VERSION 5.8 ;
BUSBITCHARS "[]" ;
DIVIDERCHAR "/" ;
UNITS
    DATABASE MICRONS 1000 ;
END UNITS

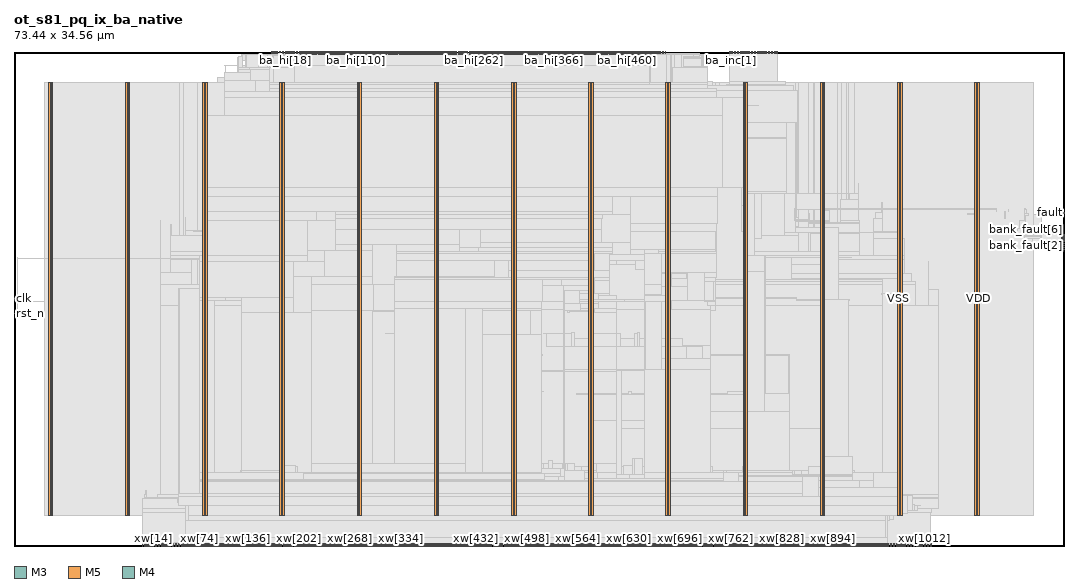
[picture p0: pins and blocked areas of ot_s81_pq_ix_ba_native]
MACRO ot_s81_pq_ix_ba_native
  FOREIGN ot_s81_pq_ix_ba_native 0 0 ;
  CLASS BLOCK ;
  SIZE 73.44 BY 34.56 ;
  PIN ba_hi[0]
    DIRECTION OUTPUT ;
    USE SIGNAL ;
    PORT
      LAYER M3 ;
        RECT  18 34.416 18.018 34.56 ;
    END
  END ba_hi[0]
  PIN ba_hi[100]
    DIRECTION OUTPUT ;
    USE SIGNAL ;
    PORT
      LAYER M3 ;
        RECT  23.4 34.416 23.418 34.56 ;
    END
  END ba_hi[100]
  PIN ba_hi[101]
    DIRECTION OUTPUT ;
    USE SIGNAL ;
    PORT
      LAYER M5 ;
        RECT  24.816 34.368 24.84 34.56 ;
    END
  END ba_hi[101]
  PIN ba_hi[102]
    DIRECTION OUTPUT ;
    USE SIGNAL ;
    PORT
      LAYER M3 ;
        RECT  23.508 34.416 23.526 34.56 ;
    END
  END ba_hi[102]
  PIN ba_hi[103]
    DIRECTION OUTPUT ;
    USE SIGNAL ;
    PORT
      LAYER M5 ;
        RECT  24.912 34.368 24.936 34.56 ;
    END
  END ba_hi[103]
  PIN ba_hi[104]
    DIRECTION OUTPUT ;
    USE SIGNAL ;
    PORT
      LAYER M3 ;
        RECT  23.616 34.416 23.634 34.56 ;
    END
  END ba_hi[104]
  PIN ba_hi[105]
    DIRECTION OUTPUT ;
    USE SIGNAL ;
    PORT
      LAYER M5 ;
        RECT  25.008 34.368 25.032 34.56 ;
    END
  END ba_hi[105]
  PIN ba_hi[106]
    DIRECTION OUTPUT ;
    USE SIGNAL ;
    PORT
      LAYER M3 ;
        RECT  23.724 34.416 23.742 34.56 ;
    END
  END ba_hi[106]
  PIN ba_hi[107]
    DIRECTION OUTPUT ;
    USE SIGNAL ;
    PORT
      LAYER M5 ;
        RECT  25.104 34.368 25.128 34.56 ;
    END
  END ba_hi[107]
  PIN ba_hi[108]
    DIRECTION OUTPUT ;
    USE SIGNAL ;
    PORT
      LAYER M3 ;
        RECT  23.832 34.416 23.85 34.56 ;
    END
  END ba_hi[108]
  PIN ba_hi[109]
    DIRECTION OUTPUT ;
    USE SIGNAL ;
    PORT
      LAYER M5 ;
        RECT  25.2 34.368 25.224 34.56 ;
    END
  END ba_hi[109]
  PIN ba_hi[10]
    DIRECTION OUTPUT ;
    USE SIGNAL ;
    PORT
      LAYER M3 ;
        RECT  18.54 34.416 18.558 34.56 ;
    END
  END ba_hi[10]
  PIN ba_hi[110]
    DIRECTION OUTPUT ;
    USE SIGNAL ;
    PORT
      LAYER M3 ;
        RECT  23.94 34.416 23.958 34.56 ;
    END
  END ba_hi[110]
  PIN ba_hi[111]
    DIRECTION OUTPUT ;
    USE SIGNAL ;
    PORT
      LAYER M5 ;
        RECT  25.296 34.368 25.32 34.56 ;
    END
  END ba_hi[111]
  PIN ba_hi[112]
    DIRECTION OUTPUT ;
    USE SIGNAL ;
    PORT
      LAYER M3 ;
        RECT  24.048 34.416 24.066 34.56 ;
    END
  END ba_hi[112]
  PIN ba_hi[113]
    DIRECTION OUTPUT ;
    USE SIGNAL ;
    PORT
      LAYER M5 ;
        RECT  25.392 34.368 25.416 34.56 ;
    END
  END ba_hi[113]
  PIN ba_hi[114]
    DIRECTION OUTPUT ;
    USE SIGNAL ;
    PORT
      LAYER M3 ;
        RECT  24.156 34.416 24.174 34.56 ;
    END
  END ba_hi[114]
  PIN ba_hi[115]
    DIRECTION OUTPUT ;
    USE SIGNAL ;
    PORT
      LAYER M5 ;
        RECT  25.488 34.368 25.512 34.56 ;
    END
  END ba_hi[115]
  PIN ba_hi[116]
    DIRECTION OUTPUT ;
    USE SIGNAL ;
    PORT
      LAYER M3 ;
        RECT  24.264 34.416 24.282 34.56 ;
    END
  END ba_hi[116]
  PIN ba_hi[117]
    DIRECTION OUTPUT ;
    USE SIGNAL ;
    PORT
      LAYER M5 ;
        RECT  25.584 34.368 25.608 34.56 ;
    END
  END ba_hi[117]
  PIN ba_hi[118]
    DIRECTION OUTPUT ;
    USE SIGNAL ;
    PORT
      LAYER M3 ;
        RECT  24.372 34.416 24.39 34.56 ;
    END
  END ba_hi[118]
  PIN ba_hi[119]
    DIRECTION OUTPUT ;
    USE SIGNAL ;
    PORT
      LAYER M5 ;
        RECT  25.68 34.368 25.704 34.56 ;
    END
  END ba_hi[119]
  PIN ba_hi[11]
    DIRECTION OUTPUT ;
    USE SIGNAL ;
    PORT
      LAYER M5 ;
        RECT  20.496 34.368 20.52 34.56 ;
    END
  END ba_hi[11]
  PIN ba_hi[120]
    DIRECTION OUTPUT ;
    USE SIGNAL ;
    PORT
      LAYER M3 ;
        RECT  24.48 34.416 24.498 34.56 ;
    END
  END ba_hi[120]
  PIN ba_hi[121]
    DIRECTION OUTPUT ;
    USE SIGNAL ;
    PORT
      LAYER M5 ;
        RECT  25.776 34.368 25.8 34.56 ;
    END
  END ba_hi[121]
  PIN ba_hi[122]
    DIRECTION OUTPUT ;
    USE SIGNAL ;
    PORT
      LAYER M3 ;
        RECT  24.588 34.416 24.606 34.56 ;
    END
  END ba_hi[122]
  PIN ba_hi[123]
    DIRECTION OUTPUT ;
    USE SIGNAL ;
    PORT
      LAYER M5 ;
        RECT  25.872 34.368 25.896 34.56 ;
    END
  END ba_hi[123]
  PIN ba_hi[124]
    DIRECTION OUTPUT ;
    USE SIGNAL ;
    PORT
      LAYER M3 ;
        RECT  24.696 34.416 24.714 34.56 ;
    END
  END ba_hi[124]
  PIN ba_hi[125]
    DIRECTION OUTPUT ;
    USE SIGNAL ;
    PORT
      LAYER M5 ;
        RECT  25.968 34.368 25.992 34.56 ;
    END
  END ba_hi[125]
  PIN ba_hi[126]
    DIRECTION OUTPUT ;
    USE SIGNAL ;
    PORT
      LAYER M3 ;
        RECT  24.804 34.416 24.822 34.56 ;
    END
  END ba_hi[126]
  PIN ba_hi[127]
    DIRECTION OUTPUT ;
    USE SIGNAL ;
    PORT
      LAYER M5 ;
        RECT  26.064 34.368 26.088 34.56 ;
    END
  END ba_hi[127]
  PIN ba_hi[128]
    DIRECTION OUTPUT ;
    USE SIGNAL ;
    PORT
      LAYER M3 ;
        RECT  24.912 34.416 24.93 34.56 ;
    END
  END ba_hi[128]
  PIN ba_hi[129]
    DIRECTION OUTPUT ;
    USE SIGNAL ;
    PORT
      LAYER M5 ;
        RECT  26.16 34.368 26.184 34.56 ;
    END
  END ba_hi[129]
  PIN ba_hi[12]
    DIRECTION OUTPUT ;
    USE SIGNAL ;
    PORT
      LAYER M3 ;
        RECT  18.648 34.416 18.666 34.56 ;
    END
  END ba_hi[12]
  PIN ba_hi[130]
    DIRECTION OUTPUT ;
    USE SIGNAL ;
    PORT
      LAYER M3 ;
        RECT  25.02 34.416 25.038 34.56 ;
    END
  END ba_hi[130]
  PIN ba_hi[131]
    DIRECTION OUTPUT ;
    USE SIGNAL ;
    PORT
      LAYER M5 ;
        RECT  26.256 34.368 26.28 34.56 ;
    END
  END ba_hi[131]
  PIN ba_hi[132]
    DIRECTION OUTPUT ;
    USE SIGNAL ;
    PORT
      LAYER M3 ;
        RECT  25.128 34.416 25.146 34.56 ;
    END
  END ba_hi[132]
  PIN ba_hi[133]
    DIRECTION OUTPUT ;
    USE SIGNAL ;
    PORT
      LAYER M5 ;
        RECT  26.352 34.368 26.376 34.56 ;
    END
  END ba_hi[133]
  PIN ba_hi[134]
    DIRECTION OUTPUT ;
    USE SIGNAL ;
    PORT
      LAYER M3 ;
        RECT  25.236 34.416 25.254 34.56 ;
    END
  END ba_hi[134]
  PIN ba_hi[135]
    DIRECTION OUTPUT ;
    USE SIGNAL ;
    PORT
      LAYER M5 ;
        RECT  26.448 34.368 26.472 34.56 ;
    END
  END ba_hi[135]
  PIN ba_hi[136]
    DIRECTION OUTPUT ;
    USE SIGNAL ;
    PORT
      LAYER M3 ;
        RECT  25.344 34.416 25.362 34.56 ;
    END
  END ba_hi[136]
  PIN ba_hi[137]
    DIRECTION OUTPUT ;
    USE SIGNAL ;
    PORT
      LAYER M5 ;
        RECT  26.544 34.368 26.568 34.56 ;
    END
  END ba_hi[137]
  PIN ba_hi[138]
    DIRECTION OUTPUT ;
    USE SIGNAL ;
    PORT
      LAYER M3 ;
        RECT  25.452 34.416 25.47 34.56 ;
    END
  END ba_hi[138]
  PIN ba_hi[139]
    DIRECTION OUTPUT ;
    USE SIGNAL ;
    PORT
      LAYER M5 ;
        RECT  26.64 34.368 26.664 34.56 ;
    END
  END ba_hi[139]
  PIN ba_hi[13]
    DIRECTION OUTPUT ;
    USE SIGNAL ;
    PORT
      LAYER M5 ;
        RECT  20.592 34.368 20.616 34.56 ;
    END
  END ba_hi[13]
  PIN ba_hi[140]
    DIRECTION OUTPUT ;
    USE SIGNAL ;
    PORT
      LAYER M3 ;
        RECT  25.56 34.416 25.578 34.56 ;
    END
  END ba_hi[140]
  PIN ba_hi[141]
    DIRECTION OUTPUT ;
    USE SIGNAL ;
    PORT
      LAYER M5 ;
        RECT  26.736 34.368 26.76 34.56 ;
    END
  END ba_hi[141]
  PIN ba_hi[142]
    DIRECTION OUTPUT ;
    USE SIGNAL ;
    PORT
      LAYER M3 ;
        RECT  25.668 34.416 25.686 34.56 ;
    END
  END ba_hi[142]
  PIN ba_hi[143]
    DIRECTION OUTPUT ;
    USE SIGNAL ;
    PORT
      LAYER M5 ;
        RECT  26.832 34.368 26.856 34.56 ;
    END
  END ba_hi[143]
  PIN ba_hi[144]
    DIRECTION OUTPUT ;
    USE SIGNAL ;
    PORT
      LAYER M3 ;
        RECT  25.776 34.416 25.794 34.56 ;
    END
  END ba_hi[144]
  PIN ba_hi[145]
    DIRECTION OUTPUT ;
    USE SIGNAL ;
    PORT
      LAYER M5 ;
        RECT  26.928 34.368 26.952 34.56 ;
    END
  END ba_hi[145]
  PIN ba_hi[146]
    DIRECTION OUTPUT ;
    USE SIGNAL ;
    PORT
      LAYER M3 ;
        RECT  25.884 34.416 25.902 34.56 ;
    END
  END ba_hi[146]
  PIN ba_hi[147]
    DIRECTION OUTPUT ;
    USE SIGNAL ;
    PORT
      LAYER M5 ;
        RECT  27.024 34.368 27.048 34.56 ;
    END
  END ba_hi[147]
  PIN ba_hi[148]
    DIRECTION OUTPUT ;
    USE SIGNAL ;
    PORT
      LAYER M3 ;
        RECT  25.992 34.416 26.01 34.56 ;
    END
  END ba_hi[148]
  PIN ba_hi[149]
    DIRECTION OUTPUT ;
    USE SIGNAL ;
    PORT
      LAYER M5 ;
        RECT  27.12 34.368 27.144 34.56 ;
    END
  END ba_hi[149]
  PIN ba_hi[14]
    DIRECTION OUTPUT ;
    USE SIGNAL ;
    PORT
      LAYER M3 ;
        RECT  18.756 34.416 18.774 34.56 ;
    END
  END ba_hi[14]
  PIN ba_hi[150]
    DIRECTION OUTPUT ;
    USE SIGNAL ;
    PORT
      LAYER M3 ;
        RECT  26.1 34.416 26.118 34.56 ;
    END
  END ba_hi[150]
  PIN ba_hi[151]
    DIRECTION OUTPUT ;
    USE SIGNAL ;
    PORT
      LAYER M5 ;
        RECT  27.216 34.368 27.24 34.56 ;
    END
  END ba_hi[151]
  PIN ba_hi[152]
    DIRECTION OUTPUT ;
    USE SIGNAL ;
    PORT
      LAYER M3 ;
        RECT  26.208 34.416 26.226 34.56 ;
    END
  END ba_hi[152]
  PIN ba_hi[153]
    DIRECTION OUTPUT ;
    USE SIGNAL ;
    PORT
      LAYER M5 ;
        RECT  27.312 34.368 27.336 34.56 ;
    END
  END ba_hi[153]
  PIN ba_hi[154]
    DIRECTION OUTPUT ;
    USE SIGNAL ;
    PORT
      LAYER M3 ;
        RECT  26.316 34.416 26.334 34.56 ;
    END
  END ba_hi[154]
  PIN ba_hi[155]
    DIRECTION OUTPUT ;
    USE SIGNAL ;
    PORT
      LAYER M5 ;
        RECT  27.408 34.368 27.432 34.56 ;
    END
  END ba_hi[155]
  PIN ba_hi[156]
    DIRECTION OUTPUT ;
    USE SIGNAL ;
    PORT
      LAYER M3 ;
        RECT  26.424 34.416 26.442 34.56 ;
    END
  END ba_hi[156]
  PIN ba_hi[157]
    DIRECTION OUTPUT ;
    USE SIGNAL ;
    PORT
      LAYER M5 ;
        RECT  27.504 34.368 27.528 34.56 ;
    END
  END ba_hi[157]
  PIN ba_hi[158]
    DIRECTION OUTPUT ;
    USE SIGNAL ;
    PORT
      LAYER M3 ;
        RECT  26.532 34.416 26.55 34.56 ;
    END
  END ba_hi[158]
  PIN ba_hi[159]
    DIRECTION OUTPUT ;
    USE SIGNAL ;
    PORT
      LAYER M5 ;
        RECT  27.6 34.368 27.624 34.56 ;
    END
  END ba_hi[159]
  PIN ba_hi[15]
    DIRECTION OUTPUT ;
    USE SIGNAL ;
    PORT
      LAYER M5 ;
        RECT  20.688 34.368 20.712 34.56 ;
    END
  END ba_hi[15]
  PIN ba_hi[160]
    DIRECTION OUTPUT ;
    USE SIGNAL ;
    PORT
      LAYER M3 ;
        RECT  26.64 34.416 26.658 34.56 ;
    END
  END ba_hi[160]
  PIN ba_hi[161]
    DIRECTION OUTPUT ;
    USE SIGNAL ;
    PORT
      LAYER M5 ;
        RECT  27.696 34.368 27.72 34.56 ;
    END
  END ba_hi[161]
  PIN ba_hi[162]
    DIRECTION OUTPUT ;
    USE SIGNAL ;
    PORT
      LAYER M3 ;
        RECT  26.748 34.416 26.766 34.56 ;
    END
  END ba_hi[162]
  PIN ba_hi[163]
    DIRECTION OUTPUT ;
    USE SIGNAL ;
    PORT
      LAYER M5 ;
        RECT  27.792 34.368 27.816 34.56 ;
    END
  END ba_hi[163]
  PIN ba_hi[164]
    DIRECTION OUTPUT ;
    USE SIGNAL ;
    PORT
      LAYER M3 ;
        RECT  26.856 34.416 26.874 34.56 ;
    END
  END ba_hi[164]
  PIN ba_hi[165]
    DIRECTION OUTPUT ;
    USE SIGNAL ;
    PORT
      LAYER M5 ;
        RECT  27.888 34.368 27.912 34.56 ;
    END
  END ba_hi[165]
  PIN ba_hi[166]
    DIRECTION OUTPUT ;
    USE SIGNAL ;
    PORT
      LAYER M3 ;
        RECT  26.964 34.416 26.982 34.56 ;
    END
  END ba_hi[166]
  PIN ba_hi[167]
    DIRECTION OUTPUT ;
    USE SIGNAL ;
    PORT
      LAYER M5 ;
        RECT  27.984 34.368 28.008 34.56 ;
    END
  END ba_hi[167]
  PIN ba_hi[168]
    DIRECTION OUTPUT ;
    USE SIGNAL ;
    PORT
      LAYER M3 ;
        RECT  27.072 34.416 27.09 34.56 ;
    END
  END ba_hi[168]
  PIN ba_hi[169]
    DIRECTION OUTPUT ;
    USE SIGNAL ;
    PORT
      LAYER M5 ;
        RECT  28.08 34.368 28.104 34.56 ;
    END
  END ba_hi[169]
  PIN ba_hi[16]
    DIRECTION OUTPUT ;
    USE SIGNAL ;
    PORT
      LAYER M3 ;
        RECT  18.864 34.416 18.882 34.56 ;
    END
  END ba_hi[16]
  PIN ba_hi[170]
    DIRECTION OUTPUT ;
    USE SIGNAL ;
    PORT
      LAYER M3 ;
        RECT  27.18 34.416 27.198 34.56 ;
    END
  END ba_hi[170]
  PIN ba_hi[171]
    DIRECTION OUTPUT ;
    USE SIGNAL ;
    PORT
      LAYER M5 ;
        RECT  28.176 34.368 28.2 34.56 ;
    END
  END ba_hi[171]
  PIN ba_hi[172]
    DIRECTION OUTPUT ;
    USE SIGNAL ;
    PORT
      LAYER M3 ;
        RECT  27.288 34.416 27.306 34.56 ;
    END
  END ba_hi[172]
  PIN ba_hi[173]
    DIRECTION OUTPUT ;
    USE SIGNAL ;
    PORT
      LAYER M5 ;
        RECT  28.272 34.368 28.296 34.56 ;
    END
  END ba_hi[173]
  PIN ba_hi[174]
    DIRECTION OUTPUT ;
    USE SIGNAL ;
    PORT
      LAYER M3 ;
        RECT  27.396 34.416 27.414 34.56 ;
    END
  END ba_hi[174]
  PIN ba_hi[175]
    DIRECTION OUTPUT ;
    USE SIGNAL ;
    PORT
      LAYER M5 ;
        RECT  28.368 34.368 28.392 34.56 ;
    END
  END ba_hi[175]
  PIN ba_hi[176]
    DIRECTION OUTPUT ;
    USE SIGNAL ;
    PORT
      LAYER M3 ;
        RECT  27.504 34.416 27.522 34.56 ;
    END
  END ba_hi[176]
  PIN ba_hi[177]
    DIRECTION OUTPUT ;
    USE SIGNAL ;
    PORT
      LAYER M5 ;
        RECT  28.464 34.368 28.488 34.56 ;
    END
  END ba_hi[177]
  PIN ba_hi[178]
    DIRECTION OUTPUT ;
    USE SIGNAL ;
    PORT
      LAYER M3 ;
        RECT  27.612 34.416 27.63 34.56 ;
    END
  END ba_hi[178]
  PIN ba_hi[179]
    DIRECTION OUTPUT ;
    USE SIGNAL ;
    PORT
      LAYER M5 ;
        RECT  28.56 34.368 28.584 34.56 ;
    END
  END ba_hi[179]
  PIN ba_hi[17]
    DIRECTION OUTPUT ;
    USE SIGNAL ;
    PORT
      LAYER M5 ;
        RECT  20.784 34.368 20.808 34.56 ;
    END
  END ba_hi[17]
  PIN ba_hi[180]
    DIRECTION OUTPUT ;
    USE SIGNAL ;
    PORT
      LAYER M3 ;
        RECT  27.72 34.416 27.738 34.56 ;
    END
  END ba_hi[180]
  PIN ba_hi[181]
    DIRECTION OUTPUT ;
    USE SIGNAL ;
    PORT
      LAYER M5 ;
        RECT  28.656 34.368 28.68 34.56 ;
    END
  END ba_hi[181]
  PIN ba_hi[182]
    DIRECTION OUTPUT ;
    USE SIGNAL ;
    PORT
      LAYER M3 ;
        RECT  27.828 34.416 27.846 34.56 ;
    END
  END ba_hi[182]
  PIN ba_hi[183]
    DIRECTION OUTPUT ;
    USE SIGNAL ;
    PORT
      LAYER M5 ;
        RECT  28.752 34.368 28.776 34.56 ;
    END
  END ba_hi[183]
  PIN ba_hi[184]
    DIRECTION OUTPUT ;
    USE SIGNAL ;
    PORT
      LAYER M3 ;
        RECT  27.936 34.416 27.954 34.56 ;
    END
  END ba_hi[184]
  PIN ba_hi[185]
    DIRECTION OUTPUT ;
    USE SIGNAL ;
    PORT
      LAYER M5 ;
        RECT  28.848 34.368 28.872 34.56 ;
    END
  END ba_hi[185]
  PIN ba_hi[186]
    DIRECTION OUTPUT ;
    USE SIGNAL ;
    PORT
      LAYER M3 ;
        RECT  28.044 34.416 28.062 34.56 ;
    END
  END ba_hi[186]
  PIN ba_hi[187]
    DIRECTION OUTPUT ;
    USE SIGNAL ;
    PORT
      LAYER M5 ;
        RECT  28.944 34.368 28.968 34.56 ;
    END
  END ba_hi[187]
  PIN ba_hi[188]
    DIRECTION OUTPUT ;
    USE SIGNAL ;
    PORT
      LAYER M3 ;
        RECT  28.152 34.416 28.17 34.56 ;
    END
  END ba_hi[188]
  PIN ba_hi[189]
    DIRECTION OUTPUT ;
    USE SIGNAL ;
    PORT
      LAYER M5 ;
        RECT  29.04 34.368 29.064 34.56 ;
    END
  END ba_hi[189]
  PIN ba_hi[18]
    DIRECTION OUTPUT ;
    USE SIGNAL ;
    PORT
      LAYER M3 ;
        RECT  18.972 34.416 18.99 34.56 ;
    END
  END ba_hi[18]
  PIN ba_hi[190]
    DIRECTION OUTPUT ;
    USE SIGNAL ;
    PORT
      LAYER M3 ;
        RECT  28.26 34.416 28.278 34.56 ;
    END
  END ba_hi[190]
  PIN ba_hi[191]
    DIRECTION OUTPUT ;
    USE SIGNAL ;
    PORT
      LAYER M5 ;
        RECT  29.136 34.368 29.16 34.56 ;
    END
  END ba_hi[191]
  PIN ba_hi[192]
    DIRECTION OUTPUT ;
    USE SIGNAL ;
    PORT
      LAYER M3 ;
        RECT  28.368 34.416 28.386 34.56 ;
    END
  END ba_hi[192]
  PIN ba_hi[193]
    DIRECTION OUTPUT ;
    USE SIGNAL ;
    PORT
      LAYER M5 ;
        RECT  29.232 34.368 29.256 34.56 ;
    END
  END ba_hi[193]
  PIN ba_hi[194]
    DIRECTION OUTPUT ;
    USE SIGNAL ;
    PORT
      LAYER M3 ;
        RECT  28.476 34.416 28.494 34.56 ;
    END
  END ba_hi[194]
  PIN ba_hi[195]
    DIRECTION OUTPUT ;
    USE SIGNAL ;
    PORT
      LAYER M5 ;
        RECT  29.328 34.368 29.352 34.56 ;
    END
  END ba_hi[195]
  PIN ba_hi[196]
    DIRECTION OUTPUT ;
    USE SIGNAL ;
    PORT
      LAYER M3 ;
        RECT  28.584 34.416 28.602 34.56 ;
    END
  END ba_hi[196]
  PIN ba_hi[197]
    DIRECTION OUTPUT ;
    USE SIGNAL ;
    PORT
      LAYER M5 ;
        RECT  29.424 34.368 29.448 34.56 ;
    END
  END ba_hi[197]
  PIN ba_hi[198]
    DIRECTION OUTPUT ;
    USE SIGNAL ;
    PORT
      LAYER M3 ;
        RECT  28.692 34.416 28.71 34.56 ;
    END
  END ba_hi[198]
  PIN ba_hi[199]
    DIRECTION OUTPUT ;
    USE SIGNAL ;
    PORT
      LAYER M5 ;
        RECT  29.52 34.368 29.544 34.56 ;
    END
  END ba_hi[199]
  PIN ba_hi[19]
    DIRECTION OUTPUT ;
    USE SIGNAL ;
    PORT
      LAYER M5 ;
        RECT  20.88 34.368 20.904 34.56 ;
    END
  END ba_hi[19]
  PIN ba_hi[1]
    DIRECTION OUTPUT ;
    USE SIGNAL ;
    PORT
      LAYER M5 ;
        RECT  20.016 34.368 20.04 34.56 ;
    END
  END ba_hi[1]
  PIN ba_hi[200]
    DIRECTION OUTPUT ;
    USE SIGNAL ;
    PORT
      LAYER M3 ;
        RECT  28.8 34.416 28.818 34.56 ;
    END
  END ba_hi[200]
  PIN ba_hi[201]
    DIRECTION OUTPUT ;
    USE SIGNAL ;
    PORT
      LAYER M5 ;
        RECT  29.616 34.368 29.64 34.56 ;
    END
  END ba_hi[201]
  PIN ba_hi[202]
    DIRECTION OUTPUT ;
    USE SIGNAL ;
    PORT
      LAYER M3 ;
        RECT  28.908 34.416 28.926 34.56 ;
    END
  END ba_hi[202]
  PIN ba_hi[203]
    DIRECTION OUTPUT ;
    USE SIGNAL ;
    PORT
      LAYER M5 ;
        RECT  29.712 34.368 29.736 34.56 ;
    END
  END ba_hi[203]
  PIN ba_hi[204]
    DIRECTION OUTPUT ;
    USE SIGNAL ;
    PORT
      LAYER M3 ;
        RECT  29.016 34.416 29.034 34.56 ;
    END
  END ba_hi[204]
  PIN ba_hi[205]
    DIRECTION OUTPUT ;
    USE SIGNAL ;
    PORT
      LAYER M5 ;
        RECT  29.808 34.368 29.832 34.56 ;
    END
  END ba_hi[205]
  PIN ba_hi[206]
    DIRECTION OUTPUT ;
    USE SIGNAL ;
    PORT
      LAYER M3 ;
        RECT  29.124 34.416 29.142 34.56 ;
    END
  END ba_hi[206]
  PIN ba_hi[207]
    DIRECTION OUTPUT ;
    USE SIGNAL ;
    PORT
      LAYER M5 ;
        RECT  29.904 34.368 29.928 34.56 ;
    END
  END ba_hi[207]
  PIN ba_hi[208]
    DIRECTION OUTPUT ;
    USE SIGNAL ;
    PORT
      LAYER M3 ;
        RECT  29.232 34.416 29.25 34.56 ;
    END
  END ba_hi[208]
  PIN ba_hi[209]
    DIRECTION OUTPUT ;
    USE SIGNAL ;
    PORT
      LAYER M5 ;
        RECT  30 34.368 30.024 34.56 ;
    END
  END ba_hi[209]
  PIN ba_hi[20]
    DIRECTION OUTPUT ;
    USE SIGNAL ;
    PORT
      LAYER M3 ;
        RECT  19.08 34.416 19.098 34.56 ;
    END
  END ba_hi[20]
  PIN ba_hi[210]
    DIRECTION OUTPUT ;
    USE SIGNAL ;
    PORT
      LAYER M3 ;
        RECT  29.34 34.416 29.358 34.56 ;
    END
  END ba_hi[210]
  PIN ba_hi[211]
    DIRECTION OUTPUT ;
    USE SIGNAL ;
    PORT
      LAYER M5 ;
        RECT  30.096 34.368 30.12 34.56 ;
    END
  END ba_hi[211]
  PIN ba_hi[212]
    DIRECTION OUTPUT ;
    USE SIGNAL ;
    PORT
      LAYER M3 ;
        RECT  29.448 34.416 29.466 34.56 ;
    END
  END ba_hi[212]
  PIN ba_hi[213]
    DIRECTION OUTPUT ;
    USE SIGNAL ;
    PORT
      LAYER M5 ;
        RECT  30.192 34.368 30.216 34.56 ;
    END
  END ba_hi[213]
  PIN ba_hi[214]
    DIRECTION OUTPUT ;
    USE SIGNAL ;
    PORT
      LAYER M3 ;
        RECT  29.556 34.416 29.574 34.56 ;
    END
  END ba_hi[214]
  PIN ba_hi[215]
    DIRECTION OUTPUT ;
    USE SIGNAL ;
    PORT
      LAYER M5 ;
        RECT  30.288 34.368 30.312 34.56 ;
    END
  END ba_hi[215]
  PIN ba_hi[216]
    DIRECTION OUTPUT ;
    USE SIGNAL ;
    PORT
      LAYER M3 ;
        RECT  29.664 34.416 29.682 34.56 ;
    END
  END ba_hi[216]
  PIN ba_hi[217]
    DIRECTION OUTPUT ;
    USE SIGNAL ;
    PORT
      LAYER M5 ;
        RECT  30.384 34.368 30.408 34.56 ;
    END
  END ba_hi[217]
  PIN ba_hi[218]
    DIRECTION OUTPUT ;
    USE SIGNAL ;
    PORT
      LAYER M3 ;
        RECT  29.772 34.416 29.79 34.56 ;
    END
  END ba_hi[218]
  PIN ba_hi[219]
    DIRECTION OUTPUT ;
    USE SIGNAL ;
    PORT
      LAYER M5 ;
        RECT  30.48 34.368 30.504 34.56 ;
    END
  END ba_hi[219]
  PIN ba_hi[21]
    DIRECTION OUTPUT ;
    USE SIGNAL ;
    PORT
      LAYER M5 ;
        RECT  20.976 34.368 21 34.56 ;
    END
  END ba_hi[21]
  PIN ba_hi[220]
    DIRECTION OUTPUT ;
    USE SIGNAL ;
    PORT
      LAYER M3 ;
        RECT  29.88 34.416 29.898 34.56 ;
    END
  END ba_hi[220]
  PIN ba_hi[221]
    DIRECTION OUTPUT ;
    USE SIGNAL ;
    PORT
      LAYER M5 ;
        RECT  30.576 34.368 30.6 34.56 ;
    END
  END ba_hi[221]
  PIN ba_hi[222]
    DIRECTION OUTPUT ;
    USE SIGNAL ;
    PORT
      LAYER M3 ;
        RECT  29.988 34.416 30.006 34.56 ;
    END
  END ba_hi[222]
  PIN ba_hi[223]
    DIRECTION OUTPUT ;
    USE SIGNAL ;
    PORT
      LAYER M5 ;
        RECT  30.672 34.368 30.696 34.56 ;
    END
  END ba_hi[223]
  PIN ba_hi[224]
    DIRECTION OUTPUT ;
    USE SIGNAL ;
    PORT
      LAYER M3 ;
        RECT  30.096 34.416 30.114 34.56 ;
    END
  END ba_hi[224]
  PIN ba_hi[225]
    DIRECTION OUTPUT ;
    USE SIGNAL ;
    PORT
      LAYER M5 ;
        RECT  30.768 34.368 30.792 34.56 ;
    END
  END ba_hi[225]
  PIN ba_hi[226]
    DIRECTION OUTPUT ;
    USE SIGNAL ;
    PORT
      LAYER M3 ;
        RECT  30.204 34.416 30.222 34.56 ;
    END
  END ba_hi[226]
  PIN ba_hi[227]
    DIRECTION OUTPUT ;
    USE SIGNAL ;
    PORT
      LAYER M5 ;
        RECT  30.864 34.368 30.888 34.56 ;
    END
  END ba_hi[227]
  PIN ba_hi[228]
    DIRECTION OUTPUT ;
    USE SIGNAL ;
    PORT
      LAYER M3 ;
        RECT  30.312 34.416 30.33 34.56 ;
    END
  END ba_hi[228]
  PIN ba_hi[229]
    DIRECTION OUTPUT ;
    USE SIGNAL ;
    PORT
      LAYER M5 ;
        RECT  30.96 34.368 30.984 34.56 ;
    END
  END ba_hi[229]
  PIN ba_hi[22]
    DIRECTION OUTPUT ;
    USE SIGNAL ;
    PORT
      LAYER M3 ;
        RECT  19.188 34.416 19.206 34.56 ;
    END
  END ba_hi[22]
  PIN ba_hi[230]
    DIRECTION OUTPUT ;
    USE SIGNAL ;
    PORT
      LAYER M3 ;
        RECT  30.42 34.416 30.438 34.56 ;
    END
  END ba_hi[230]
  PIN ba_hi[231]
    DIRECTION OUTPUT ;
    USE SIGNAL ;
    PORT
      LAYER M5 ;
        RECT  31.056 34.368 31.08 34.56 ;
    END
  END ba_hi[231]
  PIN ba_hi[232]
    DIRECTION OUTPUT ;
    USE SIGNAL ;
    PORT
      LAYER M3 ;
        RECT  30.528 34.416 30.546 34.56 ;
    END
  END ba_hi[232]
  PIN ba_hi[233]
    DIRECTION OUTPUT ;
    USE SIGNAL ;
    PORT
      LAYER M5 ;
        RECT  31.152 34.368 31.176 34.56 ;
    END
  END ba_hi[233]
  PIN ba_hi[234]
    DIRECTION OUTPUT ;
    USE SIGNAL ;
    PORT
      LAYER M3 ;
        RECT  30.636 34.416 30.654 34.56 ;
    END
  END ba_hi[234]
  PIN ba_hi[235]
    DIRECTION OUTPUT ;
    USE SIGNAL ;
    PORT
      LAYER M5 ;
        RECT  31.248 34.368 31.272 34.56 ;
    END
  END ba_hi[235]
  PIN ba_hi[236]
    DIRECTION OUTPUT ;
    USE SIGNAL ;
    PORT
      LAYER M3 ;
        RECT  30.744 34.416 30.762 34.56 ;
    END
  END ba_hi[236]
  PIN ba_hi[237]
    DIRECTION OUTPUT ;
    USE SIGNAL ;
    PORT
      LAYER M5 ;
        RECT  31.344 34.368 31.368 34.56 ;
    END
  END ba_hi[237]
  PIN ba_hi[238]
    DIRECTION OUTPUT ;
    USE SIGNAL ;
    PORT
      LAYER M3 ;
        RECT  30.852 34.416 30.87 34.56 ;
    END
  END ba_hi[238]
  PIN ba_hi[239]
    DIRECTION OUTPUT ;
    USE SIGNAL ;
    PORT
      LAYER M5 ;
        RECT  31.44 34.368 31.464 34.56 ;
    END
  END ba_hi[239]
  PIN ba_hi[23]
    DIRECTION OUTPUT ;
    USE SIGNAL ;
    PORT
      LAYER M5 ;
        RECT  21.072 34.368 21.096 34.56 ;
    END
  END ba_hi[23]
  PIN ba_hi[240]
    DIRECTION OUTPUT ;
    USE SIGNAL ;
    PORT
      LAYER M3 ;
        RECT  30.96 34.416 30.978 34.56 ;
    END
  END ba_hi[240]
  PIN ba_hi[241]
    DIRECTION OUTPUT ;
    USE SIGNAL ;
    PORT
      LAYER M5 ;
        RECT  31.536 34.368 31.56 34.56 ;
    END
  END ba_hi[241]
  PIN ba_hi[242]
    DIRECTION OUTPUT ;
    USE SIGNAL ;
    PORT
      LAYER M3 ;
        RECT  31.068 34.416 31.086 34.56 ;
    END
  END ba_hi[242]
  PIN ba_hi[243]
    DIRECTION OUTPUT ;
    USE SIGNAL ;
    PORT
      LAYER M5 ;
        RECT  31.632 34.368 31.656 34.56 ;
    END
  END ba_hi[243]
  PIN ba_hi[244]
    DIRECTION OUTPUT ;
    USE SIGNAL ;
    PORT
      LAYER M3 ;
        RECT  31.176 34.416 31.194 34.56 ;
    END
  END ba_hi[244]
  PIN ba_hi[245]
    DIRECTION OUTPUT ;
    USE SIGNAL ;
    PORT
      LAYER M5 ;
        RECT  31.728 34.368 31.752 34.56 ;
    END
  END ba_hi[245]
  PIN ba_hi[246]
    DIRECTION OUTPUT ;
    USE SIGNAL ;
    PORT
      LAYER M3 ;
        RECT  31.284 34.416 31.302 34.56 ;
    END
  END ba_hi[246]
  PIN ba_hi[247]
    DIRECTION OUTPUT ;
    USE SIGNAL ;
    PORT
      LAYER M5 ;
        RECT  31.824 34.368 31.848 34.56 ;
    END
  END ba_hi[247]
  PIN ba_hi[248]
    DIRECTION OUTPUT ;
    USE SIGNAL ;
    PORT
      LAYER M3 ;
        RECT  31.392 34.416 31.41 34.56 ;
    END
  END ba_hi[248]
  PIN ba_hi[249]
    DIRECTION OUTPUT ;
    USE SIGNAL ;
    PORT
      LAYER M5 ;
        RECT  31.92 34.368 31.944 34.56 ;
    END
  END ba_hi[249]
  PIN ba_hi[24]
    DIRECTION OUTPUT ;
    USE SIGNAL ;
    PORT
      LAYER M3 ;
        RECT  19.296 34.416 19.314 34.56 ;
    END
  END ba_hi[24]
  PIN ba_hi[250]
    DIRECTION OUTPUT ;
    USE SIGNAL ;
    PORT
      LAYER M3 ;
        RECT  31.5 34.416 31.518 34.56 ;
    END
  END ba_hi[250]
  PIN ba_hi[251]
    DIRECTION OUTPUT ;
    USE SIGNAL ;
    PORT
      LAYER M5 ;
        RECT  32.016 34.368 32.04 34.56 ;
    END
  END ba_hi[251]
  PIN ba_hi[252]
    DIRECTION OUTPUT ;
    USE SIGNAL ;
    PORT
      LAYER M3 ;
        RECT  31.608 34.416 31.626 34.56 ;
    END
    PORT
      LAYER M3 ;
        RECT  31.572 34.428 31.698 34.493 ;
    END
  END ba_hi[252]
  PIN ba_hi[253]
    DIRECTION OUTPUT ;
    USE SIGNAL ;
    PORT
      LAYER M5 ;
        RECT  32.112 34.368 32.136 34.56 ;
    END
  END ba_hi[253]
  PIN ba_hi[254]
    DIRECTION OUTPUT ;
    USE SIGNAL ;
    PORT
      LAYER M3 ;
        RECT  31.716 34.416 31.734 34.56 ;
    END
  END ba_hi[254]
  PIN ba_hi[255]
    DIRECTION OUTPUT ;
    USE SIGNAL ;
    PORT
      LAYER M5 ;
        RECT  32.208 34.368 32.232 34.56 ;
    END
  END ba_hi[255]
  PIN ba_hi[256]
    DIRECTION OUTPUT ;
    USE SIGNAL ;
    PORT
      LAYER M3 ;
        RECT  31.824 34.416 31.842 34.56 ;
    END
  END ba_hi[256]
  PIN ba_hi[257]
    DIRECTION OUTPUT ;
    USE SIGNAL ;
    PORT
      LAYER M5 ;
        RECT  32.304 34.368 32.328 34.56 ;
    END
  END ba_hi[257]
  PIN ba_hi[258]
    DIRECTION OUTPUT ;
    USE SIGNAL ;
    PORT
      LAYER M3 ;
        RECT  31.932 34.416 31.95 34.56 ;
    END
  END ba_hi[258]
  PIN ba_hi[259]
    DIRECTION OUTPUT ;
    USE SIGNAL ;
    PORT
      LAYER M5 ;
        RECT  32.4 34.368 32.424 34.56 ;
    END
  END ba_hi[259]
  PIN ba_hi[25]
    DIRECTION OUTPUT ;
    USE SIGNAL ;
    PORT
      LAYER M5 ;
        RECT  21.168 34.368 21.192 34.56 ;
    END
  END ba_hi[25]
  PIN ba_hi[260]
    DIRECTION OUTPUT ;
    USE SIGNAL ;
    PORT
      LAYER M3 ;
        RECT  32.04 34.416 32.058 34.56 ;
    END
  END ba_hi[260]
  PIN ba_hi[261]
    DIRECTION OUTPUT ;
    USE SIGNAL ;
    PORT
      LAYER M5 ;
        RECT  32.496 34.368 32.52 34.56 ;
    END
  END ba_hi[261]
  PIN ba_hi[262]
    DIRECTION OUTPUT ;
    USE SIGNAL ;
    PORT
      LAYER M3 ;
        RECT  32.148 34.416 32.166 34.56 ;
    END
  END ba_hi[262]
  PIN ba_hi[263]
    DIRECTION OUTPUT ;
    USE SIGNAL ;
    PORT
      LAYER M5 ;
        RECT  32.592 34.368 32.616 34.56 ;
    END
  END ba_hi[263]
  PIN ba_hi[264]
    DIRECTION OUTPUT ;
    USE SIGNAL ;
    PORT
      LAYER M3 ;
        RECT  32.256 34.416 32.274 34.56 ;
    END
  END ba_hi[264]
  PIN ba_hi[265]
    DIRECTION OUTPUT ;
    USE SIGNAL ;
    PORT
      LAYER M5 ;
        RECT  32.688 34.368 32.712 34.56 ;
    END
  END ba_hi[265]
  PIN ba_hi[266]
    DIRECTION OUTPUT ;
    USE SIGNAL ;
    PORT
      LAYER M3 ;
        RECT  32.364 34.416 32.382 34.56 ;
    END
  END ba_hi[266]
  PIN ba_hi[267]
    DIRECTION OUTPUT ;
    USE SIGNAL ;
    PORT
      LAYER M5 ;
        RECT  32.784 34.368 32.808 34.56 ;
    END
  END ba_hi[267]
  PIN ba_hi[268]
    DIRECTION OUTPUT ;
    USE SIGNAL ;
    PORT
      LAYER M3 ;
        RECT  32.472 34.416 32.49 34.56 ;
    END
  END ba_hi[268]
  PIN ba_hi[269]
    DIRECTION OUTPUT ;
    USE SIGNAL ;
    PORT
      LAYER M5 ;
        RECT  32.88 34.368 32.904 34.56 ;
    END
  END ba_hi[269]
  PIN ba_hi[26]
    DIRECTION OUTPUT ;
    USE SIGNAL ;
    PORT
      LAYER M3 ;
        RECT  19.404 34.416 19.422 34.56 ;
    END
  END ba_hi[26]
  PIN ba_hi[270]
    DIRECTION OUTPUT ;
    USE SIGNAL ;
    PORT
      LAYER M3 ;
        RECT  32.58 34.416 32.598 34.56 ;
    END
  END ba_hi[270]
  PIN ba_hi[271]
    DIRECTION OUTPUT ;
    USE SIGNAL ;
    PORT
      LAYER M5 ;
        RECT  32.976 34.368 33 34.56 ;
    END
  END ba_hi[271]
  PIN ba_hi[272]
    DIRECTION OUTPUT ;
    USE SIGNAL ;
    PORT
      LAYER M3 ;
        RECT  32.688 34.416 32.706 34.56 ;
    END
  END ba_hi[272]
  PIN ba_hi[273]
    DIRECTION OUTPUT ;
    USE SIGNAL ;
    PORT
      LAYER M5 ;
        RECT  33.072 34.368 33.096 34.56 ;
    END
  END ba_hi[273]
  PIN ba_hi[274]
    DIRECTION OUTPUT ;
    USE SIGNAL ;
    PORT
      LAYER M3 ;
        RECT  32.796 34.416 32.814 34.56 ;
    END
  END ba_hi[274]
  PIN ba_hi[275]
    DIRECTION OUTPUT ;
    USE SIGNAL ;
    PORT
      LAYER M5 ;
        RECT  33.168 34.368 33.192 34.56 ;
    END
  END ba_hi[275]
  PIN ba_hi[276]
    DIRECTION OUTPUT ;
    USE SIGNAL ;
    PORT
      LAYER M3 ;
        RECT  32.904 34.416 32.922 34.56 ;
    END
  END ba_hi[276]
  PIN ba_hi[277]
    DIRECTION OUTPUT ;
    USE SIGNAL ;
    PORT
      LAYER M5 ;
        RECT  33.264 34.368 33.288 34.56 ;
    END
  END ba_hi[277]
  PIN ba_hi[278]
    DIRECTION OUTPUT ;
    USE SIGNAL ;
    PORT
      LAYER M3 ;
        RECT  33.012 34.416 33.03 34.56 ;
    END
  END ba_hi[278]
  PIN ba_hi[279]
    DIRECTION OUTPUT ;
    USE SIGNAL ;
    PORT
      LAYER M5 ;
        RECT  33.36 34.368 33.384 34.56 ;
    END
  END ba_hi[279]
  PIN ba_hi[27]
    DIRECTION OUTPUT ;
    USE SIGNAL ;
    PORT
      LAYER M5 ;
        RECT  21.264 34.368 21.288 34.56 ;
    END
  END ba_hi[27]
  PIN ba_hi[280]
    DIRECTION OUTPUT ;
    USE SIGNAL ;
    PORT
      LAYER M3 ;
        RECT  33.12 34.416 33.138 34.56 ;
    END
  END ba_hi[280]
  PIN ba_hi[281]
    DIRECTION OUTPUT ;
    USE SIGNAL ;
    PORT
      LAYER M5 ;
        RECT  33.456 34.368 33.48 34.56 ;
    END
  END ba_hi[281]
  PIN ba_hi[282]
    DIRECTION OUTPUT ;
    USE SIGNAL ;
    PORT
      LAYER M3 ;
        RECT  33.228 34.416 33.246 34.56 ;
    END
  END ba_hi[282]
  PIN ba_hi[283]
    DIRECTION OUTPUT ;
    USE SIGNAL ;
    PORT
      LAYER M5 ;
        RECT  33.552 34.368 33.576 34.56 ;
    END
  END ba_hi[283]
  PIN ba_hi[284]
    DIRECTION OUTPUT ;
    USE SIGNAL ;
    PORT
      LAYER M3 ;
        RECT  33.336 34.416 33.354 34.56 ;
    END
  END ba_hi[284]
  PIN ba_hi[285]
    DIRECTION OUTPUT ;
    USE SIGNAL ;
    PORT
      LAYER M5 ;
        RECT  33.648 34.368 33.672 34.56 ;
    END
  END ba_hi[285]
  PIN ba_hi[286]
    DIRECTION OUTPUT ;
    USE SIGNAL ;
    PORT
      LAYER M3 ;
        RECT  33.444 34.416 33.462 34.56 ;
    END
  END ba_hi[286]
  PIN ba_hi[287]
    DIRECTION OUTPUT ;
    USE SIGNAL ;
    PORT
      LAYER M5 ;
        RECT  33.744 34.368 33.768 34.56 ;
    END
  END ba_hi[287]
  PIN ba_hi[288]
    DIRECTION OUTPUT ;
    USE SIGNAL ;
    PORT
      LAYER M3 ;
        RECT  33.552 34.416 33.57 34.56 ;
    END
  END ba_hi[288]
  PIN ba_hi[289]
    DIRECTION OUTPUT ;
    USE SIGNAL ;
    PORT
      LAYER M5 ;
        RECT  33.84 34.368 33.864 34.56 ;
    END
  END ba_hi[289]
  PIN ba_hi[28]
    DIRECTION OUTPUT ;
    USE SIGNAL ;
    PORT
      LAYER M3 ;
        RECT  19.512 34.416 19.53 34.56 ;
    END
  END ba_hi[28]
  PIN ba_hi[290]
    DIRECTION OUTPUT ;
    USE SIGNAL ;
    PORT
      LAYER M3 ;
        RECT  33.66 34.416 33.678 34.56 ;
    END
  END ba_hi[290]
  PIN ba_hi[291]
    DIRECTION OUTPUT ;
    USE SIGNAL ;
    PORT
      LAYER M5 ;
        RECT  33.936 34.368 33.96 34.56 ;
    END
  END ba_hi[291]
  PIN ba_hi[292]
    DIRECTION OUTPUT ;
    USE SIGNAL ;
    PORT
      LAYER M3 ;
        RECT  33.768 34.416 33.786 34.56 ;
    END
  END ba_hi[292]
  PIN ba_hi[293]
    DIRECTION OUTPUT ;
    USE SIGNAL ;
    PORT
      LAYER M5 ;
        RECT  34.032 34.368 34.056 34.56 ;
    END
  END ba_hi[293]
  PIN ba_hi[294]
    DIRECTION OUTPUT ;
    USE SIGNAL ;
    PORT
      LAYER M3 ;
        RECT  33.876 34.416 33.894 34.56 ;
    END
  END ba_hi[294]
  PIN ba_hi[295]
    DIRECTION OUTPUT ;
    USE SIGNAL ;
    PORT
      LAYER M5 ;
        RECT  34.128 34.368 34.152 34.56 ;
    END
  END ba_hi[295]
  PIN ba_hi[296]
    DIRECTION OUTPUT ;
    USE SIGNAL ;
    PORT
      LAYER M3 ;
        RECT  33.984 34.416 34.002 34.56 ;
    END
  END ba_hi[296]
  PIN ba_hi[297]
    DIRECTION OUTPUT ;
    USE SIGNAL ;
    PORT
      LAYER M5 ;
        RECT  34.224 34.368 34.248 34.56 ;
    END
  END ba_hi[297]
  PIN ba_hi[298]
    DIRECTION OUTPUT ;
    USE SIGNAL ;
    PORT
      LAYER M3 ;
        RECT  34.092 34.416 34.11 34.56 ;
    END
  END ba_hi[298]
  PIN ba_hi[299]
    DIRECTION OUTPUT ;
    USE SIGNAL ;
    PORT
      LAYER M5 ;
        RECT  34.32 34.368 34.344 34.56 ;
    END
  END ba_hi[299]
  PIN ba_hi[29]
    DIRECTION OUTPUT ;
    USE SIGNAL ;
    PORT
      LAYER M5 ;
        RECT  21.36 34.368 21.384 34.56 ;
    END
  END ba_hi[29]
  PIN ba_hi[2]
    DIRECTION OUTPUT ;
    USE SIGNAL ;
    PORT
      LAYER M3 ;
        RECT  18.108 34.416 18.126 34.56 ;
    END
  END ba_hi[2]
  PIN ba_hi[300]
    DIRECTION OUTPUT ;
    USE SIGNAL ;
    PORT
      LAYER M3 ;
        RECT  34.2 34.416 34.218 34.56 ;
    END
  END ba_hi[300]
  PIN ba_hi[301]
    DIRECTION OUTPUT ;
    USE SIGNAL ;
    PORT
      LAYER M5 ;
        RECT  34.416 34.368 34.44 34.56 ;
    END
  END ba_hi[301]
  PIN ba_hi[302]
    DIRECTION OUTPUT ;
    USE SIGNAL ;
    PORT
      LAYER M3 ;
        RECT  34.308 34.416 34.326 34.56 ;
    END
  END ba_hi[302]
  PIN ba_hi[303]
    DIRECTION OUTPUT ;
    USE SIGNAL ;
    PORT
      LAYER M5 ;
        RECT  34.512 34.368 34.536 34.56 ;
    END
  END ba_hi[303]
  PIN ba_hi[304]
    DIRECTION OUTPUT ;
    USE SIGNAL ;
    PORT
      LAYER M3 ;
        RECT  34.416 34.416 34.434 34.56 ;
    END
  END ba_hi[304]
  PIN ba_hi[305]
    DIRECTION OUTPUT ;
    USE SIGNAL ;
    PORT
      LAYER M5 ;
        RECT  34.608 34.368 34.632 34.56 ;
    END
  END ba_hi[305]
  PIN ba_hi[306]
    DIRECTION OUTPUT ;
    USE SIGNAL ;
    PORT
      LAYER M3 ;
        RECT  34.524 34.416 34.542 34.56 ;
    END
  END ba_hi[306]
  PIN ba_hi[307]
    DIRECTION OUTPUT ;
    USE SIGNAL ;
    PORT
      LAYER M5 ;
        RECT  34.704 34.368 34.728 34.56 ;
    END
  END ba_hi[307]
  PIN ba_hi[308]
    DIRECTION OUTPUT ;
    USE SIGNAL ;
    PORT
      LAYER M3 ;
        RECT  34.632 34.416 34.65 34.56 ;
    END
  END ba_hi[308]
  PIN ba_hi[309]
    DIRECTION OUTPUT ;
    USE SIGNAL ;
    PORT
      LAYER M5 ;
        RECT  34.8 34.368 34.824 34.56 ;
    END
  END ba_hi[309]
  PIN ba_hi[30]
    DIRECTION OUTPUT ;
    USE SIGNAL ;
    PORT
      LAYER M3 ;
        RECT  19.62 34.416 19.638 34.56 ;
    END
  END ba_hi[30]
  PIN ba_hi[310]
    DIRECTION OUTPUT ;
    USE SIGNAL ;
    PORT
      LAYER M3 ;
        RECT  34.74 34.416 34.758 34.56 ;
    END
  END ba_hi[310]
  PIN ba_hi[311]
    DIRECTION OUTPUT ;
    USE SIGNAL ;
    PORT
      LAYER M5 ;
        RECT  34.896 34.368 34.92 34.56 ;
    END
  END ba_hi[311]
  PIN ba_hi[312]
    DIRECTION OUTPUT ;
    USE SIGNAL ;
    PORT
      LAYER M3 ;
        RECT  34.848 34.416 34.866 34.56 ;
    END
  END ba_hi[312]
  PIN ba_hi[313]
    DIRECTION OUTPUT ;
    USE SIGNAL ;
    PORT
      LAYER M5 ;
        RECT  34.992 34.368 35.016 34.56 ;
    END
  END ba_hi[313]
  PIN ba_hi[314]
    DIRECTION OUTPUT ;
    USE SIGNAL ;
    PORT
      LAYER M3 ;
        RECT  34.956 34.416 34.974 34.56 ;
    END
  END ba_hi[314]
  PIN ba_hi[315]
    DIRECTION OUTPUT ;
    USE SIGNAL ;
    PORT
      LAYER M5 ;
        RECT  35.088 34.368 35.112 34.56 ;
    END
  END ba_hi[315]
  PIN ba_hi[316]
    DIRECTION OUTPUT ;
    USE SIGNAL ;
    PORT
      LAYER M3 ;
        RECT  35.064 34.416 35.082 34.56 ;
    END
  END ba_hi[316]
  PIN ba_hi[317]
    DIRECTION OUTPUT ;
    USE SIGNAL ;
    PORT
      LAYER M5 ;
        RECT  35.184 34.368 35.208 34.56 ;
    END
  END ba_hi[317]
  PIN ba_hi[318]
    DIRECTION OUTPUT ;
    USE SIGNAL ;
    PORT
      LAYER M3 ;
        RECT  35.172 34.416 35.19 34.56 ;
    END
  END ba_hi[318]
  PIN ba_hi[319]
    DIRECTION OUTPUT ;
    USE SIGNAL ;
    PORT
      LAYER M5 ;
        RECT  35.28 34.368 35.304 34.56 ;
    END
  END ba_hi[319]
  PIN ba_hi[31]
    DIRECTION OUTPUT ;
    USE SIGNAL ;
    PORT
      LAYER M5 ;
        RECT  21.456 34.368 21.48 34.56 ;
    END
  END ba_hi[31]
  PIN ba_hi[320]
    DIRECTION OUTPUT ;
    USE SIGNAL ;
    PORT
      LAYER M3 ;
        RECT  35.28 34.416 35.298 34.56 ;
    END
  END ba_hi[320]
  PIN ba_hi[321]
    DIRECTION OUTPUT ;
    USE SIGNAL ;
    PORT
      LAYER M5 ;
        RECT  35.376 34.368 35.4 34.56 ;
    END
  END ba_hi[321]
  PIN ba_hi[322]
    DIRECTION OUTPUT ;
    USE SIGNAL ;
    PORT
      LAYER M3 ;
        RECT  35.388 34.416 35.406 34.56 ;
    END
  END ba_hi[322]
  PIN ba_hi[323]
    DIRECTION OUTPUT ;
    USE SIGNAL ;
    PORT
      LAYER M5 ;
        RECT  35.472 34.368 35.496 34.56 ;
    END
  END ba_hi[323]
  PIN ba_hi[324]
    DIRECTION OUTPUT ;
    USE SIGNAL ;
    PORT
      LAYER M3 ;
        RECT  35.496 34.416 35.514 34.56 ;
    END
  END ba_hi[324]
  PIN ba_hi[325]
    DIRECTION OUTPUT ;
    USE SIGNAL ;
    PORT
      LAYER M5 ;
        RECT  35.568 34.368 35.592 34.56 ;
    END
  END ba_hi[325]
  PIN ba_hi[326]
    DIRECTION OUTPUT ;
    USE SIGNAL ;
    PORT
      LAYER M3 ;
        RECT  35.604 34.416 35.622 34.56 ;
    END
  END ba_hi[326]
  PIN ba_hi[327]
    DIRECTION OUTPUT ;
    USE SIGNAL ;
    PORT
      LAYER M5 ;
        RECT  35.664 34.368 35.688 34.56 ;
    END
  END ba_hi[327]
  PIN ba_hi[328]
    DIRECTION OUTPUT ;
    USE SIGNAL ;
    PORT
      LAYER M3 ;
        RECT  35.712 34.416 35.73 34.56 ;
    END
  END ba_hi[328]
  PIN ba_hi[329]
    DIRECTION OUTPUT ;
    USE SIGNAL ;
    PORT
      LAYER M5 ;
        RECT  35.76 34.368 35.784 34.56 ;
    END
  END ba_hi[329]
  PIN ba_hi[32]
    DIRECTION OUTPUT ;
    USE SIGNAL ;
    PORT
      LAYER M3 ;
        RECT  19.728 34.416 19.746 34.56 ;
    END
  END ba_hi[32]
  PIN ba_hi[330]
    DIRECTION OUTPUT ;
    USE SIGNAL ;
    PORT
      LAYER M3 ;
        RECT  35.82 34.416 35.838 34.56 ;
    END
  END ba_hi[330]
  PIN ba_hi[331]
    DIRECTION OUTPUT ;
    USE SIGNAL ;
    PORT
      LAYER M5 ;
        RECT  35.856 34.368 35.88 34.56 ;
    END
  END ba_hi[331]
  PIN ba_hi[332]
    DIRECTION OUTPUT ;
    USE SIGNAL ;
    PORT
      LAYER M3 ;
        RECT  35.928 34.416 35.946 34.56 ;
    END
  END ba_hi[332]
  PIN ba_hi[333]
    DIRECTION OUTPUT ;
    USE SIGNAL ;
    PORT
      LAYER M5 ;
        RECT  35.952 34.368 35.976 34.56 ;
    END
  END ba_hi[333]
  PIN ba_hi[334]
    DIRECTION OUTPUT ;
    USE SIGNAL ;
    PORT
      LAYER M3 ;
        RECT  36.036 34.416 36.054 34.56 ;
    END
  END ba_hi[334]
  PIN ba_hi[335]
    DIRECTION OUTPUT ;
    USE SIGNAL ;
    PORT
      LAYER M5 ;
        RECT  36.048 34.368 36.072 34.56 ;
    END
  END ba_hi[335]
  PIN ba_hi[336]
    DIRECTION OUTPUT ;
    USE SIGNAL ;
    PORT
      LAYER M3 ;
        RECT  36.144 34.416 36.162 34.56 ;
    END
  END ba_hi[336]
  PIN ba_hi[337]
    DIRECTION OUTPUT ;
    USE SIGNAL ;
    PORT
      LAYER M5 ;
        RECT  36.144 34.368 36.168 34.56 ;
    END
  END ba_hi[337]
  PIN ba_hi[338]
    DIRECTION OUTPUT ;
    USE SIGNAL ;
    PORT
      LAYER M3 ;
        RECT  36.252 34.416 36.27 34.56 ;
    END
  END ba_hi[338]
  PIN ba_hi[339]
    DIRECTION OUTPUT ;
    USE SIGNAL ;
    PORT
      LAYER M5 ;
        RECT  36.24 34.368 36.264 34.56 ;
    END
  END ba_hi[339]
  PIN ba_hi[33]
    DIRECTION OUTPUT ;
    USE SIGNAL ;
    PORT
      LAYER M5 ;
        RECT  21.552 34.368 21.576 34.56 ;
    END
  END ba_hi[33]
  PIN ba_hi[340]
    DIRECTION OUTPUT ;
    USE SIGNAL ;
    PORT
      LAYER M3 ;
        RECT  36.36 34.416 36.378 34.56 ;
    END
  END ba_hi[340]
  PIN ba_hi[341]
    DIRECTION OUTPUT ;
    USE SIGNAL ;
    PORT
      LAYER M5 ;
        RECT  36.336 34.368 36.36 34.56 ;
    END
  END ba_hi[341]
  PIN ba_hi[342]
    DIRECTION OUTPUT ;
    USE SIGNAL ;
    PORT
      LAYER M3 ;
        RECT  36.468 34.416 36.486 34.56 ;
    END
  END ba_hi[342]
  PIN ba_hi[343]
    DIRECTION OUTPUT ;
    USE SIGNAL ;
    PORT
      LAYER M5 ;
        RECT  36.432 34.368 36.456 34.56 ;
    END
  END ba_hi[343]
  PIN ba_hi[344]
    DIRECTION OUTPUT ;
    USE SIGNAL ;
    PORT
      LAYER M3 ;
        RECT  36.576 34.416 36.594 34.56 ;
    END
  END ba_hi[344]
  PIN ba_hi[345]
    DIRECTION OUTPUT ;
    USE SIGNAL ;
    PORT
      LAYER M5 ;
        RECT  36.528 34.368 36.552 34.56 ;
    END
  END ba_hi[345]
  PIN ba_hi[346]
    DIRECTION OUTPUT ;
    USE SIGNAL ;
    PORT
      LAYER M3 ;
        RECT  36.684 34.416 36.702 34.56 ;
    END
  END ba_hi[346]
  PIN ba_hi[347]
    DIRECTION OUTPUT ;
    USE SIGNAL ;
    PORT
      LAYER M5 ;
        RECT  36.624 34.368 36.648 34.56 ;
    END
  END ba_hi[347]
  PIN ba_hi[348]
    DIRECTION OUTPUT ;
    USE SIGNAL ;
    PORT
      LAYER M3 ;
        RECT  36.792 34.416 36.81 34.56 ;
    END
  END ba_hi[348]
  PIN ba_hi[349]
    DIRECTION OUTPUT ;
    USE SIGNAL ;
    PORT
      LAYER M5 ;
        RECT  36.72 34.368 36.744 34.56 ;
    END
  END ba_hi[349]
  PIN ba_hi[34]
    DIRECTION OUTPUT ;
    USE SIGNAL ;
    PORT
      LAYER M3 ;
        RECT  19.836 34.416 19.854 34.56 ;
    END
  END ba_hi[34]
  PIN ba_hi[350]
    DIRECTION OUTPUT ;
    USE SIGNAL ;
    PORT
      LAYER M3 ;
        RECT  36.9 34.416 36.918 34.56 ;
    END
  END ba_hi[350]
  PIN ba_hi[351]
    DIRECTION OUTPUT ;
    USE SIGNAL ;
    PORT
      LAYER M5 ;
        RECT  36.816 34.368 36.84 34.56 ;
    END
  END ba_hi[351]
  PIN ba_hi[352]
    DIRECTION OUTPUT ;
    USE SIGNAL ;
    PORT
      LAYER M3 ;
        RECT  37.008 34.416 37.026 34.56 ;
    END
  END ba_hi[352]
  PIN ba_hi[353]
    DIRECTION OUTPUT ;
    USE SIGNAL ;
    PORT
      LAYER M5 ;
        RECT  36.912 34.368 36.936 34.56 ;
    END
  END ba_hi[353]
  PIN ba_hi[354]
    DIRECTION OUTPUT ;
    USE SIGNAL ;
    PORT
      LAYER M3 ;
        RECT  37.116 34.416 37.134 34.56 ;
    END
  END ba_hi[354]
  PIN ba_hi[355]
    DIRECTION OUTPUT ;
    USE SIGNAL ;
    PORT
      LAYER M5 ;
        RECT  37.008 34.368 37.032 34.56 ;
    END
  END ba_hi[355]
  PIN ba_hi[356]
    DIRECTION OUTPUT ;
    USE SIGNAL ;
    PORT
      LAYER M3 ;
        RECT  37.224 34.416 37.242 34.56 ;
    END
  END ba_hi[356]
  PIN ba_hi[357]
    DIRECTION OUTPUT ;
    USE SIGNAL ;
    PORT
      LAYER M5 ;
        RECT  37.104 34.368 37.128 34.56 ;
    END
  END ba_hi[357]
  PIN ba_hi[358]
    DIRECTION OUTPUT ;
    USE SIGNAL ;
    PORT
      LAYER M3 ;
        RECT  37.332 34.416 37.35 34.56 ;
    END
  END ba_hi[358]
  PIN ba_hi[359]
    DIRECTION OUTPUT ;
    USE SIGNAL ;
    PORT
      LAYER M5 ;
        RECT  37.2 34.368 37.224 34.56 ;
    END
  END ba_hi[359]
  PIN ba_hi[35]
    DIRECTION OUTPUT ;
    USE SIGNAL ;
    PORT
      LAYER M5 ;
        RECT  21.648 34.368 21.672 34.56 ;
    END
  END ba_hi[35]
  PIN ba_hi[360]
    DIRECTION OUTPUT ;
    USE SIGNAL ;
    PORT
      LAYER M3 ;
        RECT  37.44 34.416 37.458 34.56 ;
    END
  END ba_hi[360]
  PIN ba_hi[361]
    DIRECTION OUTPUT ;
    USE SIGNAL ;
    PORT
      LAYER M5 ;
        RECT  37.296 34.368 37.32 34.56 ;
    END
  END ba_hi[361]
  PIN ba_hi[362]
    DIRECTION OUTPUT ;
    USE SIGNAL ;
    PORT
      LAYER M3 ;
        RECT  37.548 34.416 37.566 34.56 ;
    END
  END ba_hi[362]
  PIN ba_hi[363]
    DIRECTION OUTPUT ;
    USE SIGNAL ;
    PORT
      LAYER M5 ;
        RECT  37.392 34.368 37.416 34.56 ;
    END
  END ba_hi[363]
  PIN ba_hi[364]
    DIRECTION OUTPUT ;
    USE SIGNAL ;
    PORT
      LAYER M3 ;
        RECT  37.656 34.416 37.674 34.56 ;
    END
  END ba_hi[364]
  PIN ba_hi[365]
    DIRECTION OUTPUT ;
    USE SIGNAL ;
    PORT
      LAYER M5 ;
        RECT  37.488 34.368 37.512 34.56 ;
    END
  END ba_hi[365]
  PIN ba_hi[366]
    DIRECTION OUTPUT ;
    USE SIGNAL ;
    PORT
      LAYER M3 ;
        RECT  37.764 34.416 37.782 34.56 ;
    END
  END ba_hi[366]
  PIN ba_hi[367]
    DIRECTION OUTPUT ;
    USE SIGNAL ;
    PORT
      LAYER M5 ;
        RECT  37.584 34.368 37.608 34.56 ;
    END
  END ba_hi[367]
  PIN ba_hi[368]
    DIRECTION OUTPUT ;
    USE SIGNAL ;
    PORT
      LAYER M3 ;
        RECT  37.872 34.416 37.89 34.56 ;
    END
  END ba_hi[368]
  PIN ba_hi[369]
    DIRECTION OUTPUT ;
    USE SIGNAL ;
    PORT
      LAYER M5 ;
        RECT  37.68 34.368 37.704 34.56 ;
    END
  END ba_hi[369]
  PIN ba_hi[36]
    DIRECTION OUTPUT ;
    USE SIGNAL ;
    PORT
      LAYER M3 ;
        RECT  19.944 34.416 19.962 34.56 ;
    END
  END ba_hi[36]
  PIN ba_hi[370]
    DIRECTION OUTPUT ;
    USE SIGNAL ;
    PORT
      LAYER M3 ;
        RECT  37.98 34.416 37.998 34.56 ;
    END
  END ba_hi[370]
  PIN ba_hi[371]
    DIRECTION OUTPUT ;
    USE SIGNAL ;
    PORT
      LAYER M5 ;
        RECT  37.776 34.368 37.8 34.56 ;
    END
  END ba_hi[371]
  PIN ba_hi[372]
    DIRECTION OUTPUT ;
    USE SIGNAL ;
    PORT
      LAYER M3 ;
        RECT  38.088 34.416 38.106 34.56 ;
    END
  END ba_hi[372]
  PIN ba_hi[373]
    DIRECTION OUTPUT ;
    USE SIGNAL ;
    PORT
      LAYER M5 ;
        RECT  37.872 34.368 37.896 34.56 ;
    END
  END ba_hi[373]
  PIN ba_hi[374]
    DIRECTION OUTPUT ;
    USE SIGNAL ;
    PORT
      LAYER M3 ;
        RECT  38.196 34.416 38.214 34.56 ;
    END
  END ba_hi[374]
  PIN ba_hi[375]
    DIRECTION OUTPUT ;
    USE SIGNAL ;
    PORT
      LAYER M5 ;
        RECT  37.968 34.368 37.992 34.56 ;
    END
  END ba_hi[375]
  PIN ba_hi[376]
    DIRECTION OUTPUT ;
    USE SIGNAL ;
    PORT
      LAYER M3 ;
        RECT  38.304 34.416 38.322 34.56 ;
    END
  END ba_hi[376]
  PIN ba_hi[377]
    DIRECTION OUTPUT ;
    USE SIGNAL ;
    PORT
      LAYER M5 ;
        RECT  38.064 34.368 38.088 34.56 ;
    END
  END ba_hi[377]
  PIN ba_hi[378]
    DIRECTION OUTPUT ;
    USE SIGNAL ;
    PORT
      LAYER M3 ;
        RECT  38.412 34.416 38.43 34.56 ;
    END
  END ba_hi[378]
  PIN ba_hi[379]
    DIRECTION OUTPUT ;
    USE SIGNAL ;
    PORT
      LAYER M5 ;
        RECT  38.16 34.368 38.184 34.56 ;
    END
  END ba_hi[379]
  PIN ba_hi[37]
    DIRECTION OUTPUT ;
    USE SIGNAL ;
    PORT
      LAYER M5 ;
        RECT  21.744 34.368 21.768 34.56 ;
    END
  END ba_hi[37]
  PIN ba_hi[380]
    DIRECTION OUTPUT ;
    USE SIGNAL ;
    PORT
      LAYER M3 ;
        RECT  38.52 34.416 38.538 34.56 ;
    END
    PORT
      LAYER M3 ;
        RECT  38.484 34.428 38.61 34.493 ;
    END
  END ba_hi[380]
  PIN ba_hi[381]
    DIRECTION OUTPUT ;
    USE SIGNAL ;
    PORT
      LAYER M5 ;
        RECT  38.256 34.368 38.28 34.56 ;
    END
  END ba_hi[381]
  PIN ba_hi[382]
    DIRECTION OUTPUT ;
    USE SIGNAL ;
    PORT
      LAYER M3 ;
        RECT  38.628 34.416 38.646 34.56 ;
    END
  END ba_hi[382]
  PIN ba_hi[383]
    DIRECTION OUTPUT ;
    USE SIGNAL ;
    PORT
      LAYER M5 ;
        RECT  38.352 34.368 38.376 34.56 ;
    END
  END ba_hi[383]
  PIN ba_hi[384]
    DIRECTION OUTPUT ;
    USE SIGNAL ;
    PORT
      LAYER M3 ;
        RECT  38.736 34.416 38.754 34.56 ;
    END
  END ba_hi[384]
  PIN ba_hi[385]
    DIRECTION OUTPUT ;
    USE SIGNAL ;
    PORT
      LAYER M5 ;
        RECT  38.448 34.368 38.472 34.56 ;
    END
  END ba_hi[385]
  PIN ba_hi[386]
    DIRECTION OUTPUT ;
    USE SIGNAL ;
    PORT
      LAYER M3 ;
        RECT  38.844 34.416 38.862 34.56 ;
    END
  END ba_hi[386]
  PIN ba_hi[387]
    DIRECTION OUTPUT ;
    USE SIGNAL ;
    PORT
      LAYER M5 ;
        RECT  38.544 34.368 38.568 34.56 ;
    END
  END ba_hi[387]
  PIN ba_hi[388]
    DIRECTION OUTPUT ;
    USE SIGNAL ;
    PORT
      LAYER M3 ;
        RECT  38.952 34.416 38.97 34.56 ;
    END
  END ba_hi[388]
  PIN ba_hi[389]
    DIRECTION OUTPUT ;
    USE SIGNAL ;
    PORT
      LAYER M5 ;
        RECT  38.64 34.368 38.664 34.56 ;
    END
  END ba_hi[389]
  PIN ba_hi[38]
    DIRECTION OUTPUT ;
    USE SIGNAL ;
    PORT
      LAYER M3 ;
        RECT  20.052 34.416 20.07 34.56 ;
    END
  END ba_hi[38]
  PIN ba_hi[390]
    DIRECTION OUTPUT ;
    USE SIGNAL ;
    PORT
      LAYER M3 ;
        RECT  39.06 34.416 39.078 34.56 ;
    END
  END ba_hi[390]
  PIN ba_hi[391]
    DIRECTION OUTPUT ;
    USE SIGNAL ;
    PORT
      LAYER M5 ;
        RECT  38.736 34.368 38.76 34.56 ;
    END
  END ba_hi[391]
  PIN ba_hi[392]
    DIRECTION OUTPUT ;
    USE SIGNAL ;
    PORT
      LAYER M3 ;
        RECT  39.168 34.416 39.186 34.56 ;
    END
  END ba_hi[392]
  PIN ba_hi[393]
    DIRECTION OUTPUT ;
    USE SIGNAL ;
    PORT
      LAYER M5 ;
        RECT  38.832 34.368 38.856 34.56 ;
    END
  END ba_hi[393]
  PIN ba_hi[394]
    DIRECTION OUTPUT ;
    USE SIGNAL ;
    PORT
      LAYER M3 ;
        RECT  39.276 34.416 39.294 34.56 ;
    END
  END ba_hi[394]
  PIN ba_hi[395]
    DIRECTION OUTPUT ;
    USE SIGNAL ;
    PORT
      LAYER M5 ;
        RECT  38.928 34.368 38.952 34.56 ;
    END
  END ba_hi[395]
  PIN ba_hi[396]
    DIRECTION OUTPUT ;
    USE SIGNAL ;
    PORT
      LAYER M3 ;
        RECT  39.384 34.416 39.402 34.56 ;
    END
  END ba_hi[396]
  PIN ba_hi[397]
    DIRECTION OUTPUT ;
    USE SIGNAL ;
    PORT
      LAYER M5 ;
        RECT  39.024 34.368 39.048 34.56 ;
    END
  END ba_hi[397]
  PIN ba_hi[398]
    DIRECTION OUTPUT ;
    USE SIGNAL ;
    PORT
      LAYER M3 ;
        RECT  39.492 34.416 39.51 34.56 ;
    END
  END ba_hi[398]
  PIN ba_hi[399]
    DIRECTION OUTPUT ;
    USE SIGNAL ;
    PORT
      LAYER M5 ;
        RECT  39.12 34.368 39.144 34.56 ;
    END
  END ba_hi[399]
  PIN ba_hi[39]
    DIRECTION OUTPUT ;
    USE SIGNAL ;
    PORT
      LAYER M5 ;
        RECT  21.84 34.368 21.864 34.56 ;
    END
  END ba_hi[39]
  PIN ba_hi[3]
    DIRECTION OUTPUT ;
    USE SIGNAL ;
    PORT
      LAYER M5 ;
        RECT  20.112 34.368 20.136 34.56 ;
    END
  END ba_hi[3]
  PIN ba_hi[400]
    DIRECTION OUTPUT ;
    USE SIGNAL ;
    PORT
      LAYER M3 ;
        RECT  39.6 34.416 39.618 34.56 ;
    END
  END ba_hi[400]
  PIN ba_hi[401]
    DIRECTION OUTPUT ;
    USE SIGNAL ;
    PORT
      LAYER M5 ;
        RECT  39.216 34.368 39.24 34.56 ;
    END
  END ba_hi[401]
  PIN ba_hi[402]
    DIRECTION OUTPUT ;
    USE SIGNAL ;
    PORT
      LAYER M3 ;
        RECT  39.708 34.416 39.726 34.56 ;
    END
  END ba_hi[402]
  PIN ba_hi[403]
    DIRECTION OUTPUT ;
    USE SIGNAL ;
    PORT
      LAYER M5 ;
        RECT  39.312 34.368 39.336 34.56 ;
    END
  END ba_hi[403]
  PIN ba_hi[404]
    DIRECTION OUTPUT ;
    USE SIGNAL ;
    PORT
      LAYER M3 ;
        RECT  39.816 34.416 39.834 34.56 ;
    END
  END ba_hi[404]
  PIN ba_hi[405]
    DIRECTION OUTPUT ;
    USE SIGNAL ;
    PORT
      LAYER M5 ;
        RECT  39.408 34.368 39.432 34.56 ;
    END
  END ba_hi[405]
  PIN ba_hi[406]
    DIRECTION OUTPUT ;
    USE SIGNAL ;
    PORT
      LAYER M3 ;
        RECT  39.924 34.416 39.942 34.56 ;
    END
  END ba_hi[406]
  PIN ba_hi[407]
    DIRECTION OUTPUT ;
    USE SIGNAL ;
    PORT
      LAYER M5 ;
        RECT  39.504 34.368 39.528 34.56 ;
    END
  END ba_hi[407]
  PIN ba_hi[408]
    DIRECTION OUTPUT ;
    USE SIGNAL ;
    PORT
      LAYER M3 ;
        RECT  40.032 34.416 40.05 34.56 ;
    END
  END ba_hi[408]
  PIN ba_hi[409]
    DIRECTION OUTPUT ;
    USE SIGNAL ;
    PORT
      LAYER M5 ;
        RECT  39.6 34.368 39.624 34.56 ;
    END
  END ba_hi[409]
  PIN ba_hi[40]
    DIRECTION OUTPUT ;
    USE SIGNAL ;
    PORT
      LAYER M3 ;
        RECT  20.16 34.416 20.178 34.56 ;
    END
  END ba_hi[40]
  PIN ba_hi[410]
    DIRECTION OUTPUT ;
    USE SIGNAL ;
    PORT
      LAYER M3 ;
        RECT  40.14 34.416 40.158 34.56 ;
    END
  END ba_hi[410]
  PIN ba_hi[411]
    DIRECTION OUTPUT ;
    USE SIGNAL ;
    PORT
      LAYER M5 ;
        RECT  39.696 34.368 39.72 34.56 ;
    END
  END ba_hi[411]
  PIN ba_hi[412]
    DIRECTION OUTPUT ;
    USE SIGNAL ;
    PORT
      LAYER M3 ;
        RECT  40.248 34.416 40.266 34.56 ;
    END
  END ba_hi[412]
  PIN ba_hi[413]
    DIRECTION OUTPUT ;
    USE SIGNAL ;
    PORT
      LAYER M5 ;
        RECT  39.792 34.368 39.816 34.56 ;
    END
  END ba_hi[413]
  PIN ba_hi[414]
    DIRECTION OUTPUT ;
    USE SIGNAL ;
    PORT
      LAYER M3 ;
        RECT  40.356 34.416 40.374 34.56 ;
    END
  END ba_hi[414]
  PIN ba_hi[415]
    DIRECTION OUTPUT ;
    USE SIGNAL ;
    PORT
      LAYER M5 ;
        RECT  39.888 34.368 39.912 34.56 ;
    END
  END ba_hi[415]
  PIN ba_hi[416]
    DIRECTION OUTPUT ;
    USE SIGNAL ;
    PORT
      LAYER M3 ;
        RECT  40.464 34.416 40.482 34.56 ;
    END
  END ba_hi[416]
  PIN ba_hi[417]
    DIRECTION OUTPUT ;
    USE SIGNAL ;
    PORT
      LAYER M5 ;
        RECT  39.984 34.368 40.008 34.56 ;
    END
  END ba_hi[417]
  PIN ba_hi[418]
    DIRECTION OUTPUT ;
    USE SIGNAL ;
    PORT
      LAYER M3 ;
        RECT  40.572 34.416 40.59 34.56 ;
    END
  END ba_hi[418]
  PIN ba_hi[419]
    DIRECTION OUTPUT ;
    USE SIGNAL ;
    PORT
      LAYER M5 ;
        RECT  40.08 34.368 40.104 34.56 ;
    END
  END ba_hi[419]
  PIN ba_hi[41]
    DIRECTION OUTPUT ;
    USE SIGNAL ;
    PORT
      LAYER M5 ;
        RECT  21.936 34.368 21.96 34.56 ;
    END
  END ba_hi[41]
  PIN ba_hi[420]
    DIRECTION OUTPUT ;
    USE SIGNAL ;
    PORT
      LAYER M3 ;
        RECT  40.68 34.416 40.698 34.56 ;
    END
  END ba_hi[420]
  PIN ba_hi[421]
    DIRECTION OUTPUT ;
    USE SIGNAL ;
    PORT
      LAYER M5 ;
        RECT  40.176 34.368 40.2 34.56 ;
    END
  END ba_hi[421]
  PIN ba_hi[422]
    DIRECTION OUTPUT ;
    USE SIGNAL ;
    PORT
      LAYER M3 ;
        RECT  40.788 34.416 40.806 34.56 ;
    END
  END ba_hi[422]
  PIN ba_hi[423]
    DIRECTION OUTPUT ;
    USE SIGNAL ;
    PORT
      LAYER M5 ;
        RECT  40.272 34.368 40.296 34.56 ;
    END
  END ba_hi[423]
  PIN ba_hi[424]
    DIRECTION OUTPUT ;
    USE SIGNAL ;
    PORT
      LAYER M3 ;
        RECT  40.896 34.416 40.914 34.56 ;
    END
  END ba_hi[424]
  PIN ba_hi[425]
    DIRECTION OUTPUT ;
    USE SIGNAL ;
    PORT
      LAYER M5 ;
        RECT  40.368 34.368 40.392 34.56 ;
    END
  END ba_hi[425]
  PIN ba_hi[426]
    DIRECTION OUTPUT ;
    USE SIGNAL ;
    PORT
      LAYER M3 ;
        RECT  41.004 34.416 41.022 34.56 ;
    END
  END ba_hi[426]
  PIN ba_hi[427]
    DIRECTION OUTPUT ;
    USE SIGNAL ;
    PORT
      LAYER M5 ;
        RECT  40.464 34.368 40.488 34.56 ;
    END
  END ba_hi[427]
  PIN ba_hi[428]
    DIRECTION OUTPUT ;
    USE SIGNAL ;
    PORT
      LAYER M3 ;
        RECT  41.112 34.416 41.13 34.56 ;
    END
  END ba_hi[428]
  PIN ba_hi[429]
    DIRECTION OUTPUT ;
    USE SIGNAL ;
    PORT
      LAYER M5 ;
        RECT  40.56 34.368 40.584 34.56 ;
    END
  END ba_hi[429]
  PIN ba_hi[42]
    DIRECTION OUTPUT ;
    USE SIGNAL ;
    PORT
      LAYER M3 ;
        RECT  20.268 34.416 20.286 34.56 ;
    END
  END ba_hi[42]
  PIN ba_hi[430]
    DIRECTION OUTPUT ;
    USE SIGNAL ;
    PORT
      LAYER M3 ;
        RECT  41.22 34.416 41.238 34.56 ;
    END
  END ba_hi[430]
  PIN ba_hi[431]
    DIRECTION OUTPUT ;
    USE SIGNAL ;
    PORT
      LAYER M5 ;
        RECT  40.656 34.368 40.68 34.56 ;
    END
  END ba_hi[431]
  PIN ba_hi[432]
    DIRECTION OUTPUT ;
    USE SIGNAL ;
    PORT
      LAYER M3 ;
        RECT  41.328 34.416 41.346 34.56 ;
    END
  END ba_hi[432]
  PIN ba_hi[433]
    DIRECTION OUTPUT ;
    USE SIGNAL ;
    PORT
      LAYER M5 ;
        RECT  40.752 34.368 40.776 34.56 ;
    END
  END ba_hi[433]
  PIN ba_hi[434]
    DIRECTION OUTPUT ;
    USE SIGNAL ;
    PORT
      LAYER M3 ;
        RECT  41.436 34.416 41.454 34.56 ;
    END
  END ba_hi[434]
  PIN ba_hi[435]
    DIRECTION OUTPUT ;
    USE SIGNAL ;
    PORT
      LAYER M5 ;
        RECT  40.848 34.368 40.872 34.56 ;
    END
  END ba_hi[435]
  PIN ba_hi[436]
    DIRECTION OUTPUT ;
    USE SIGNAL ;
    PORT
      LAYER M3 ;
        RECT  41.544 34.416 41.562 34.56 ;
    END
  END ba_hi[436]
  PIN ba_hi[437]
    DIRECTION OUTPUT ;
    USE SIGNAL ;
    PORT
      LAYER M5 ;
        RECT  40.944 34.368 40.968 34.56 ;
    END
  END ba_hi[437]
  PIN ba_hi[438]
    DIRECTION OUTPUT ;
    USE SIGNAL ;
    PORT
      LAYER M3 ;
        RECT  41.652 34.416 41.67 34.56 ;
    END
    PORT
      LAYER M3 ;
        RECT  41.616 34.428 41.742 34.493 ;
    END
  END ba_hi[438]
  PIN ba_hi[439]
    DIRECTION OUTPUT ;
    USE SIGNAL ;
    PORT
      LAYER M5 ;
        RECT  41.04 34.368 41.064 34.56 ;
    END
  END ba_hi[439]
  PIN ba_hi[43]
    DIRECTION OUTPUT ;
    USE SIGNAL ;
    PORT
      LAYER M5 ;
        RECT  22.032 34.368 22.056 34.56 ;
    END
  END ba_hi[43]
  PIN ba_hi[440]
    DIRECTION OUTPUT ;
    USE SIGNAL ;
    PORT
      LAYER M3 ;
        RECT  41.76 34.416 41.778 34.56 ;
    END
  END ba_hi[440]
  PIN ba_hi[441]
    DIRECTION OUTPUT ;
    USE SIGNAL ;
    PORT
      LAYER M5 ;
        RECT  41.136 34.368 41.16 34.56 ;
    END
  END ba_hi[441]
  PIN ba_hi[442]
    DIRECTION OUTPUT ;
    USE SIGNAL ;
    PORT
      LAYER M3 ;
        RECT  41.868 34.416 41.886 34.56 ;
    END
  END ba_hi[442]
  PIN ba_hi[443]
    DIRECTION OUTPUT ;
    USE SIGNAL ;
    PORT
      LAYER M5 ;
        RECT  41.232 34.368 41.256 34.56 ;
    END
  END ba_hi[443]
  PIN ba_hi[444]
    DIRECTION OUTPUT ;
    USE SIGNAL ;
    PORT
      LAYER M3 ;
        RECT  41.976 34.416 41.994 34.56 ;
    END
  END ba_hi[444]
  PIN ba_hi[445]
    DIRECTION OUTPUT ;
    USE SIGNAL ;
    PORT
      LAYER M5 ;
        RECT  41.328 34.368 41.352 34.56 ;
    END
  END ba_hi[445]
  PIN ba_hi[446]
    DIRECTION OUTPUT ;
    USE SIGNAL ;
    PORT
      LAYER M3 ;
        RECT  42.084 34.416 42.102 34.56 ;
    END
  END ba_hi[446]
  PIN ba_hi[447]
    DIRECTION OUTPUT ;
    USE SIGNAL ;
    PORT
      LAYER M5 ;
        RECT  41.424 34.368 41.448 34.56 ;
    END
  END ba_hi[447]
  PIN ba_hi[448]
    DIRECTION OUTPUT ;
    USE SIGNAL ;
    PORT
      LAYER M3 ;
        RECT  42.192 34.416 42.21 34.56 ;
    END
  END ba_hi[448]
  PIN ba_hi[449]
    DIRECTION OUTPUT ;
    USE SIGNAL ;
    PORT
      LAYER M5 ;
        RECT  41.52 34.368 41.544 34.56 ;
    END
  END ba_hi[449]
  PIN ba_hi[44]
    DIRECTION OUTPUT ;
    USE SIGNAL ;
    PORT
      LAYER M3 ;
        RECT  20.376 34.416 20.394 34.56 ;
    END
  END ba_hi[44]
  PIN ba_hi[450]
    DIRECTION OUTPUT ;
    USE SIGNAL ;
    PORT
      LAYER M3 ;
        RECT  42.3 34.416 42.318 34.56 ;
    END
  END ba_hi[450]
  PIN ba_hi[451]
    DIRECTION OUTPUT ;
    USE SIGNAL ;
    PORT
      LAYER M5 ;
        RECT  41.616 34.368 41.64 34.56 ;
    END
  END ba_hi[451]
  PIN ba_hi[452]
    DIRECTION OUTPUT ;
    USE SIGNAL ;
    PORT
      LAYER M3 ;
        RECT  42.408 34.416 42.426 34.56 ;
    END
  END ba_hi[452]
  PIN ba_hi[453]
    DIRECTION OUTPUT ;
    USE SIGNAL ;
    PORT
      LAYER M5 ;
        RECT  41.712 34.368 41.736 34.56 ;
    END
  END ba_hi[453]
  PIN ba_hi[454]
    DIRECTION OUTPUT ;
    USE SIGNAL ;
    PORT
      LAYER M3 ;
        RECT  42.516 34.416 42.534 34.56 ;
    END
  END ba_hi[454]
  PIN ba_hi[455]
    DIRECTION OUTPUT ;
    USE SIGNAL ;
    PORT
      LAYER M5 ;
        RECT  41.808 34.368 41.832 34.56 ;
    END
  END ba_hi[455]
  PIN ba_hi[456]
    DIRECTION OUTPUT ;
    USE SIGNAL ;
    PORT
      LAYER M3 ;
        RECT  42.624 34.416 42.642 34.56 ;
    END
  END ba_hi[456]
  PIN ba_hi[457]
    DIRECTION OUTPUT ;
    USE SIGNAL ;
    PORT
      LAYER M5 ;
        RECT  41.904 34.368 41.928 34.56 ;
    END
  END ba_hi[457]
  PIN ba_hi[458]
    DIRECTION OUTPUT ;
    USE SIGNAL ;
    PORT
      LAYER M3 ;
        RECT  42.732 34.416 42.75 34.56 ;
    END
  END ba_hi[458]
  PIN ba_hi[459]
    DIRECTION OUTPUT ;
    USE SIGNAL ;
    PORT
      LAYER M5 ;
        RECT  42 34.368 42.024 34.56 ;
    END
  END ba_hi[459]
  PIN ba_hi[45]
    DIRECTION OUTPUT ;
    USE SIGNAL ;
    PORT
      LAYER M5 ;
        RECT  22.128 34.368 22.152 34.56 ;
    END
  END ba_hi[45]
  PIN ba_hi[460]
    DIRECTION OUTPUT ;
    USE SIGNAL ;
    PORT
      LAYER M3 ;
        RECT  42.84 34.416 42.858 34.56 ;
    END
  END ba_hi[460]
  PIN ba_hi[461]
    DIRECTION OUTPUT ;
    USE SIGNAL ;
    PORT
      LAYER M5 ;
        RECT  42.096 34.368 42.12 34.56 ;
    END
  END ba_hi[461]
  PIN ba_hi[462]
    DIRECTION OUTPUT ;
    USE SIGNAL ;
    PORT
      LAYER M3 ;
        RECT  42.948 34.416 42.966 34.56 ;
    END
  END ba_hi[462]
  PIN ba_hi[463]
    DIRECTION OUTPUT ;
    USE SIGNAL ;
    PORT
      LAYER M5 ;
        RECT  42.192 34.368 42.216 34.56 ;
    END
  END ba_hi[463]
  PIN ba_hi[464]
    DIRECTION OUTPUT ;
    USE SIGNAL ;
    PORT
      LAYER M3 ;
        RECT  43.056 34.416 43.074 34.56 ;
    END
  END ba_hi[464]
  PIN ba_hi[465]
    DIRECTION OUTPUT ;
    USE SIGNAL ;
    PORT
      LAYER M5 ;
        RECT  42.288 34.368 42.312 34.56 ;
    END
  END ba_hi[465]
  PIN ba_hi[466]
    DIRECTION OUTPUT ;
    USE SIGNAL ;
    PORT
      LAYER M3 ;
        RECT  43.164 34.416 43.182 34.56 ;
    END
  END ba_hi[466]
  PIN ba_hi[467]
    DIRECTION OUTPUT ;
    USE SIGNAL ;
    PORT
      LAYER M5 ;
        RECT  42.384 34.368 42.408 34.56 ;
    END
  END ba_hi[467]
  PIN ba_hi[468]
    DIRECTION OUTPUT ;
    USE SIGNAL ;
    PORT
      LAYER M3 ;
        RECT  43.272 34.416 43.29 34.56 ;
    END
  END ba_hi[468]
  PIN ba_hi[469]
    DIRECTION OUTPUT ;
    USE SIGNAL ;
    PORT
      LAYER M5 ;
        RECT  42.48 34.368 42.504 34.56 ;
    END
  END ba_hi[469]
  PIN ba_hi[46]
    DIRECTION OUTPUT ;
    USE SIGNAL ;
    PORT
      LAYER M3 ;
        RECT  20.484 34.416 20.502 34.56 ;
    END
  END ba_hi[46]
  PIN ba_hi[470]
    DIRECTION OUTPUT ;
    USE SIGNAL ;
    PORT
      LAYER M3 ;
        RECT  43.38 34.416 43.398 34.56 ;
    END
  END ba_hi[470]
  PIN ba_hi[471]
    DIRECTION OUTPUT ;
    USE SIGNAL ;
    PORT
      LAYER M5 ;
        RECT  42.576 34.368 42.6 34.56 ;
    END
  END ba_hi[471]
  PIN ba_hi[472]
    DIRECTION OUTPUT ;
    USE SIGNAL ;
    PORT
      LAYER M3 ;
        RECT  43.488 34.416 43.506 34.56 ;
    END
  END ba_hi[472]
  PIN ba_hi[473]
    DIRECTION OUTPUT ;
    USE SIGNAL ;
    PORT
      LAYER M5 ;
        RECT  42.672 34.368 42.696 34.56 ;
    END
  END ba_hi[473]
  PIN ba_hi[474]
    DIRECTION OUTPUT ;
    USE SIGNAL ;
    PORT
      LAYER M3 ;
        RECT  43.596 34.416 43.614 34.56 ;
    END
  END ba_hi[474]
  PIN ba_hi[475]
    DIRECTION OUTPUT ;
    USE SIGNAL ;
    PORT
      LAYER M5 ;
        RECT  42.768 34.368 42.792 34.56 ;
    END
  END ba_hi[475]
  PIN ba_hi[476]
    DIRECTION OUTPUT ;
    USE SIGNAL ;
    PORT
      LAYER M3 ;
        RECT  43.704 34.416 43.722 34.56 ;
    END
  END ba_hi[476]
  PIN ba_hi[477]
    DIRECTION OUTPUT ;
    USE SIGNAL ;
    PORT
      LAYER M5 ;
        RECT  42.864 34.368 42.888 34.56 ;
    END
  END ba_hi[477]
  PIN ba_hi[478]
    DIRECTION OUTPUT ;
    USE SIGNAL ;
    PORT
      LAYER M3 ;
        RECT  43.812 34.416 43.83 34.56 ;
    END
  END ba_hi[478]
  PIN ba_hi[479]
    DIRECTION OUTPUT ;
    USE SIGNAL ;
    PORT
      LAYER M5 ;
        RECT  42.96 34.368 42.984 34.56 ;
    END
  END ba_hi[479]
  PIN ba_hi[47]
    DIRECTION OUTPUT ;
    USE SIGNAL ;
    PORT
      LAYER M5 ;
        RECT  22.224 34.368 22.248 34.56 ;
    END
  END ba_hi[47]
  PIN ba_hi[480]
    DIRECTION OUTPUT ;
    USE SIGNAL ;
    PORT
      LAYER M3 ;
        RECT  43.92 34.416 43.938 34.56 ;
    END
  END ba_hi[480]
  PIN ba_hi[481]
    DIRECTION OUTPUT ;
    USE SIGNAL ;
    PORT
      LAYER M5 ;
        RECT  43.056 34.368 43.08 34.56 ;
    END
  END ba_hi[481]
  PIN ba_hi[482]
    DIRECTION OUTPUT ;
    USE SIGNAL ;
    PORT
      LAYER M3 ;
        RECT  44.028 34.416 44.046 34.56 ;
    END
  END ba_hi[482]
  PIN ba_hi[483]
    DIRECTION OUTPUT ;
    USE SIGNAL ;
    PORT
      LAYER M5 ;
        RECT  43.152 34.368 43.176 34.56 ;
    END
  END ba_hi[483]
  PIN ba_hi[484]
    DIRECTION OUTPUT ;
    USE SIGNAL ;
    PORT
      LAYER M3 ;
        RECT  44.136 34.416 44.154 34.56 ;
    END
  END ba_hi[484]
  PIN ba_hi[485]
    DIRECTION OUTPUT ;
    USE SIGNAL ;
    PORT
      LAYER M5 ;
        RECT  43.248 34.368 43.272 34.56 ;
    END
  END ba_hi[485]
  PIN ba_hi[486]
    DIRECTION OUTPUT ;
    USE SIGNAL ;
    PORT
      LAYER M3 ;
        RECT  44.244 34.416 44.262 34.56 ;
    END
  END ba_hi[486]
  PIN ba_hi[487]
    DIRECTION OUTPUT ;
    USE SIGNAL ;
    PORT
      LAYER M5 ;
        RECT  43.344 34.368 43.368 34.56 ;
    END
  END ba_hi[487]
  PIN ba_hi[488]
    DIRECTION OUTPUT ;
    USE SIGNAL ;
    PORT
      LAYER M3 ;
        RECT  44.352 34.416 44.37 34.56 ;
    END
  END ba_hi[488]
  PIN ba_hi[489]
    DIRECTION OUTPUT ;
    USE SIGNAL ;
    PORT
      LAYER M5 ;
        RECT  43.44 34.368 43.464 34.56 ;
    END
  END ba_hi[489]
  PIN ba_hi[48]
    DIRECTION OUTPUT ;
    USE SIGNAL ;
    PORT
      LAYER M3 ;
        RECT  20.592 34.416 20.61 34.56 ;
    END
  END ba_hi[48]
  PIN ba_hi[490]
    DIRECTION OUTPUT ;
    USE SIGNAL ;
    PORT
      LAYER M3 ;
        RECT  44.46 34.416 44.478 34.56 ;
    END
  END ba_hi[490]
  PIN ba_hi[491]
    DIRECTION OUTPUT ;
    USE SIGNAL ;
    PORT
      LAYER M5 ;
        RECT  43.536 34.368 43.56 34.56 ;
    END
  END ba_hi[491]
  PIN ba_hi[492]
    DIRECTION OUTPUT ;
    USE SIGNAL ;
    PORT
      LAYER M3 ;
        RECT  44.568 34.416 44.586 34.56 ;
    END
  END ba_hi[492]
  PIN ba_hi[493]
    DIRECTION OUTPUT ;
    USE SIGNAL ;
    PORT
      LAYER M5 ;
        RECT  43.632 34.368 43.656 34.56 ;
    END
  END ba_hi[493]
  PIN ba_hi[494]
    DIRECTION OUTPUT ;
    USE SIGNAL ;
    PORT
      LAYER M3 ;
        RECT  44.676 34.416 44.694 34.56 ;
    END
  END ba_hi[494]
  PIN ba_hi[495]
    DIRECTION OUTPUT ;
    USE SIGNAL ;
    PORT
      LAYER M5 ;
        RECT  43.728 34.368 43.752 34.56 ;
    END
  END ba_hi[495]
  PIN ba_hi[496]
    DIRECTION OUTPUT ;
    USE SIGNAL ;
    PORT
      LAYER M3 ;
        RECT  44.784 34.416 44.802 34.56 ;
    END
  END ba_hi[496]
  PIN ba_hi[497]
    DIRECTION OUTPUT ;
    USE SIGNAL ;
    PORT
      LAYER M5 ;
        RECT  43.824 34.368 43.848 34.56 ;
    END
  END ba_hi[497]
  PIN ba_hi[498]
    DIRECTION OUTPUT ;
    USE SIGNAL ;
    PORT
      LAYER M3 ;
        RECT  44.892 34.416 44.91 34.56 ;
    END
  END ba_hi[498]
  PIN ba_hi[499]
    DIRECTION OUTPUT ;
    USE SIGNAL ;
    PORT
      LAYER M5 ;
        RECT  43.92 34.368 43.944 34.56 ;
    END
  END ba_hi[499]
  PIN ba_hi[49]
    DIRECTION OUTPUT ;
    USE SIGNAL ;
    PORT
      LAYER M5 ;
        RECT  22.32 34.368 22.344 34.56 ;
    END
  END ba_hi[49]
  PIN ba_hi[4]
    DIRECTION OUTPUT ;
    USE SIGNAL ;
    PORT
      LAYER M3 ;
        RECT  18.216 34.416 18.234 34.56 ;
    END
  END ba_hi[4]
  PIN ba_hi[500]
    DIRECTION OUTPUT ;
    USE SIGNAL ;
    PORT
      LAYER M3 ;
        RECT  45 34.416 45.018 34.56 ;
    END
  END ba_hi[500]
  PIN ba_hi[501]
    DIRECTION OUTPUT ;
    USE SIGNAL ;
    PORT
      LAYER M5 ;
        RECT  44.016 34.368 44.04 34.56 ;
    END
  END ba_hi[501]
  PIN ba_hi[502]
    DIRECTION OUTPUT ;
    USE SIGNAL ;
    PORT
      LAYER M3 ;
        RECT  45.108 34.416 45.126 34.56 ;
    END
  END ba_hi[502]
  PIN ba_hi[503]
    DIRECTION OUTPUT ;
    USE SIGNAL ;
    PORT
      LAYER M5 ;
        RECT  44.112 34.368 44.136 34.56 ;
    END
  END ba_hi[503]
  PIN ba_hi[504]
    DIRECTION OUTPUT ;
    USE SIGNAL ;
    PORT
      LAYER M3 ;
        RECT  45.216 34.416 45.234 34.56 ;
    END
  END ba_hi[504]
  PIN ba_hi[505]
    DIRECTION OUTPUT ;
    USE SIGNAL ;
    PORT
      LAYER M5 ;
        RECT  44.208 34.368 44.232 34.56 ;
    END
  END ba_hi[505]
  PIN ba_hi[506]
    DIRECTION OUTPUT ;
    USE SIGNAL ;
    PORT
      LAYER M3 ;
        RECT  45.324 34.416 45.342 34.56 ;
    END
  END ba_hi[506]
  PIN ba_hi[507]
    DIRECTION OUTPUT ;
    USE SIGNAL ;
    PORT
      LAYER M5 ;
        RECT  44.304 34.368 44.328 34.56 ;
    END
  END ba_hi[507]
  PIN ba_hi[508]
    DIRECTION OUTPUT ;
    USE SIGNAL ;
    PORT
      LAYER M3 ;
        RECT  45.432 34.416 45.45 34.56 ;
    END
  END ba_hi[508]
  PIN ba_hi[509]
    DIRECTION OUTPUT ;
    USE SIGNAL ;
    PORT
      LAYER M5 ;
        RECT  44.4 34.368 44.424 34.56 ;
    END
  END ba_hi[509]
  PIN ba_hi[50]
    DIRECTION OUTPUT ;
    USE SIGNAL ;
    PORT
      LAYER M3 ;
        RECT  20.7 34.416 20.718 34.56 ;
    END
  END ba_hi[50]
  PIN ba_hi[510]
    DIRECTION OUTPUT ;
    USE SIGNAL ;
    PORT
      LAYER M3 ;
        RECT  45.54 34.416 45.558 34.56 ;
    END
  END ba_hi[510]
  PIN ba_hi[511]
    DIRECTION OUTPUT ;
    USE SIGNAL ;
    PORT
      LAYER M5 ;
        RECT  44.496 34.368 44.52 34.56 ;
    END
  END ba_hi[511]
  PIN ba_hi[51]
    DIRECTION OUTPUT ;
    USE SIGNAL ;
    PORT
      LAYER M5 ;
        RECT  22.416 34.368 22.44 34.56 ;
    END
  END ba_hi[51]
  PIN ba_hi[52]
    DIRECTION OUTPUT ;
    USE SIGNAL ;
    PORT
      LAYER M3 ;
        RECT  20.808 34.416 20.826 34.56 ;
    END
  END ba_hi[52]
  PIN ba_hi[53]
    DIRECTION OUTPUT ;
    USE SIGNAL ;
    PORT
      LAYER M5 ;
        RECT  22.512 34.368 22.536 34.56 ;
    END
  END ba_hi[53]
  PIN ba_hi[54]
    DIRECTION OUTPUT ;
    USE SIGNAL ;
    PORT
      LAYER M3 ;
        RECT  20.916 34.416 20.934 34.56 ;
    END
  END ba_hi[54]
  PIN ba_hi[55]
    DIRECTION OUTPUT ;
    USE SIGNAL ;
    PORT
      LAYER M5 ;
        RECT  22.608 34.368 22.632 34.56 ;
    END
  END ba_hi[55]
  PIN ba_hi[56]
    DIRECTION OUTPUT ;
    USE SIGNAL ;
    PORT
      LAYER M3 ;
        RECT  21.024 34.416 21.042 34.56 ;
    END
  END ba_hi[56]
  PIN ba_hi[57]
    DIRECTION OUTPUT ;
    USE SIGNAL ;
    PORT
      LAYER M5 ;
        RECT  22.704 34.368 22.728 34.56 ;
    END
  END ba_hi[57]
  PIN ba_hi[58]
    DIRECTION OUTPUT ;
    USE SIGNAL ;
    PORT
      LAYER M3 ;
        RECT  21.132 34.416 21.15 34.56 ;
    END
  END ba_hi[58]
  PIN ba_hi[59]
    DIRECTION OUTPUT ;
    USE SIGNAL ;
    PORT
      LAYER M5 ;
        RECT  22.8 34.368 22.824 34.56 ;
    END
  END ba_hi[59]
  PIN ba_hi[5]
    DIRECTION OUTPUT ;
    USE SIGNAL ;
    PORT
      LAYER M5 ;
        RECT  20.208 34.368 20.232 34.56 ;
    END
  END ba_hi[5]
  PIN ba_hi[60]
    DIRECTION OUTPUT ;
    USE SIGNAL ;
    PORT
      LAYER M3 ;
        RECT  21.24 34.416 21.258 34.56 ;
    END
  END ba_hi[60]
  PIN ba_hi[61]
    DIRECTION OUTPUT ;
    USE SIGNAL ;
    PORT
      LAYER M5 ;
        RECT  22.896 34.368 22.92 34.56 ;
    END
  END ba_hi[61]
  PIN ba_hi[62]
    DIRECTION OUTPUT ;
    USE SIGNAL ;
    PORT
      LAYER M3 ;
        RECT  21.348 34.416 21.366 34.56 ;
    END
  END ba_hi[62]
  PIN ba_hi[63]
    DIRECTION OUTPUT ;
    USE SIGNAL ;
    PORT
      LAYER M5 ;
        RECT  22.992 34.368 23.016 34.56 ;
    END
  END ba_hi[63]
  PIN ba_hi[64]
    DIRECTION OUTPUT ;
    USE SIGNAL ;
    PORT
      LAYER M3 ;
        RECT  21.456 34.416 21.474 34.56 ;
    END
  END ba_hi[64]
  PIN ba_hi[65]
    DIRECTION OUTPUT ;
    USE SIGNAL ;
    PORT
      LAYER M5 ;
        RECT  23.088 34.368 23.112 34.56 ;
    END
  END ba_hi[65]
  PIN ba_hi[66]
    DIRECTION OUTPUT ;
    USE SIGNAL ;
    PORT
      LAYER M3 ;
        RECT  21.564 34.416 21.582 34.56 ;
    END
  END ba_hi[66]
  PIN ba_hi[67]
    DIRECTION OUTPUT ;
    USE SIGNAL ;
    PORT
      LAYER M5 ;
        RECT  23.184 34.368 23.208 34.56 ;
    END
  END ba_hi[67]
  PIN ba_hi[68]
    DIRECTION OUTPUT ;
    USE SIGNAL ;
    PORT
      LAYER M3 ;
        RECT  21.672 34.416 21.69 34.56 ;
    END
  END ba_hi[68]
  PIN ba_hi[69]
    DIRECTION OUTPUT ;
    USE SIGNAL ;
    PORT
      LAYER M5 ;
        RECT  23.28 34.368 23.304 34.56 ;
    END
  END ba_hi[69]
  PIN ba_hi[6]
    DIRECTION OUTPUT ;
    USE SIGNAL ;
    PORT
      LAYER M3 ;
        RECT  18.324 34.416 18.342 34.56 ;
    END
  END ba_hi[6]
  PIN ba_hi[70]
    DIRECTION OUTPUT ;
    USE SIGNAL ;
    PORT
      LAYER M3 ;
        RECT  21.78 34.416 21.798 34.56 ;
    END
  END ba_hi[70]
  PIN ba_hi[71]
    DIRECTION OUTPUT ;
    USE SIGNAL ;
    PORT
      LAYER M5 ;
        RECT  23.376 34.368 23.4 34.56 ;
    END
  END ba_hi[71]
  PIN ba_hi[72]
    DIRECTION OUTPUT ;
    USE SIGNAL ;
    PORT
      LAYER M3 ;
        RECT  21.888 34.416 21.906 34.56 ;
    END
  END ba_hi[72]
  PIN ba_hi[73]
    DIRECTION OUTPUT ;
    USE SIGNAL ;
    PORT
      LAYER M5 ;
        RECT  23.472 34.368 23.496 34.56 ;
    END
  END ba_hi[73]
  PIN ba_hi[74]
    DIRECTION OUTPUT ;
    USE SIGNAL ;
    PORT
      LAYER M3 ;
        RECT  21.996 34.416 22.014 34.56 ;
    END
  END ba_hi[74]
  PIN ba_hi[75]
    DIRECTION OUTPUT ;
    USE SIGNAL ;
    PORT
      LAYER M5 ;
        RECT  23.568 34.368 23.592 34.56 ;
    END
  END ba_hi[75]
  PIN ba_hi[76]
    DIRECTION OUTPUT ;
    USE SIGNAL ;
    PORT
      LAYER M3 ;
        RECT  22.104 34.416 22.122 34.56 ;
    END
  END ba_hi[76]
  PIN ba_hi[77]
    DIRECTION OUTPUT ;
    USE SIGNAL ;
    PORT
      LAYER M5 ;
        RECT  23.664 34.368 23.688 34.56 ;
    END
  END ba_hi[77]
  PIN ba_hi[78]
    DIRECTION OUTPUT ;
    USE SIGNAL ;
    PORT
      LAYER M3 ;
        RECT  22.212 34.416 22.23 34.56 ;
    END
  END ba_hi[78]
  PIN ba_hi[79]
    DIRECTION OUTPUT ;
    USE SIGNAL ;
    PORT
      LAYER M5 ;
        RECT  23.76 34.368 23.784 34.56 ;
    END
  END ba_hi[79]
  PIN ba_hi[7]
    DIRECTION OUTPUT ;
    USE SIGNAL ;
    PORT
      LAYER M5 ;
        RECT  20.304 34.368 20.328 34.56 ;
    END
  END ba_hi[7]
  PIN ba_hi[80]
    DIRECTION OUTPUT ;
    USE SIGNAL ;
    PORT
      LAYER M3 ;
        RECT  22.32 34.416 22.338 34.56 ;
    END
  END ba_hi[80]
  PIN ba_hi[81]
    DIRECTION OUTPUT ;
    USE SIGNAL ;
    PORT
      LAYER M5 ;
        RECT  23.856 34.368 23.88 34.56 ;
    END
  END ba_hi[81]
  PIN ba_hi[82]
    DIRECTION OUTPUT ;
    USE SIGNAL ;
    PORT
      LAYER M3 ;
        RECT  22.428 34.416 22.446 34.56 ;
    END
  END ba_hi[82]
  PIN ba_hi[83]
    DIRECTION OUTPUT ;
    USE SIGNAL ;
    PORT
      LAYER M5 ;
        RECT  23.952 34.368 23.976 34.56 ;
    END
  END ba_hi[83]
  PIN ba_hi[84]
    DIRECTION OUTPUT ;
    USE SIGNAL ;
    PORT
      LAYER M3 ;
        RECT  22.536 34.416 22.554 34.56 ;
    END
  END ba_hi[84]
  PIN ba_hi[85]
    DIRECTION OUTPUT ;
    USE SIGNAL ;
    PORT
      LAYER M5 ;
        RECT  24.048 34.368 24.072 34.56 ;
    END
  END ba_hi[85]
  PIN ba_hi[86]
    DIRECTION OUTPUT ;
    USE SIGNAL ;
    PORT
      LAYER M3 ;
        RECT  22.644 34.416 22.662 34.56 ;
    END
  END ba_hi[86]
  PIN ba_hi[87]
    DIRECTION OUTPUT ;
    USE SIGNAL ;
    PORT
      LAYER M5 ;
        RECT  24.144 34.368 24.168 34.56 ;
    END
  END ba_hi[87]
  PIN ba_hi[88]
    DIRECTION OUTPUT ;
    USE SIGNAL ;
    PORT
      LAYER M3 ;
        RECT  22.752 34.416 22.77 34.56 ;
    END
  END ba_hi[88]
  PIN ba_hi[89]
    DIRECTION OUTPUT ;
    USE SIGNAL ;
    PORT
      LAYER M5 ;
        RECT  24.24 34.368 24.264 34.56 ;
    END
  END ba_hi[89]
  PIN ba_hi[8]
    DIRECTION OUTPUT ;
    USE SIGNAL ;
    PORT
      LAYER M3 ;
        RECT  18.432 34.416 18.45 34.56 ;
    END
  END ba_hi[8]
  PIN ba_hi[90]
    DIRECTION OUTPUT ;
    USE SIGNAL ;
    PORT
      LAYER M3 ;
        RECT  22.86 34.416 22.878 34.56 ;
    END
  END ba_hi[90]
  PIN ba_hi[91]
    DIRECTION OUTPUT ;
    USE SIGNAL ;
    PORT
      LAYER M5 ;
        RECT  24.336 34.368 24.36 34.56 ;
    END
  END ba_hi[91]
  PIN ba_hi[92]
    DIRECTION OUTPUT ;
    USE SIGNAL ;
    PORT
      LAYER M3 ;
        RECT  22.968 34.416 22.986 34.56 ;
    END
  END ba_hi[92]
  PIN ba_hi[93]
    DIRECTION OUTPUT ;
    USE SIGNAL ;
    PORT
      LAYER M5 ;
        RECT  24.432 34.368 24.456 34.56 ;
    END
  END ba_hi[93]
  PIN ba_hi[94]
    DIRECTION OUTPUT ;
    USE SIGNAL ;
    PORT
      LAYER M3 ;
        RECT  23.076 34.416 23.094 34.56 ;
    END
  END ba_hi[94]
  PIN ba_hi[95]
    DIRECTION OUTPUT ;
    USE SIGNAL ;
    PORT
      LAYER M5 ;
        RECT  24.528 34.368 24.552 34.56 ;
    END
  END ba_hi[95]
  PIN ba_hi[96]
    DIRECTION OUTPUT ;
    USE SIGNAL ;
    PORT
      LAYER M3 ;
        RECT  23.184 34.416 23.202 34.56 ;
    END
  END ba_hi[96]
  PIN ba_hi[97]
    DIRECTION OUTPUT ;
    USE SIGNAL ;
    PORT
      LAYER M5 ;
        RECT  24.624 34.368 24.648 34.56 ;
    END
  END ba_hi[97]
  PIN ba_hi[98]
    DIRECTION OUTPUT ;
    USE SIGNAL ;
    PORT
      LAYER M3 ;
        RECT  23.292 34.416 23.31 34.56 ;
    END
  END ba_hi[98]
  PIN ba_hi[99]
    DIRECTION OUTPUT ;
    USE SIGNAL ;
    PORT
      LAYER M5 ;
        RECT  24.72 34.368 24.744 34.56 ;
    END
  END ba_hi[99]
  PIN ba_hi[9]
    DIRECTION OUTPUT ;
    USE SIGNAL ;
    PORT
      LAYER M5 ;
        RECT  20.4 34.368 20.424 34.56 ;
    END
  END ba_hi[9]
  PIN ba_inc[0]
    DIRECTION OUTPUT ;
    USE SIGNAL ;
    PORT
      LAYER M3 ;
        RECT  50.04 34.416 50.058 34.56 ;
    END
  END ba_inc[0]
  PIN ba_inc[10]
    DIRECTION OUTPUT ;
    USE SIGNAL ;
    PORT
      LAYER M3 ;
        RECT  51.12 34.416 51.138 34.56 ;
    END
  END ba_inc[10]
  PIN ba_inc[11]
    DIRECTION OUTPUT ;
    USE SIGNAL ;
    PORT
      LAYER M3 ;
        RECT  51.228 34.416 51.246 34.56 ;
    END
  END ba_inc[11]
  PIN ba_inc[12]
    DIRECTION OUTPUT ;
    USE SIGNAL ;
    PORT
      LAYER M3 ;
        RECT  51.336 34.416 51.354 34.56 ;
    END
  END ba_inc[12]
  PIN ba_inc[13]
    DIRECTION OUTPUT ;
    USE SIGNAL ;
    PORT
      LAYER M3 ;
        RECT  51.444 34.416 51.462 34.56 ;
    END
  END ba_inc[13]
  PIN ba_inc[14]
    DIRECTION OUTPUT ;
    USE SIGNAL ;
    PORT
      LAYER M3 ;
        RECT  51.552 34.416 51.57 34.56 ;
    END
  END ba_inc[14]
  PIN ba_inc[15]
    DIRECTION OUTPUT ;
    USE SIGNAL ;
    PORT
      LAYER M3 ;
        RECT  51.66 34.416 51.678 34.56 ;
    END
  END ba_inc[15]
  PIN ba_inc[16]
    DIRECTION OUTPUT ;
    USE SIGNAL ;
    PORT
      LAYER M3 ;
        RECT  51.768 34.416 51.786 34.56 ;
    END
  END ba_inc[16]
  PIN ba_inc[17]
    DIRECTION OUTPUT ;
    USE SIGNAL ;
    PORT
      LAYER M3 ;
        RECT  51.876 34.416 51.894 34.56 ;
    END
  END ba_inc[17]
  PIN ba_inc[18]
    DIRECTION OUTPUT ;
    USE SIGNAL ;
    PORT
      LAYER M3 ;
        RECT  51.984 34.416 52.002 34.56 ;
    END
  END ba_inc[18]
  PIN ba_inc[19]
    DIRECTION OUTPUT ;
    USE SIGNAL ;
    PORT
      LAYER M3 ;
        RECT  52.092 34.416 52.11 34.56 ;
    END
  END ba_inc[19]
  PIN ba_inc[1]
    DIRECTION OUTPUT ;
    USE SIGNAL ;
    PORT
      LAYER M3 ;
        RECT  50.148 34.416 50.166 34.56 ;
    END
  END ba_inc[1]
  PIN ba_inc[20]
    DIRECTION OUTPUT ;
    USE SIGNAL ;
    PORT
      LAYER M3 ;
        RECT  52.2 34.416 52.218 34.56 ;
    END
  END ba_inc[20]
  PIN ba_inc[21]
    DIRECTION OUTPUT ;
    USE SIGNAL ;
    PORT
      LAYER M3 ;
        RECT  52.308 34.416 52.326 34.56 ;
    END
  END ba_inc[21]
  PIN ba_inc[22]
    DIRECTION OUTPUT ;
    USE SIGNAL ;
    PORT
      LAYER M3 ;
        RECT  52.416 34.416 52.434 34.56 ;
    END
  END ba_inc[22]
  PIN ba_inc[23]
    DIRECTION OUTPUT ;
    USE SIGNAL ;
    PORT
      LAYER M3 ;
        RECT  52.524 34.416 52.542 34.56 ;
    END
  END ba_inc[23]
  PIN ba_inc[24]
    DIRECTION OUTPUT ;
    USE SIGNAL ;
    PORT
      LAYER M3 ;
        RECT  52.632 34.416 52.65 34.56 ;
    END
  END ba_inc[24]
  PIN ba_inc[25]
    DIRECTION OUTPUT ;
    USE SIGNAL ;
    PORT
      LAYER M3 ;
        RECT  52.74 34.416 52.758 34.56 ;
    END
  END ba_inc[25]
  PIN ba_inc[26]
    DIRECTION OUTPUT ;
    USE SIGNAL ;
    PORT
      LAYER M3 ;
        RECT  52.848 34.416 52.866 34.56 ;
    END
  END ba_inc[26]
  PIN ba_inc[27]
    DIRECTION OUTPUT ;
    USE SIGNAL ;
    PORT
      LAYER M3 ;
        RECT  52.956 34.416 52.974 34.56 ;
    END
  END ba_inc[27]
  PIN ba_inc[28]
    DIRECTION OUTPUT ;
    USE SIGNAL ;
    PORT
      LAYER M3 ;
        RECT  53.064 34.416 53.082 34.56 ;
    END
  END ba_inc[28]
  PIN ba_inc[29]
    DIRECTION OUTPUT ;
    USE SIGNAL ;
    PORT
      LAYER M3 ;
        RECT  53.172 34.416 53.19 34.56 ;
    END
  END ba_inc[29]
  PIN ba_inc[2]
    DIRECTION OUTPUT ;
    USE SIGNAL ;
    PORT
      LAYER M3 ;
        RECT  50.256 34.416 50.274 34.56 ;
    END
  END ba_inc[2]
  PIN ba_inc[30]
    DIRECTION OUTPUT ;
    USE SIGNAL ;
    PORT
      LAYER M3 ;
        RECT  53.28 34.416 53.298 34.56 ;
    END
  END ba_inc[30]
  PIN ba_inc[31]
    DIRECTION OUTPUT ;
    USE SIGNAL ;
    PORT
      LAYER M3 ;
        RECT  53.388 34.416 53.406 34.56 ;
    END
  END ba_inc[31]
  PIN ba_inc[3]
    DIRECTION OUTPUT ;
    USE SIGNAL ;
    PORT
      LAYER M3 ;
        RECT  50.364 34.416 50.382 34.56 ;
    END
  END ba_inc[3]
  PIN ba_inc[4]
    DIRECTION OUTPUT ;
    USE SIGNAL ;
    PORT
      LAYER M3 ;
        RECT  50.472 34.416 50.49 34.56 ;
    END
  END ba_inc[4]
  PIN ba_inc[5]
    DIRECTION OUTPUT ;
    USE SIGNAL ;
    PORT
      LAYER M3 ;
        RECT  50.58 34.416 50.598 34.56 ;
    END
  END ba_inc[5]
  PIN ba_inc[6]
    DIRECTION OUTPUT ;
    USE SIGNAL ;
    PORT
      LAYER M3 ;
        RECT  50.688 34.416 50.706 34.56 ;
    END
  END ba_inc[6]
  PIN ba_inc[7]
    DIRECTION OUTPUT ;
    USE SIGNAL ;
    PORT
      LAYER M3 ;
        RECT  50.796 34.416 50.814 34.56 ;
    END
  END ba_inc[7]
  PIN ba_inc[8]
    DIRECTION OUTPUT ;
    USE SIGNAL ;
    PORT
      LAYER M3 ;
        RECT  50.904 34.416 50.922 34.56 ;
    END
    PORT
      LAYER M3 ;
        RECT  50.832 34.428 50.958 34.493 ;
    END
  END ba_inc[8]
  PIN ba_inc[9]
    DIRECTION OUTPUT ;
    USE SIGNAL ;
    PORT
      LAYER M3 ;
        RECT  51.012 34.416 51.03 34.56 ;
    END
  END ba_inc[9]
  PIN bank_fault[0]
    DIRECTION INPUT ;
    USE SIGNAL ;
    PORT
      LAYER M4 ;
        RECT  73.248 20.736 73.44 20.76 ;
    END
  END bank_fault[0]
  PIN bank_fault[1]
    DIRECTION INPUT ;
    USE SIGNAL ;
    PORT
      LAYER M4 ;
        RECT  73.248 20.88 73.44 20.904 ;
    END
  END bank_fault[1]
  PIN bank_fault[2]
    DIRECTION INPUT ;
    USE SIGNAL ;
    PORT
      LAYER M4 ;
        RECT  73.248 21.024 73.44 21.048 ;
    END
  END bank_fault[2]
  PIN bank_fault[3]
    DIRECTION INPUT ;
    USE SIGNAL ;
    PORT
      LAYER M4 ;
        RECT  73.248 21.168 73.44 21.192 ;
    END
  END bank_fault[3]
  PIN bank_fault[4]
    DIRECTION INPUT ;
    USE SIGNAL ;
    PORT
      LAYER M4 ;
        RECT  73.248 21.312 73.44 21.336 ;
    END
  END bank_fault[4]
  PIN bank_fault[5]
    DIRECTION INPUT ;
    USE SIGNAL ;
    PORT
      LAYER M4 ;
        RECT  73.248 21.456 73.44 21.48 ;
    END
  END bank_fault[5]
  PIN bank_fault[6]
    DIRECTION INPUT ;
    USE SIGNAL ;
    PORT
      LAYER M4 ;
        RECT  73.248 21.6 73.44 21.624 ;
    END
  END bank_fault[6]
  PIN bank_fault[7]
    DIRECTION INPUT ;
    USE SIGNAL ;
    PORT
      LAYER M4 ;
        RECT  73.248 21.744 73.44 21.768 ;
    END
  END bank_fault[7]
  PIN clk
    DIRECTION INPUT ;
    USE SIGNAL ;
    PORT
      LAYER M4 ;
        RECT  0 17.28 0.192 17.304 ;
    END
    PORT
      LAYER M4 ;
        RECT  0.156 17.28 0.275 17.304 ;
    END
  END clk
  PIN fault
    DIRECTION OUTPUT ;
    USE SIGNAL ;
    PORT
      LAYER M4 ;
        RECT  73.248 23.28 73.44 23.304 ;
    END
    PORT
      LAYER M4 ;
        RECT  71.809 23.28 73.26 23.304 ;
    END
  END fault
  PIN rst_n
    DIRECTION INPUT ;
    USE SIGNAL ;
    PORT
      LAYER M4 ;
        RECT  0 16.272 0.192 16.296 ;
    END
    PORT
      LAYER M4 ;
        RECT  0.156 16.272 0.245 16.296 ;
    END
  END rst_n
  PIN xw[0]
    DIRECTION INPUT ;
    USE SIGNAL ;
    PORT
      LAYER M3 ;
        RECT  9 0 9.018 0.144 ;
    END
  END xw[0]
  PIN xw[1000]
    DIRECTION INPUT ;
    USE SIGNAL ;
    PORT
      LAYER M3 ;
        RECT  63 0 63.018 0.144 ;
    END
  END xw[1000]
  PIN xw[1001]
    DIRECTION INPUT ;
    USE SIGNAL ;
    PORT
      LAYER M5 ;
        RECT  60 0 60.024 0.192 ;
    END
  END xw[1001]
  PIN xw[1002]
    DIRECTION INPUT ;
    USE SIGNAL ;
    PORT
      LAYER M3 ;
        RECT  63.108 0 63.126 0.144 ;
    END
  END xw[1002]
  PIN xw[1003]
    DIRECTION INPUT ;
    USE SIGNAL ;
    PORT
      LAYER M5 ;
        RECT  60.096 0 60.12 0.192 ;
    END
  END xw[1003]
  PIN xw[1004]
    DIRECTION INPUT ;
    USE SIGNAL ;
    PORT
      LAYER M3 ;
        RECT  63.216 0 63.234 0.144 ;
    END
  END xw[1004]
  PIN xw[1005]
    DIRECTION INPUT ;
    USE SIGNAL ;
    PORT
      LAYER M5 ;
        RECT  60.192 0 60.216 0.192 ;
    END
  END xw[1005]
  PIN xw[1006]
    DIRECTION INPUT ;
    USE SIGNAL ;
    PORT
      LAYER M3 ;
        RECT  63.324 0 63.342 0.144 ;
    END
  END xw[1006]
  PIN xw[1007]
    DIRECTION INPUT ;
    USE SIGNAL ;
    PORT
      LAYER M5 ;
        RECT  60.288 0 60.312 0.192 ;
    END
  END xw[1007]
  PIN xw[1008]
    DIRECTION INPUT ;
    USE SIGNAL ;
    PORT
      LAYER M3 ;
        RECT  63.432 0 63.45 0.144 ;
    END
  END xw[1008]
  PIN xw[1009]
    DIRECTION INPUT ;
    USE SIGNAL ;
    PORT
      LAYER M5 ;
        RECT  60.384 0 60.408 0.192 ;
    END
  END xw[1009]
  PIN xw[100]
    DIRECTION INPUT ;
    USE SIGNAL ;
    PORT
      LAYER M3 ;
        RECT  14.4 0 14.418 0.144 ;
    END
  END xw[100]
  PIN xw[1010]
    DIRECTION INPUT ;
    USE SIGNAL ;
    PORT
      LAYER M3 ;
        RECT  63.54 0 63.558 0.144 ;
    END
  END xw[1010]
  PIN xw[1011]
    DIRECTION INPUT ;
    USE SIGNAL ;
    PORT
      LAYER M5 ;
        RECT  60.48 0 60.504 0.192 ;
    END
  END xw[1011]
  PIN xw[1012]
    DIRECTION INPUT ;
    USE SIGNAL ;
    PORT
      LAYER M3 ;
        RECT  63.648 0 63.666 0.144 ;
    END
  END xw[1012]
  PIN xw[1013]
    DIRECTION INPUT ;
    USE SIGNAL ;
    PORT
      LAYER M5 ;
        RECT  60.576 0 60.6 0.192 ;
    END
  END xw[1013]
  PIN xw[1014]
    DIRECTION INPUT ;
    USE SIGNAL ;
    PORT
      LAYER M3 ;
        RECT  63.756 0 63.774 0.144 ;
    END
  END xw[1014]
  PIN xw[1015]
    DIRECTION INPUT ;
    USE SIGNAL ;
    PORT
      LAYER M5 ;
        RECT  60.672 0 60.696 0.192 ;
    END
  END xw[1015]
  PIN xw[1016]
    DIRECTION INPUT ;
    USE SIGNAL ;
    PORT
      LAYER M3 ;
        RECT  63.864 0 63.882 0.144 ;
    END
  END xw[1016]
  PIN xw[1017]
    DIRECTION INPUT ;
    USE SIGNAL ;
    PORT
      LAYER M5 ;
        RECT  60.768 0 60.792 0.192 ;
    END
  END xw[1017]
  PIN xw[1018]
    DIRECTION INPUT ;
    USE SIGNAL ;
    PORT
      LAYER M3 ;
        RECT  63.972 0 63.99 0.144 ;
    END
  END xw[1018]
  PIN xw[1019]
    DIRECTION INPUT ;
    USE SIGNAL ;
    PORT
      LAYER M5 ;
        RECT  60.864 0 60.888 0.192 ;
    END
  END xw[1019]
  PIN xw[101]
    DIRECTION INPUT ;
    USE SIGNAL ;
    PORT
      LAYER M5 ;
        RECT  16.8 0 16.824 0.192 ;
    END
  END xw[101]
  PIN xw[1020]
    DIRECTION INPUT ;
    USE SIGNAL ;
    PORT
      LAYER M3 ;
        RECT  64.08 0 64.098 0.144 ;
    END
  END xw[1020]
  PIN xw[1021]
    DIRECTION INPUT ;
    USE SIGNAL ;
    PORT
      LAYER M5 ;
        RECT  60.96 0 60.984 0.192 ;
    END
  END xw[1021]
  PIN xw[1022]
    DIRECTION INPUT ;
    USE SIGNAL ;
    PORT
      LAYER M3 ;
        RECT  64.188 0 64.206 0.144 ;
    END
  END xw[1022]
  PIN xw[1023]
    DIRECTION INPUT ;
    USE SIGNAL ;
    PORT
      LAYER M5 ;
        RECT  61.056 0 61.08 0.192 ;
    END
  END xw[1023]
  PIN xw[102]
    DIRECTION INPUT ;
    USE SIGNAL ;
    PORT
      LAYER M3 ;
        RECT  14.508 0 14.526 0.144 ;
    END
  END xw[102]
  PIN xw[103]
    DIRECTION INPUT ;
    USE SIGNAL ;
    PORT
      LAYER M5 ;
        RECT  16.896 0 16.92 0.192 ;
    END
  END xw[103]
  PIN xw[104]
    DIRECTION INPUT ;
    USE SIGNAL ;
    PORT
      LAYER M3 ;
        RECT  14.616 0 14.634 0.144 ;
    END
  END xw[104]
  PIN xw[105]
    DIRECTION INPUT ;
    USE SIGNAL ;
    PORT
      LAYER M5 ;
        RECT  16.992 0 17.016 0.192 ;
    END
  END xw[105]
  PIN xw[106]
    DIRECTION INPUT ;
    USE SIGNAL ;
    PORT
      LAYER M3 ;
        RECT  14.724 0 14.742 0.144 ;
    END
  END xw[106]
  PIN xw[107]
    DIRECTION INPUT ;
    USE SIGNAL ;
    PORT
      LAYER M5 ;
        RECT  17.088 0 17.112 0.192 ;
    END
  END xw[107]
  PIN xw[108]
    DIRECTION INPUT ;
    USE SIGNAL ;
    PORT
      LAYER M3 ;
        RECT  14.832 0 14.85 0.144 ;
    END
  END xw[108]
  PIN xw[109]
    DIRECTION INPUT ;
    USE SIGNAL ;
    PORT
      LAYER M5 ;
        RECT  17.184 0 17.208 0.192 ;
    END
  END xw[109]
  PIN xw[10]
    DIRECTION INPUT ;
    USE SIGNAL ;
    PORT
      LAYER M3 ;
        RECT  9.54 0 9.558 0.144 ;
    END
  END xw[10]
  PIN xw[110]
    DIRECTION INPUT ;
    USE SIGNAL ;
    PORT
      LAYER M3 ;
        RECT  14.94 0 14.958 0.144 ;
    END
  END xw[110]
  PIN xw[111]
    DIRECTION INPUT ;
    USE SIGNAL ;
    PORT
      LAYER M5 ;
        RECT  17.28 0 17.304 0.192 ;
    END
  END xw[111]
  PIN xw[112]
    DIRECTION INPUT ;
    USE SIGNAL ;
    PORT
      LAYER M3 ;
        RECT  15.048 0 15.066 0.144 ;
    END
  END xw[112]
  PIN xw[113]
    DIRECTION INPUT ;
    USE SIGNAL ;
    PORT
      LAYER M5 ;
        RECT  17.376 0 17.4 0.192 ;
    END
  END xw[113]
  PIN xw[114]
    DIRECTION INPUT ;
    USE SIGNAL ;
    PORT
      LAYER M3 ;
        RECT  15.156 0 15.174 0.144 ;
    END
  END xw[114]
  PIN xw[115]
    DIRECTION INPUT ;
    USE SIGNAL ;
    PORT
      LAYER M5 ;
        RECT  17.472 0 17.496 0.192 ;
    END
  END xw[115]
  PIN xw[116]
    DIRECTION INPUT ;
    USE SIGNAL ;
    PORT
      LAYER M3 ;
        RECT  15.264 0 15.282 0.144 ;
    END
  END xw[116]
  PIN xw[117]
    DIRECTION INPUT ;
    USE SIGNAL ;
    PORT
      LAYER M5 ;
        RECT  17.568 0 17.592 0.192 ;
    END
  END xw[117]
  PIN xw[118]
    DIRECTION INPUT ;
    USE SIGNAL ;
    PORT
      LAYER M3 ;
        RECT  15.372 0 15.39 0.144 ;
    END
  END xw[118]
  PIN xw[119]
    DIRECTION INPUT ;
    USE SIGNAL ;
    PORT
      LAYER M5 ;
        RECT  17.664 0 17.688 0.192 ;
    END
  END xw[119]
  PIN xw[11]
    DIRECTION INPUT ;
    USE SIGNAL ;
    PORT
      LAYER M5 ;
        RECT  12.48 0 12.504 0.192 ;
    END
  END xw[11]
  PIN xw[120]
    DIRECTION INPUT ;
    USE SIGNAL ;
    PORT
      LAYER M3 ;
        RECT  15.48 0 15.498 0.144 ;
    END
  END xw[120]
  PIN xw[121]
    DIRECTION INPUT ;
    USE SIGNAL ;
    PORT
      LAYER M5 ;
        RECT  17.76 0 17.784 0.192 ;
    END
  END xw[121]
  PIN xw[122]
    DIRECTION INPUT ;
    USE SIGNAL ;
    PORT
      LAYER M3 ;
        RECT  15.588 0 15.606 0.144 ;
    END
  END xw[122]
  PIN xw[123]
    DIRECTION INPUT ;
    USE SIGNAL ;
    PORT
      LAYER M5 ;
        RECT  17.856 0 17.88 0.192 ;
    END
  END xw[123]
  PIN xw[124]
    DIRECTION INPUT ;
    USE SIGNAL ;
    PORT
      LAYER M3 ;
        RECT  15.696 0 15.714 0.144 ;
    END
  END xw[124]
  PIN xw[125]
    DIRECTION INPUT ;
    USE SIGNAL ;
    PORT
      LAYER M5 ;
        RECT  17.952 0 17.976 0.192 ;
    END
  END xw[125]
  PIN xw[126]
    DIRECTION INPUT ;
    USE SIGNAL ;
    PORT
      LAYER M3 ;
        RECT  15.804 0 15.822 0.144 ;
    END
  END xw[126]
  PIN xw[127]
    DIRECTION INPUT ;
    USE SIGNAL ;
    PORT
      LAYER M5 ;
        RECT  18.048 0 18.072 0.192 ;
    END
  END xw[127]
  PIN xw[128]
    DIRECTION INPUT ;
    USE SIGNAL ;
    PORT
      LAYER M3 ;
        RECT  15.912 0 15.93 0.144 ;
    END
  END xw[128]
  PIN xw[129]
    DIRECTION INPUT ;
    USE SIGNAL ;
    PORT
      LAYER M5 ;
        RECT  18.144 0 18.168 0.192 ;
    END
  END xw[129]
  PIN xw[12]
    DIRECTION INPUT ;
    USE SIGNAL ;
    PORT
      LAYER M3 ;
        RECT  9.648 0 9.666 0.144 ;
    END
  END xw[12]
  PIN xw[130]
    DIRECTION INPUT ;
    USE SIGNAL ;
    PORT
      LAYER M3 ;
        RECT  16.02 0 16.038 0.144 ;
    END
  END xw[130]
  PIN xw[131]
    DIRECTION INPUT ;
    USE SIGNAL ;
    PORT
      LAYER M5 ;
        RECT  18.24 0 18.264 0.192 ;
    END
  END xw[131]
  PIN xw[132]
    DIRECTION INPUT ;
    USE SIGNAL ;
    PORT
      LAYER M3 ;
        RECT  16.128 0 16.146 0.144 ;
    END
  END xw[132]
  PIN xw[133]
    DIRECTION INPUT ;
    USE SIGNAL ;
    PORT
      LAYER M5 ;
        RECT  18.336 0 18.36 0.192 ;
    END
  END xw[133]
  PIN xw[134]
    DIRECTION INPUT ;
    USE SIGNAL ;
    PORT
      LAYER M3 ;
        RECT  16.236 0 16.254 0.144 ;
    END
  END xw[134]
  PIN xw[135]
    DIRECTION INPUT ;
    USE SIGNAL ;
    PORT
      LAYER M5 ;
        RECT  18.432 0 18.456 0.192 ;
    END
  END xw[135]
  PIN xw[136]
    DIRECTION INPUT ;
    USE SIGNAL ;
    PORT
      LAYER M3 ;
        RECT  16.344 0 16.362 0.144 ;
    END
  END xw[136]
  PIN xw[137]
    DIRECTION INPUT ;
    USE SIGNAL ;
    PORT
      LAYER M5 ;
        RECT  18.528 0 18.552 0.192 ;
    END
  END xw[137]
  PIN xw[138]
    DIRECTION INPUT ;
    USE SIGNAL ;
    PORT
      LAYER M3 ;
        RECT  16.452 0 16.47 0.144 ;
    END
  END xw[138]
  PIN xw[139]
    DIRECTION INPUT ;
    USE SIGNAL ;
    PORT
      LAYER M5 ;
        RECT  18.624 0 18.648 0.192 ;
    END
  END xw[139]
  PIN xw[13]
    DIRECTION INPUT ;
    USE SIGNAL ;
    PORT
      LAYER M5 ;
        RECT  12.576 0 12.6 0.192 ;
    END
  END xw[13]
  PIN xw[140]
    DIRECTION INPUT ;
    USE SIGNAL ;
    PORT
      LAYER M3 ;
        RECT  16.56 0 16.578 0.144 ;
    END
  END xw[140]
  PIN xw[141]
    DIRECTION INPUT ;
    USE SIGNAL ;
    PORT
      LAYER M5 ;
        RECT  18.72 0 18.744 0.192 ;
    END
  END xw[141]
  PIN xw[142]
    DIRECTION INPUT ;
    USE SIGNAL ;
    PORT
      LAYER M3 ;
        RECT  16.668 0 16.686 0.144 ;
    END
  END xw[142]
  PIN xw[143]
    DIRECTION INPUT ;
    USE SIGNAL ;
    PORT
      LAYER M5 ;
        RECT  18.816 0 18.84 0.192 ;
    END
  END xw[143]
  PIN xw[144]
    DIRECTION INPUT ;
    USE SIGNAL ;
    PORT
      LAYER M3 ;
        RECT  16.776 0 16.794 0.144 ;
    END
  END xw[144]
  PIN xw[145]
    DIRECTION INPUT ;
    USE SIGNAL ;
    PORT
      LAYER M5 ;
        RECT  18.912 0 18.936 0.192 ;
    END
  END xw[145]
  PIN xw[146]
    DIRECTION INPUT ;
    USE SIGNAL ;
    PORT
      LAYER M3 ;
        RECT  16.884 0 16.902 0.144 ;
    END
  END xw[146]
  PIN xw[147]
    DIRECTION INPUT ;
    USE SIGNAL ;
    PORT
      LAYER M5 ;
        RECT  19.008 0 19.032 0.192 ;
    END
  END xw[147]
  PIN xw[148]
    DIRECTION INPUT ;
    USE SIGNAL ;
    PORT
      LAYER M3 ;
        RECT  16.992 0 17.01 0.144 ;
    END
  END xw[148]
  PIN xw[149]
    DIRECTION INPUT ;
    USE SIGNAL ;
    PORT
      LAYER M5 ;
        RECT  19.104 0 19.128 0.192 ;
    END
  END xw[149]
  PIN xw[14]
    DIRECTION INPUT ;
    USE SIGNAL ;
    PORT
      LAYER M3 ;
        RECT  9.756 0 9.774 0.144 ;
    END
  END xw[14]
  PIN xw[150]
    DIRECTION INPUT ;
    USE SIGNAL ;
    PORT
      LAYER M3 ;
        RECT  17.1 0 17.118 0.144 ;
    END
  END xw[150]
  PIN xw[151]
    DIRECTION INPUT ;
    USE SIGNAL ;
    PORT
      LAYER M5 ;
        RECT  19.2 0 19.224 0.192 ;
    END
  END xw[151]
  PIN xw[152]
    DIRECTION INPUT ;
    USE SIGNAL ;
    PORT
      LAYER M3 ;
        RECT  17.208 0 17.226 0.144 ;
    END
  END xw[152]
  PIN xw[153]
    DIRECTION INPUT ;
    USE SIGNAL ;
    PORT
      LAYER M5 ;
        RECT  19.296 0 19.32 0.192 ;
    END
  END xw[153]
  PIN xw[154]
    DIRECTION INPUT ;
    USE SIGNAL ;
    PORT
      LAYER M3 ;
        RECT  17.316 0 17.334 0.144 ;
    END
  END xw[154]
  PIN xw[155]
    DIRECTION INPUT ;
    USE SIGNAL ;
    PORT
      LAYER M5 ;
        RECT  19.392 0 19.416 0.192 ;
    END
  END xw[155]
  PIN xw[156]
    DIRECTION INPUT ;
    USE SIGNAL ;
    PORT
      LAYER M3 ;
        RECT  17.424 0 17.442 0.144 ;
    END
  END xw[156]
  PIN xw[157]
    DIRECTION INPUT ;
    USE SIGNAL ;
    PORT
      LAYER M5 ;
        RECT  19.488 0 19.512 0.192 ;
    END
  END xw[157]
  PIN xw[158]
    DIRECTION INPUT ;
    USE SIGNAL ;
    PORT
      LAYER M3 ;
        RECT  17.532 0 17.55 0.144 ;
    END
  END xw[158]
  PIN xw[159]
    DIRECTION INPUT ;
    USE SIGNAL ;
    PORT
      LAYER M5 ;
        RECT  19.584 0 19.608 0.192 ;
    END
  END xw[159]
  PIN xw[15]
    DIRECTION INPUT ;
    USE SIGNAL ;
    PORT
      LAYER M5 ;
        RECT  12.672 0 12.696 0.192 ;
    END
  END xw[15]
  PIN xw[160]
    DIRECTION INPUT ;
    USE SIGNAL ;
    PORT
      LAYER M3 ;
        RECT  17.64 0 17.658 0.144 ;
    END
  END xw[160]
  PIN xw[161]
    DIRECTION INPUT ;
    USE SIGNAL ;
    PORT
      LAYER M5 ;
        RECT  19.68 0 19.704 0.192 ;
    END
  END xw[161]
  PIN xw[162]
    DIRECTION INPUT ;
    USE SIGNAL ;
    PORT
      LAYER M3 ;
        RECT  17.748 0 17.766 0.144 ;
    END
  END xw[162]
  PIN xw[163]
    DIRECTION INPUT ;
    USE SIGNAL ;
    PORT
      LAYER M5 ;
        RECT  19.776 0 19.8 0.192 ;
    END
  END xw[163]
  PIN xw[164]
    DIRECTION INPUT ;
    USE SIGNAL ;
    PORT
      LAYER M3 ;
        RECT  17.856 0 17.874 0.144 ;
    END
  END xw[164]
  PIN xw[165]
    DIRECTION INPUT ;
    USE SIGNAL ;
    PORT
      LAYER M5 ;
        RECT  19.872 0 19.896 0.192 ;
    END
  END xw[165]
  PIN xw[166]
    DIRECTION INPUT ;
    USE SIGNAL ;
    PORT
      LAYER M3 ;
        RECT  17.964 0 17.982 0.144 ;
    END
  END xw[166]
  PIN xw[167]
    DIRECTION INPUT ;
    USE SIGNAL ;
    PORT
      LAYER M5 ;
        RECT  19.968 0 19.992 0.192 ;
    END
  END xw[167]
  PIN xw[168]
    DIRECTION INPUT ;
    USE SIGNAL ;
    PORT
      LAYER M3 ;
        RECT  18.072 0 18.09 0.144 ;
    END
  END xw[168]
  PIN xw[169]
    DIRECTION INPUT ;
    USE SIGNAL ;
    PORT
      LAYER M5 ;
        RECT  20.064 0 20.088 0.192 ;
    END
  END xw[169]
  PIN xw[16]
    DIRECTION INPUT ;
    USE SIGNAL ;
    PORT
      LAYER M3 ;
        RECT  9.864 0 9.882 0.144 ;
    END
  END xw[16]
  PIN xw[170]
    DIRECTION INPUT ;
    USE SIGNAL ;
    PORT
      LAYER M3 ;
        RECT  18.18 0 18.198 0.144 ;
    END
  END xw[170]
  PIN xw[171]
    DIRECTION INPUT ;
    USE SIGNAL ;
    PORT
      LAYER M5 ;
        RECT  20.16 0 20.184 0.192 ;
    END
  END xw[171]
  PIN xw[172]
    DIRECTION INPUT ;
    USE SIGNAL ;
    PORT
      LAYER M3 ;
        RECT  18.288 0 18.306 0.144 ;
    END
  END xw[172]
  PIN xw[173]
    DIRECTION INPUT ;
    USE SIGNAL ;
    PORT
      LAYER M5 ;
        RECT  20.256 0 20.28 0.192 ;
    END
  END xw[173]
  PIN xw[174]
    DIRECTION INPUT ;
    USE SIGNAL ;
    PORT
      LAYER M3 ;
        RECT  18.396 0 18.414 0.144 ;
    END
  END xw[174]
  PIN xw[175]
    DIRECTION INPUT ;
    USE SIGNAL ;
    PORT
      LAYER M5 ;
        RECT  20.352 0 20.376 0.192 ;
    END
  END xw[175]
  PIN xw[176]
    DIRECTION INPUT ;
    USE SIGNAL ;
    PORT
      LAYER M3 ;
        RECT  18.504 0 18.522 0.144 ;
    END
  END xw[176]
  PIN xw[177]
    DIRECTION INPUT ;
    USE SIGNAL ;
    PORT
      LAYER M5 ;
        RECT  20.448 0 20.472 0.192 ;
    END
  END xw[177]
  PIN xw[178]
    DIRECTION INPUT ;
    USE SIGNAL ;
    PORT
      LAYER M3 ;
        RECT  18.612 0 18.63 0.144 ;
    END
  END xw[178]
  PIN xw[179]
    DIRECTION INPUT ;
    USE SIGNAL ;
    PORT
      LAYER M5 ;
        RECT  20.544 0 20.568 0.192 ;
    END
  END xw[179]
  PIN xw[17]
    DIRECTION INPUT ;
    USE SIGNAL ;
    PORT
      LAYER M5 ;
        RECT  12.768 0 12.792 0.192 ;
    END
  END xw[17]
  PIN xw[180]
    DIRECTION INPUT ;
    USE SIGNAL ;
    PORT
      LAYER M3 ;
        RECT  18.72 0 18.738 0.144 ;
    END
  END xw[180]
  PIN xw[181]
    DIRECTION INPUT ;
    USE SIGNAL ;
    PORT
      LAYER M5 ;
        RECT  20.64 0 20.664 0.192 ;
    END
  END xw[181]
  PIN xw[182]
    DIRECTION INPUT ;
    USE SIGNAL ;
    PORT
      LAYER M3 ;
        RECT  18.828 0 18.846 0.144 ;
    END
  END xw[182]
  PIN xw[183]
    DIRECTION INPUT ;
    USE SIGNAL ;
    PORT
      LAYER M5 ;
        RECT  20.736 0 20.76 0.192 ;
    END
  END xw[183]
  PIN xw[184]
    DIRECTION INPUT ;
    USE SIGNAL ;
    PORT
      LAYER M3 ;
        RECT  18.936 0 18.954 0.144 ;
    END
  END xw[184]
  PIN xw[185]
    DIRECTION INPUT ;
    USE SIGNAL ;
    PORT
      LAYER M5 ;
        RECT  20.832 0 20.856 0.192 ;
    END
  END xw[185]
  PIN xw[186]
    DIRECTION INPUT ;
    USE SIGNAL ;
    PORT
      LAYER M3 ;
        RECT  19.044 0 19.062 0.144 ;
    END
  END xw[186]
  PIN xw[187]
    DIRECTION INPUT ;
    USE SIGNAL ;
    PORT
      LAYER M5 ;
        RECT  20.928 0 20.952 0.192 ;
    END
  END xw[187]
  PIN xw[188]
    DIRECTION INPUT ;
    USE SIGNAL ;
    PORT
      LAYER M3 ;
        RECT  19.152 0 19.17 0.144 ;
    END
  END xw[188]
  PIN xw[189]
    DIRECTION INPUT ;
    USE SIGNAL ;
    PORT
      LAYER M5 ;
        RECT  21.024 0 21.048 0.192 ;
    END
  END xw[189]
  PIN xw[18]
    DIRECTION INPUT ;
    USE SIGNAL ;
    PORT
      LAYER M3 ;
        RECT  9.972 0 9.99 0.144 ;
    END
  END xw[18]
  PIN xw[190]
    DIRECTION INPUT ;
    USE SIGNAL ;
    PORT
      LAYER M3 ;
        RECT  19.26 0 19.278 0.144 ;
    END
  END xw[190]
  PIN xw[191]
    DIRECTION INPUT ;
    USE SIGNAL ;
    PORT
      LAYER M5 ;
        RECT  21.12 0 21.144 0.192 ;
    END
  END xw[191]
  PIN xw[192]
    DIRECTION INPUT ;
    USE SIGNAL ;
    PORT
      LAYER M3 ;
        RECT  19.368 0 19.386 0.144 ;
    END
  END xw[192]
  PIN xw[193]
    DIRECTION INPUT ;
    USE SIGNAL ;
    PORT
      LAYER M5 ;
        RECT  21.216 0 21.24 0.192 ;
    END
  END xw[193]
  PIN xw[194]
    DIRECTION INPUT ;
    USE SIGNAL ;
    PORT
      LAYER M3 ;
        RECT  19.476 0 19.494 0.144 ;
    END
  END xw[194]
  PIN xw[195]
    DIRECTION INPUT ;
    USE SIGNAL ;
    PORT
      LAYER M5 ;
        RECT  21.312 0 21.336 0.192 ;
    END
  END xw[195]
  PIN xw[196]
    DIRECTION INPUT ;
    USE SIGNAL ;
    PORT
      LAYER M3 ;
        RECT  19.584 0 19.602 0.144 ;
    END
  END xw[196]
  PIN xw[197]
    DIRECTION INPUT ;
    USE SIGNAL ;
    PORT
      LAYER M5 ;
        RECT  21.408 0 21.432 0.192 ;
    END
  END xw[197]
  PIN xw[198]
    DIRECTION INPUT ;
    USE SIGNAL ;
    PORT
      LAYER M3 ;
        RECT  19.692 0 19.71 0.144 ;
    END
  END xw[198]
  PIN xw[199]
    DIRECTION INPUT ;
    USE SIGNAL ;
    PORT
      LAYER M5 ;
        RECT  21.504 0 21.528 0.192 ;
    END
  END xw[199]
  PIN xw[19]
    DIRECTION INPUT ;
    USE SIGNAL ;
    PORT
      LAYER M5 ;
        RECT  12.864 0 12.888 0.192 ;
    END
  END xw[19]
  PIN xw[1]
    DIRECTION INPUT ;
    USE SIGNAL ;
    PORT
      LAYER M5 ;
        RECT  12 0 12.024 0.192 ;
    END
  END xw[1]
  PIN xw[200]
    DIRECTION INPUT ;
    USE SIGNAL ;
    PORT
      LAYER M3 ;
        RECT  19.8 0 19.818 0.144 ;
    END
  END xw[200]
  PIN xw[201]
    DIRECTION INPUT ;
    USE SIGNAL ;
    PORT
      LAYER M5 ;
        RECT  21.6 0 21.624 0.192 ;
    END
  END xw[201]
  PIN xw[202]
    DIRECTION INPUT ;
    USE SIGNAL ;
    PORT
      LAYER M3 ;
        RECT  19.908 0 19.926 0.144 ;
    END
  END xw[202]
  PIN xw[203]
    DIRECTION INPUT ;
    USE SIGNAL ;
    PORT
      LAYER M5 ;
        RECT  21.696 0 21.72 0.192 ;
    END
  END xw[203]
  PIN xw[204]
    DIRECTION INPUT ;
    USE SIGNAL ;
    PORT
      LAYER M3 ;
        RECT  20.016 0 20.034 0.144 ;
    END
  END xw[204]
  PIN xw[205]
    DIRECTION INPUT ;
    USE SIGNAL ;
    PORT
      LAYER M5 ;
        RECT  21.792 0 21.816 0.192 ;
    END
  END xw[205]
  PIN xw[206]
    DIRECTION INPUT ;
    USE SIGNAL ;
    PORT
      LAYER M3 ;
        RECT  20.124 0 20.142 0.144 ;
    END
  END xw[206]
  PIN xw[207]
    DIRECTION INPUT ;
    USE SIGNAL ;
    PORT
      LAYER M5 ;
        RECT  21.888 0 21.912 0.192 ;
    END
  END xw[207]
  PIN xw[208]
    DIRECTION INPUT ;
    USE SIGNAL ;
    PORT
      LAYER M3 ;
        RECT  20.232 0 20.25 0.144 ;
    END
  END xw[208]
  PIN xw[209]
    DIRECTION INPUT ;
    USE SIGNAL ;
    PORT
      LAYER M5 ;
        RECT  21.984 0 22.008 0.192 ;
    END
  END xw[209]
  PIN xw[20]
    DIRECTION INPUT ;
    USE SIGNAL ;
    PORT
      LAYER M3 ;
        RECT  10.08 0 10.098 0.144 ;
    END
  END xw[20]
  PIN xw[210]
    DIRECTION INPUT ;
    USE SIGNAL ;
    PORT
      LAYER M3 ;
        RECT  20.34 0 20.358 0.144 ;
    END
  END xw[210]
  PIN xw[211]
    DIRECTION INPUT ;
    USE SIGNAL ;
    PORT
      LAYER M5 ;
        RECT  22.08 0 22.104 0.192 ;
    END
  END xw[211]
  PIN xw[212]
    DIRECTION INPUT ;
    USE SIGNAL ;
    PORT
      LAYER M3 ;
        RECT  20.448 0 20.466 0.144 ;
    END
  END xw[212]
  PIN xw[213]
    DIRECTION INPUT ;
    USE SIGNAL ;
    PORT
      LAYER M5 ;
        RECT  22.176 0 22.2 0.192 ;
    END
  END xw[213]
  PIN xw[214]
    DIRECTION INPUT ;
    USE SIGNAL ;
    PORT
      LAYER M3 ;
        RECT  20.556 0 20.574 0.144 ;
    END
  END xw[214]
  PIN xw[215]
    DIRECTION INPUT ;
    USE SIGNAL ;
    PORT
      LAYER M5 ;
        RECT  22.272 0 22.296 0.192 ;
    END
  END xw[215]
  PIN xw[216]
    DIRECTION INPUT ;
    USE SIGNAL ;
    PORT
      LAYER M3 ;
        RECT  20.664 0 20.682 0.144 ;
    END
  END xw[216]
  PIN xw[217]
    DIRECTION INPUT ;
    USE SIGNAL ;
    PORT
      LAYER M5 ;
        RECT  22.368 0 22.392 0.192 ;
    END
  END xw[217]
  PIN xw[218]
    DIRECTION INPUT ;
    USE SIGNAL ;
    PORT
      LAYER M3 ;
        RECT  20.772 0 20.79 0.144 ;
    END
  END xw[218]
  PIN xw[219]
    DIRECTION INPUT ;
    USE SIGNAL ;
    PORT
      LAYER M5 ;
        RECT  22.464 0 22.488 0.192 ;
    END
  END xw[219]
  PIN xw[21]
    DIRECTION INPUT ;
    USE SIGNAL ;
    PORT
      LAYER M5 ;
        RECT  12.96 0 12.984 0.192 ;
    END
  END xw[21]
  PIN xw[220]
    DIRECTION INPUT ;
    USE SIGNAL ;
    PORT
      LAYER M3 ;
        RECT  20.88 0 20.898 0.144 ;
    END
  END xw[220]
  PIN xw[221]
    DIRECTION INPUT ;
    USE SIGNAL ;
    PORT
      LAYER M5 ;
        RECT  22.56 0 22.584 0.192 ;
    END
  END xw[221]
  PIN xw[222]
    DIRECTION INPUT ;
    USE SIGNAL ;
    PORT
      LAYER M3 ;
        RECT  20.988 0 21.006 0.144 ;
    END
  END xw[222]
  PIN xw[223]
    DIRECTION INPUT ;
    USE SIGNAL ;
    PORT
      LAYER M5 ;
        RECT  22.656 0 22.68 0.192 ;
    END
  END xw[223]
  PIN xw[224]
    DIRECTION INPUT ;
    USE SIGNAL ;
    PORT
      LAYER M3 ;
        RECT  21.096 0 21.114 0.144 ;
    END
  END xw[224]
  PIN xw[225]
    DIRECTION INPUT ;
    USE SIGNAL ;
    PORT
      LAYER M5 ;
        RECT  22.752 0 22.776 0.192 ;
    END
  END xw[225]
  PIN xw[226]
    DIRECTION INPUT ;
    USE SIGNAL ;
    PORT
      LAYER M3 ;
        RECT  21.204 0 21.222 0.144 ;
    END
  END xw[226]
  PIN xw[227]
    DIRECTION INPUT ;
    USE SIGNAL ;
    PORT
      LAYER M5 ;
        RECT  22.848 0 22.872 0.192 ;
    END
  END xw[227]
  PIN xw[228]
    DIRECTION INPUT ;
    USE SIGNAL ;
    PORT
      LAYER M3 ;
        RECT  21.312 0 21.33 0.144 ;
    END
  END xw[228]
  PIN xw[229]
    DIRECTION INPUT ;
    USE SIGNAL ;
    PORT
      LAYER M5 ;
        RECT  22.944 0 22.968 0.192 ;
    END
  END xw[229]
  PIN xw[22]
    DIRECTION INPUT ;
    USE SIGNAL ;
    PORT
      LAYER M3 ;
        RECT  10.188 0 10.206 0.144 ;
    END
  END xw[22]
  PIN xw[230]
    DIRECTION INPUT ;
    USE SIGNAL ;
    PORT
      LAYER M3 ;
        RECT  21.42 0 21.438 0.144 ;
    END
  END xw[230]
  PIN xw[231]
    DIRECTION INPUT ;
    USE SIGNAL ;
    PORT
      LAYER M5 ;
        RECT  23.04 0 23.064 0.192 ;
    END
  END xw[231]
  PIN xw[232]
    DIRECTION INPUT ;
    USE SIGNAL ;
    PORT
      LAYER M3 ;
        RECT  21.528 0 21.546 0.144 ;
    END
  END xw[232]
  PIN xw[233]
    DIRECTION INPUT ;
    USE SIGNAL ;
    PORT
      LAYER M5 ;
        RECT  23.136 0 23.16 0.192 ;
    END
  END xw[233]
  PIN xw[234]
    DIRECTION INPUT ;
    USE SIGNAL ;
    PORT
      LAYER M3 ;
        RECT  21.636 0 21.654 0.144 ;
    END
  END xw[234]
  PIN xw[235]
    DIRECTION INPUT ;
    USE SIGNAL ;
    PORT
      LAYER M5 ;
        RECT  23.232 0 23.256 0.192 ;
    END
  END xw[235]
  PIN xw[236]
    DIRECTION INPUT ;
    USE SIGNAL ;
    PORT
      LAYER M3 ;
        RECT  21.744 0 21.762 0.144 ;
    END
  END xw[236]
  PIN xw[237]
    DIRECTION INPUT ;
    USE SIGNAL ;
    PORT
      LAYER M5 ;
        RECT  23.328 0 23.352 0.192 ;
    END
  END xw[237]
  PIN xw[238]
    DIRECTION INPUT ;
    USE SIGNAL ;
    PORT
      LAYER M3 ;
        RECT  21.852 0 21.87 0.144 ;
    END
  END xw[238]
  PIN xw[239]
    DIRECTION INPUT ;
    USE SIGNAL ;
    PORT
      LAYER M5 ;
        RECT  23.424 0 23.448 0.192 ;
    END
  END xw[239]
  PIN xw[23]
    DIRECTION INPUT ;
    USE SIGNAL ;
    PORT
      LAYER M5 ;
        RECT  13.056 0 13.08 0.192 ;
    END
  END xw[23]
  PIN xw[240]
    DIRECTION INPUT ;
    USE SIGNAL ;
    PORT
      LAYER M3 ;
        RECT  21.96 0 21.978 0.144 ;
    END
  END xw[240]
  PIN xw[241]
    DIRECTION INPUT ;
    USE SIGNAL ;
    PORT
      LAYER M5 ;
        RECT  23.52 0 23.544 0.192 ;
    END
  END xw[241]
  PIN xw[242]
    DIRECTION INPUT ;
    USE SIGNAL ;
    PORT
      LAYER M3 ;
        RECT  22.068 0 22.086 0.144 ;
    END
  END xw[242]
  PIN xw[243]
    DIRECTION INPUT ;
    USE SIGNAL ;
    PORT
      LAYER M5 ;
        RECT  23.616 0 23.64 0.192 ;
    END
  END xw[243]
  PIN xw[244]
    DIRECTION INPUT ;
    USE SIGNAL ;
    PORT
      LAYER M3 ;
        RECT  22.176 0 22.194 0.144 ;
    END
  END xw[244]
  PIN xw[245]
    DIRECTION INPUT ;
    USE SIGNAL ;
    PORT
      LAYER M5 ;
        RECT  23.712 0 23.736 0.192 ;
    END
  END xw[245]
  PIN xw[246]
    DIRECTION INPUT ;
    USE SIGNAL ;
    PORT
      LAYER M3 ;
        RECT  22.284 0 22.302 0.144 ;
    END
  END xw[246]
  PIN xw[247]
    DIRECTION INPUT ;
    USE SIGNAL ;
    PORT
      LAYER M5 ;
        RECT  23.808 0 23.832 0.192 ;
    END
  END xw[247]
  PIN xw[248]
    DIRECTION INPUT ;
    USE SIGNAL ;
    PORT
      LAYER M3 ;
        RECT  22.392 0 22.41 0.144 ;
    END
  END xw[248]
  PIN xw[249]
    DIRECTION INPUT ;
    USE SIGNAL ;
    PORT
      LAYER M5 ;
        RECT  23.904 0 23.928 0.192 ;
    END
  END xw[249]
  PIN xw[24]
    DIRECTION INPUT ;
    USE SIGNAL ;
    PORT
      LAYER M3 ;
        RECT  10.296 0 10.314 0.144 ;
    END
  END xw[24]
  PIN xw[250]
    DIRECTION INPUT ;
    USE SIGNAL ;
    PORT
      LAYER M3 ;
        RECT  22.5 0 22.518 0.144 ;
    END
  END xw[250]
  PIN xw[251]
    DIRECTION INPUT ;
    USE SIGNAL ;
    PORT
      LAYER M5 ;
        RECT  24 0 24.024 0.192 ;
    END
  END xw[251]
  PIN xw[252]
    DIRECTION INPUT ;
    USE SIGNAL ;
    PORT
      LAYER M3 ;
        RECT  22.608 0 22.626 0.144 ;
    END
  END xw[252]
  PIN xw[253]
    DIRECTION INPUT ;
    USE SIGNAL ;
    PORT
      LAYER M5 ;
        RECT  24.096 0 24.12 0.192 ;
    END
  END xw[253]
  PIN xw[254]
    DIRECTION INPUT ;
    USE SIGNAL ;
    PORT
      LAYER M3 ;
        RECT  22.716 0 22.734 0.144 ;
    END
  END xw[254]
  PIN xw[255]
    DIRECTION INPUT ;
    USE SIGNAL ;
    PORT
      LAYER M5 ;
        RECT  24.192 0 24.216 0.192 ;
    END
  END xw[255]
  PIN xw[256]
    DIRECTION INPUT ;
    USE SIGNAL ;
    PORT
      LAYER M3 ;
        RECT  22.824 0 22.842 0.144 ;
    END
  END xw[256]
  PIN xw[257]
    DIRECTION INPUT ;
    USE SIGNAL ;
    PORT
      LAYER M5 ;
        RECT  24.288 0 24.312 0.192 ;
    END
  END xw[257]
  PIN xw[258]
    DIRECTION INPUT ;
    USE SIGNAL ;
    PORT
      LAYER M3 ;
        RECT  22.932 0 22.95 0.144 ;
    END
  END xw[258]
  PIN xw[259]
    DIRECTION INPUT ;
    USE SIGNAL ;
    PORT
      LAYER M5 ;
        RECT  24.384 0 24.408 0.192 ;
    END
  END xw[259]
  PIN xw[25]
    DIRECTION INPUT ;
    USE SIGNAL ;
    PORT
      LAYER M5 ;
        RECT  13.152 0 13.176 0.192 ;
    END
  END xw[25]
  PIN xw[260]
    DIRECTION INPUT ;
    USE SIGNAL ;
    PORT
      LAYER M3 ;
        RECT  23.04 0 23.058 0.144 ;
    END
  END xw[260]
  PIN xw[261]
    DIRECTION INPUT ;
    USE SIGNAL ;
    PORT
      LAYER M5 ;
        RECT  24.48 0 24.504 0.192 ;
    END
  END xw[261]
  PIN xw[262]
    DIRECTION INPUT ;
    USE SIGNAL ;
    PORT
      LAYER M3 ;
        RECT  23.148 0 23.166 0.144 ;
    END
  END xw[262]
  PIN xw[263]
    DIRECTION INPUT ;
    USE SIGNAL ;
    PORT
      LAYER M5 ;
        RECT  24.576 0 24.6 0.192 ;
    END
  END xw[263]
  PIN xw[264]
    DIRECTION INPUT ;
    USE SIGNAL ;
    PORT
      LAYER M3 ;
        RECT  23.256 0 23.274 0.144 ;
    END
  END xw[264]
  PIN xw[265]
    DIRECTION INPUT ;
    USE SIGNAL ;
    PORT
      LAYER M5 ;
        RECT  24.672 0 24.696 0.192 ;
    END
  END xw[265]
  PIN xw[266]
    DIRECTION INPUT ;
    USE SIGNAL ;
    PORT
      LAYER M3 ;
        RECT  23.364 0 23.382 0.144 ;
    END
  END xw[266]
  PIN xw[267]
    DIRECTION INPUT ;
    USE SIGNAL ;
    PORT
      LAYER M5 ;
        RECT  24.768 0 24.792 0.192 ;
    END
  END xw[267]
  PIN xw[268]
    DIRECTION INPUT ;
    USE SIGNAL ;
    PORT
      LAYER M3 ;
        RECT  23.472 0 23.49 0.144 ;
    END
  END xw[268]
  PIN xw[269]
    DIRECTION INPUT ;
    USE SIGNAL ;
    PORT
      LAYER M5 ;
        RECT  24.864 0 24.888 0.192 ;
    END
  END xw[269]
  PIN xw[26]
    DIRECTION INPUT ;
    USE SIGNAL ;
    PORT
      LAYER M3 ;
        RECT  10.404 0 10.422 0.144 ;
    END
  END xw[26]
  PIN xw[270]
    DIRECTION INPUT ;
    USE SIGNAL ;
    PORT
      LAYER M3 ;
        RECT  23.58 0 23.598 0.144 ;
    END
  END xw[270]
  PIN xw[271]
    DIRECTION INPUT ;
    USE SIGNAL ;
    PORT
      LAYER M5 ;
        RECT  24.96 0 24.984 0.192 ;
    END
  END xw[271]
  PIN xw[272]
    DIRECTION INPUT ;
    USE SIGNAL ;
    PORT
      LAYER M3 ;
        RECT  23.688 0 23.706 0.144 ;
    END
  END xw[272]
  PIN xw[273]
    DIRECTION INPUT ;
    USE SIGNAL ;
    PORT
      LAYER M5 ;
        RECT  25.056 0 25.08 0.192 ;
    END
  END xw[273]
  PIN xw[274]
    DIRECTION INPUT ;
    USE SIGNAL ;
    PORT
      LAYER M3 ;
        RECT  23.796 0 23.814 0.144 ;
    END
  END xw[274]
  PIN xw[275]
    DIRECTION INPUT ;
    USE SIGNAL ;
    PORT
      LAYER M5 ;
        RECT  25.152 0 25.176 0.192 ;
    END
  END xw[275]
  PIN xw[276]
    DIRECTION INPUT ;
    USE SIGNAL ;
    PORT
      LAYER M3 ;
        RECT  23.904 0 23.922 0.144 ;
    END
  END xw[276]
  PIN xw[277]
    DIRECTION INPUT ;
    USE SIGNAL ;
    PORT
      LAYER M5 ;
        RECT  25.248 0 25.272 0.192 ;
    END
  END xw[277]
  PIN xw[278]
    DIRECTION INPUT ;
    USE SIGNAL ;
    PORT
      LAYER M3 ;
        RECT  24.012 0 24.03 0.144 ;
    END
  END xw[278]
  PIN xw[279]
    DIRECTION INPUT ;
    USE SIGNAL ;
    PORT
      LAYER M5 ;
        RECT  25.344 0 25.368 0.192 ;
    END
  END xw[279]
  PIN xw[27]
    DIRECTION INPUT ;
    USE SIGNAL ;
    PORT
      LAYER M5 ;
        RECT  13.248 0 13.272 0.192 ;
    END
  END xw[27]
  PIN xw[280]
    DIRECTION INPUT ;
    USE SIGNAL ;
    PORT
      LAYER M3 ;
        RECT  24.12 0 24.138 0.144 ;
    END
  END xw[280]
  PIN xw[281]
    DIRECTION INPUT ;
    USE SIGNAL ;
    PORT
      LAYER M5 ;
        RECT  25.44 0 25.464 0.192 ;
    END
  END xw[281]
  PIN xw[282]
    DIRECTION INPUT ;
    USE SIGNAL ;
    PORT
      LAYER M3 ;
        RECT  24.228 0 24.246 0.144 ;
    END
  END xw[282]
  PIN xw[283]
    DIRECTION INPUT ;
    USE SIGNAL ;
    PORT
      LAYER M5 ;
        RECT  25.536 0 25.56 0.192 ;
    END
  END xw[283]
  PIN xw[284]
    DIRECTION INPUT ;
    USE SIGNAL ;
    PORT
      LAYER M3 ;
        RECT  24.336 0 24.354 0.144 ;
    END
  END xw[284]
  PIN xw[285]
    DIRECTION INPUT ;
    USE SIGNAL ;
    PORT
      LAYER M5 ;
        RECT  25.632 0 25.656 0.192 ;
    END
  END xw[285]
  PIN xw[286]
    DIRECTION INPUT ;
    USE SIGNAL ;
    PORT
      LAYER M3 ;
        RECT  24.444 0 24.462 0.144 ;
    END
  END xw[286]
  PIN xw[287]
    DIRECTION INPUT ;
    USE SIGNAL ;
    PORT
      LAYER M5 ;
        RECT  25.728 0 25.752 0.192 ;
    END
  END xw[287]
  PIN xw[288]
    DIRECTION INPUT ;
    USE SIGNAL ;
    PORT
      LAYER M3 ;
        RECT  24.552 0 24.57 0.144 ;
    END
  END xw[288]
  PIN xw[289]
    DIRECTION INPUT ;
    USE SIGNAL ;
    PORT
      LAYER M5 ;
        RECT  25.824 0 25.848 0.192 ;
    END
  END xw[289]
  PIN xw[28]
    DIRECTION INPUT ;
    USE SIGNAL ;
    PORT
      LAYER M3 ;
        RECT  10.512 0 10.53 0.144 ;
    END
  END xw[28]
  PIN xw[290]
    DIRECTION INPUT ;
    USE SIGNAL ;
    PORT
      LAYER M3 ;
        RECT  24.66 0 24.678 0.144 ;
    END
  END xw[290]
  PIN xw[291]
    DIRECTION INPUT ;
    USE SIGNAL ;
    PORT
      LAYER M5 ;
        RECT  25.92 0 25.944 0.192 ;
    END
  END xw[291]
  PIN xw[292]
    DIRECTION INPUT ;
    USE SIGNAL ;
    PORT
      LAYER M3 ;
        RECT  24.768 0 24.786 0.144 ;
    END
  END xw[292]
  PIN xw[293]
    DIRECTION INPUT ;
    USE SIGNAL ;
    PORT
      LAYER M5 ;
        RECT  26.016 0 26.04 0.192 ;
    END
  END xw[293]
  PIN xw[294]
    DIRECTION INPUT ;
    USE SIGNAL ;
    PORT
      LAYER M3 ;
        RECT  24.876 0 24.894 0.144 ;
    END
  END xw[294]
  PIN xw[295]
    DIRECTION INPUT ;
    USE SIGNAL ;
    PORT
      LAYER M5 ;
        RECT  26.112 0 26.136 0.192 ;
    END
  END xw[295]
  PIN xw[296]
    DIRECTION INPUT ;
    USE SIGNAL ;
    PORT
      LAYER M3 ;
        RECT  24.984 0 25.002 0.144 ;
    END
  END xw[296]
  PIN xw[297]
    DIRECTION INPUT ;
    USE SIGNAL ;
    PORT
      LAYER M5 ;
        RECT  26.208 0 26.232 0.192 ;
    END
  END xw[297]
  PIN xw[298]
    DIRECTION INPUT ;
    USE SIGNAL ;
    PORT
      LAYER M3 ;
        RECT  25.092 0 25.11 0.144 ;
    END
  END xw[298]
  PIN xw[299]
    DIRECTION INPUT ;
    USE SIGNAL ;
    PORT
      LAYER M5 ;
        RECT  26.304 0 26.328 0.192 ;
    END
  END xw[299]
  PIN xw[29]
    DIRECTION INPUT ;
    USE SIGNAL ;
    PORT
      LAYER M5 ;
        RECT  13.344 0 13.368 0.192 ;
    END
  END xw[29]
  PIN xw[2]
    DIRECTION INPUT ;
    USE SIGNAL ;
    PORT
      LAYER M3 ;
        RECT  9.108 0 9.126 0.144 ;
    END
  END xw[2]
  PIN xw[300]
    DIRECTION INPUT ;
    USE SIGNAL ;
    PORT
      LAYER M3 ;
        RECT  25.2 0 25.218 0.144 ;
    END
  END xw[300]
  PIN xw[301]
    DIRECTION INPUT ;
    USE SIGNAL ;
    PORT
      LAYER M5 ;
        RECT  26.4 0 26.424 0.192 ;
    END
  END xw[301]
  PIN xw[302]
    DIRECTION INPUT ;
    USE SIGNAL ;
    PORT
      LAYER M3 ;
        RECT  25.308 0 25.326 0.144 ;
    END
  END xw[302]
  PIN xw[303]
    DIRECTION INPUT ;
    USE SIGNAL ;
    PORT
      LAYER M5 ;
        RECT  26.496 0 26.52 0.192 ;
    END
  END xw[303]
  PIN xw[304]
    DIRECTION INPUT ;
    USE SIGNAL ;
    PORT
      LAYER M3 ;
        RECT  25.416 0 25.434 0.144 ;
    END
  END xw[304]
  PIN xw[305]
    DIRECTION INPUT ;
    USE SIGNAL ;
    PORT
      LAYER M5 ;
        RECT  26.592 0 26.616 0.192 ;
    END
  END xw[305]
  PIN xw[306]
    DIRECTION INPUT ;
    USE SIGNAL ;
    PORT
      LAYER M3 ;
        RECT  25.524 0 25.542 0.144 ;
    END
  END xw[306]
  PIN xw[307]
    DIRECTION INPUT ;
    USE SIGNAL ;
    PORT
      LAYER M5 ;
        RECT  26.688 0 26.712 0.192 ;
    END
  END xw[307]
  PIN xw[308]
    DIRECTION INPUT ;
    USE SIGNAL ;
    PORT
      LAYER M3 ;
        RECT  25.632 0 25.65 0.144 ;
    END
  END xw[308]
  PIN xw[309]
    DIRECTION INPUT ;
    USE SIGNAL ;
    PORT
      LAYER M5 ;
        RECT  26.784 0 26.808 0.192 ;
    END
  END xw[309]
  PIN xw[30]
    DIRECTION INPUT ;
    USE SIGNAL ;
    PORT
      LAYER M3 ;
        RECT  10.62 0 10.638 0.144 ;
    END
  END xw[30]
  PIN xw[310]
    DIRECTION INPUT ;
    USE SIGNAL ;
    PORT
      LAYER M3 ;
        RECT  25.74 0 25.758 0.144 ;
    END
  END xw[310]
  PIN xw[311]
    DIRECTION INPUT ;
    USE SIGNAL ;
    PORT
      LAYER M5 ;
        RECT  26.88 0 26.904 0.192 ;
    END
  END xw[311]
  PIN xw[312]
    DIRECTION INPUT ;
    USE SIGNAL ;
    PORT
      LAYER M3 ;
        RECT  25.848 0 25.866 0.144 ;
    END
  END xw[312]
  PIN xw[313]
    DIRECTION INPUT ;
    USE SIGNAL ;
    PORT
      LAYER M5 ;
        RECT  26.976 0 27 0.192 ;
    END
  END xw[313]
  PIN xw[314]
    DIRECTION INPUT ;
    USE SIGNAL ;
    PORT
      LAYER M3 ;
        RECT  25.956 0 25.974 0.144 ;
    END
  END xw[314]
  PIN xw[315]
    DIRECTION INPUT ;
    USE SIGNAL ;
    PORT
      LAYER M5 ;
        RECT  27.072 0 27.096 0.192 ;
    END
  END xw[315]
  PIN xw[316]
    DIRECTION INPUT ;
    USE SIGNAL ;
    PORT
      LAYER M3 ;
        RECT  26.064 0 26.082 0.144 ;
    END
  END xw[316]
  PIN xw[317]
    DIRECTION INPUT ;
    USE SIGNAL ;
    PORT
      LAYER M5 ;
        RECT  27.168 0 27.192 0.192 ;
    END
  END xw[317]
  PIN xw[318]
    DIRECTION INPUT ;
    USE SIGNAL ;
    PORT
      LAYER M3 ;
        RECT  26.172 0 26.19 0.144 ;
    END
  END xw[318]
  PIN xw[319]
    DIRECTION INPUT ;
    USE SIGNAL ;
    PORT
      LAYER M5 ;
        RECT  27.264 0 27.288 0.192 ;
    END
  END xw[319]
  PIN xw[31]
    DIRECTION INPUT ;
    USE SIGNAL ;
    PORT
      LAYER M5 ;
        RECT  13.44 0 13.464 0.192 ;
    END
  END xw[31]
  PIN xw[320]
    DIRECTION INPUT ;
    USE SIGNAL ;
    PORT
      LAYER M3 ;
        RECT  26.28 0 26.298 0.144 ;
    END
  END xw[320]
  PIN xw[321]
    DIRECTION INPUT ;
    USE SIGNAL ;
    PORT
      LAYER M5 ;
        RECT  27.36 0 27.384 0.192 ;
    END
  END xw[321]
  PIN xw[322]
    DIRECTION INPUT ;
    USE SIGNAL ;
    PORT
      LAYER M3 ;
        RECT  26.388 0 26.406 0.144 ;
    END
  END xw[322]
  PIN xw[323]
    DIRECTION INPUT ;
    USE SIGNAL ;
    PORT
      LAYER M5 ;
        RECT  27.456 0 27.48 0.192 ;
    END
  END xw[323]
  PIN xw[324]
    DIRECTION INPUT ;
    USE SIGNAL ;
    PORT
      LAYER M3 ;
        RECT  26.496 0 26.514 0.144 ;
    END
  END xw[324]
  PIN xw[325]
    DIRECTION INPUT ;
    USE SIGNAL ;
    PORT
      LAYER M5 ;
        RECT  27.552 0 27.576 0.192 ;
    END
  END xw[325]
  PIN xw[326]
    DIRECTION INPUT ;
    USE SIGNAL ;
    PORT
      LAYER M3 ;
        RECT  26.604 0 26.622 0.144 ;
    END
  END xw[326]
  PIN xw[327]
    DIRECTION INPUT ;
    USE SIGNAL ;
    PORT
      LAYER M5 ;
        RECT  27.648 0 27.672 0.192 ;
    END
  END xw[327]
  PIN xw[328]
    DIRECTION INPUT ;
    USE SIGNAL ;
    PORT
      LAYER M3 ;
        RECT  26.712 0 26.73 0.144 ;
    END
  END xw[328]
  PIN xw[329]
    DIRECTION INPUT ;
    USE SIGNAL ;
    PORT
      LAYER M5 ;
        RECT  27.744 0 27.768 0.192 ;
    END
  END xw[329]
  PIN xw[32]
    DIRECTION INPUT ;
    USE SIGNAL ;
    PORT
      LAYER M3 ;
        RECT  10.728 0 10.746 0.144 ;
    END
  END xw[32]
  PIN xw[330]
    DIRECTION INPUT ;
    USE SIGNAL ;
    PORT
      LAYER M3 ;
        RECT  26.82 0 26.838 0.144 ;
    END
  END xw[330]
  PIN xw[331]
    DIRECTION INPUT ;
    USE SIGNAL ;
    PORT
      LAYER M5 ;
        RECT  27.84 0 27.864 0.192 ;
    END
  END xw[331]
  PIN xw[332]
    DIRECTION INPUT ;
    USE SIGNAL ;
    PORT
      LAYER M3 ;
        RECT  26.928 0 26.946 0.144 ;
    END
  END xw[332]
  PIN xw[333]
    DIRECTION INPUT ;
    USE SIGNAL ;
    PORT
      LAYER M5 ;
        RECT  27.936 0 27.96 0.192 ;
    END
  END xw[333]
  PIN xw[334]
    DIRECTION INPUT ;
    USE SIGNAL ;
    PORT
      LAYER M3 ;
        RECT  27.036 0 27.054 0.144 ;
    END
  END xw[334]
  PIN xw[335]
    DIRECTION INPUT ;
    USE SIGNAL ;
    PORT
      LAYER M5 ;
        RECT  28.032 0 28.056 0.192 ;
    END
  END xw[335]
  PIN xw[336]
    DIRECTION INPUT ;
    USE SIGNAL ;
    PORT
      LAYER M3 ;
        RECT  27.144 0 27.162 0.144 ;
    END
  END xw[336]
  PIN xw[337]
    DIRECTION INPUT ;
    USE SIGNAL ;
    PORT
      LAYER M5 ;
        RECT  28.128 0 28.152 0.192 ;
    END
  END xw[337]
  PIN xw[338]
    DIRECTION INPUT ;
    USE SIGNAL ;
    PORT
      LAYER M3 ;
        RECT  27.252 0 27.27 0.144 ;
    END
  END xw[338]
  PIN xw[339]
    DIRECTION INPUT ;
    USE SIGNAL ;
    PORT
      LAYER M5 ;
        RECT  28.224 0 28.248 0.192 ;
    END
  END xw[339]
  PIN xw[33]
    DIRECTION INPUT ;
    USE SIGNAL ;
    PORT
      LAYER M5 ;
        RECT  13.536 0 13.56 0.192 ;
    END
  END xw[33]
  PIN xw[340]
    DIRECTION INPUT ;
    USE SIGNAL ;
    PORT
      LAYER M3 ;
        RECT  27.36 0 27.378 0.144 ;
    END
  END xw[340]
  PIN xw[341]
    DIRECTION INPUT ;
    USE SIGNAL ;
    PORT
      LAYER M5 ;
        RECT  28.32 0 28.344 0.192 ;
    END
  END xw[341]
  PIN xw[342]
    DIRECTION INPUT ;
    USE SIGNAL ;
    PORT
      LAYER M3 ;
        RECT  27.468 0 27.486 0.144 ;
    END
  END xw[342]
  PIN xw[343]
    DIRECTION INPUT ;
    USE SIGNAL ;
    PORT
      LAYER M5 ;
        RECT  28.416 0 28.44 0.192 ;
    END
  END xw[343]
  PIN xw[344]
    DIRECTION INPUT ;
    USE SIGNAL ;
    PORT
      LAYER M3 ;
        RECT  27.576 0 27.594 0.144 ;
    END
  END xw[344]
  PIN xw[345]
    DIRECTION INPUT ;
    USE SIGNAL ;
    PORT
      LAYER M5 ;
        RECT  28.512 0 28.536 0.192 ;
    END
  END xw[345]
  PIN xw[346]
    DIRECTION INPUT ;
    USE SIGNAL ;
    PORT
      LAYER M3 ;
        RECT  27.684 0 27.702 0.144 ;
    END
  END xw[346]
  PIN xw[347]
    DIRECTION INPUT ;
    USE SIGNAL ;
    PORT
      LAYER M5 ;
        RECT  28.608 0 28.632 0.192 ;
    END
  END xw[347]
  PIN xw[348]
    DIRECTION INPUT ;
    USE SIGNAL ;
    PORT
      LAYER M3 ;
        RECT  27.792 0 27.81 0.144 ;
    END
  END xw[348]
  PIN xw[349]
    DIRECTION INPUT ;
    USE SIGNAL ;
    PORT
      LAYER M5 ;
        RECT  28.704 0 28.728 0.192 ;
    END
  END xw[349]
  PIN xw[34]
    DIRECTION INPUT ;
    USE SIGNAL ;
    PORT
      LAYER M3 ;
        RECT  10.836 0 10.854 0.144 ;
    END
  END xw[34]
  PIN xw[350]
    DIRECTION INPUT ;
    USE SIGNAL ;
    PORT
      LAYER M3 ;
        RECT  27.9 0 27.918 0.144 ;
    END
  END xw[350]
  PIN xw[351]
    DIRECTION INPUT ;
    USE SIGNAL ;
    PORT
      LAYER M5 ;
        RECT  28.8 0 28.824 0.192 ;
    END
  END xw[351]
  PIN xw[352]
    DIRECTION INPUT ;
    USE SIGNAL ;
    PORT
      LAYER M3 ;
        RECT  28.008 0 28.026 0.144 ;
    END
  END xw[352]
  PIN xw[353]
    DIRECTION INPUT ;
    USE SIGNAL ;
    PORT
      LAYER M5 ;
        RECT  28.896 0 28.92 0.192 ;
    END
  END xw[353]
  PIN xw[354]
    DIRECTION INPUT ;
    USE SIGNAL ;
    PORT
      LAYER M3 ;
        RECT  28.116 0 28.134 0.144 ;
    END
  END xw[354]
  PIN xw[355]
    DIRECTION INPUT ;
    USE SIGNAL ;
    PORT
      LAYER M5 ;
        RECT  28.992 0 29.016 0.192 ;
    END
  END xw[355]
  PIN xw[356]
    DIRECTION INPUT ;
    USE SIGNAL ;
    PORT
      LAYER M3 ;
        RECT  28.224 0 28.242 0.144 ;
    END
  END xw[356]
  PIN xw[357]
    DIRECTION INPUT ;
    USE SIGNAL ;
    PORT
      LAYER M5 ;
        RECT  29.088 0 29.112 0.192 ;
    END
  END xw[357]
  PIN xw[358]
    DIRECTION INPUT ;
    USE SIGNAL ;
    PORT
      LAYER M3 ;
        RECT  28.332 0 28.35 0.144 ;
    END
  END xw[358]
  PIN xw[359]
    DIRECTION INPUT ;
    USE SIGNAL ;
    PORT
      LAYER M5 ;
        RECT  29.184 0 29.208 0.192 ;
    END
  END xw[359]
  PIN xw[35]
    DIRECTION INPUT ;
    USE SIGNAL ;
    PORT
      LAYER M5 ;
        RECT  13.632 0 13.656 0.192 ;
    END
  END xw[35]
  PIN xw[360]
    DIRECTION INPUT ;
    USE SIGNAL ;
    PORT
      LAYER M3 ;
        RECT  28.44 0 28.458 0.144 ;
    END
  END xw[360]
  PIN xw[361]
    DIRECTION INPUT ;
    USE SIGNAL ;
    PORT
      LAYER M5 ;
        RECT  29.28 0 29.304 0.192 ;
    END
  END xw[361]
  PIN xw[362]
    DIRECTION INPUT ;
    USE SIGNAL ;
    PORT
      LAYER M3 ;
        RECT  28.548 0 28.566 0.144 ;
    END
  END xw[362]
  PIN xw[363]
    DIRECTION INPUT ;
    USE SIGNAL ;
    PORT
      LAYER M5 ;
        RECT  29.376 0 29.4 0.192 ;
    END
  END xw[363]
  PIN xw[364]
    DIRECTION INPUT ;
    USE SIGNAL ;
    PORT
      LAYER M3 ;
        RECT  28.656 0 28.674 0.144 ;
    END
  END xw[364]
  PIN xw[365]
    DIRECTION INPUT ;
    USE SIGNAL ;
    PORT
      LAYER M5 ;
        RECT  29.472 0 29.496 0.192 ;
    END
  END xw[365]
  PIN xw[366]
    DIRECTION INPUT ;
    USE SIGNAL ;
    PORT
      LAYER M3 ;
        RECT  28.764 0 28.782 0.144 ;
    END
  END xw[366]
  PIN xw[367]
    DIRECTION INPUT ;
    USE SIGNAL ;
    PORT
      LAYER M5 ;
        RECT  29.568 0 29.592 0.192 ;
    END
  END xw[367]
  PIN xw[368]
    DIRECTION INPUT ;
    USE SIGNAL ;
    PORT
      LAYER M3 ;
        RECT  28.872 0 28.89 0.144 ;
    END
  END xw[368]
  PIN xw[369]
    DIRECTION INPUT ;
    USE SIGNAL ;
    PORT
      LAYER M5 ;
        RECT  29.664 0 29.688 0.192 ;
    END
  END xw[369]
  PIN xw[36]
    DIRECTION INPUT ;
    USE SIGNAL ;
    PORT
      LAYER M3 ;
        RECT  10.944 0 10.962 0.144 ;
    END
  END xw[36]
  PIN xw[370]
    DIRECTION INPUT ;
    USE SIGNAL ;
    PORT
      LAYER M3 ;
        RECT  28.98 0 28.998 0.144 ;
    END
  END xw[370]
  PIN xw[371]
    DIRECTION INPUT ;
    USE SIGNAL ;
    PORT
      LAYER M5 ;
        RECT  29.76 0 29.784 0.192 ;
    END
  END xw[371]
  PIN xw[372]
    DIRECTION INPUT ;
    USE SIGNAL ;
    PORT
      LAYER M3 ;
        RECT  29.088 0 29.106 0.144 ;
    END
  END xw[372]
  PIN xw[373]
    DIRECTION INPUT ;
    USE SIGNAL ;
    PORT
      LAYER M5 ;
        RECT  29.856 0 29.88 0.192 ;
    END
  END xw[373]
  PIN xw[374]
    DIRECTION INPUT ;
    USE SIGNAL ;
    PORT
      LAYER M3 ;
        RECT  29.196 0 29.214 0.144 ;
    END
  END xw[374]
  PIN xw[375]
    DIRECTION INPUT ;
    USE SIGNAL ;
    PORT
      LAYER M5 ;
        RECT  29.952 0 29.976 0.192 ;
    END
  END xw[375]
  PIN xw[376]
    DIRECTION INPUT ;
    USE SIGNAL ;
    PORT
      LAYER M3 ;
        RECT  29.304 0 29.322 0.144 ;
    END
  END xw[376]
  PIN xw[377]
    DIRECTION INPUT ;
    USE SIGNAL ;
    PORT
      LAYER M5 ;
        RECT  30.048 0 30.072 0.192 ;
    END
  END xw[377]
  PIN xw[378]
    DIRECTION INPUT ;
    USE SIGNAL ;
    PORT
      LAYER M3 ;
        RECT  29.412 0 29.43 0.144 ;
    END
  END xw[378]
  PIN xw[379]
    DIRECTION INPUT ;
    USE SIGNAL ;
    PORT
      LAYER M5 ;
        RECT  30.144 0 30.168 0.192 ;
    END
  END xw[379]
  PIN xw[37]
    DIRECTION INPUT ;
    USE SIGNAL ;
    PORT
      LAYER M5 ;
        RECT  13.728 0 13.752 0.192 ;
    END
  END xw[37]
  PIN xw[380]
    DIRECTION INPUT ;
    USE SIGNAL ;
    PORT
      LAYER M3 ;
        RECT  29.52 0 29.538 0.144 ;
    END
  END xw[380]
  PIN xw[381]
    DIRECTION INPUT ;
    USE SIGNAL ;
    PORT
      LAYER M5 ;
        RECT  30.24 0 30.264 0.192 ;
    END
  END xw[381]
  PIN xw[382]
    DIRECTION INPUT ;
    USE SIGNAL ;
    PORT
      LAYER M3 ;
        RECT  29.628 0 29.646 0.144 ;
    END
  END xw[382]
  PIN xw[383]
    DIRECTION INPUT ;
    USE SIGNAL ;
    PORT
      LAYER M5 ;
        RECT  30.336 0 30.36 0.192 ;
    END
  END xw[383]
  PIN xw[384]
    DIRECTION INPUT ;
    USE SIGNAL ;
    PORT
      LAYER M3 ;
        RECT  29.736 0 29.754 0.144 ;
    END
  END xw[384]
  PIN xw[385]
    DIRECTION INPUT ;
    USE SIGNAL ;
    PORT
      LAYER M5 ;
        RECT  30.432 0 30.456 0.192 ;
    END
  END xw[385]
  PIN xw[386]
    DIRECTION INPUT ;
    USE SIGNAL ;
    PORT
      LAYER M3 ;
        RECT  29.844 0 29.862 0.144 ;
    END
  END xw[386]
  PIN xw[387]
    DIRECTION INPUT ;
    USE SIGNAL ;
    PORT
      LAYER M5 ;
        RECT  30.528 0 30.552 0.192 ;
    END
  END xw[387]
  PIN xw[388]
    DIRECTION INPUT ;
    USE SIGNAL ;
    PORT
      LAYER M3 ;
        RECT  29.952 0 29.97 0.144 ;
    END
  END xw[388]
  PIN xw[389]
    DIRECTION INPUT ;
    USE SIGNAL ;
    PORT
      LAYER M5 ;
        RECT  30.624 0 30.648 0.192 ;
    END
  END xw[389]
  PIN xw[38]
    DIRECTION INPUT ;
    USE SIGNAL ;
    PORT
      LAYER M3 ;
        RECT  11.052 0 11.07 0.144 ;
    END
  END xw[38]
  PIN xw[390]
    DIRECTION INPUT ;
    USE SIGNAL ;
    PORT
      LAYER M3 ;
        RECT  30.06 0 30.078 0.144 ;
    END
  END xw[390]
  PIN xw[391]
    DIRECTION INPUT ;
    USE SIGNAL ;
    PORT
      LAYER M5 ;
        RECT  30.72 0 30.744 0.192 ;
    END
  END xw[391]
  PIN xw[392]
    DIRECTION INPUT ;
    USE SIGNAL ;
    PORT
      LAYER M3 ;
        RECT  30.168 0 30.186 0.144 ;
    END
  END xw[392]
  PIN xw[393]
    DIRECTION INPUT ;
    USE SIGNAL ;
    PORT
      LAYER M5 ;
        RECT  30.816 0 30.84 0.192 ;
    END
  END xw[393]
  PIN xw[394]
    DIRECTION INPUT ;
    USE SIGNAL ;
    PORT
      LAYER M3 ;
        RECT  30.276 0 30.294 0.144 ;
    END
  END xw[394]
  PIN xw[395]
    DIRECTION INPUT ;
    USE SIGNAL ;
    PORT
      LAYER M5 ;
        RECT  30.912 0 30.936 0.192 ;
    END
  END xw[395]
  PIN xw[396]
    DIRECTION INPUT ;
    USE SIGNAL ;
    PORT
      LAYER M3 ;
        RECT  30.384 0 30.402 0.144 ;
    END
  END xw[396]
  PIN xw[397]
    DIRECTION INPUT ;
    USE SIGNAL ;
    PORT
      LAYER M5 ;
        RECT  31.008 0 31.032 0.192 ;
    END
  END xw[397]
  PIN xw[398]
    DIRECTION INPUT ;
    USE SIGNAL ;
    PORT
      LAYER M3 ;
        RECT  30.492 0 30.51 0.144 ;
    END
  END xw[398]
  PIN xw[399]
    DIRECTION INPUT ;
    USE SIGNAL ;
    PORT
      LAYER M5 ;
        RECT  31.104 0 31.128 0.192 ;
    END
  END xw[399]
  PIN xw[39]
    DIRECTION INPUT ;
    USE SIGNAL ;
    PORT
      LAYER M5 ;
        RECT  13.824 0 13.848 0.192 ;
    END
  END xw[39]
  PIN xw[3]
    DIRECTION INPUT ;
    USE SIGNAL ;
    PORT
      LAYER M5 ;
        RECT  12.096 0 12.12 0.192 ;
    END
  END xw[3]
  PIN xw[400]
    DIRECTION INPUT ;
    USE SIGNAL ;
    PORT
      LAYER M3 ;
        RECT  30.6 0 30.618 0.144 ;
    END
  END xw[400]
  PIN xw[401]
    DIRECTION INPUT ;
    USE SIGNAL ;
    PORT
      LAYER M5 ;
        RECT  31.2 0 31.224 0.192 ;
    END
  END xw[401]
  PIN xw[402]
    DIRECTION INPUT ;
    USE SIGNAL ;
    PORT
      LAYER M3 ;
        RECT  30.708 0 30.726 0.144 ;
    END
  END xw[402]
  PIN xw[403]
    DIRECTION INPUT ;
    USE SIGNAL ;
    PORT
      LAYER M5 ;
        RECT  31.296 0 31.32 0.192 ;
    END
  END xw[403]
  PIN xw[404]
    DIRECTION INPUT ;
    USE SIGNAL ;
    PORT
      LAYER M3 ;
        RECT  30.816 0 30.834 0.144 ;
    END
  END xw[404]
  PIN xw[405]
    DIRECTION INPUT ;
    USE SIGNAL ;
    PORT
      LAYER M5 ;
        RECT  31.392 0 31.416 0.192 ;
    END
  END xw[405]
  PIN xw[406]
    DIRECTION INPUT ;
    USE SIGNAL ;
    PORT
      LAYER M3 ;
        RECT  30.924 0 30.942 0.144 ;
    END
  END xw[406]
  PIN xw[407]
    DIRECTION INPUT ;
    USE SIGNAL ;
    PORT
      LAYER M5 ;
        RECT  31.488 0 31.512 0.192 ;
    END
  END xw[407]
  PIN xw[408]
    DIRECTION INPUT ;
    USE SIGNAL ;
    PORT
      LAYER M3 ;
        RECT  31.032 0 31.05 0.144 ;
    END
  END xw[408]
  PIN xw[409]
    DIRECTION INPUT ;
    USE SIGNAL ;
    PORT
      LAYER M5 ;
        RECT  31.584 0 31.608 0.192 ;
    END
  END xw[409]
  PIN xw[40]
    DIRECTION INPUT ;
    USE SIGNAL ;
    PORT
      LAYER M3 ;
        RECT  11.16 0 11.178 0.144 ;
    END
  END xw[40]
  PIN xw[410]
    DIRECTION INPUT ;
    USE SIGNAL ;
    PORT
      LAYER M3 ;
        RECT  31.14 0 31.158 0.144 ;
    END
  END xw[410]
  PIN xw[411]
    DIRECTION INPUT ;
    USE SIGNAL ;
    PORT
      LAYER M5 ;
        RECT  31.68 0 31.704 0.192 ;
    END
  END xw[411]
  PIN xw[412]
    DIRECTION INPUT ;
    USE SIGNAL ;
    PORT
      LAYER M3 ;
        RECT  31.248 0 31.266 0.144 ;
    END
  END xw[412]
  PIN xw[413]
    DIRECTION INPUT ;
    USE SIGNAL ;
    PORT
      LAYER M5 ;
        RECT  31.776 0 31.8 0.192 ;
    END
  END xw[413]
  PIN xw[414]
    DIRECTION INPUT ;
    USE SIGNAL ;
    PORT
      LAYER M3 ;
        RECT  31.356 0 31.374 0.144 ;
    END
  END xw[414]
  PIN xw[415]
    DIRECTION INPUT ;
    USE SIGNAL ;
    PORT
      LAYER M5 ;
        RECT  31.872 0 31.896 0.192 ;
    END
  END xw[415]
  PIN xw[416]
    DIRECTION INPUT ;
    USE SIGNAL ;
    PORT
      LAYER M3 ;
        RECT  31.464 0 31.482 0.144 ;
    END
  END xw[416]
  PIN xw[417]
    DIRECTION INPUT ;
    USE SIGNAL ;
    PORT
      LAYER M5 ;
        RECT  31.968 0 31.992 0.192 ;
    END
  END xw[417]
  PIN xw[418]
    DIRECTION INPUT ;
    USE SIGNAL ;
    PORT
      LAYER M3 ;
        RECT  31.572 0 31.59 0.144 ;
    END
  END xw[418]
  PIN xw[419]
    DIRECTION INPUT ;
    USE SIGNAL ;
    PORT
      LAYER M5 ;
        RECT  32.064 0 32.088 0.192 ;
    END
  END xw[419]
  PIN xw[41]
    DIRECTION INPUT ;
    USE SIGNAL ;
    PORT
      LAYER M5 ;
        RECT  13.92 0 13.944 0.192 ;
    END
  END xw[41]
  PIN xw[420]
    DIRECTION INPUT ;
    USE SIGNAL ;
    PORT
      LAYER M3 ;
        RECT  31.68 0 31.698 0.144 ;
    END
  END xw[420]
  PIN xw[421]
    DIRECTION INPUT ;
    USE SIGNAL ;
    PORT
      LAYER M5 ;
        RECT  32.16 0 32.184 0.192 ;
    END
  END xw[421]
  PIN xw[422]
    DIRECTION INPUT ;
    USE SIGNAL ;
    PORT
      LAYER M3 ;
        RECT  31.788 0 31.806 0.144 ;
    END
  END xw[422]
  PIN xw[423]
    DIRECTION INPUT ;
    USE SIGNAL ;
    PORT
      LAYER M5 ;
        RECT  32.256 0 32.28 0.192 ;
    END
  END xw[423]
  PIN xw[424]
    DIRECTION INPUT ;
    USE SIGNAL ;
    PORT
      LAYER M3 ;
        RECT  31.896 0 31.914 0.144 ;
    END
  END xw[424]
  PIN xw[425]
    DIRECTION INPUT ;
    USE SIGNAL ;
    PORT
      LAYER M5 ;
        RECT  32.352 0 32.376 0.192 ;
    END
  END xw[425]
  PIN xw[426]
    DIRECTION INPUT ;
    USE SIGNAL ;
    PORT
      LAYER M3 ;
        RECT  32.004 0 32.022 0.144 ;
    END
  END xw[426]
  PIN xw[427]
    DIRECTION INPUT ;
    USE SIGNAL ;
    PORT
      LAYER M5 ;
        RECT  32.448 0 32.472 0.192 ;
    END
  END xw[427]
  PIN xw[428]
    DIRECTION INPUT ;
    USE SIGNAL ;
    PORT
      LAYER M3 ;
        RECT  32.112 0 32.13 0.144 ;
    END
  END xw[428]
  PIN xw[429]
    DIRECTION INPUT ;
    USE SIGNAL ;
    PORT
      LAYER M5 ;
        RECT  32.544 0 32.568 0.192 ;
    END
  END xw[429]
  PIN xw[42]
    DIRECTION INPUT ;
    USE SIGNAL ;
    PORT
      LAYER M3 ;
        RECT  11.268 0 11.286 0.144 ;
    END
  END xw[42]
  PIN xw[430]
    DIRECTION INPUT ;
    USE SIGNAL ;
    PORT
      LAYER M3 ;
        RECT  32.22 0 32.238 0.144 ;
    END
  END xw[430]
  PIN xw[431]
    DIRECTION INPUT ;
    USE SIGNAL ;
    PORT
      LAYER M5 ;
        RECT  32.64 0 32.664 0.192 ;
    END
  END xw[431]
  PIN xw[432]
    DIRECTION INPUT ;
    USE SIGNAL ;
    PORT
      LAYER M3 ;
        RECT  32.328 0 32.346 0.144 ;
    END
  END xw[432]
  PIN xw[433]
    DIRECTION INPUT ;
    USE SIGNAL ;
    PORT
      LAYER M5 ;
        RECT  32.736 0 32.76 0.192 ;
    END
  END xw[433]
  PIN xw[434]
    DIRECTION INPUT ;
    USE SIGNAL ;
    PORT
      LAYER M3 ;
        RECT  32.436 0 32.454 0.144 ;
    END
  END xw[434]
  PIN xw[435]
    DIRECTION INPUT ;
    USE SIGNAL ;
    PORT
      LAYER M5 ;
        RECT  32.832 0 32.856 0.192 ;
    END
  END xw[435]
  PIN xw[436]
    DIRECTION INPUT ;
    USE SIGNAL ;
    PORT
      LAYER M3 ;
        RECT  32.544 0 32.562 0.144 ;
    END
  END xw[436]
  PIN xw[437]
    DIRECTION INPUT ;
    USE SIGNAL ;
    PORT
      LAYER M5 ;
        RECT  32.928 0 32.952 0.192 ;
    END
  END xw[437]
  PIN xw[438]
    DIRECTION INPUT ;
    USE SIGNAL ;
    PORT
      LAYER M3 ;
        RECT  32.652 0 32.67 0.144 ;
    END
  END xw[438]
  PIN xw[439]
    DIRECTION INPUT ;
    USE SIGNAL ;
    PORT
      LAYER M5 ;
        RECT  33.024 0 33.048 0.192 ;
    END
  END xw[439]
  PIN xw[43]
    DIRECTION INPUT ;
    USE SIGNAL ;
    PORT
      LAYER M5 ;
        RECT  14.016 0 14.04 0.192 ;
    END
  END xw[43]
  PIN xw[440]
    DIRECTION INPUT ;
    USE SIGNAL ;
    PORT
      LAYER M3 ;
        RECT  32.76 0 32.778 0.144 ;
    END
  END xw[440]
  PIN xw[441]
    DIRECTION INPUT ;
    USE SIGNAL ;
    PORT
      LAYER M5 ;
        RECT  33.12 0 33.144 0.192 ;
    END
  END xw[441]
  PIN xw[442]
    DIRECTION INPUT ;
    USE SIGNAL ;
    PORT
      LAYER M3 ;
        RECT  32.868 0 32.886 0.144 ;
    END
  END xw[442]
  PIN xw[443]
    DIRECTION INPUT ;
    USE SIGNAL ;
    PORT
      LAYER M5 ;
        RECT  33.216 0 33.24 0.192 ;
    END
  END xw[443]
  PIN xw[444]
    DIRECTION INPUT ;
    USE SIGNAL ;
    PORT
      LAYER M3 ;
        RECT  32.976 0 32.994 0.144 ;
    END
  END xw[444]
  PIN xw[445]
    DIRECTION INPUT ;
    USE SIGNAL ;
    PORT
      LAYER M5 ;
        RECT  33.312 0 33.336 0.192 ;
    END
  END xw[445]
  PIN xw[446]
    DIRECTION INPUT ;
    USE SIGNAL ;
    PORT
      LAYER M3 ;
        RECT  33.084 0 33.102 0.144 ;
    END
  END xw[446]
  PIN xw[447]
    DIRECTION INPUT ;
    USE SIGNAL ;
    PORT
      LAYER M5 ;
        RECT  33.408 0 33.432 0.192 ;
    END
  END xw[447]
  PIN xw[448]
    DIRECTION INPUT ;
    USE SIGNAL ;
    PORT
      LAYER M3 ;
        RECT  33.192 0 33.21 0.144 ;
    END
  END xw[448]
  PIN xw[449]
    DIRECTION INPUT ;
    USE SIGNAL ;
    PORT
      LAYER M5 ;
        RECT  33.504 0 33.528 0.192 ;
    END
  END xw[449]
  PIN xw[44]
    DIRECTION INPUT ;
    USE SIGNAL ;
    PORT
      LAYER M3 ;
        RECT  11.376 0 11.394 0.144 ;
    END
  END xw[44]
  PIN xw[450]
    DIRECTION INPUT ;
    USE SIGNAL ;
    PORT
      LAYER M3 ;
        RECT  33.3 0 33.318 0.144 ;
    END
  END xw[450]
  PIN xw[451]
    DIRECTION INPUT ;
    USE SIGNAL ;
    PORT
      LAYER M5 ;
        RECT  33.6 0 33.624 0.192 ;
    END
  END xw[451]
  PIN xw[452]
    DIRECTION INPUT ;
    USE SIGNAL ;
    PORT
      LAYER M3 ;
        RECT  33.408 0 33.426 0.144 ;
    END
  END xw[452]
  PIN xw[453]
    DIRECTION INPUT ;
    USE SIGNAL ;
    PORT
      LAYER M5 ;
        RECT  33.696 0 33.72 0.192 ;
    END
  END xw[453]
  PIN xw[454]
    DIRECTION INPUT ;
    USE SIGNAL ;
    PORT
      LAYER M3 ;
        RECT  33.516 0 33.534 0.144 ;
    END
  END xw[454]
  PIN xw[455]
    DIRECTION INPUT ;
    USE SIGNAL ;
    PORT
      LAYER M5 ;
        RECT  33.792 0 33.816 0.192 ;
    END
  END xw[455]
  PIN xw[456]
    DIRECTION INPUT ;
    USE SIGNAL ;
    PORT
      LAYER M3 ;
        RECT  33.624 0 33.642 0.144 ;
    END
  END xw[456]
  PIN xw[457]
    DIRECTION INPUT ;
    USE SIGNAL ;
    PORT
      LAYER M5 ;
        RECT  33.888 0 33.912 0.192 ;
    END
  END xw[457]
  PIN xw[458]
    DIRECTION INPUT ;
    USE SIGNAL ;
    PORT
      LAYER M3 ;
        RECT  33.732 0 33.75 0.144 ;
    END
  END xw[458]
  PIN xw[459]
    DIRECTION INPUT ;
    USE SIGNAL ;
    PORT
      LAYER M5 ;
        RECT  33.984 0 34.008 0.192 ;
    END
  END xw[459]
  PIN xw[45]
    DIRECTION INPUT ;
    USE SIGNAL ;
    PORT
      LAYER M5 ;
        RECT  14.112 0 14.136 0.192 ;
    END
  END xw[45]
  PIN xw[460]
    DIRECTION INPUT ;
    USE SIGNAL ;
    PORT
      LAYER M3 ;
        RECT  33.84 0 33.858 0.144 ;
    END
  END xw[460]
  PIN xw[461]
    DIRECTION INPUT ;
    USE SIGNAL ;
    PORT
      LAYER M5 ;
        RECT  34.08 0 34.104 0.192 ;
    END
  END xw[461]
  PIN xw[462]
    DIRECTION INPUT ;
    USE SIGNAL ;
    PORT
      LAYER M3 ;
        RECT  33.948 0 33.966 0.144 ;
    END
  END xw[462]
  PIN xw[463]
    DIRECTION INPUT ;
    USE SIGNAL ;
    PORT
      LAYER M5 ;
        RECT  34.176 0 34.2 0.192 ;
    END
  END xw[463]
  PIN xw[464]
    DIRECTION INPUT ;
    USE SIGNAL ;
    PORT
      LAYER M3 ;
        RECT  34.056 0 34.074 0.144 ;
    END
  END xw[464]
  PIN xw[465]
    DIRECTION INPUT ;
    USE SIGNAL ;
    PORT
      LAYER M5 ;
        RECT  34.272 0 34.296 0.192 ;
    END
  END xw[465]
  PIN xw[466]
    DIRECTION INPUT ;
    USE SIGNAL ;
    PORT
      LAYER M3 ;
        RECT  34.164 0 34.182 0.144 ;
    END
  END xw[466]
  PIN xw[467]
    DIRECTION INPUT ;
    USE SIGNAL ;
    PORT
      LAYER M5 ;
        RECT  34.368 0 34.392 0.192 ;
    END
  END xw[467]
  PIN xw[468]
    DIRECTION INPUT ;
    USE SIGNAL ;
    PORT
      LAYER M3 ;
        RECT  34.272 0 34.29 0.144 ;
    END
  END xw[468]
  PIN xw[469]
    DIRECTION INPUT ;
    USE SIGNAL ;
    PORT
      LAYER M5 ;
        RECT  34.464 0 34.488 0.192 ;
    END
  END xw[469]
  PIN xw[46]
    DIRECTION INPUT ;
    USE SIGNAL ;
    PORT
      LAYER M3 ;
        RECT  11.484 0 11.502 0.144 ;
    END
  END xw[46]
  PIN xw[470]
    DIRECTION INPUT ;
    USE SIGNAL ;
    PORT
      LAYER M3 ;
        RECT  34.38 0 34.398 0.144 ;
    END
  END xw[470]
  PIN xw[471]
    DIRECTION INPUT ;
    USE SIGNAL ;
    PORT
      LAYER M5 ;
        RECT  34.56 0 34.584 0.192 ;
    END
  END xw[471]
  PIN xw[472]
    DIRECTION INPUT ;
    USE SIGNAL ;
    PORT
      LAYER M3 ;
        RECT  34.488 0 34.506 0.144 ;
    END
  END xw[472]
  PIN xw[473]
    DIRECTION INPUT ;
    USE SIGNAL ;
    PORT
      LAYER M5 ;
        RECT  34.656 0 34.68 0.192 ;
    END
  END xw[473]
  PIN xw[474]
    DIRECTION INPUT ;
    USE SIGNAL ;
    PORT
      LAYER M3 ;
        RECT  34.596 0 34.614 0.144 ;
    END
  END xw[474]
  PIN xw[475]
    DIRECTION INPUT ;
    USE SIGNAL ;
    PORT
      LAYER M5 ;
        RECT  34.752 0 34.776 0.192 ;
    END
  END xw[475]
  PIN xw[476]
    DIRECTION INPUT ;
    USE SIGNAL ;
    PORT
      LAYER M3 ;
        RECT  34.704 0 34.722 0.144 ;
    END
  END xw[476]
  PIN xw[477]
    DIRECTION INPUT ;
    USE SIGNAL ;
    PORT
      LAYER M5 ;
        RECT  34.848 0 34.872 0.192 ;
    END
  END xw[477]
  PIN xw[478]
    DIRECTION INPUT ;
    USE SIGNAL ;
    PORT
      LAYER M3 ;
        RECT  34.812 0 34.83 0.144 ;
    END
  END xw[478]
  PIN xw[479]
    DIRECTION INPUT ;
    USE SIGNAL ;
    PORT
      LAYER M5 ;
        RECT  34.944 0 34.968 0.192 ;
    END
  END xw[479]
  PIN xw[47]
    DIRECTION INPUT ;
    USE SIGNAL ;
    PORT
      LAYER M5 ;
        RECT  14.208 0 14.232 0.192 ;
    END
  END xw[47]
  PIN xw[480]
    DIRECTION INPUT ;
    USE SIGNAL ;
    PORT
      LAYER M3 ;
        RECT  34.92 0 34.938 0.144 ;
    END
  END xw[480]
  PIN xw[481]
    DIRECTION INPUT ;
    USE SIGNAL ;
    PORT
      LAYER M5 ;
        RECT  35.04 0 35.064 0.192 ;
    END
  END xw[481]
  PIN xw[482]
    DIRECTION INPUT ;
    USE SIGNAL ;
    PORT
      LAYER M3 ;
        RECT  35.028 0 35.046 0.144 ;
    END
  END xw[482]
  PIN xw[483]
    DIRECTION INPUT ;
    USE SIGNAL ;
    PORT
      LAYER M5 ;
        RECT  35.136 0 35.16 0.192 ;
    END
  END xw[483]
  PIN xw[484]
    DIRECTION INPUT ;
    USE SIGNAL ;
    PORT
      LAYER M3 ;
        RECT  35.136 0 35.154 0.144 ;
    END
  END xw[484]
  PIN xw[485]
    DIRECTION INPUT ;
    USE SIGNAL ;
    PORT
      LAYER M5 ;
        RECT  35.232 0 35.256 0.192 ;
    END
  END xw[485]
  PIN xw[486]
    DIRECTION INPUT ;
    USE SIGNAL ;
    PORT
      LAYER M3 ;
        RECT  35.244 0 35.262 0.144 ;
    END
  END xw[486]
  PIN xw[487]
    DIRECTION INPUT ;
    USE SIGNAL ;
    PORT
      LAYER M5 ;
        RECT  35.328 0 35.352 0.192 ;
    END
  END xw[487]
  PIN xw[488]
    DIRECTION INPUT ;
    USE SIGNAL ;
    PORT
      LAYER M3 ;
        RECT  35.352 0 35.37 0.144 ;
    END
  END xw[488]
  PIN xw[489]
    DIRECTION INPUT ;
    USE SIGNAL ;
    PORT
      LAYER M5 ;
        RECT  35.424 0 35.448 0.192 ;
    END
  END xw[489]
  PIN xw[48]
    DIRECTION INPUT ;
    USE SIGNAL ;
    PORT
      LAYER M3 ;
        RECT  11.592 0 11.61 0.144 ;
    END
  END xw[48]
  PIN xw[490]
    DIRECTION INPUT ;
    USE SIGNAL ;
    PORT
      LAYER M3 ;
        RECT  35.46 0 35.478 0.144 ;
    END
  END xw[490]
  PIN xw[491]
    DIRECTION INPUT ;
    USE SIGNAL ;
    PORT
      LAYER M5 ;
        RECT  35.52 0 35.544 0.192 ;
    END
  END xw[491]
  PIN xw[492]
    DIRECTION INPUT ;
    USE SIGNAL ;
    PORT
      LAYER M3 ;
        RECT  35.568 0 35.586 0.144 ;
    END
  END xw[492]
  PIN xw[493]
    DIRECTION INPUT ;
    USE SIGNAL ;
    PORT
      LAYER M5 ;
        RECT  35.616 0 35.64 0.192 ;
    END
  END xw[493]
  PIN xw[494]
    DIRECTION INPUT ;
    USE SIGNAL ;
    PORT
      LAYER M3 ;
        RECT  35.676 0 35.694 0.144 ;
    END
  END xw[494]
  PIN xw[495]
    DIRECTION INPUT ;
    USE SIGNAL ;
    PORT
      LAYER M5 ;
        RECT  35.712 0 35.736 0.192 ;
    END
  END xw[495]
  PIN xw[496]
    DIRECTION INPUT ;
    USE SIGNAL ;
    PORT
      LAYER M3 ;
        RECT  35.784 0 35.802 0.144 ;
    END
  END xw[496]
  PIN xw[497]
    DIRECTION INPUT ;
    USE SIGNAL ;
    PORT
      LAYER M5 ;
        RECT  35.808 0 35.832 0.192 ;
    END
  END xw[497]
  PIN xw[498]
    DIRECTION INPUT ;
    USE SIGNAL ;
    PORT
      LAYER M3 ;
        RECT  35.892 0 35.91 0.144 ;
    END
  END xw[498]
  PIN xw[499]
    DIRECTION INPUT ;
    USE SIGNAL ;
    PORT
      LAYER M5 ;
        RECT  35.904 0 35.928 0.192 ;
    END
  END xw[499]
  PIN xw[49]
    DIRECTION INPUT ;
    USE SIGNAL ;
    PORT
      LAYER M5 ;
        RECT  14.304 0 14.328 0.192 ;
    END
  END xw[49]
  PIN xw[4]
    DIRECTION INPUT ;
    USE SIGNAL ;
    PORT
      LAYER M3 ;
        RECT  9.216 0 9.234 0.144 ;
    END
  END xw[4]
  PIN xw[500]
    DIRECTION INPUT ;
    USE SIGNAL ;
    PORT
      LAYER M3 ;
        RECT  36 0 36.018 0.144 ;
    END
  END xw[500]
  PIN xw[501]
    DIRECTION INPUT ;
    USE SIGNAL ;
    PORT
      LAYER M5 ;
        RECT  36 0 36.024 0.192 ;
    END
  END xw[501]
  PIN xw[502]
    DIRECTION INPUT ;
    USE SIGNAL ;
    PORT
      LAYER M3 ;
        RECT  36.108 0 36.126 0.144 ;
    END
  END xw[502]
  PIN xw[503]
    DIRECTION INPUT ;
    USE SIGNAL ;
    PORT
      LAYER M5 ;
        RECT  36.096 0 36.12 0.192 ;
    END
  END xw[503]
  PIN xw[504]
    DIRECTION INPUT ;
    USE SIGNAL ;
    PORT
      LAYER M3 ;
        RECT  36.216 0 36.234 0.144 ;
    END
  END xw[504]
  PIN xw[505]
    DIRECTION INPUT ;
    USE SIGNAL ;
    PORT
      LAYER M5 ;
        RECT  36.192 0 36.216 0.192 ;
    END
  END xw[505]
  PIN xw[506]
    DIRECTION INPUT ;
    USE SIGNAL ;
    PORT
      LAYER M3 ;
        RECT  36.324 0 36.342 0.144 ;
    END
  END xw[506]
  PIN xw[507]
    DIRECTION INPUT ;
    USE SIGNAL ;
    PORT
      LAYER M5 ;
        RECT  36.288 0 36.312 0.192 ;
    END
  END xw[507]
  PIN xw[508]
    DIRECTION INPUT ;
    USE SIGNAL ;
    PORT
      LAYER M3 ;
        RECT  36.432 0 36.45 0.144 ;
    END
  END xw[508]
  PIN xw[509]
    DIRECTION INPUT ;
    USE SIGNAL ;
    PORT
      LAYER M5 ;
        RECT  36.384 0 36.408 0.192 ;
    END
  END xw[509]
  PIN xw[50]
    DIRECTION INPUT ;
    USE SIGNAL ;
    PORT
      LAYER M3 ;
        RECT  11.7 0 11.718 0.144 ;
    END
  END xw[50]
  PIN xw[510]
    DIRECTION INPUT ;
    USE SIGNAL ;
    PORT
      LAYER M3 ;
        RECT  36.54 0 36.558 0.144 ;
    END
  END xw[510]
  PIN xw[511]
    DIRECTION INPUT ;
    USE SIGNAL ;
    PORT
      LAYER M5 ;
        RECT  36.48 0 36.504 0.192 ;
    END
  END xw[511]
  PIN xw[512]
    DIRECTION INPUT ;
    USE SIGNAL ;
    PORT
      LAYER M3 ;
        RECT  36.648 0 36.666 0.144 ;
    END
  END xw[512]
  PIN xw[513]
    DIRECTION INPUT ;
    USE SIGNAL ;
    PORT
      LAYER M5 ;
        RECT  36.576 0 36.6 0.192 ;
    END
  END xw[513]
  PIN xw[514]
    DIRECTION INPUT ;
    USE SIGNAL ;
    PORT
      LAYER M3 ;
        RECT  36.756 0 36.774 0.144 ;
    END
  END xw[514]
  PIN xw[515]
    DIRECTION INPUT ;
    USE SIGNAL ;
    PORT
      LAYER M5 ;
        RECT  36.672 0 36.696 0.192 ;
    END
  END xw[515]
  PIN xw[516]
    DIRECTION INPUT ;
    USE SIGNAL ;
    PORT
      LAYER M3 ;
        RECT  36.864 0 36.882 0.144 ;
    END
  END xw[516]
  PIN xw[517]
    DIRECTION INPUT ;
    USE SIGNAL ;
    PORT
      LAYER M5 ;
        RECT  36.768 0 36.792 0.192 ;
    END
  END xw[517]
  PIN xw[518]
    DIRECTION INPUT ;
    USE SIGNAL ;
    PORT
      LAYER M3 ;
        RECT  36.972 0 36.99 0.144 ;
    END
  END xw[518]
  PIN xw[519]
    DIRECTION INPUT ;
    USE SIGNAL ;
    PORT
      LAYER M5 ;
        RECT  36.864 0 36.888 0.192 ;
    END
  END xw[519]
  PIN xw[51]
    DIRECTION INPUT ;
    USE SIGNAL ;
    PORT
      LAYER M5 ;
        RECT  14.4 0 14.424 0.192 ;
    END
  END xw[51]
  PIN xw[520]
    DIRECTION INPUT ;
    USE SIGNAL ;
    PORT
      LAYER M3 ;
        RECT  37.08 0 37.098 0.144 ;
    END
  END xw[520]
  PIN xw[521]
    DIRECTION INPUT ;
    USE SIGNAL ;
    PORT
      LAYER M5 ;
        RECT  36.96 0 36.984 0.192 ;
    END
  END xw[521]
  PIN xw[522]
    DIRECTION INPUT ;
    USE SIGNAL ;
    PORT
      LAYER M3 ;
        RECT  37.188 0 37.206 0.144 ;
    END
  END xw[522]
  PIN xw[523]
    DIRECTION INPUT ;
    USE SIGNAL ;
    PORT
      LAYER M5 ;
        RECT  37.056 0 37.08 0.192 ;
    END
  END xw[523]
  PIN xw[524]
    DIRECTION INPUT ;
    USE SIGNAL ;
    PORT
      LAYER M3 ;
        RECT  37.296 0 37.314 0.144 ;
    END
  END xw[524]
  PIN xw[525]
    DIRECTION INPUT ;
    USE SIGNAL ;
    PORT
      LAYER M5 ;
        RECT  37.152 0 37.176 0.192 ;
    END
  END xw[525]
  PIN xw[526]
    DIRECTION INPUT ;
    USE SIGNAL ;
    PORT
      LAYER M3 ;
        RECT  37.404 0 37.422 0.144 ;
    END
  END xw[526]
  PIN xw[527]
    DIRECTION INPUT ;
    USE SIGNAL ;
    PORT
      LAYER M5 ;
        RECT  37.248 0 37.272 0.192 ;
    END
  END xw[527]
  PIN xw[528]
    DIRECTION INPUT ;
    USE SIGNAL ;
    PORT
      LAYER M3 ;
        RECT  37.512 0 37.53 0.144 ;
    END
  END xw[528]
  PIN xw[529]
    DIRECTION INPUT ;
    USE SIGNAL ;
    PORT
      LAYER M5 ;
        RECT  37.344 0 37.368 0.192 ;
    END
  END xw[529]
  PIN xw[52]
    DIRECTION INPUT ;
    USE SIGNAL ;
    PORT
      LAYER M3 ;
        RECT  11.808 0 11.826 0.144 ;
    END
  END xw[52]
  PIN xw[530]
    DIRECTION INPUT ;
    USE SIGNAL ;
    PORT
      LAYER M3 ;
        RECT  37.62 0 37.638 0.144 ;
    END
  END xw[530]
  PIN xw[531]
    DIRECTION INPUT ;
    USE SIGNAL ;
    PORT
      LAYER M5 ;
        RECT  37.44 0 37.464 0.192 ;
    END
  END xw[531]
  PIN xw[532]
    DIRECTION INPUT ;
    USE SIGNAL ;
    PORT
      LAYER M3 ;
        RECT  37.728 0 37.746 0.144 ;
    END
  END xw[532]
  PIN xw[533]
    DIRECTION INPUT ;
    USE SIGNAL ;
    PORT
      LAYER M5 ;
        RECT  37.536 0 37.56 0.192 ;
    END
  END xw[533]
  PIN xw[534]
    DIRECTION INPUT ;
    USE SIGNAL ;
    PORT
      LAYER M3 ;
        RECT  37.836 0 37.854 0.144 ;
    END
  END xw[534]
  PIN xw[535]
    DIRECTION INPUT ;
    USE SIGNAL ;
    PORT
      LAYER M5 ;
        RECT  37.632 0 37.656 0.192 ;
    END
  END xw[535]
  PIN xw[536]
    DIRECTION INPUT ;
    USE SIGNAL ;
    PORT
      LAYER M3 ;
        RECT  37.944 0 37.962 0.144 ;
    END
  END xw[536]
  PIN xw[537]
    DIRECTION INPUT ;
    USE SIGNAL ;
    PORT
      LAYER M5 ;
        RECT  37.728 0 37.752 0.192 ;
    END
  END xw[537]
  PIN xw[538]
    DIRECTION INPUT ;
    USE SIGNAL ;
    PORT
      LAYER M3 ;
        RECT  38.052 0 38.07 0.144 ;
    END
  END xw[538]
  PIN xw[539]
    DIRECTION INPUT ;
    USE SIGNAL ;
    PORT
      LAYER M5 ;
        RECT  37.824 0 37.848 0.192 ;
    END
  END xw[539]
  PIN xw[53]
    DIRECTION INPUT ;
    USE SIGNAL ;
    PORT
      LAYER M5 ;
        RECT  14.496 0 14.52 0.192 ;
    END
  END xw[53]
  PIN xw[540]
    DIRECTION INPUT ;
    USE SIGNAL ;
    PORT
      LAYER M3 ;
        RECT  38.16 0 38.178 0.144 ;
    END
  END xw[540]
  PIN xw[541]
    DIRECTION INPUT ;
    USE SIGNAL ;
    PORT
      LAYER M5 ;
        RECT  37.92 0 37.944 0.192 ;
    END
  END xw[541]
  PIN xw[542]
    DIRECTION INPUT ;
    USE SIGNAL ;
    PORT
      LAYER M3 ;
        RECT  38.268 0 38.286 0.144 ;
    END
  END xw[542]
  PIN xw[543]
    DIRECTION INPUT ;
    USE SIGNAL ;
    PORT
      LAYER M5 ;
        RECT  38.016 0 38.04 0.192 ;
    END
  END xw[543]
  PIN xw[544]
    DIRECTION INPUT ;
    USE SIGNAL ;
    PORT
      LAYER M3 ;
        RECT  38.376 0 38.394 0.144 ;
    END
  END xw[544]
  PIN xw[545]
    DIRECTION INPUT ;
    USE SIGNAL ;
    PORT
      LAYER M5 ;
        RECT  38.112 0 38.136 0.192 ;
    END
  END xw[545]
  PIN xw[546]
    DIRECTION INPUT ;
    USE SIGNAL ;
    PORT
      LAYER M3 ;
        RECT  38.484 0 38.502 0.144 ;
    END
  END xw[546]
  PIN xw[547]
    DIRECTION INPUT ;
    USE SIGNAL ;
    PORT
      LAYER M5 ;
        RECT  38.208 0 38.232 0.192 ;
    END
  END xw[547]
  PIN xw[548]
    DIRECTION INPUT ;
    USE SIGNAL ;
    PORT
      LAYER M3 ;
        RECT  38.592 0 38.61 0.144 ;
    END
  END xw[548]
  PIN xw[549]
    DIRECTION INPUT ;
    USE SIGNAL ;
    PORT
      LAYER M5 ;
        RECT  38.304 0 38.328 0.192 ;
    END
  END xw[549]
  PIN xw[54]
    DIRECTION INPUT ;
    USE SIGNAL ;
    PORT
      LAYER M3 ;
        RECT  11.916 0 11.934 0.144 ;
    END
  END xw[54]
  PIN xw[550]
    DIRECTION INPUT ;
    USE SIGNAL ;
    PORT
      LAYER M3 ;
        RECT  38.7 0 38.718 0.144 ;
    END
  END xw[550]
  PIN xw[551]
    DIRECTION INPUT ;
    USE SIGNAL ;
    PORT
      LAYER M5 ;
        RECT  38.4 0 38.424 0.192 ;
    END
  END xw[551]
  PIN xw[552]
    DIRECTION INPUT ;
    USE SIGNAL ;
    PORT
      LAYER M3 ;
        RECT  38.808 0 38.826 0.144 ;
    END
  END xw[552]
  PIN xw[553]
    DIRECTION INPUT ;
    USE SIGNAL ;
    PORT
      LAYER M5 ;
        RECT  38.496 0 38.52 0.192 ;
    END
  END xw[553]
  PIN xw[554]
    DIRECTION INPUT ;
    USE SIGNAL ;
    PORT
      LAYER M3 ;
        RECT  38.916 0 38.934 0.144 ;
    END
  END xw[554]
  PIN xw[555]
    DIRECTION INPUT ;
    USE SIGNAL ;
    PORT
      LAYER M5 ;
        RECT  38.592 0 38.616 0.192 ;
    END
  END xw[555]
  PIN xw[556]
    DIRECTION INPUT ;
    USE SIGNAL ;
    PORT
      LAYER M3 ;
        RECT  39.024 0 39.042 0.144 ;
    END
  END xw[556]
  PIN xw[557]
    DIRECTION INPUT ;
    USE SIGNAL ;
    PORT
      LAYER M5 ;
        RECT  38.688 0 38.712 0.192 ;
    END
  END xw[557]
  PIN xw[558]
    DIRECTION INPUT ;
    USE SIGNAL ;
    PORT
      LAYER M3 ;
        RECT  39.132 0 39.15 0.144 ;
    END
  END xw[558]
  PIN xw[559]
    DIRECTION INPUT ;
    USE SIGNAL ;
    PORT
      LAYER M5 ;
        RECT  38.784 0 38.808 0.192 ;
    END
  END xw[559]
  PIN xw[55]
    DIRECTION INPUT ;
    USE SIGNAL ;
    PORT
      LAYER M5 ;
        RECT  14.592 0 14.616 0.192 ;
    END
  END xw[55]
  PIN xw[560]
    DIRECTION INPUT ;
    USE SIGNAL ;
    PORT
      LAYER M3 ;
        RECT  39.24 0 39.258 0.144 ;
    END
  END xw[560]
  PIN xw[561]
    DIRECTION INPUT ;
    USE SIGNAL ;
    PORT
      LAYER M5 ;
        RECT  38.88 0 38.904 0.192 ;
    END
  END xw[561]
  PIN xw[562]
    DIRECTION INPUT ;
    USE SIGNAL ;
    PORT
      LAYER M3 ;
        RECT  39.348 0 39.366 0.144 ;
    END
  END xw[562]
  PIN xw[563]
    DIRECTION INPUT ;
    USE SIGNAL ;
    PORT
      LAYER M5 ;
        RECT  38.976 0 39 0.192 ;
    END
  END xw[563]
  PIN xw[564]
    DIRECTION INPUT ;
    USE SIGNAL ;
    PORT
      LAYER M3 ;
        RECT  39.456 0 39.474 0.144 ;
    END
  END xw[564]
  PIN xw[565]
    DIRECTION INPUT ;
    USE SIGNAL ;
    PORT
      LAYER M5 ;
        RECT  39.072 0 39.096 0.192 ;
    END
  END xw[565]
  PIN xw[566]
    DIRECTION INPUT ;
    USE SIGNAL ;
    PORT
      LAYER M3 ;
        RECT  39.564 0 39.582 0.144 ;
    END
  END xw[566]
  PIN xw[567]
    DIRECTION INPUT ;
    USE SIGNAL ;
    PORT
      LAYER M5 ;
        RECT  39.168 0 39.192 0.192 ;
    END
  END xw[567]
  PIN xw[568]
    DIRECTION INPUT ;
    USE SIGNAL ;
    PORT
      LAYER M3 ;
        RECT  39.672 0 39.69 0.144 ;
    END
  END xw[568]
  PIN xw[569]
    DIRECTION INPUT ;
    USE SIGNAL ;
    PORT
      LAYER M5 ;
        RECT  39.264 0 39.288 0.192 ;
    END
  END xw[569]
  PIN xw[56]
    DIRECTION INPUT ;
    USE SIGNAL ;
    PORT
      LAYER M3 ;
        RECT  12.024 0 12.042 0.144 ;
    END
  END xw[56]
  PIN xw[570]
    DIRECTION INPUT ;
    USE SIGNAL ;
    PORT
      LAYER M3 ;
        RECT  39.78 0 39.798 0.144 ;
    END
  END xw[570]
  PIN xw[571]
    DIRECTION INPUT ;
    USE SIGNAL ;
    PORT
      LAYER M5 ;
        RECT  39.36 0 39.384 0.192 ;
    END
  END xw[571]
  PIN xw[572]
    DIRECTION INPUT ;
    USE SIGNAL ;
    PORT
      LAYER M3 ;
        RECT  39.888 0 39.906 0.144 ;
    END
  END xw[572]
  PIN xw[573]
    DIRECTION INPUT ;
    USE SIGNAL ;
    PORT
      LAYER M5 ;
        RECT  39.456 0 39.48 0.192 ;
    END
  END xw[573]
  PIN xw[574]
    DIRECTION INPUT ;
    USE SIGNAL ;
    PORT
      LAYER M3 ;
        RECT  39.996 0 40.014 0.144 ;
    END
  END xw[574]
  PIN xw[575]
    DIRECTION INPUT ;
    USE SIGNAL ;
    PORT
      LAYER M5 ;
        RECT  39.552 0 39.576 0.192 ;
    END
  END xw[575]
  PIN xw[576]
    DIRECTION INPUT ;
    USE SIGNAL ;
    PORT
      LAYER M3 ;
        RECT  40.104 0 40.122 0.144 ;
    END
  END xw[576]
  PIN xw[577]
    DIRECTION INPUT ;
    USE SIGNAL ;
    PORT
      LAYER M5 ;
        RECT  39.648 0 39.672 0.192 ;
    END
  END xw[577]
  PIN xw[578]
    DIRECTION INPUT ;
    USE SIGNAL ;
    PORT
      LAYER M3 ;
        RECT  40.212 0 40.23 0.144 ;
    END
  END xw[578]
  PIN xw[579]
    DIRECTION INPUT ;
    USE SIGNAL ;
    PORT
      LAYER M5 ;
        RECT  39.744 0 39.768 0.192 ;
    END
  END xw[579]
  PIN xw[57]
    DIRECTION INPUT ;
    USE SIGNAL ;
    PORT
      LAYER M5 ;
        RECT  14.688 0 14.712 0.192 ;
    END
  END xw[57]
  PIN xw[580]
    DIRECTION INPUT ;
    USE SIGNAL ;
    PORT
      LAYER M3 ;
        RECT  40.32 0 40.338 0.144 ;
    END
  END xw[580]
  PIN xw[581]
    DIRECTION INPUT ;
    USE SIGNAL ;
    PORT
      LAYER M5 ;
        RECT  39.84 0 39.864 0.192 ;
    END
  END xw[581]
  PIN xw[582]
    DIRECTION INPUT ;
    USE SIGNAL ;
    PORT
      LAYER M3 ;
        RECT  40.428 0 40.446 0.144 ;
    END
  END xw[582]
  PIN xw[583]
    DIRECTION INPUT ;
    USE SIGNAL ;
    PORT
      LAYER M5 ;
        RECT  39.936 0 39.96 0.192 ;
    END
  END xw[583]
  PIN xw[584]
    DIRECTION INPUT ;
    USE SIGNAL ;
    PORT
      LAYER M3 ;
        RECT  40.536 0 40.554 0.144 ;
    END
  END xw[584]
  PIN xw[585]
    DIRECTION INPUT ;
    USE SIGNAL ;
    PORT
      LAYER M5 ;
        RECT  40.032 0 40.056 0.192 ;
    END
  END xw[585]
  PIN xw[586]
    DIRECTION INPUT ;
    USE SIGNAL ;
    PORT
      LAYER M3 ;
        RECT  40.644 0 40.662 0.144 ;
    END
  END xw[586]
  PIN xw[587]
    DIRECTION INPUT ;
    USE SIGNAL ;
    PORT
      LAYER M5 ;
        RECT  40.128 0 40.152 0.192 ;
    END
  END xw[587]
  PIN xw[588]
    DIRECTION INPUT ;
    USE SIGNAL ;
    PORT
      LAYER M3 ;
        RECT  40.752 0 40.77 0.144 ;
    END
  END xw[588]
  PIN xw[589]
    DIRECTION INPUT ;
    USE SIGNAL ;
    PORT
      LAYER M5 ;
        RECT  40.224 0 40.248 0.192 ;
    END
  END xw[589]
  PIN xw[58]
    DIRECTION INPUT ;
    USE SIGNAL ;
    PORT
      LAYER M3 ;
        RECT  12.132 0 12.15 0.144 ;
    END
  END xw[58]
  PIN xw[590]
    DIRECTION INPUT ;
    USE SIGNAL ;
    PORT
      LAYER M3 ;
        RECT  40.86 0 40.878 0.144 ;
    END
  END xw[590]
  PIN xw[591]
    DIRECTION INPUT ;
    USE SIGNAL ;
    PORT
      LAYER M5 ;
        RECT  40.32 0 40.344 0.192 ;
    END
  END xw[591]
  PIN xw[592]
    DIRECTION INPUT ;
    USE SIGNAL ;
    PORT
      LAYER M3 ;
        RECT  40.968 0 40.986 0.144 ;
    END
  END xw[592]
  PIN xw[593]
    DIRECTION INPUT ;
    USE SIGNAL ;
    PORT
      LAYER M5 ;
        RECT  40.416 0 40.44 0.192 ;
    END
  END xw[593]
  PIN xw[594]
    DIRECTION INPUT ;
    USE SIGNAL ;
    PORT
      LAYER M3 ;
        RECT  41.076 0 41.094 0.144 ;
    END
  END xw[594]
  PIN xw[595]
    DIRECTION INPUT ;
    USE SIGNAL ;
    PORT
      LAYER M5 ;
        RECT  40.512 0 40.536 0.192 ;
    END
  END xw[595]
  PIN xw[596]
    DIRECTION INPUT ;
    USE SIGNAL ;
    PORT
      LAYER M3 ;
        RECT  41.184 0 41.202 0.144 ;
    END
  END xw[596]
  PIN xw[597]
    DIRECTION INPUT ;
    USE SIGNAL ;
    PORT
      LAYER M5 ;
        RECT  40.608 0 40.632 0.192 ;
    END
  END xw[597]
  PIN xw[598]
    DIRECTION INPUT ;
    USE SIGNAL ;
    PORT
      LAYER M3 ;
        RECT  41.292 0 41.31 0.144 ;
    END
  END xw[598]
  PIN xw[599]
    DIRECTION INPUT ;
    USE SIGNAL ;
    PORT
      LAYER M5 ;
        RECT  40.704 0 40.728 0.192 ;
    END
  END xw[599]
  PIN xw[59]
    DIRECTION INPUT ;
    USE SIGNAL ;
    PORT
      LAYER M5 ;
        RECT  14.784 0 14.808 0.192 ;
    END
  END xw[59]
  PIN xw[5]
    DIRECTION INPUT ;
    USE SIGNAL ;
    PORT
      LAYER M5 ;
        RECT  12.192 0 12.216 0.192 ;
    END
  END xw[5]
  PIN xw[600]
    DIRECTION INPUT ;
    USE SIGNAL ;
    PORT
      LAYER M3 ;
        RECT  41.4 0 41.418 0.144 ;
    END
  END xw[600]
  PIN xw[601]
    DIRECTION INPUT ;
    USE SIGNAL ;
    PORT
      LAYER M5 ;
        RECT  40.8 0 40.824 0.192 ;
    END
  END xw[601]
  PIN xw[602]
    DIRECTION INPUT ;
    USE SIGNAL ;
    PORT
      LAYER M3 ;
        RECT  41.508 0 41.526 0.144 ;
    END
  END xw[602]
  PIN xw[603]
    DIRECTION INPUT ;
    USE SIGNAL ;
    PORT
      LAYER M5 ;
        RECT  40.896 0 40.92 0.192 ;
    END
  END xw[603]
  PIN xw[604]
    DIRECTION INPUT ;
    USE SIGNAL ;
    PORT
      LAYER M3 ;
        RECT  41.616 0 41.634 0.144 ;
    END
  END xw[604]
  PIN xw[605]
    DIRECTION INPUT ;
    USE SIGNAL ;
    PORT
      LAYER M5 ;
        RECT  40.992 0 41.016 0.192 ;
    END
  END xw[605]
  PIN xw[606]
    DIRECTION INPUT ;
    USE SIGNAL ;
    PORT
      LAYER M3 ;
        RECT  41.724 0 41.742 0.144 ;
    END
  END xw[606]
  PIN xw[607]
    DIRECTION INPUT ;
    USE SIGNAL ;
    PORT
      LAYER M5 ;
        RECT  41.088 0 41.112 0.192 ;
    END
  END xw[607]
  PIN xw[608]
    DIRECTION INPUT ;
    USE SIGNAL ;
    PORT
      LAYER M3 ;
        RECT  41.832 0 41.85 0.144 ;
    END
  END xw[608]
  PIN xw[609]
    DIRECTION INPUT ;
    USE SIGNAL ;
    PORT
      LAYER M5 ;
        RECT  41.184 0 41.208 0.192 ;
    END
  END xw[609]
  PIN xw[60]
    DIRECTION INPUT ;
    USE SIGNAL ;
    PORT
      LAYER M3 ;
        RECT  12.24 0 12.258 0.144 ;
    END
  END xw[60]
  PIN xw[610]
    DIRECTION INPUT ;
    USE SIGNAL ;
    PORT
      LAYER M3 ;
        RECT  41.94 0 41.958 0.144 ;
    END
  END xw[610]
  PIN xw[611]
    DIRECTION INPUT ;
    USE SIGNAL ;
    PORT
      LAYER M5 ;
        RECT  41.28 0 41.304 0.192 ;
    END
  END xw[611]
  PIN xw[612]
    DIRECTION INPUT ;
    USE SIGNAL ;
    PORT
      LAYER M3 ;
        RECT  42.048 0 42.066 0.144 ;
    END
  END xw[612]
  PIN xw[613]
    DIRECTION INPUT ;
    USE SIGNAL ;
    PORT
      LAYER M5 ;
        RECT  41.376 0 41.4 0.192 ;
    END
  END xw[613]
  PIN xw[614]
    DIRECTION INPUT ;
    USE SIGNAL ;
    PORT
      LAYER M3 ;
        RECT  42.156 0 42.174 0.144 ;
    END
  END xw[614]
  PIN xw[615]
    DIRECTION INPUT ;
    USE SIGNAL ;
    PORT
      LAYER M5 ;
        RECT  41.472 0 41.496 0.192 ;
    END
  END xw[615]
  PIN xw[616]
    DIRECTION INPUT ;
    USE SIGNAL ;
    PORT
      LAYER M3 ;
        RECT  42.264 0 42.282 0.144 ;
    END
  END xw[616]
  PIN xw[617]
    DIRECTION INPUT ;
    USE SIGNAL ;
    PORT
      LAYER M5 ;
        RECT  41.568 0 41.592 0.192 ;
    END
  END xw[617]
  PIN xw[618]
    DIRECTION INPUT ;
    USE SIGNAL ;
    PORT
      LAYER M3 ;
        RECT  42.372 0 42.39 0.144 ;
    END
  END xw[618]
  PIN xw[619]
    DIRECTION INPUT ;
    USE SIGNAL ;
    PORT
      LAYER M5 ;
        RECT  41.664 0 41.688 0.192 ;
    END
  END xw[619]
  PIN xw[61]
    DIRECTION INPUT ;
    USE SIGNAL ;
    PORT
      LAYER M5 ;
        RECT  14.88 0 14.904 0.192 ;
    END
  END xw[61]
  PIN xw[620]
    DIRECTION INPUT ;
    USE SIGNAL ;
    PORT
      LAYER M3 ;
        RECT  42.48 0 42.498 0.144 ;
    END
  END xw[620]
  PIN xw[621]
    DIRECTION INPUT ;
    USE SIGNAL ;
    PORT
      LAYER M5 ;
        RECT  41.76 0 41.784 0.192 ;
    END
  END xw[621]
  PIN xw[622]
    DIRECTION INPUT ;
    USE SIGNAL ;
    PORT
      LAYER M3 ;
        RECT  42.588 0 42.606 0.144 ;
    END
  END xw[622]
  PIN xw[623]
    DIRECTION INPUT ;
    USE SIGNAL ;
    PORT
      LAYER M5 ;
        RECT  41.856 0 41.88 0.192 ;
    END
  END xw[623]
  PIN xw[624]
    DIRECTION INPUT ;
    USE SIGNAL ;
    PORT
      LAYER M3 ;
        RECT  42.696 0 42.714 0.144 ;
    END
  END xw[624]
  PIN xw[625]
    DIRECTION INPUT ;
    USE SIGNAL ;
    PORT
      LAYER M5 ;
        RECT  41.952 0 41.976 0.192 ;
    END
  END xw[625]
  PIN xw[626]
    DIRECTION INPUT ;
    USE SIGNAL ;
    PORT
      LAYER M3 ;
        RECT  42.804 0 42.822 0.144 ;
    END
  END xw[626]
  PIN xw[627]
    DIRECTION INPUT ;
    USE SIGNAL ;
    PORT
      LAYER M5 ;
        RECT  42.048 0 42.072 0.192 ;
    END
  END xw[627]
  PIN xw[628]
    DIRECTION INPUT ;
    USE SIGNAL ;
    PORT
      LAYER M3 ;
        RECT  42.912 0 42.93 0.144 ;
    END
  END xw[628]
  PIN xw[629]
    DIRECTION INPUT ;
    USE SIGNAL ;
    PORT
      LAYER M5 ;
        RECT  42.144 0 42.168 0.192 ;
    END
  END xw[629]
  PIN xw[62]
    DIRECTION INPUT ;
    USE SIGNAL ;
    PORT
      LAYER M3 ;
        RECT  12.348 0 12.366 0.144 ;
    END
  END xw[62]
  PIN xw[630]
    DIRECTION INPUT ;
    USE SIGNAL ;
    PORT
      LAYER M3 ;
        RECT  43.02 0 43.038 0.144 ;
    END
  END xw[630]
  PIN xw[631]
    DIRECTION INPUT ;
    USE SIGNAL ;
    PORT
      LAYER M5 ;
        RECT  42.24 0 42.264 0.192 ;
    END
  END xw[631]
  PIN xw[632]
    DIRECTION INPUT ;
    USE SIGNAL ;
    PORT
      LAYER M3 ;
        RECT  43.128 0 43.146 0.144 ;
    END
  END xw[632]
  PIN xw[633]
    DIRECTION INPUT ;
    USE SIGNAL ;
    PORT
      LAYER M5 ;
        RECT  42.336 0 42.36 0.192 ;
    END
  END xw[633]
  PIN xw[634]
    DIRECTION INPUT ;
    USE SIGNAL ;
    PORT
      LAYER M3 ;
        RECT  43.236 0 43.254 0.144 ;
    END
  END xw[634]
  PIN xw[635]
    DIRECTION INPUT ;
    USE SIGNAL ;
    PORT
      LAYER M5 ;
        RECT  42.432 0 42.456 0.192 ;
    END
  END xw[635]
  PIN xw[636]
    DIRECTION INPUT ;
    USE SIGNAL ;
    PORT
      LAYER M3 ;
        RECT  43.344 0 43.362 0.144 ;
    END
  END xw[636]
  PIN xw[637]
    DIRECTION INPUT ;
    USE SIGNAL ;
    PORT
      LAYER M5 ;
        RECT  42.528 0 42.552 0.192 ;
    END
  END xw[637]
  PIN xw[638]
    DIRECTION INPUT ;
    USE SIGNAL ;
    PORT
      LAYER M3 ;
        RECT  43.452 0 43.47 0.144 ;
    END
  END xw[638]
  PIN xw[639]
    DIRECTION INPUT ;
    USE SIGNAL ;
    PORT
      LAYER M5 ;
        RECT  42.624 0 42.648 0.192 ;
    END
  END xw[639]
  PIN xw[63]
    DIRECTION INPUT ;
    USE SIGNAL ;
    PORT
      LAYER M5 ;
        RECT  14.976 0 15 0.192 ;
    END
  END xw[63]
  PIN xw[640]
    DIRECTION INPUT ;
    USE SIGNAL ;
    PORT
      LAYER M3 ;
        RECT  43.56 0 43.578 0.144 ;
    END
  END xw[640]
  PIN xw[641]
    DIRECTION INPUT ;
    USE SIGNAL ;
    PORT
      LAYER M5 ;
        RECT  42.72 0 42.744 0.192 ;
    END
  END xw[641]
  PIN xw[642]
    DIRECTION INPUT ;
    USE SIGNAL ;
    PORT
      LAYER M3 ;
        RECT  43.668 0 43.686 0.144 ;
    END
  END xw[642]
  PIN xw[643]
    DIRECTION INPUT ;
    USE SIGNAL ;
    PORT
      LAYER M5 ;
        RECT  42.816 0 42.84 0.192 ;
    END
  END xw[643]
  PIN xw[644]
    DIRECTION INPUT ;
    USE SIGNAL ;
    PORT
      LAYER M3 ;
        RECT  43.776 0 43.794 0.144 ;
    END
  END xw[644]
  PIN xw[645]
    DIRECTION INPUT ;
    USE SIGNAL ;
    PORT
      LAYER M5 ;
        RECT  42.912 0 42.936 0.192 ;
    END
  END xw[645]
  PIN xw[646]
    DIRECTION INPUT ;
    USE SIGNAL ;
    PORT
      LAYER M3 ;
        RECT  43.884 0 43.902 0.144 ;
    END
  END xw[646]
  PIN xw[647]
    DIRECTION INPUT ;
    USE SIGNAL ;
    PORT
      LAYER M5 ;
        RECT  43.008 0 43.032 0.192 ;
    END
  END xw[647]
  PIN xw[648]
    DIRECTION INPUT ;
    USE SIGNAL ;
    PORT
      LAYER M3 ;
        RECT  43.992 0 44.01 0.144 ;
    END
  END xw[648]
  PIN xw[649]
    DIRECTION INPUT ;
    USE SIGNAL ;
    PORT
      LAYER M5 ;
        RECT  43.104 0 43.128 0.192 ;
    END
  END xw[649]
  PIN xw[64]
    DIRECTION INPUT ;
    USE SIGNAL ;
    PORT
      LAYER M3 ;
        RECT  12.456 0 12.474 0.144 ;
    END
  END xw[64]
  PIN xw[650]
    DIRECTION INPUT ;
    USE SIGNAL ;
    PORT
      LAYER M3 ;
        RECT  44.1 0 44.118 0.144 ;
    END
  END xw[650]
  PIN xw[651]
    DIRECTION INPUT ;
    USE SIGNAL ;
    PORT
      LAYER M5 ;
        RECT  43.2 0 43.224 0.192 ;
    END
  END xw[651]
  PIN xw[652]
    DIRECTION INPUT ;
    USE SIGNAL ;
    PORT
      LAYER M3 ;
        RECT  44.208 0 44.226 0.144 ;
    END
  END xw[652]
  PIN xw[653]
    DIRECTION INPUT ;
    USE SIGNAL ;
    PORT
      LAYER M5 ;
        RECT  43.296 0 43.32 0.192 ;
    END
  END xw[653]
  PIN xw[654]
    DIRECTION INPUT ;
    USE SIGNAL ;
    PORT
      LAYER M3 ;
        RECT  44.316 0 44.334 0.144 ;
    END
  END xw[654]
  PIN xw[655]
    DIRECTION INPUT ;
    USE SIGNAL ;
    PORT
      LAYER M5 ;
        RECT  43.392 0 43.416 0.192 ;
    END
  END xw[655]
  PIN xw[656]
    DIRECTION INPUT ;
    USE SIGNAL ;
    PORT
      LAYER M3 ;
        RECT  44.424 0 44.442 0.144 ;
    END
  END xw[656]
  PIN xw[657]
    DIRECTION INPUT ;
    USE SIGNAL ;
    PORT
      LAYER M5 ;
        RECT  43.488 0 43.512 0.192 ;
    END
  END xw[657]
  PIN xw[658]
    DIRECTION INPUT ;
    USE SIGNAL ;
    PORT
      LAYER M3 ;
        RECT  44.532 0 44.55 0.144 ;
    END
  END xw[658]
  PIN xw[659]
    DIRECTION INPUT ;
    USE SIGNAL ;
    PORT
      LAYER M5 ;
        RECT  43.584 0 43.608 0.192 ;
    END
  END xw[659]
  PIN xw[65]
    DIRECTION INPUT ;
    USE SIGNAL ;
    PORT
      LAYER M5 ;
        RECT  15.072 0 15.096 0.192 ;
    END
  END xw[65]
  PIN xw[660]
    DIRECTION INPUT ;
    USE SIGNAL ;
    PORT
      LAYER M3 ;
        RECT  44.64 0 44.658 0.144 ;
    END
  END xw[660]
  PIN xw[661]
    DIRECTION INPUT ;
    USE SIGNAL ;
    PORT
      LAYER M5 ;
        RECT  43.68 0 43.704 0.192 ;
    END
  END xw[661]
  PIN xw[662]
    DIRECTION INPUT ;
    USE SIGNAL ;
    PORT
      LAYER M3 ;
        RECT  44.748 0 44.766 0.144 ;
    END
  END xw[662]
  PIN xw[663]
    DIRECTION INPUT ;
    USE SIGNAL ;
    PORT
      LAYER M5 ;
        RECT  43.776 0 43.8 0.192 ;
    END
  END xw[663]
  PIN xw[664]
    DIRECTION INPUT ;
    USE SIGNAL ;
    PORT
      LAYER M3 ;
        RECT  44.856 0 44.874 0.144 ;
    END
  END xw[664]
  PIN xw[665]
    DIRECTION INPUT ;
    USE SIGNAL ;
    PORT
      LAYER M5 ;
        RECT  43.872 0 43.896 0.192 ;
    END
  END xw[665]
  PIN xw[666]
    DIRECTION INPUT ;
    USE SIGNAL ;
    PORT
      LAYER M3 ;
        RECT  44.964 0 44.982 0.144 ;
    END
  END xw[666]
  PIN xw[667]
    DIRECTION INPUT ;
    USE SIGNAL ;
    PORT
      LAYER M5 ;
        RECT  43.968 0 43.992 0.192 ;
    END
  END xw[667]
  PIN xw[668]
    DIRECTION INPUT ;
    USE SIGNAL ;
    PORT
      LAYER M3 ;
        RECT  45.072 0 45.09 0.144 ;
    END
  END xw[668]
  PIN xw[669]
    DIRECTION INPUT ;
    USE SIGNAL ;
    PORT
      LAYER M5 ;
        RECT  44.064 0 44.088 0.192 ;
    END
  END xw[669]
  PIN xw[66]
    DIRECTION INPUT ;
    USE SIGNAL ;
    PORT
      LAYER M3 ;
        RECT  12.564 0 12.582 0.144 ;
    END
  END xw[66]
  PIN xw[670]
    DIRECTION INPUT ;
    USE SIGNAL ;
    PORT
      LAYER M3 ;
        RECT  45.18 0 45.198 0.144 ;
    END
  END xw[670]
  PIN xw[671]
    DIRECTION INPUT ;
    USE SIGNAL ;
    PORT
      LAYER M5 ;
        RECT  44.16 0 44.184 0.192 ;
    END
  END xw[671]
  PIN xw[672]
    DIRECTION INPUT ;
    USE SIGNAL ;
    PORT
      LAYER M3 ;
        RECT  45.288 0 45.306 0.144 ;
    END
  END xw[672]
  PIN xw[673]
    DIRECTION INPUT ;
    USE SIGNAL ;
    PORT
      LAYER M5 ;
        RECT  44.256 0 44.28 0.192 ;
    END
  END xw[673]
  PIN xw[674]
    DIRECTION INPUT ;
    USE SIGNAL ;
    PORT
      LAYER M3 ;
        RECT  45.396 0 45.414 0.144 ;
    END
  END xw[674]
  PIN xw[675]
    DIRECTION INPUT ;
    USE SIGNAL ;
    PORT
      LAYER M5 ;
        RECT  44.352 0 44.376 0.192 ;
    END
  END xw[675]
  PIN xw[676]
    DIRECTION INPUT ;
    USE SIGNAL ;
    PORT
      LAYER M3 ;
        RECT  45.504 0 45.522 0.144 ;
    END
  END xw[676]
  PIN xw[677]
    DIRECTION INPUT ;
    USE SIGNAL ;
    PORT
      LAYER M5 ;
        RECT  44.448 0 44.472 0.192 ;
    END
  END xw[677]
  PIN xw[678]
    DIRECTION INPUT ;
    USE SIGNAL ;
    PORT
      LAYER M3 ;
        RECT  45.612 0 45.63 0.144 ;
    END
  END xw[678]
  PIN xw[679]
    DIRECTION INPUT ;
    USE SIGNAL ;
    PORT
      LAYER M5 ;
        RECT  44.544 0 44.568 0.192 ;
    END
  END xw[679]
  PIN xw[67]
    DIRECTION INPUT ;
    USE SIGNAL ;
    PORT
      LAYER M5 ;
        RECT  15.168 0 15.192 0.192 ;
    END
  END xw[67]
  PIN xw[680]
    DIRECTION INPUT ;
    USE SIGNAL ;
    PORT
      LAYER M3 ;
        RECT  45.72 0 45.738 0.144 ;
    END
  END xw[680]
  PIN xw[681]
    DIRECTION INPUT ;
    USE SIGNAL ;
    PORT
      LAYER M5 ;
        RECT  44.64 0 44.664 0.192 ;
    END
  END xw[681]
  PIN xw[682]
    DIRECTION INPUT ;
    USE SIGNAL ;
    PORT
      LAYER M3 ;
        RECT  45.828 0 45.846 0.144 ;
    END
  END xw[682]
  PIN xw[683]
    DIRECTION INPUT ;
    USE SIGNAL ;
    PORT
      LAYER M5 ;
        RECT  44.736 0 44.76 0.192 ;
    END
  END xw[683]
  PIN xw[684]
    DIRECTION INPUT ;
    USE SIGNAL ;
    PORT
      LAYER M3 ;
        RECT  45.936 0 45.954 0.144 ;
    END
  END xw[684]
  PIN xw[685]
    DIRECTION INPUT ;
    USE SIGNAL ;
    PORT
      LAYER M5 ;
        RECT  44.832 0 44.856 0.192 ;
    END
  END xw[685]
  PIN xw[686]
    DIRECTION INPUT ;
    USE SIGNAL ;
    PORT
      LAYER M3 ;
        RECT  46.044 0 46.062 0.144 ;
    END
  END xw[686]
  PIN xw[687]
    DIRECTION INPUT ;
    USE SIGNAL ;
    PORT
      LAYER M5 ;
        RECT  44.928 0 44.952 0.192 ;
    END
  END xw[687]
  PIN xw[688]
    DIRECTION INPUT ;
    USE SIGNAL ;
    PORT
      LAYER M3 ;
        RECT  46.152 0 46.17 0.144 ;
    END
  END xw[688]
  PIN xw[689]
    DIRECTION INPUT ;
    USE SIGNAL ;
    PORT
      LAYER M5 ;
        RECT  45.024 0 45.048 0.192 ;
    END
  END xw[689]
  PIN xw[68]
    DIRECTION INPUT ;
    USE SIGNAL ;
    PORT
      LAYER M3 ;
        RECT  12.672 0 12.69 0.144 ;
    END
  END xw[68]
  PIN xw[690]
    DIRECTION INPUT ;
    USE SIGNAL ;
    PORT
      LAYER M3 ;
        RECT  46.26 0 46.278 0.144 ;
    END
  END xw[690]
  PIN xw[691]
    DIRECTION INPUT ;
    USE SIGNAL ;
    PORT
      LAYER M5 ;
        RECT  45.12 0 45.144 0.192 ;
    END
  END xw[691]
  PIN xw[692]
    DIRECTION INPUT ;
    USE SIGNAL ;
    PORT
      LAYER M3 ;
        RECT  46.368 0 46.386 0.144 ;
    END
  END xw[692]
  PIN xw[693]
    DIRECTION INPUT ;
    USE SIGNAL ;
    PORT
      LAYER M5 ;
        RECT  45.216 0 45.24 0.192 ;
    END
  END xw[693]
  PIN xw[694]
    DIRECTION INPUT ;
    USE SIGNAL ;
    PORT
      LAYER M3 ;
        RECT  46.476 0 46.494 0.144 ;
    END
  END xw[694]
  PIN xw[695]
    DIRECTION INPUT ;
    USE SIGNAL ;
    PORT
      LAYER M5 ;
        RECT  45.312 0 45.336 0.192 ;
    END
  END xw[695]
  PIN xw[696]
    DIRECTION INPUT ;
    USE SIGNAL ;
    PORT
      LAYER M3 ;
        RECT  46.584 0 46.602 0.144 ;
    END
  END xw[696]
  PIN xw[697]
    DIRECTION INPUT ;
    USE SIGNAL ;
    PORT
      LAYER M5 ;
        RECT  45.408 0 45.432 0.192 ;
    END
  END xw[697]
  PIN xw[698]
    DIRECTION INPUT ;
    USE SIGNAL ;
    PORT
      LAYER M3 ;
        RECT  46.692 0 46.71 0.144 ;
    END
  END xw[698]
  PIN xw[699]
    DIRECTION INPUT ;
    USE SIGNAL ;
    PORT
      LAYER M5 ;
        RECT  45.504 0 45.528 0.192 ;
    END
  END xw[699]
  PIN xw[69]
    DIRECTION INPUT ;
    USE SIGNAL ;
    PORT
      LAYER M5 ;
        RECT  15.264 0 15.288 0.192 ;
    END
  END xw[69]
  PIN xw[6]
    DIRECTION INPUT ;
    USE SIGNAL ;
    PORT
      LAYER M3 ;
        RECT  9.324 0 9.342 0.144 ;
    END
  END xw[6]
  PIN xw[700]
    DIRECTION INPUT ;
    USE SIGNAL ;
    PORT
      LAYER M3 ;
        RECT  46.8 0 46.818 0.144 ;
    END
  END xw[700]
  PIN xw[701]
    DIRECTION INPUT ;
    USE SIGNAL ;
    PORT
      LAYER M5 ;
        RECT  45.6 0 45.624 0.192 ;
    END
  END xw[701]
  PIN xw[702]
    DIRECTION INPUT ;
    USE SIGNAL ;
    PORT
      LAYER M3 ;
        RECT  46.908 0 46.926 0.144 ;
    END
  END xw[702]
  PIN xw[703]
    DIRECTION INPUT ;
    USE SIGNAL ;
    PORT
      LAYER M5 ;
        RECT  45.696 0 45.72 0.192 ;
    END
  END xw[703]
  PIN xw[704]
    DIRECTION INPUT ;
    USE SIGNAL ;
    PORT
      LAYER M3 ;
        RECT  47.016 0 47.034 0.144 ;
    END
  END xw[704]
  PIN xw[705]
    DIRECTION INPUT ;
    USE SIGNAL ;
    PORT
      LAYER M5 ;
        RECT  45.792 0 45.816 0.192 ;
    END
  END xw[705]
  PIN xw[706]
    DIRECTION INPUT ;
    USE SIGNAL ;
    PORT
      LAYER M3 ;
        RECT  47.124 0 47.142 0.144 ;
    END
  END xw[706]
  PIN xw[707]
    DIRECTION INPUT ;
    USE SIGNAL ;
    PORT
      LAYER M5 ;
        RECT  45.888 0 45.912 0.192 ;
    END
  END xw[707]
  PIN xw[708]
    DIRECTION INPUT ;
    USE SIGNAL ;
    PORT
      LAYER M3 ;
        RECT  47.232 0 47.25 0.144 ;
    END
  END xw[708]
  PIN xw[709]
    DIRECTION INPUT ;
    USE SIGNAL ;
    PORT
      LAYER M5 ;
        RECT  45.984 0 46.008 0.192 ;
    END
  END xw[709]
  PIN xw[70]
    DIRECTION INPUT ;
    USE SIGNAL ;
    PORT
      LAYER M3 ;
        RECT  12.78 0 12.798 0.144 ;
    END
  END xw[70]
  PIN xw[710]
    DIRECTION INPUT ;
    USE SIGNAL ;
    PORT
      LAYER M3 ;
        RECT  47.34 0 47.358 0.144 ;
    END
  END xw[710]
  PIN xw[711]
    DIRECTION INPUT ;
    USE SIGNAL ;
    PORT
      LAYER M5 ;
        RECT  46.08 0 46.104 0.192 ;
    END
  END xw[711]
  PIN xw[712]
    DIRECTION INPUT ;
    USE SIGNAL ;
    PORT
      LAYER M3 ;
        RECT  47.448 0 47.466 0.144 ;
    END
  END xw[712]
  PIN xw[713]
    DIRECTION INPUT ;
    USE SIGNAL ;
    PORT
      LAYER M5 ;
        RECT  46.176 0 46.2 0.192 ;
    END
  END xw[713]
  PIN xw[714]
    DIRECTION INPUT ;
    USE SIGNAL ;
    PORT
      LAYER M3 ;
        RECT  47.556 0 47.574 0.144 ;
    END
  END xw[714]
  PIN xw[715]
    DIRECTION INPUT ;
    USE SIGNAL ;
    PORT
      LAYER M5 ;
        RECT  46.272 0 46.296 0.192 ;
    END
  END xw[715]
  PIN xw[716]
    DIRECTION INPUT ;
    USE SIGNAL ;
    PORT
      LAYER M3 ;
        RECT  47.664 0 47.682 0.144 ;
    END
  END xw[716]
  PIN xw[717]
    DIRECTION INPUT ;
    USE SIGNAL ;
    PORT
      LAYER M5 ;
        RECT  46.368 0 46.392 0.192 ;
    END
  END xw[717]
  PIN xw[718]
    DIRECTION INPUT ;
    USE SIGNAL ;
    PORT
      LAYER M3 ;
        RECT  47.772 0 47.79 0.144 ;
    END
  END xw[718]
  PIN xw[719]
    DIRECTION INPUT ;
    USE SIGNAL ;
    PORT
      LAYER M5 ;
        RECT  46.464 0 46.488 0.192 ;
    END
  END xw[719]
  PIN xw[71]
    DIRECTION INPUT ;
    USE SIGNAL ;
    PORT
      LAYER M5 ;
        RECT  15.36 0 15.384 0.192 ;
    END
  END xw[71]
  PIN xw[720]
    DIRECTION INPUT ;
    USE SIGNAL ;
    PORT
      LAYER M3 ;
        RECT  47.88 0 47.898 0.144 ;
    END
  END xw[720]
  PIN xw[721]
    DIRECTION INPUT ;
    USE SIGNAL ;
    PORT
      LAYER M5 ;
        RECT  46.56 0 46.584 0.192 ;
    END
  END xw[721]
  PIN xw[722]
    DIRECTION INPUT ;
    USE SIGNAL ;
    PORT
      LAYER M3 ;
        RECT  47.988 0 48.006 0.144 ;
    END
  END xw[722]
  PIN xw[723]
    DIRECTION INPUT ;
    USE SIGNAL ;
    PORT
      LAYER M5 ;
        RECT  46.656 0 46.68 0.192 ;
    END
  END xw[723]
  PIN xw[724]
    DIRECTION INPUT ;
    USE SIGNAL ;
    PORT
      LAYER M3 ;
        RECT  48.096 0 48.114 0.144 ;
    END
  END xw[724]
  PIN xw[725]
    DIRECTION INPUT ;
    USE SIGNAL ;
    PORT
      LAYER M5 ;
        RECT  46.752 0 46.776 0.192 ;
    END
  END xw[725]
  PIN xw[726]
    DIRECTION INPUT ;
    USE SIGNAL ;
    PORT
      LAYER M3 ;
        RECT  48.204 0 48.222 0.144 ;
    END
  END xw[726]
  PIN xw[727]
    DIRECTION INPUT ;
    USE SIGNAL ;
    PORT
      LAYER M5 ;
        RECT  46.848 0 46.872 0.192 ;
    END
  END xw[727]
  PIN xw[728]
    DIRECTION INPUT ;
    USE SIGNAL ;
    PORT
      LAYER M3 ;
        RECT  48.312 0 48.33 0.144 ;
    END
  END xw[728]
  PIN xw[729]
    DIRECTION INPUT ;
    USE SIGNAL ;
    PORT
      LAYER M5 ;
        RECT  46.944 0 46.968 0.192 ;
    END
  END xw[729]
  PIN xw[72]
    DIRECTION INPUT ;
    USE SIGNAL ;
    PORT
      LAYER M3 ;
        RECT  12.888 0 12.906 0.144 ;
    END
  END xw[72]
  PIN xw[730]
    DIRECTION INPUT ;
    USE SIGNAL ;
    PORT
      LAYER M3 ;
        RECT  48.42 0 48.438 0.144 ;
    END
  END xw[730]
  PIN xw[731]
    DIRECTION INPUT ;
    USE SIGNAL ;
    PORT
      LAYER M5 ;
        RECT  47.04 0 47.064 0.192 ;
    END
  END xw[731]
  PIN xw[732]
    DIRECTION INPUT ;
    USE SIGNAL ;
    PORT
      LAYER M3 ;
        RECT  48.528 0 48.546 0.144 ;
    END
  END xw[732]
  PIN xw[733]
    DIRECTION INPUT ;
    USE SIGNAL ;
    PORT
      LAYER M5 ;
        RECT  47.136 0 47.16 0.192 ;
    END
  END xw[733]
  PIN xw[734]
    DIRECTION INPUT ;
    USE SIGNAL ;
    PORT
      LAYER M3 ;
        RECT  48.636 0 48.654 0.144 ;
    END
  END xw[734]
  PIN xw[735]
    DIRECTION INPUT ;
    USE SIGNAL ;
    PORT
      LAYER M5 ;
        RECT  47.232 0 47.256 0.192 ;
    END
  END xw[735]
  PIN xw[736]
    DIRECTION INPUT ;
    USE SIGNAL ;
    PORT
      LAYER M3 ;
        RECT  48.744 0 48.762 0.144 ;
    END
  END xw[736]
  PIN xw[737]
    DIRECTION INPUT ;
    USE SIGNAL ;
    PORT
      LAYER M5 ;
        RECT  47.328 0 47.352 0.192 ;
    END
  END xw[737]
  PIN xw[738]
    DIRECTION INPUT ;
    USE SIGNAL ;
    PORT
      LAYER M3 ;
        RECT  48.852 0 48.87 0.144 ;
    END
  END xw[738]
  PIN xw[739]
    DIRECTION INPUT ;
    USE SIGNAL ;
    PORT
      LAYER M5 ;
        RECT  47.424 0 47.448 0.192 ;
    END
  END xw[739]
  PIN xw[73]
    DIRECTION INPUT ;
    USE SIGNAL ;
    PORT
      LAYER M5 ;
        RECT  15.456 0 15.48 0.192 ;
    END
  END xw[73]
  PIN xw[740]
    DIRECTION INPUT ;
    USE SIGNAL ;
    PORT
      LAYER M3 ;
        RECT  48.96 0 48.978 0.144 ;
    END
  END xw[740]
  PIN xw[741]
    DIRECTION INPUT ;
    USE SIGNAL ;
    PORT
      LAYER M5 ;
        RECT  47.52 0 47.544 0.192 ;
    END
  END xw[741]
  PIN xw[742]
    DIRECTION INPUT ;
    USE SIGNAL ;
    PORT
      LAYER M3 ;
        RECT  49.068 0 49.086 0.144 ;
    END
  END xw[742]
  PIN xw[743]
    DIRECTION INPUT ;
    USE SIGNAL ;
    PORT
      LAYER M5 ;
        RECT  47.616 0 47.64 0.192 ;
    END
  END xw[743]
  PIN xw[744]
    DIRECTION INPUT ;
    USE SIGNAL ;
    PORT
      LAYER M3 ;
        RECT  49.176 0 49.194 0.144 ;
    END
  END xw[744]
  PIN xw[745]
    DIRECTION INPUT ;
    USE SIGNAL ;
    PORT
      LAYER M5 ;
        RECT  47.712 0 47.736 0.192 ;
    END
  END xw[745]
  PIN xw[746]
    DIRECTION INPUT ;
    USE SIGNAL ;
    PORT
      LAYER M3 ;
        RECT  49.284 0 49.302 0.144 ;
    END
  END xw[746]
  PIN xw[747]
    DIRECTION INPUT ;
    USE SIGNAL ;
    PORT
      LAYER M5 ;
        RECT  47.808 0 47.832 0.192 ;
    END
  END xw[747]
  PIN xw[748]
    DIRECTION INPUT ;
    USE SIGNAL ;
    PORT
      LAYER M3 ;
        RECT  49.392 0 49.41 0.144 ;
    END
  END xw[748]
  PIN xw[749]
    DIRECTION INPUT ;
    USE SIGNAL ;
    PORT
      LAYER M5 ;
        RECT  47.904 0 47.928 0.192 ;
    END
  END xw[749]
  PIN xw[74]
    DIRECTION INPUT ;
    USE SIGNAL ;
    PORT
      LAYER M3 ;
        RECT  12.996 0 13.014 0.144 ;
    END
  END xw[74]
  PIN xw[750]
    DIRECTION INPUT ;
    USE SIGNAL ;
    PORT
      LAYER M3 ;
        RECT  49.5 0 49.518 0.144 ;
    END
  END xw[750]
  PIN xw[751]
    DIRECTION INPUT ;
    USE SIGNAL ;
    PORT
      LAYER M5 ;
        RECT  48 0 48.024 0.192 ;
    END
  END xw[751]
  PIN xw[752]
    DIRECTION INPUT ;
    USE SIGNAL ;
    PORT
      LAYER M3 ;
        RECT  49.608 0 49.626 0.144 ;
    END
  END xw[752]
  PIN xw[753]
    DIRECTION INPUT ;
    USE SIGNAL ;
    PORT
      LAYER M5 ;
        RECT  48.096 0 48.12 0.192 ;
    END
  END xw[753]
  PIN xw[754]
    DIRECTION INPUT ;
    USE SIGNAL ;
    PORT
      LAYER M3 ;
        RECT  49.716 0 49.734 0.144 ;
    END
  END xw[754]
  PIN xw[755]
    DIRECTION INPUT ;
    USE SIGNAL ;
    PORT
      LAYER M5 ;
        RECT  48.192 0 48.216 0.192 ;
    END
  END xw[755]
  PIN xw[756]
    DIRECTION INPUT ;
    USE SIGNAL ;
    PORT
      LAYER M3 ;
        RECT  49.824 0 49.842 0.144 ;
    END
  END xw[756]
  PIN xw[757]
    DIRECTION INPUT ;
    USE SIGNAL ;
    PORT
      LAYER M5 ;
        RECT  48.288 0 48.312 0.192 ;
    END
  END xw[757]
  PIN xw[758]
    DIRECTION INPUT ;
    USE SIGNAL ;
    PORT
      LAYER M3 ;
        RECT  49.932 0 49.95 0.144 ;
    END
  END xw[758]
  PIN xw[759]
    DIRECTION INPUT ;
    USE SIGNAL ;
    PORT
      LAYER M5 ;
        RECT  48.384 0 48.408 0.192 ;
    END
  END xw[759]
  PIN xw[75]
    DIRECTION INPUT ;
    USE SIGNAL ;
    PORT
      LAYER M5 ;
        RECT  15.552 0 15.576 0.192 ;
    END
  END xw[75]
  PIN xw[760]
    DIRECTION INPUT ;
    USE SIGNAL ;
    PORT
      LAYER M3 ;
        RECT  50.04 0 50.058 0.144 ;
    END
  END xw[760]
  PIN xw[761]
    DIRECTION INPUT ;
    USE SIGNAL ;
    PORT
      LAYER M5 ;
        RECT  48.48 0 48.504 0.192 ;
    END
  END xw[761]
  PIN xw[762]
    DIRECTION INPUT ;
    USE SIGNAL ;
    PORT
      LAYER M3 ;
        RECT  50.148 0 50.166 0.144 ;
    END
  END xw[762]
  PIN xw[763]
    DIRECTION INPUT ;
    USE SIGNAL ;
    PORT
      LAYER M5 ;
        RECT  48.576 0 48.6 0.192 ;
    END
  END xw[763]
  PIN xw[764]
    DIRECTION INPUT ;
    USE SIGNAL ;
    PORT
      LAYER M3 ;
        RECT  50.256 0 50.274 0.144 ;
    END
  END xw[764]
  PIN xw[765]
    DIRECTION INPUT ;
    USE SIGNAL ;
    PORT
      LAYER M5 ;
        RECT  48.672 0 48.696 0.192 ;
    END
  END xw[765]
  PIN xw[766]
    DIRECTION INPUT ;
    USE SIGNAL ;
    PORT
      LAYER M3 ;
        RECT  50.364 0 50.382 0.144 ;
    END
  END xw[766]
  PIN xw[767]
    DIRECTION INPUT ;
    USE SIGNAL ;
    PORT
      LAYER M5 ;
        RECT  48.768 0 48.792 0.192 ;
    END
  END xw[767]
  PIN xw[768]
    DIRECTION INPUT ;
    USE SIGNAL ;
    PORT
      LAYER M3 ;
        RECT  50.472 0 50.49 0.144 ;
    END
  END xw[768]
  PIN xw[769]
    DIRECTION INPUT ;
    USE SIGNAL ;
    PORT
      LAYER M5 ;
        RECT  48.864 0 48.888 0.192 ;
    END
  END xw[769]
  PIN xw[76]
    DIRECTION INPUT ;
    USE SIGNAL ;
    PORT
      LAYER M3 ;
        RECT  13.104 0 13.122 0.144 ;
    END
  END xw[76]
  PIN xw[770]
    DIRECTION INPUT ;
    USE SIGNAL ;
    PORT
      LAYER M3 ;
        RECT  50.58 0 50.598 0.144 ;
    END
  END xw[770]
  PIN xw[771]
    DIRECTION INPUT ;
    USE SIGNAL ;
    PORT
      LAYER M5 ;
        RECT  48.96 0 48.984 0.192 ;
    END
  END xw[771]
  PIN xw[772]
    DIRECTION INPUT ;
    USE SIGNAL ;
    PORT
      LAYER M3 ;
        RECT  50.688 0 50.706 0.144 ;
    END
  END xw[772]
  PIN xw[773]
    DIRECTION INPUT ;
    USE SIGNAL ;
    PORT
      LAYER M5 ;
        RECT  49.056 0 49.08 0.192 ;
    END
  END xw[773]
  PIN xw[774]
    DIRECTION INPUT ;
    USE SIGNAL ;
    PORT
      LAYER M3 ;
        RECT  50.796 0 50.814 0.144 ;
    END
  END xw[774]
  PIN xw[775]
    DIRECTION INPUT ;
    USE SIGNAL ;
    PORT
      LAYER M5 ;
        RECT  49.152 0 49.176 0.192 ;
    END
  END xw[775]
  PIN xw[776]
    DIRECTION INPUT ;
    USE SIGNAL ;
    PORT
      LAYER M3 ;
        RECT  50.904 0 50.922 0.144 ;
    END
  END xw[776]
  PIN xw[777]
    DIRECTION INPUT ;
    USE SIGNAL ;
    PORT
      LAYER M5 ;
        RECT  49.248 0 49.272 0.192 ;
    END
  END xw[777]
  PIN xw[778]
    DIRECTION INPUT ;
    USE SIGNAL ;
    PORT
      LAYER M3 ;
        RECT  51.012 0 51.03 0.144 ;
    END
  END xw[778]
  PIN xw[779]
    DIRECTION INPUT ;
    USE SIGNAL ;
    PORT
      LAYER M5 ;
        RECT  49.344 0 49.368 0.192 ;
    END
  END xw[779]
  PIN xw[77]
    DIRECTION INPUT ;
    USE SIGNAL ;
    PORT
      LAYER M5 ;
        RECT  15.648 0 15.672 0.192 ;
    END
  END xw[77]
  PIN xw[780]
    DIRECTION INPUT ;
    USE SIGNAL ;
    PORT
      LAYER M3 ;
        RECT  51.12 0 51.138 0.144 ;
    END
  END xw[780]
  PIN xw[781]
    DIRECTION INPUT ;
    USE SIGNAL ;
    PORT
      LAYER M5 ;
        RECT  49.44 0 49.464 0.192 ;
    END
  END xw[781]
  PIN xw[782]
    DIRECTION INPUT ;
    USE SIGNAL ;
    PORT
      LAYER M3 ;
        RECT  51.228 0 51.246 0.144 ;
    END
  END xw[782]
  PIN xw[783]
    DIRECTION INPUT ;
    USE SIGNAL ;
    PORT
      LAYER M5 ;
        RECT  49.536 0 49.56 0.192 ;
    END
  END xw[783]
  PIN xw[784]
    DIRECTION INPUT ;
    USE SIGNAL ;
    PORT
      LAYER M3 ;
        RECT  51.336 0 51.354 0.144 ;
    END
  END xw[784]
  PIN xw[785]
    DIRECTION INPUT ;
    USE SIGNAL ;
    PORT
      LAYER M5 ;
        RECT  49.632 0 49.656 0.192 ;
    END
  END xw[785]
  PIN xw[786]
    DIRECTION INPUT ;
    USE SIGNAL ;
    PORT
      LAYER M3 ;
        RECT  51.444 0 51.462 0.144 ;
    END
  END xw[786]
  PIN xw[787]
    DIRECTION INPUT ;
    USE SIGNAL ;
    PORT
      LAYER M5 ;
        RECT  49.728 0 49.752 0.192 ;
    END
  END xw[787]
  PIN xw[788]
    DIRECTION INPUT ;
    USE SIGNAL ;
    PORT
      LAYER M3 ;
        RECT  51.552 0 51.57 0.144 ;
    END
  END xw[788]
  PIN xw[789]
    DIRECTION INPUT ;
    USE SIGNAL ;
    PORT
      LAYER M5 ;
        RECT  49.824 0 49.848 0.192 ;
    END
  END xw[789]
  PIN xw[78]
    DIRECTION INPUT ;
    USE SIGNAL ;
    PORT
      LAYER M3 ;
        RECT  13.212 0 13.23 0.144 ;
    END
  END xw[78]
  PIN xw[790]
    DIRECTION INPUT ;
    USE SIGNAL ;
    PORT
      LAYER M3 ;
        RECT  51.66 0 51.678 0.144 ;
    END
  END xw[790]
  PIN xw[791]
    DIRECTION INPUT ;
    USE SIGNAL ;
    PORT
      LAYER M5 ;
        RECT  49.92 0 49.944 0.192 ;
    END
  END xw[791]
  PIN xw[792]
    DIRECTION INPUT ;
    USE SIGNAL ;
    PORT
      LAYER M3 ;
        RECT  51.768 0 51.786 0.144 ;
    END
  END xw[792]
  PIN xw[793]
    DIRECTION INPUT ;
    USE SIGNAL ;
    PORT
      LAYER M5 ;
        RECT  50.016 0 50.04 0.192 ;
    END
  END xw[793]
  PIN xw[794]
    DIRECTION INPUT ;
    USE SIGNAL ;
    PORT
      LAYER M3 ;
        RECT  51.876 0 51.894 0.144 ;
    END
  END xw[794]
  PIN xw[795]
    DIRECTION INPUT ;
    USE SIGNAL ;
    PORT
      LAYER M5 ;
        RECT  50.112 0 50.136 0.192 ;
    END
  END xw[795]
  PIN xw[796]
    DIRECTION INPUT ;
    USE SIGNAL ;
    PORT
      LAYER M3 ;
        RECT  51.984 0 52.002 0.144 ;
    END
  END xw[796]
  PIN xw[797]
    DIRECTION INPUT ;
    USE SIGNAL ;
    PORT
      LAYER M5 ;
        RECT  50.208 0 50.232 0.192 ;
    END
  END xw[797]
  PIN xw[798]
    DIRECTION INPUT ;
    USE SIGNAL ;
    PORT
      LAYER M3 ;
        RECT  52.092 0 52.11 0.144 ;
    END
  END xw[798]
  PIN xw[799]
    DIRECTION INPUT ;
    USE SIGNAL ;
    PORT
      LAYER M5 ;
        RECT  50.304 0 50.328 0.192 ;
    END
  END xw[799]
  PIN xw[79]
    DIRECTION INPUT ;
    USE SIGNAL ;
    PORT
      LAYER M5 ;
        RECT  15.744 0 15.768 0.192 ;
    END
  END xw[79]
  PIN xw[7]
    DIRECTION INPUT ;
    USE SIGNAL ;
    PORT
      LAYER M5 ;
        RECT  12.288 0 12.312 0.192 ;
    END
  END xw[7]
  PIN xw[800]
    DIRECTION INPUT ;
    USE SIGNAL ;
    PORT
      LAYER M3 ;
        RECT  52.2 0 52.218 0.144 ;
    END
  END xw[800]
  PIN xw[801]
    DIRECTION INPUT ;
    USE SIGNAL ;
    PORT
      LAYER M5 ;
        RECT  50.4 0 50.424 0.192 ;
    END
  END xw[801]
  PIN xw[802]
    DIRECTION INPUT ;
    USE SIGNAL ;
    PORT
      LAYER M3 ;
        RECT  52.308 0 52.326 0.144 ;
    END
  END xw[802]
  PIN xw[803]
    DIRECTION INPUT ;
    USE SIGNAL ;
    PORT
      LAYER M5 ;
        RECT  50.496 0 50.52 0.192 ;
    END
  END xw[803]
  PIN xw[804]
    DIRECTION INPUT ;
    USE SIGNAL ;
    PORT
      LAYER M3 ;
        RECT  52.416 0 52.434 0.144 ;
    END
  END xw[804]
  PIN xw[805]
    DIRECTION INPUT ;
    USE SIGNAL ;
    PORT
      LAYER M5 ;
        RECT  50.592 0 50.616 0.192 ;
    END
  END xw[805]
  PIN xw[806]
    DIRECTION INPUT ;
    USE SIGNAL ;
    PORT
      LAYER M3 ;
        RECT  52.524 0 52.542 0.144 ;
    END
  END xw[806]
  PIN xw[807]
    DIRECTION INPUT ;
    USE SIGNAL ;
    PORT
      LAYER M5 ;
        RECT  50.688 0 50.712 0.192 ;
    END
  END xw[807]
  PIN xw[808]
    DIRECTION INPUT ;
    USE SIGNAL ;
    PORT
      LAYER M3 ;
        RECT  52.632 0 52.65 0.144 ;
    END
  END xw[808]
  PIN xw[809]
    DIRECTION INPUT ;
    USE SIGNAL ;
    PORT
      LAYER M5 ;
        RECT  50.784 0 50.808 0.192 ;
    END
  END xw[809]
  PIN xw[80]
    DIRECTION INPUT ;
    USE SIGNAL ;
    PORT
      LAYER M3 ;
        RECT  13.32 0 13.338 0.144 ;
    END
  END xw[80]
  PIN xw[810]
    DIRECTION INPUT ;
    USE SIGNAL ;
    PORT
      LAYER M3 ;
        RECT  52.74 0 52.758 0.144 ;
    END
  END xw[810]
  PIN xw[811]
    DIRECTION INPUT ;
    USE SIGNAL ;
    PORT
      LAYER M5 ;
        RECT  50.88 0 50.904 0.192 ;
    END
  END xw[811]
  PIN xw[812]
    DIRECTION INPUT ;
    USE SIGNAL ;
    PORT
      LAYER M3 ;
        RECT  52.848 0 52.866 0.144 ;
    END
  END xw[812]
  PIN xw[813]
    DIRECTION INPUT ;
    USE SIGNAL ;
    PORT
      LAYER M5 ;
        RECT  50.976 0 51 0.192 ;
    END
  END xw[813]
  PIN xw[814]
    DIRECTION INPUT ;
    USE SIGNAL ;
    PORT
      LAYER M3 ;
        RECT  52.956 0 52.974 0.144 ;
    END
  END xw[814]
  PIN xw[815]
    DIRECTION INPUT ;
    USE SIGNAL ;
    PORT
      LAYER M5 ;
        RECT  51.072 0 51.096 0.192 ;
    END
  END xw[815]
  PIN xw[816]
    DIRECTION INPUT ;
    USE SIGNAL ;
    PORT
      LAYER M3 ;
        RECT  53.064 0 53.082 0.144 ;
    END
  END xw[816]
  PIN xw[817]
    DIRECTION INPUT ;
    USE SIGNAL ;
    PORT
      LAYER M5 ;
        RECT  51.168 0 51.192 0.192 ;
    END
  END xw[817]
  PIN xw[818]
    DIRECTION INPUT ;
    USE SIGNAL ;
    PORT
      LAYER M3 ;
        RECT  53.172 0 53.19 0.144 ;
    END
  END xw[818]
  PIN xw[819]
    DIRECTION INPUT ;
    USE SIGNAL ;
    PORT
      LAYER M5 ;
        RECT  51.264 0 51.288 0.192 ;
    END
  END xw[819]
  PIN xw[81]
    DIRECTION INPUT ;
    USE SIGNAL ;
    PORT
      LAYER M5 ;
        RECT  15.84 0 15.864 0.192 ;
    END
  END xw[81]
  PIN xw[820]
    DIRECTION INPUT ;
    USE SIGNAL ;
    PORT
      LAYER M3 ;
        RECT  53.28 0 53.298 0.144 ;
    END
  END xw[820]
  PIN xw[821]
    DIRECTION INPUT ;
    USE SIGNAL ;
    PORT
      LAYER M5 ;
        RECT  51.36 0 51.384 0.192 ;
    END
  END xw[821]
  PIN xw[822]
    DIRECTION INPUT ;
    USE SIGNAL ;
    PORT
      LAYER M3 ;
        RECT  53.388 0 53.406 0.144 ;
    END
  END xw[822]
  PIN xw[823]
    DIRECTION INPUT ;
    USE SIGNAL ;
    PORT
      LAYER M5 ;
        RECT  51.456 0 51.48 0.192 ;
    END
  END xw[823]
  PIN xw[824]
    DIRECTION INPUT ;
    USE SIGNAL ;
    PORT
      LAYER M3 ;
        RECT  53.496 0 53.514 0.144 ;
    END
  END xw[824]
  PIN xw[825]
    DIRECTION INPUT ;
    USE SIGNAL ;
    PORT
      LAYER M5 ;
        RECT  51.552 0 51.576 0.192 ;
    END
  END xw[825]
  PIN xw[826]
    DIRECTION INPUT ;
    USE SIGNAL ;
    PORT
      LAYER M3 ;
        RECT  53.604 0 53.622 0.144 ;
    END
  END xw[826]
  PIN xw[827]
    DIRECTION INPUT ;
    USE SIGNAL ;
    PORT
      LAYER M5 ;
        RECT  51.648 0 51.672 0.192 ;
    END
  END xw[827]
  PIN xw[828]
    DIRECTION INPUT ;
    USE SIGNAL ;
    PORT
      LAYER M3 ;
        RECT  53.712 0 53.73 0.144 ;
    END
  END xw[828]
  PIN xw[829]
    DIRECTION INPUT ;
    USE SIGNAL ;
    PORT
      LAYER M5 ;
        RECT  51.744 0 51.768 0.192 ;
    END
  END xw[829]
  PIN xw[82]
    DIRECTION INPUT ;
    USE SIGNAL ;
    PORT
      LAYER M3 ;
        RECT  13.428 0 13.446 0.144 ;
    END
  END xw[82]
  PIN xw[830]
    DIRECTION INPUT ;
    USE SIGNAL ;
    PORT
      LAYER M3 ;
        RECT  53.82 0 53.838 0.144 ;
    END
  END xw[830]
  PIN xw[831]
    DIRECTION INPUT ;
    USE SIGNAL ;
    PORT
      LAYER M5 ;
        RECT  51.84 0 51.864 0.192 ;
    END
  END xw[831]
  PIN xw[832]
    DIRECTION INPUT ;
    USE SIGNAL ;
    PORT
      LAYER M3 ;
        RECT  53.928 0 53.946 0.144 ;
    END
  END xw[832]
  PIN xw[833]
    DIRECTION INPUT ;
    USE SIGNAL ;
    PORT
      LAYER M5 ;
        RECT  51.936 0 51.96 0.192 ;
    END
  END xw[833]
  PIN xw[834]
    DIRECTION INPUT ;
    USE SIGNAL ;
    PORT
      LAYER M3 ;
        RECT  54.036 0 54.054 0.144 ;
    END
  END xw[834]
  PIN xw[835]
    DIRECTION INPUT ;
    USE SIGNAL ;
    PORT
      LAYER M5 ;
        RECT  52.032 0 52.056 0.192 ;
    END
  END xw[835]
  PIN xw[836]
    DIRECTION INPUT ;
    USE SIGNAL ;
    PORT
      LAYER M3 ;
        RECT  54.144 0 54.162 0.144 ;
    END
  END xw[836]
  PIN xw[837]
    DIRECTION INPUT ;
    USE SIGNAL ;
    PORT
      LAYER M5 ;
        RECT  52.128 0 52.152 0.192 ;
    END
  END xw[837]
  PIN xw[838]
    DIRECTION INPUT ;
    USE SIGNAL ;
    PORT
      LAYER M3 ;
        RECT  54.252 0 54.27 0.144 ;
    END
  END xw[838]
  PIN xw[839]
    DIRECTION INPUT ;
    USE SIGNAL ;
    PORT
      LAYER M5 ;
        RECT  52.224 0 52.248 0.192 ;
    END
  END xw[839]
  PIN xw[83]
    DIRECTION INPUT ;
    USE SIGNAL ;
    PORT
      LAYER M5 ;
        RECT  15.936 0 15.96 0.192 ;
    END
  END xw[83]
  PIN xw[840]
    DIRECTION INPUT ;
    USE SIGNAL ;
    PORT
      LAYER M3 ;
        RECT  54.36 0 54.378 0.144 ;
    END
  END xw[840]
  PIN xw[841]
    DIRECTION INPUT ;
    USE SIGNAL ;
    PORT
      LAYER M5 ;
        RECT  52.32 0 52.344 0.192 ;
    END
  END xw[841]
  PIN xw[842]
    DIRECTION INPUT ;
    USE SIGNAL ;
    PORT
      LAYER M3 ;
        RECT  54.468 0 54.486 0.144 ;
    END
  END xw[842]
  PIN xw[843]
    DIRECTION INPUT ;
    USE SIGNAL ;
    PORT
      LAYER M5 ;
        RECT  52.416 0 52.44 0.192 ;
    END
  END xw[843]
  PIN xw[844]
    DIRECTION INPUT ;
    USE SIGNAL ;
    PORT
      LAYER M3 ;
        RECT  54.576 0 54.594 0.144 ;
    END
  END xw[844]
  PIN xw[845]
    DIRECTION INPUT ;
    USE SIGNAL ;
    PORT
      LAYER M5 ;
        RECT  52.512 0 52.536 0.192 ;
    END
  END xw[845]
  PIN xw[846]
    DIRECTION INPUT ;
    USE SIGNAL ;
    PORT
      LAYER M3 ;
        RECT  54.684 0 54.702 0.144 ;
    END
  END xw[846]
  PIN xw[847]
    DIRECTION INPUT ;
    USE SIGNAL ;
    PORT
      LAYER M5 ;
        RECT  52.608 0 52.632 0.192 ;
    END
  END xw[847]
  PIN xw[848]
    DIRECTION INPUT ;
    USE SIGNAL ;
    PORT
      LAYER M3 ;
        RECT  54.792 0 54.81 0.144 ;
    END
  END xw[848]
  PIN xw[849]
    DIRECTION INPUT ;
    USE SIGNAL ;
    PORT
      LAYER M5 ;
        RECT  52.704 0 52.728 0.192 ;
    END
  END xw[849]
  PIN xw[84]
    DIRECTION INPUT ;
    USE SIGNAL ;
    PORT
      LAYER M3 ;
        RECT  13.536 0 13.554 0.144 ;
    END
  END xw[84]
  PIN xw[850]
    DIRECTION INPUT ;
    USE SIGNAL ;
    PORT
      LAYER M3 ;
        RECT  54.9 0 54.918 0.144 ;
    END
  END xw[850]
  PIN xw[851]
    DIRECTION INPUT ;
    USE SIGNAL ;
    PORT
      LAYER M5 ;
        RECT  52.8 0 52.824 0.192 ;
    END
  END xw[851]
  PIN xw[852]
    DIRECTION INPUT ;
    USE SIGNAL ;
    PORT
      LAYER M3 ;
        RECT  55.008 0 55.026 0.144 ;
    END
  END xw[852]
  PIN xw[853]
    DIRECTION INPUT ;
    USE SIGNAL ;
    PORT
      LAYER M5 ;
        RECT  52.896 0 52.92 0.192 ;
    END
  END xw[853]
  PIN xw[854]
    DIRECTION INPUT ;
    USE SIGNAL ;
    PORT
      LAYER M3 ;
        RECT  55.116 0 55.134 0.144 ;
    END
  END xw[854]
  PIN xw[855]
    DIRECTION INPUT ;
    USE SIGNAL ;
    PORT
      LAYER M5 ;
        RECT  52.992 0 53.016 0.192 ;
    END
  END xw[855]
  PIN xw[856]
    DIRECTION INPUT ;
    USE SIGNAL ;
    PORT
      LAYER M3 ;
        RECT  55.224 0 55.242 0.144 ;
    END
  END xw[856]
  PIN xw[857]
    DIRECTION INPUT ;
    USE SIGNAL ;
    PORT
      LAYER M5 ;
        RECT  53.088 0 53.112 0.192 ;
    END
  END xw[857]
  PIN xw[858]
    DIRECTION INPUT ;
    USE SIGNAL ;
    PORT
      LAYER M3 ;
        RECT  55.332 0 55.35 0.144 ;
    END
  END xw[858]
  PIN xw[859]
    DIRECTION INPUT ;
    USE SIGNAL ;
    PORT
      LAYER M5 ;
        RECT  53.184 0 53.208 0.192 ;
    END
  END xw[859]
  PIN xw[85]
    DIRECTION INPUT ;
    USE SIGNAL ;
    PORT
      LAYER M5 ;
        RECT  16.032 0 16.056 0.192 ;
    END
  END xw[85]
  PIN xw[860]
    DIRECTION INPUT ;
    USE SIGNAL ;
    PORT
      LAYER M3 ;
        RECT  55.44 0 55.458 0.144 ;
    END
  END xw[860]
  PIN xw[861]
    DIRECTION INPUT ;
    USE SIGNAL ;
    PORT
      LAYER M5 ;
        RECT  53.28 0 53.304 0.192 ;
    END
  END xw[861]
  PIN xw[862]
    DIRECTION INPUT ;
    USE SIGNAL ;
    PORT
      LAYER M3 ;
        RECT  55.548 0 55.566 0.144 ;
    END
  END xw[862]
  PIN xw[863]
    DIRECTION INPUT ;
    USE SIGNAL ;
    PORT
      LAYER M5 ;
        RECT  53.376 0 53.4 0.192 ;
    END
  END xw[863]
  PIN xw[864]
    DIRECTION INPUT ;
    USE SIGNAL ;
    PORT
      LAYER M3 ;
        RECT  55.656 0 55.674 0.144 ;
    END
  END xw[864]
  PIN xw[865]
    DIRECTION INPUT ;
    USE SIGNAL ;
    PORT
      LAYER M5 ;
        RECT  53.472 0 53.496 0.192 ;
    END
  END xw[865]
  PIN xw[866]
    DIRECTION INPUT ;
    USE SIGNAL ;
    PORT
      LAYER M3 ;
        RECT  55.764 0 55.782 0.144 ;
    END
  END xw[866]
  PIN xw[867]
    DIRECTION INPUT ;
    USE SIGNAL ;
    PORT
      LAYER M5 ;
        RECT  53.568 0 53.592 0.192 ;
    END
  END xw[867]
  PIN xw[868]
    DIRECTION INPUT ;
    USE SIGNAL ;
    PORT
      LAYER M3 ;
        RECT  55.872 0 55.89 0.144 ;
    END
  END xw[868]
  PIN xw[869]
    DIRECTION INPUT ;
    USE SIGNAL ;
    PORT
      LAYER M5 ;
        RECT  53.664 0 53.688 0.192 ;
    END
  END xw[869]
  PIN xw[86]
    DIRECTION INPUT ;
    USE SIGNAL ;
    PORT
      LAYER M3 ;
        RECT  13.644 0 13.662 0.144 ;
    END
  END xw[86]
  PIN xw[870]
    DIRECTION INPUT ;
    USE SIGNAL ;
    PORT
      LAYER M3 ;
        RECT  55.98 0 55.998 0.144 ;
    END
  END xw[870]
  PIN xw[871]
    DIRECTION INPUT ;
    USE SIGNAL ;
    PORT
      LAYER M5 ;
        RECT  53.76 0 53.784 0.192 ;
    END
  END xw[871]
  PIN xw[872]
    DIRECTION INPUT ;
    USE SIGNAL ;
    PORT
      LAYER M3 ;
        RECT  56.088 0 56.106 0.144 ;
    END
  END xw[872]
  PIN xw[873]
    DIRECTION INPUT ;
    USE SIGNAL ;
    PORT
      LAYER M5 ;
        RECT  53.856 0 53.88 0.192 ;
    END
  END xw[873]
  PIN xw[874]
    DIRECTION INPUT ;
    USE SIGNAL ;
    PORT
      LAYER M3 ;
        RECT  56.196 0 56.214 0.144 ;
    END
  END xw[874]
  PIN xw[875]
    DIRECTION INPUT ;
    USE SIGNAL ;
    PORT
      LAYER M5 ;
        RECT  53.952 0 53.976 0.192 ;
    END
  END xw[875]
  PIN xw[876]
    DIRECTION INPUT ;
    USE SIGNAL ;
    PORT
      LAYER M3 ;
        RECT  56.304 0 56.322 0.144 ;
    END
  END xw[876]
  PIN xw[877]
    DIRECTION INPUT ;
    USE SIGNAL ;
    PORT
      LAYER M5 ;
        RECT  54.048 0 54.072 0.192 ;
    END
  END xw[877]
  PIN xw[878]
    DIRECTION INPUT ;
    USE SIGNAL ;
    PORT
      LAYER M3 ;
        RECT  56.412 0 56.43 0.144 ;
    END
  END xw[878]
  PIN xw[879]
    DIRECTION INPUT ;
    USE SIGNAL ;
    PORT
      LAYER M5 ;
        RECT  54.144 0 54.168 0.192 ;
    END
  END xw[879]
  PIN xw[87]
    DIRECTION INPUT ;
    USE SIGNAL ;
    PORT
      LAYER M5 ;
        RECT  16.128 0 16.152 0.192 ;
    END
  END xw[87]
  PIN xw[880]
    DIRECTION INPUT ;
    USE SIGNAL ;
    PORT
      LAYER M3 ;
        RECT  56.52 0 56.538 0.144 ;
    END
  END xw[880]
  PIN xw[881]
    DIRECTION INPUT ;
    USE SIGNAL ;
    PORT
      LAYER M5 ;
        RECT  54.24 0 54.264 0.192 ;
    END
  END xw[881]
  PIN xw[882]
    DIRECTION INPUT ;
    USE SIGNAL ;
    PORT
      LAYER M3 ;
        RECT  56.628 0 56.646 0.144 ;
    END
  END xw[882]
  PIN xw[883]
    DIRECTION INPUT ;
    USE SIGNAL ;
    PORT
      LAYER M5 ;
        RECT  54.336 0 54.36 0.192 ;
    END
  END xw[883]
  PIN xw[884]
    DIRECTION INPUT ;
    USE SIGNAL ;
    PORT
      LAYER M3 ;
        RECT  56.736 0 56.754 0.144 ;
    END
  END xw[884]
  PIN xw[885]
    DIRECTION INPUT ;
    USE SIGNAL ;
    PORT
      LAYER M5 ;
        RECT  54.432 0 54.456 0.192 ;
    END
  END xw[885]
  PIN xw[886]
    DIRECTION INPUT ;
    USE SIGNAL ;
    PORT
      LAYER M3 ;
        RECT  56.844 0 56.862 0.144 ;
    END
  END xw[886]
  PIN xw[887]
    DIRECTION INPUT ;
    USE SIGNAL ;
    PORT
      LAYER M5 ;
        RECT  54.528 0 54.552 0.192 ;
    END
  END xw[887]
  PIN xw[888]
    DIRECTION INPUT ;
    USE SIGNAL ;
    PORT
      LAYER M3 ;
        RECT  56.952 0 56.97 0.144 ;
    END
  END xw[888]
  PIN xw[889]
    DIRECTION INPUT ;
    USE SIGNAL ;
    PORT
      LAYER M5 ;
        RECT  54.624 0 54.648 0.192 ;
    END
  END xw[889]
  PIN xw[88]
    DIRECTION INPUT ;
    USE SIGNAL ;
    PORT
      LAYER M3 ;
        RECT  13.752 0 13.77 0.144 ;
    END
  END xw[88]
  PIN xw[890]
    DIRECTION INPUT ;
    USE SIGNAL ;
    PORT
      LAYER M3 ;
        RECT  57.06 0 57.078 0.144 ;
    END
  END xw[890]
  PIN xw[891]
    DIRECTION INPUT ;
    USE SIGNAL ;
    PORT
      LAYER M5 ;
        RECT  54.72 0 54.744 0.192 ;
    END
  END xw[891]
  PIN xw[892]
    DIRECTION INPUT ;
    USE SIGNAL ;
    PORT
      LAYER M3 ;
        RECT  57.168 0 57.186 0.144 ;
    END
  END xw[892]
  PIN xw[893]
    DIRECTION INPUT ;
    USE SIGNAL ;
    PORT
      LAYER M5 ;
        RECT  54.816 0 54.84 0.192 ;
    END
  END xw[893]
  PIN xw[894]
    DIRECTION INPUT ;
    USE SIGNAL ;
    PORT
      LAYER M3 ;
        RECT  57.276 0 57.294 0.144 ;
    END
  END xw[894]
  PIN xw[895]
    DIRECTION INPUT ;
    USE SIGNAL ;
    PORT
      LAYER M5 ;
        RECT  54.912 0 54.936 0.192 ;
    END
  END xw[895]
  PIN xw[896]
    DIRECTION INPUT ;
    USE SIGNAL ;
    PORT
      LAYER M3 ;
        RECT  57.384 0 57.402 0.144 ;
    END
  END xw[896]
  PIN xw[897]
    DIRECTION INPUT ;
    USE SIGNAL ;
    PORT
      LAYER M5 ;
        RECT  55.008 0 55.032 0.192 ;
    END
  END xw[897]
  PIN xw[898]
    DIRECTION INPUT ;
    USE SIGNAL ;
    PORT
      LAYER M3 ;
        RECT  57.492 0 57.51 0.144 ;
    END
  END xw[898]
  PIN xw[899]
    DIRECTION INPUT ;
    USE SIGNAL ;
    PORT
      LAYER M5 ;
        RECT  55.104 0 55.128 0.192 ;
    END
  END xw[899]
  PIN xw[89]
    DIRECTION INPUT ;
    USE SIGNAL ;
    PORT
      LAYER M5 ;
        RECT  16.224 0 16.248 0.192 ;
    END
  END xw[89]
  PIN xw[8]
    DIRECTION INPUT ;
    USE SIGNAL ;
    PORT
      LAYER M3 ;
        RECT  9.432 0 9.45 0.144 ;
    END
  END xw[8]
  PIN xw[900]
    DIRECTION INPUT ;
    USE SIGNAL ;
    PORT
      LAYER M3 ;
        RECT  57.6 0 57.618 0.144 ;
    END
  END xw[900]
  PIN xw[901]
    DIRECTION INPUT ;
    USE SIGNAL ;
    PORT
      LAYER M5 ;
        RECT  55.2 0 55.224 0.192 ;
    END
  END xw[901]
  PIN xw[902]
    DIRECTION INPUT ;
    USE SIGNAL ;
    PORT
      LAYER M3 ;
        RECT  57.708 0 57.726 0.144 ;
    END
  END xw[902]
  PIN xw[903]
    DIRECTION INPUT ;
    USE SIGNAL ;
    PORT
      LAYER M5 ;
        RECT  55.296 0 55.32 0.192 ;
    END
  END xw[903]
  PIN xw[904]
    DIRECTION INPUT ;
    USE SIGNAL ;
    PORT
      LAYER M3 ;
        RECT  57.816 0 57.834 0.144 ;
    END
  END xw[904]
  PIN xw[905]
    DIRECTION INPUT ;
    USE SIGNAL ;
    PORT
      LAYER M5 ;
        RECT  55.392 0 55.416 0.192 ;
    END
  END xw[905]
  PIN xw[906]
    DIRECTION INPUT ;
    USE SIGNAL ;
    PORT
      LAYER M3 ;
        RECT  57.924 0 57.942 0.144 ;
    END
  END xw[906]
  PIN xw[907]
    DIRECTION INPUT ;
    USE SIGNAL ;
    PORT
      LAYER M5 ;
        RECT  55.488 0 55.512 0.192 ;
    END
  END xw[907]
  PIN xw[908]
    DIRECTION INPUT ;
    USE SIGNAL ;
    PORT
      LAYER M3 ;
        RECT  58.032 0 58.05 0.144 ;
    END
  END xw[908]
  PIN xw[909]
    DIRECTION INPUT ;
    USE SIGNAL ;
    PORT
      LAYER M5 ;
        RECT  55.584 0 55.608 0.192 ;
    END
  END xw[909]
  PIN xw[90]
    DIRECTION INPUT ;
    USE SIGNAL ;
    PORT
      LAYER M3 ;
        RECT  13.86 0 13.878 0.144 ;
    END
  END xw[90]
  PIN xw[910]
    DIRECTION INPUT ;
    USE SIGNAL ;
    PORT
      LAYER M3 ;
        RECT  58.14 0 58.158 0.144 ;
    END
  END xw[910]
  PIN xw[911]
    DIRECTION INPUT ;
    USE SIGNAL ;
    PORT
      LAYER M5 ;
        RECT  55.68 0 55.704 0.192 ;
    END
  END xw[911]
  PIN xw[912]
    DIRECTION INPUT ;
    USE SIGNAL ;
    PORT
      LAYER M3 ;
        RECT  58.248 0 58.266 0.144 ;
    END
  END xw[912]
  PIN xw[913]
    DIRECTION INPUT ;
    USE SIGNAL ;
    PORT
      LAYER M5 ;
        RECT  55.776 0 55.8 0.192 ;
    END
  END xw[913]
  PIN xw[914]
    DIRECTION INPUT ;
    USE SIGNAL ;
    PORT
      LAYER M3 ;
        RECT  58.356 0 58.374 0.144 ;
    END
  END xw[914]
  PIN xw[915]
    DIRECTION INPUT ;
    USE SIGNAL ;
    PORT
      LAYER M5 ;
        RECT  55.872 0 55.896 0.192 ;
    END
  END xw[915]
  PIN xw[916]
    DIRECTION INPUT ;
    USE SIGNAL ;
    PORT
      LAYER M3 ;
        RECT  58.464 0 58.482 0.144 ;
    END
  END xw[916]
  PIN xw[917]
    DIRECTION INPUT ;
    USE SIGNAL ;
    PORT
      LAYER M5 ;
        RECT  55.968 0 55.992 0.192 ;
    END
  END xw[917]
  PIN xw[918]
    DIRECTION INPUT ;
    USE SIGNAL ;
    PORT
      LAYER M3 ;
        RECT  58.572 0 58.59 0.144 ;
    END
  END xw[918]
  PIN xw[919]
    DIRECTION INPUT ;
    USE SIGNAL ;
    PORT
      LAYER M5 ;
        RECT  56.064 0 56.088 0.192 ;
    END
  END xw[919]
  PIN xw[91]
    DIRECTION INPUT ;
    USE SIGNAL ;
    PORT
      LAYER M5 ;
        RECT  16.32 0 16.344 0.192 ;
    END
  END xw[91]
  PIN xw[920]
    DIRECTION INPUT ;
    USE SIGNAL ;
    PORT
      LAYER M3 ;
        RECT  58.68 0 58.698 0.144 ;
    END
  END xw[920]
  PIN xw[921]
    DIRECTION INPUT ;
    USE SIGNAL ;
    PORT
      LAYER M5 ;
        RECT  56.16 0 56.184 0.192 ;
    END
  END xw[921]
  PIN xw[922]
    DIRECTION INPUT ;
    USE SIGNAL ;
    PORT
      LAYER M3 ;
        RECT  58.788 0 58.806 0.144 ;
    END
  END xw[922]
  PIN xw[923]
    DIRECTION INPUT ;
    USE SIGNAL ;
    PORT
      LAYER M5 ;
        RECT  56.256 0 56.28 0.192 ;
    END
  END xw[923]
  PIN xw[924]
    DIRECTION INPUT ;
    USE SIGNAL ;
    PORT
      LAYER M3 ;
        RECT  58.896 0 58.914 0.144 ;
    END
  END xw[924]
  PIN xw[925]
    DIRECTION INPUT ;
    USE SIGNAL ;
    PORT
      LAYER M5 ;
        RECT  56.352 0 56.376 0.192 ;
    END
  END xw[925]
  PIN xw[926]
    DIRECTION INPUT ;
    USE SIGNAL ;
    PORT
      LAYER M3 ;
        RECT  59.004 0 59.022 0.144 ;
    END
  END xw[926]
  PIN xw[927]
    DIRECTION INPUT ;
    USE SIGNAL ;
    PORT
      LAYER M5 ;
        RECT  56.448 0 56.472 0.192 ;
    END
  END xw[927]
  PIN xw[928]
    DIRECTION INPUT ;
    USE SIGNAL ;
    PORT
      LAYER M3 ;
        RECT  59.112 0 59.13 0.144 ;
    END
  END xw[928]
  PIN xw[929]
    DIRECTION INPUT ;
    USE SIGNAL ;
    PORT
      LAYER M5 ;
        RECT  56.544 0 56.568 0.192 ;
    END
  END xw[929]
  PIN xw[92]
    DIRECTION INPUT ;
    USE SIGNAL ;
    PORT
      LAYER M3 ;
        RECT  13.968 0 13.986 0.144 ;
    END
  END xw[92]
  PIN xw[930]
    DIRECTION INPUT ;
    USE SIGNAL ;
    PORT
      LAYER M3 ;
        RECT  59.22 0 59.238 0.144 ;
    END
  END xw[930]
  PIN xw[931]
    DIRECTION INPUT ;
    USE SIGNAL ;
    PORT
      LAYER M5 ;
        RECT  56.64 0 56.664 0.192 ;
    END
  END xw[931]
  PIN xw[932]
    DIRECTION INPUT ;
    USE SIGNAL ;
    PORT
      LAYER M3 ;
        RECT  59.328 0 59.346 0.144 ;
    END
  END xw[932]
  PIN xw[933]
    DIRECTION INPUT ;
    USE SIGNAL ;
    PORT
      LAYER M5 ;
        RECT  56.736 0 56.76 0.192 ;
    END
  END xw[933]
  PIN xw[934]
    DIRECTION INPUT ;
    USE SIGNAL ;
    PORT
      LAYER M3 ;
        RECT  59.436 0 59.454 0.144 ;
    END
  END xw[934]
  PIN xw[935]
    DIRECTION INPUT ;
    USE SIGNAL ;
    PORT
      LAYER M5 ;
        RECT  56.832 0 56.856 0.192 ;
    END
  END xw[935]
  PIN xw[936]
    DIRECTION INPUT ;
    USE SIGNAL ;
    PORT
      LAYER M3 ;
        RECT  59.544 0 59.562 0.144 ;
    END
  END xw[936]
  PIN xw[937]
    DIRECTION INPUT ;
    USE SIGNAL ;
    PORT
      LAYER M5 ;
        RECT  56.928 0 56.952 0.192 ;
    END
  END xw[937]
  PIN xw[938]
    DIRECTION INPUT ;
    USE SIGNAL ;
    PORT
      LAYER M3 ;
        RECT  59.652 0 59.67 0.144 ;
    END
  END xw[938]
  PIN xw[939]
    DIRECTION INPUT ;
    USE SIGNAL ;
    PORT
      LAYER M5 ;
        RECT  57.024 0 57.048 0.192 ;
    END
  END xw[939]
  PIN xw[93]
    DIRECTION INPUT ;
    USE SIGNAL ;
    PORT
      LAYER M5 ;
        RECT  16.416 0 16.44 0.192 ;
    END
  END xw[93]
  PIN xw[940]
    DIRECTION INPUT ;
    USE SIGNAL ;
    PORT
      LAYER M3 ;
        RECT  59.76 0 59.778 0.144 ;
    END
  END xw[940]
  PIN xw[941]
    DIRECTION INPUT ;
    USE SIGNAL ;
    PORT
      LAYER M5 ;
        RECT  57.12 0 57.144 0.192 ;
    END
  END xw[941]
  PIN xw[942]
    DIRECTION INPUT ;
    USE SIGNAL ;
    PORT
      LAYER M3 ;
        RECT  59.868 0 59.886 0.144 ;
    END
  END xw[942]
  PIN xw[943]
    DIRECTION INPUT ;
    USE SIGNAL ;
    PORT
      LAYER M5 ;
        RECT  57.216 0 57.24 0.192 ;
    END
  END xw[943]
  PIN xw[944]
    DIRECTION INPUT ;
    USE SIGNAL ;
    PORT
      LAYER M3 ;
        RECT  59.976 0 59.994 0.144 ;
    END
  END xw[944]
  PIN xw[945]
    DIRECTION INPUT ;
    USE SIGNAL ;
    PORT
      LAYER M5 ;
        RECT  57.312 0 57.336 0.192 ;
    END
  END xw[945]
  PIN xw[946]
    DIRECTION INPUT ;
    USE SIGNAL ;
    PORT
      LAYER M3 ;
        RECT  60.084 0 60.102 0.144 ;
    END
  END xw[946]
  PIN xw[947]
    DIRECTION INPUT ;
    USE SIGNAL ;
    PORT
      LAYER M5 ;
        RECT  57.408 0 57.432 0.192 ;
    END
  END xw[947]
  PIN xw[948]
    DIRECTION INPUT ;
    USE SIGNAL ;
    PORT
      LAYER M3 ;
        RECT  60.192 0 60.21 0.144 ;
    END
  END xw[948]
  PIN xw[949]
    DIRECTION INPUT ;
    USE SIGNAL ;
    PORT
      LAYER M5 ;
        RECT  57.504 0 57.528 0.192 ;
    END
  END xw[949]
  PIN xw[94]
    DIRECTION INPUT ;
    USE SIGNAL ;
    PORT
      LAYER M3 ;
        RECT  14.076 0 14.094 0.144 ;
    END
  END xw[94]
  PIN xw[950]
    DIRECTION INPUT ;
    USE SIGNAL ;
    PORT
      LAYER M3 ;
        RECT  60.3 0 60.318 0.144 ;
    END
  END xw[950]
  PIN xw[951]
    DIRECTION INPUT ;
    USE SIGNAL ;
    PORT
      LAYER M5 ;
        RECT  57.6 0 57.624 0.192 ;
    END
  END xw[951]
  PIN xw[952]
    DIRECTION INPUT ;
    USE SIGNAL ;
    PORT
      LAYER M3 ;
        RECT  60.408 0 60.426 0.144 ;
    END
  END xw[952]
  PIN xw[953]
    DIRECTION INPUT ;
    USE SIGNAL ;
    PORT
      LAYER M5 ;
        RECT  57.696 0 57.72 0.192 ;
    END
  END xw[953]
  PIN xw[954]
    DIRECTION INPUT ;
    USE SIGNAL ;
    PORT
      LAYER M3 ;
        RECT  60.516 0 60.534 0.144 ;
    END
  END xw[954]
  PIN xw[955]
    DIRECTION INPUT ;
    USE SIGNAL ;
    PORT
      LAYER M5 ;
        RECT  57.792 0 57.816 0.192 ;
    END
  END xw[955]
  PIN xw[956]
    DIRECTION INPUT ;
    USE SIGNAL ;
    PORT
      LAYER M3 ;
        RECT  60.624 0 60.642 0.144 ;
    END
  END xw[956]
  PIN xw[957]
    DIRECTION INPUT ;
    USE SIGNAL ;
    PORT
      LAYER M5 ;
        RECT  57.888 0 57.912 0.192 ;
    END
  END xw[957]
  PIN xw[958]
    DIRECTION INPUT ;
    USE SIGNAL ;
    PORT
      LAYER M3 ;
        RECT  60.732 0 60.75 0.144 ;
    END
  END xw[958]
  PIN xw[959]
    DIRECTION INPUT ;
    USE SIGNAL ;
    PORT
      LAYER M5 ;
        RECT  57.984 0 58.008 0.192 ;
    END
  END xw[959]
  PIN xw[95]
    DIRECTION INPUT ;
    USE SIGNAL ;
    PORT
      LAYER M5 ;
        RECT  16.512 0 16.536 0.192 ;
    END
  END xw[95]
  PIN xw[960]
    DIRECTION INPUT ;
    USE SIGNAL ;
    PORT
      LAYER M3 ;
        RECT  60.84 0 60.858 0.144 ;
    END
  END xw[960]
  PIN xw[961]
    DIRECTION INPUT ;
    USE SIGNAL ;
    PORT
      LAYER M5 ;
        RECT  58.08 0 58.104 0.192 ;
    END
  END xw[961]
  PIN xw[962]
    DIRECTION INPUT ;
    USE SIGNAL ;
    PORT
      LAYER M3 ;
        RECT  60.948 0 60.966 0.144 ;
    END
  END xw[962]
  PIN xw[963]
    DIRECTION INPUT ;
    USE SIGNAL ;
    PORT
      LAYER M5 ;
        RECT  58.176 0 58.2 0.192 ;
    END
  END xw[963]
  PIN xw[964]
    DIRECTION INPUT ;
    USE SIGNAL ;
    PORT
      LAYER M3 ;
        RECT  61.056 0 61.074 0.144 ;
    END
  END xw[964]
  PIN xw[965]
    DIRECTION INPUT ;
    USE SIGNAL ;
    PORT
      LAYER M5 ;
        RECT  58.272 0 58.296 0.192 ;
    END
  END xw[965]
  PIN xw[966]
    DIRECTION INPUT ;
    USE SIGNAL ;
    PORT
      LAYER M3 ;
        RECT  61.164 0 61.182 0.144 ;
    END
  END xw[966]
  PIN xw[967]
    DIRECTION INPUT ;
    USE SIGNAL ;
    PORT
      LAYER M5 ;
        RECT  58.368 0 58.392 0.192 ;
    END
  END xw[967]
  PIN xw[968]
    DIRECTION INPUT ;
    USE SIGNAL ;
    PORT
      LAYER M3 ;
        RECT  61.272 0 61.29 0.144 ;
    END
  END xw[968]
  PIN xw[969]
    DIRECTION INPUT ;
    USE SIGNAL ;
    PORT
      LAYER M5 ;
        RECT  58.464 0 58.488 0.192 ;
    END
  END xw[969]
  PIN xw[96]
    DIRECTION INPUT ;
    USE SIGNAL ;
    PORT
      LAYER M3 ;
        RECT  14.184 0 14.202 0.144 ;
    END
  END xw[96]
  PIN xw[970]
    DIRECTION INPUT ;
    USE SIGNAL ;
    PORT
      LAYER M3 ;
        RECT  61.38 0 61.398 0.144 ;
    END
  END xw[970]
  PIN xw[971]
    DIRECTION INPUT ;
    USE SIGNAL ;
    PORT
      LAYER M5 ;
        RECT  58.56 0 58.584 0.192 ;
    END
  END xw[971]
  PIN xw[972]
    DIRECTION INPUT ;
    USE SIGNAL ;
    PORT
      LAYER M3 ;
        RECT  61.488 0 61.506 0.144 ;
    END
  END xw[972]
  PIN xw[973]
    DIRECTION INPUT ;
    USE SIGNAL ;
    PORT
      LAYER M5 ;
        RECT  58.656 0 58.68 0.192 ;
    END
  END xw[973]
  PIN xw[974]
    DIRECTION INPUT ;
    USE SIGNAL ;
    PORT
      LAYER M3 ;
        RECT  61.596 0 61.614 0.144 ;
    END
  END xw[974]
  PIN xw[975]
    DIRECTION INPUT ;
    USE SIGNAL ;
    PORT
      LAYER M5 ;
        RECT  58.752 0 58.776 0.192 ;
    END
  END xw[975]
  PIN xw[976]
    DIRECTION INPUT ;
    USE SIGNAL ;
    PORT
      LAYER M3 ;
        RECT  61.704 0 61.722 0.144 ;
    END
  END xw[976]
  PIN xw[977]
    DIRECTION INPUT ;
    USE SIGNAL ;
    PORT
      LAYER M5 ;
        RECT  58.848 0 58.872 0.192 ;
    END
  END xw[977]
  PIN xw[978]
    DIRECTION INPUT ;
    USE SIGNAL ;
    PORT
      LAYER M3 ;
        RECT  61.812 0 61.83 0.144 ;
    END
  END xw[978]
  PIN xw[979]
    DIRECTION INPUT ;
    USE SIGNAL ;
    PORT
      LAYER M5 ;
        RECT  58.944 0 58.968 0.192 ;
    END
  END xw[979]
  PIN xw[97]
    DIRECTION INPUT ;
    USE SIGNAL ;
    PORT
      LAYER M5 ;
        RECT  16.608 0 16.632 0.192 ;
    END
  END xw[97]
  PIN xw[980]
    DIRECTION INPUT ;
    USE SIGNAL ;
    PORT
      LAYER M3 ;
        RECT  61.92 0 61.938 0.144 ;
    END
  END xw[980]
  PIN xw[981]
    DIRECTION INPUT ;
    USE SIGNAL ;
    PORT
      LAYER M5 ;
        RECT  59.04 0 59.064 0.192 ;
    END
  END xw[981]
  PIN xw[982]
    DIRECTION INPUT ;
    USE SIGNAL ;
    PORT
      LAYER M3 ;
        RECT  62.028 0 62.046 0.144 ;
    END
  END xw[982]
  PIN xw[983]
    DIRECTION INPUT ;
    USE SIGNAL ;
    PORT
      LAYER M5 ;
        RECT  59.136 0 59.16 0.192 ;
    END
  END xw[983]
  PIN xw[984]
    DIRECTION INPUT ;
    USE SIGNAL ;
    PORT
      LAYER M3 ;
        RECT  62.136 0 62.154 0.144 ;
    END
  END xw[984]
  PIN xw[985]
    DIRECTION INPUT ;
    USE SIGNAL ;
    PORT
      LAYER M5 ;
        RECT  59.232 0 59.256 0.192 ;
    END
  END xw[985]
  PIN xw[986]
    DIRECTION INPUT ;
    USE SIGNAL ;
    PORT
      LAYER M3 ;
        RECT  62.244 0 62.262 0.144 ;
    END
  END xw[986]
  PIN xw[987]
    DIRECTION INPUT ;
    USE SIGNAL ;
    PORT
      LAYER M5 ;
        RECT  59.328 0 59.352 0.192 ;
    END
  END xw[987]
  PIN xw[988]
    DIRECTION INPUT ;
    USE SIGNAL ;
    PORT
      LAYER M3 ;
        RECT  62.352 0 62.37 0.144 ;
    END
  END xw[988]
  PIN xw[989]
    DIRECTION INPUT ;
    USE SIGNAL ;
    PORT
      LAYER M5 ;
        RECT  59.424 0 59.448 0.192 ;
    END
  END xw[989]
  PIN xw[98]
    DIRECTION INPUT ;
    USE SIGNAL ;
    PORT
      LAYER M3 ;
        RECT  14.292 0 14.31 0.144 ;
    END
  END xw[98]
  PIN xw[990]
    DIRECTION INPUT ;
    USE SIGNAL ;
    PORT
      LAYER M3 ;
        RECT  62.46 0 62.478 0.144 ;
    END
  END xw[990]
  PIN xw[991]
    DIRECTION INPUT ;
    USE SIGNAL ;
    PORT
      LAYER M5 ;
        RECT  59.52 0 59.544 0.192 ;
    END
  END xw[991]
  PIN xw[992]
    DIRECTION INPUT ;
    USE SIGNAL ;
    PORT
      LAYER M3 ;
        RECT  62.568 0 62.586 0.144 ;
    END
  END xw[992]
  PIN xw[993]
    DIRECTION INPUT ;
    USE SIGNAL ;
    PORT
      LAYER M5 ;
        RECT  59.616 0 59.64 0.192 ;
    END
  END xw[993]
  PIN xw[994]
    DIRECTION INPUT ;
    USE SIGNAL ;
    PORT
      LAYER M3 ;
        RECT  62.676 0 62.694 0.144 ;
    END
  END xw[994]
  PIN xw[995]
    DIRECTION INPUT ;
    USE SIGNAL ;
    PORT
      LAYER M5 ;
        RECT  59.712 0 59.736 0.192 ;
    END
  END xw[995]
  PIN xw[996]
    DIRECTION INPUT ;
    USE SIGNAL ;
    PORT
      LAYER M3 ;
        RECT  62.784 0 62.802 0.144 ;
    END
  END xw[996]
  PIN xw[997]
    DIRECTION INPUT ;
    USE SIGNAL ;
    PORT
      LAYER M5 ;
        RECT  59.808 0 59.832 0.192 ;
    END
  END xw[997]
  PIN xw[998]
    DIRECTION INPUT ;
    USE SIGNAL ;
    PORT
      LAYER M3 ;
        RECT  62.892 0 62.91 0.144 ;
    END
  END xw[998]
  PIN xw[999]
    DIRECTION INPUT ;
    USE SIGNAL ;
    PORT
      LAYER M5 ;
        RECT  59.904 0 59.928 0.192 ;
    END
  END xw[999]
  PIN xw[99]
    DIRECTION INPUT ;
    USE SIGNAL ;
    PORT
      LAYER M5 ;
        RECT  16.704 0 16.728 0.192 ;
    END
  END xw[99]
  PIN xw[9]
    DIRECTION INPUT ;
    USE SIGNAL ;
    PORT
      LAYER M5 ;
        RECT  12.384 0 12.408 0.192 ;
    END
  END xw[9]
  PIN VDD
    DIRECTION INOUT ;
    USE POWER ;
    PORT
      LAYER M5 ;
        RECT  67.392 2.151 67.512 32.409 ;
        RECT  61.992 2.151 62.112 32.409 ;
        RECT  56.592 2.151 56.712 32.409 ;
        RECT  51.192 2.151 51.312 32.409 ;
        RECT  45.792 2.151 45.912 32.409 ;
        RECT  40.392 2.151 40.512 32.409 ;
        RECT  34.992 2.151 35.112 32.409 ;
        RECT  29.592 2.151 29.712 32.409 ;
        RECT  24.192 2.151 24.312 32.409 ;
        RECT  18.792 2.151 18.912 32.409 ;
        RECT  13.392 2.151 13.512 32.409 ;
        RECT  7.992 2.151 8.112 32.409 ;
        RECT  2.592 2.151 2.712 32.409 ;
    END
  END VDD
  PIN VSS
    DIRECTION INOUT ;
    USE GROUND ;
    PORT
      LAYER M5 ;
        RECT  67.2 2.137 67.32 32.423 ;
        RECT  61.8 2.137 61.92 32.423 ;
        RECT  56.4 2.137 56.52 32.423 ;
        RECT  51 2.137 51.12 32.423 ;
        RECT  45.6 2.137 45.72 32.423 ;
        RECT  40.2 2.137 40.32 32.423 ;
        RECT  34.8 2.137 34.92 32.423 ;
        RECT  29.4 2.137 29.52 32.423 ;
        RECT  24 2.137 24.12 32.423 ;
        RECT  18.6 2.137 18.72 32.423 ;
        RECT  13.2 2.137 13.32 32.423 ;
        RECT  7.8 2.137 7.92 32.423 ;
        RECT  2.4 2.137 2.52 32.423 ;
    END
  END VSS
  # OT_OBS_CLOSED layer=M5 d_um=1.536 added=75
  OBS
    LAYER RVTN ;
     RECT  2.16 2.16 71.28 2.295 ;
     RECT  2.16 2.565 71.28 2.835 ;
     RECT  2.16 3.105 71.28 3.375 ;
     RECT  2.16 3.645 71.28 3.915 ;
     RECT  2.16 4.185 71.28 4.455 ;
     RECT  2.16 4.725 71.28 4.995 ;
     RECT  2.16 5.265 71.28 5.535 ;
     RECT  2.16 5.805 71.28 6.075 ;
     RECT  2.16 6.345 71.28 6.615 ;
     RECT  2.16 6.885 71.28 7.155 ;
     RECT  2.16 7.425 71.28 7.695 ;
     RECT  2.16 7.965 71.28 8.235 ;
     RECT  2.16 8.505 71.28 8.775 ;
     RECT  2.16 9.045 71.28 9.315 ;
     RECT  2.16 9.585 71.28 9.855 ;
     RECT  2.16 10.125 71.28 10.395 ;
     RECT  2.16 10.665 71.28 10.935 ;
     RECT  2.16 11.205 71.28 11.475 ;
     RECT  2.16 11.745 71.28 12.015 ;
     RECT  2.16 12.285 71.28 12.555 ;
     RECT  2.16 12.825 71.28 13.095 ;
     RECT  2.16 13.365 71.28 13.635 ;
     RECT  2.16 13.905 71.28 14.175 ;
     RECT  2.16 14.445 71.28 14.715 ;
     RECT  2.16 14.985 71.28 15.255 ;
     RECT  2.16 15.525 71.28 15.795 ;
     RECT  2.16 16.065 71.28 16.335 ;
     RECT  2.16 16.605 71.28 16.875 ;
     RECT  2.16 17.145 71.28 17.415 ;
     RECT  2.16 17.685 71.28 17.955 ;
     RECT  2.16 18.225 71.28 18.495 ;
     RECT  2.16 18.765 71.28 19.035 ;
     RECT  2.16 19.305 71.28 19.575 ;
     RECT  2.16 19.845 71.28 20.115 ;
     RECT  2.16 20.385 71.28 20.655 ;
     RECT  2.16 20.925 71.28 21.195 ;
     RECT  2.16 21.465 71.28 21.735 ;
     RECT  2.16 22.005 71.28 22.275 ;
     RECT  2.16 22.545 71.28 22.815 ;
     RECT  2.16 23.085 71.28 23.355 ;
     RECT  2.16 23.625 71.28 23.895 ;
     RECT  2.16 24.165 71.28 24.435 ;
     RECT  2.16 24.705 71.28 24.975 ;
     RECT  2.16 25.245 71.28 25.515 ;
     RECT  2.16 25.785 71.28 26.055 ;
     RECT  2.16 26.325 71.28 26.595 ;
     RECT  2.16 26.865 71.28 27.135 ;
     RECT  2.16 27.405 71.28 27.675 ;
     RECT  2.16 27.945 71.28 28.215 ;
     RECT  2.16 28.485 71.28 28.755 ;
     RECT  2.16 29.025 71.28 29.295 ;
     RECT  2.16 29.565 71.28 29.835 ;
     RECT  2.16 30.105 71.28 30.375 ;
     RECT  2.16 30.645 71.28 30.915 ;
     RECT  2.16 31.185 71.28 31.455 ;
     RECT  2.16 31.725 71.28 31.995 ;
     RECT  2.16 32.265 71.28 32.4 ;
    LAYER RVTP ;
     RECT  2.16 2.295 71.28 2.565 ;
     RECT  2.16 2.835 71.28 3.105 ;
     RECT  2.16 3.375 71.28 3.645 ;
     RECT  2.16 3.915 71.28 4.185 ;
     RECT  2.16 4.455 71.28 4.725 ;
     RECT  2.16 4.995 71.28 5.265 ;
     RECT  2.16 5.535 71.28 5.805 ;
     RECT  2.16 6.075 71.28 6.345 ;
     RECT  2.16 6.615 71.28 6.885 ;
     RECT  2.16 7.155 71.28 7.425 ;
     RECT  2.16 7.695 71.28 7.965 ;
     RECT  2.16 8.235 71.28 8.505 ;
     RECT  2.16 8.775 71.28 9.045 ;
     RECT  2.16 9.315 71.28 9.585 ;
     RECT  2.16 9.855 71.28 10.125 ;
     RECT  2.16 10.395 71.28 10.665 ;
     RECT  2.16 10.935 71.28 11.205 ;
     RECT  2.16 11.475 71.28 11.745 ;
     RECT  2.16 12.015 71.28 12.285 ;
     RECT  2.16 12.555 71.28 12.825 ;
     RECT  2.16 13.095 71.28 13.365 ;
     RECT  2.16 13.635 71.28 13.905 ;
     RECT  2.16 14.175 71.28 14.445 ;
     RECT  2.16 14.715 71.28 14.985 ;
     RECT  2.16 15.255 71.28 15.525 ;
     RECT  2.16 15.795 71.28 16.065 ;
     RECT  2.16 16.335 71.28 16.605 ;
     RECT  2.16 16.875 71.28 17.145 ;
     RECT  2.16 17.415 71.28 17.685 ;
     RECT  2.16 17.955 71.28 18.225 ;
     RECT  2.16 18.495 71.28 18.765 ;
     RECT  2.16 19.035 71.28 19.305 ;
     RECT  2.16 19.575 71.28 19.845 ;
     RECT  2.16 20.115 71.28 20.385 ;
     RECT  2.16 20.655 71.28 20.925 ;
     RECT  2.16 21.195 71.28 21.465 ;
     RECT  2.16 21.735 71.28 22.005 ;
     RECT  2.16 22.275 71.28 22.545 ;
     RECT  2.16 22.815 71.28 23.085 ;
     RECT  2.16 23.355 71.28 23.625 ;
     RECT  2.16 23.895 71.28 24.165 ;
     RECT  2.16 24.435 71.28 24.705 ;
     RECT  2.16 24.975 71.28 25.245 ;
     RECT  2.16 25.515 71.28 25.785 ;
     RECT  2.16 26.055 71.28 26.325 ;
     RECT  2.16 26.595 71.28 26.865 ;
     RECT  2.16 27.135 71.28 27.405 ;
     RECT  2.16 27.675 71.28 27.945 ;
     RECT  2.16 28.215 71.28 28.485 ;
     RECT  2.16 28.755 71.28 29.025 ;
     RECT  2.16 29.295 71.28 29.565 ;
     RECT  2.16 29.835 71.28 30.105 ;
     RECT  2.16 30.375 71.28 30.645 ;
     RECT  2.16 30.915 71.28 31.185 ;
     RECT  2.16 31.455 71.28 31.725 ;
     RECT  2.16 31.995 71.28 32.265 ;
    LAYER M1 ;
     RECT  2.16 2.151 71.28 32.409 ;
    LAYER M2 ;
     RECT  0.211 17.082 2.16 17.1 ;
     RECT  10.003 0.144 10.103 0.162 ;
     RECT  10.831 0.144 10.939 0.162 ;
     RECT  10.939 0.144 11.155 0.234 ;
     RECT  2.16 2.151 11.587 32.409 ;
     RECT  11.587 1.728 11.831 32.409 ;
     RECT  11.155 0.144 12.343 0.324 ;
     RECT  12.343 0.144 12.479 0.396 ;
     RECT  12.479 0.144 12.551 0.324 ;
     RECT  11.831 2.151 12.811 32.409 ;
     RECT  12.811 2.034 13.171 32.409 ;
     RECT  13.171 1.692 13.747 32.409 ;
     RECT  13.747 1.386 13.855 32.409 ;
     RECT  13.855 1.26 13.891 32.409 ;
     RECT  13.891 1.152 14.215 32.409 ;
     RECT  12.551 0.144 14.387 0.234 ;
     RECT  14.215 1.152 14.711 32.796 ;
     RECT  14.711 1.728 15.251 32.796 ;
     RECT  14.387 0.144 15.583 0.162 ;
     RECT  15.251 2.034 15.691 32.796 ;
     RECT  14.755 33.588 15.691 33.606 ;
     RECT  15.547 1.152 15.719 1.242 ;
     RECT  15.583 0.144 15.791 0.234 ;
     RECT  15.719 1.224 15.791 1.242 ;
     RECT  15.691 2.034 16.447 33.606 ;
     RECT  16.447 1.656 16.555 33.606 ;
     RECT  16.555 1.341 16.591 33.606 ;
     RECT  16.591 1.296 16.663 33.606 ;
     RECT  16.663 1.152 16.727 33.606 ;
     RECT  16.727 1.152 16.763 1.242 ;
     RECT  16.727 2.034 16.771 33.606 ;
     RECT  16.763 1.224 17.051 1.242 ;
     RECT  15.791 0.144 17.095 0.162 ;
     RECT  16.771 2.034 17.195 34.344 ;
     RECT  17.095 0.144 17.447 0.324 ;
     RECT  17.447 0.144 18.283 0.279 ;
     RECT  18.283 0.144 18.319 0.324 ;
     RECT  17.195 2.106 18.355 34.344 ;
     RECT  18.355 1.728 18.635 34.344 ;
     RECT  18.319 0.144 18.851 0.594 ;
     RECT  18.635 1.926 19.363 34.344 ;
     RECT  19.363 1.656 19.679 34.344 ;
     RECT  18.851 0.144 20.119 0.162 ;
     RECT  19.679 1.728 20.147 34.344 ;
     RECT  20.147 1.8 20.219 34.344 ;
     RECT  20.119 0.144 21.011 0.234 ;
     RECT  20.219 1.962 21.091 34.344 ;
     RECT  21.091 1.728 21.263 34.344 ;
     RECT  21.263 1.728 21.803 33.912 ;
     RECT  21.803 1.8 21.839 33.912 ;
     RECT  21.839 2.034 21.911 33.912 ;
     RECT  21.011 0.144 21.955 0.162 ;
     RECT  21.955 0.144 22.055 0.234 ;
     RECT  21.911 2.034 22.307 33.606 ;
     RECT  22.055 0.144 22.819 0.162 ;
     RECT  22.819 0.144 22.891 0.234 ;
     RECT  22.891 0.144 22.927 0.279 ;
     RECT  22.307 2.106 22.963 33.606 ;
     RECT  22.963 2.106 23.135 33.804 ;
     RECT  23.135 2.106 23.279 33.759 ;
     RECT  22.927 0.144 23.575 0.324 ;
     RECT  23.279 2.106 23.755 33.606 ;
     RECT  23.575 0.144 23.819 0.396 ;
     RECT  23.819 0.144 23.927 0.324 ;
     RECT  23.755 2.07 23.999 33.606 ;
     RECT  23.999 2.151 24.727 33.606 ;
     RECT  24.727 1.728 25.151 33.606 ;
     RECT  25.151 1.728 25.375 33.372 ;
     RECT  23.927 0.144 25.411 0.234 ;
     RECT  25.375 1.152 25.475 33.372 ;
     RECT  25.411 0.144 25.547 0.324 ;
     RECT  25.547 0.144 25.655 0.279 ;
     RECT  25.655 0.144 26.195 0.234 ;
     RECT  25.475 2.106 26.267 33.372 ;
     RECT  25.475 1.152 26.311 1.242 ;
     RECT  26.267 2.106 26.311 33.336 ;
     RECT  26.195 0.144 26.447 0.198 ;
     RECT  26.311 1.152 26.663 33.336 ;
     RECT  26.663 1.152 27.239 1.17 ;
     RECT  26.663 2.151 27.715 33.336 ;
     RECT  27.715 1.728 27.851 33.336 ;
     RECT  27.851 2.151 27.931 33.336 ;
     RECT  26.447 0.144 28.111 0.162 ;
     RECT  27.931 2.151 28.247 33.804 ;
     RECT  28.183 1.152 28.499 1.17 ;
     RECT  28.111 0.144 29.047 0.324 ;
     RECT  29.047 0.144 29.219 0.594 ;
     RECT  28.247 2.151 29.299 33.066 ;
     RECT  29.299 1.728 29.335 33.066 ;
     RECT  29.335 1.152 29.399 33.066 ;
     RECT  29.399 1.998 29.759 33.066 ;
     RECT  29.219 0.144 30.083 0.279 ;
     RECT  29.759 2.151 30.371 33.066 ;
     RECT  30.371 2.151 30.443 32.832 ;
     RECT  30.083 0.144 30.919 0.162 ;
     RECT  29.399 1.152 30.991 1.17 ;
     RECT  30.443 2.151 31.207 32.796 ;
     RECT  30.991 1.152 31.343 1.242 ;
     RECT  30.919 0.144 31.567 0.234 ;
     RECT  31.343 1.188 31.567 1.242 ;
     RECT  31.567 34.47 31.603 34.488 ;
     RECT  31.603 34.398 31.703 34.488 ;
     RECT  31.567 1.188 31.847 1.278 ;
     RECT  31.847 1.224 31.891 1.278 ;
     RECT  31.207 2.151 31.891 33.066 ;
     RECT  31.891 1.224 32.027 33.066 ;
     RECT  32.027 1.224 32.135 32.796 ;
     RECT  32.135 1.224 32.459 1.359 ;
     RECT  32.323 33.741 32.495 33.759 ;
     RECT  31.567 0.144 32.675 0.324 ;
     RECT  32.135 2.151 32.899 32.796 ;
     RECT  32.899 2.151 33.115 33.066 ;
     RECT  33.115 2.106 33.223 33.066 ;
     RECT  32.791 1.152 33.295 1.17 ;
     RECT  33.223 2.106 33.367 33.372 ;
     RECT  32.675 0.144 33.403 0.279 ;
     RECT  33.367 2.106 33.467 33.759 ;
     RECT  33.403 0.144 33.539 0.324 ;
     RECT  33.539 0.144 33.863 0.279 ;
     RECT  33.863 0.144 34.043 0.234 ;
     RECT  33.295 1.152 34.231 1.242 ;
     RECT  33.467 2.106 34.231 33.372 ;
     RECT  34.231 1.152 34.403 33.372 ;
     RECT  34.043 0.144 34.915 0.162 ;
     RECT  34.915 0.144 35.023 0.234 ;
     RECT  35.023 0.144 35.303 0.279 ;
     RECT  34.843 34.362 35.311 34.38 ;
     RECT  35.311 34.362 35.339 34.452 ;
     RECT  34.403 1.152 35.563 1.359 ;
     RECT  34.403 2.106 35.563 33.372 ;
     RECT  35.563 1.152 35.879 33.372 ;
     RECT  35.879 1.728 35.951 33.372 ;
     RECT  35.303 0.144 36.103 0.234 ;
     RECT  36.103 0.144 36.239 0.324 ;
     RECT  36.239 0.144 36.455 0.279 ;
     RECT  35.951 2.106 36.679 33.372 ;
     RECT  36.607 1.152 36.715 1.17 ;
     RECT  36.679 2.106 36.959 33.408 ;
     RECT  36.715 1.152 37.075 1.242 ;
     RECT  36.455 0.144 37.363 0.162 ;
     RECT  37.075 1.152 37.463 1.359 ;
     RECT  37.463 1.152 37.499 1.278 ;
     RECT  37.363 0.144 37.643 0.234 ;
     RECT  37.643 0.144 37.751 0.162 ;
     RECT  35.339 34.434 38.479 34.452 ;
     RECT  36.959 2.151 38.515 33.408 ;
     RECT  38.479 34.434 38.515 34.488 ;
     RECT  38.515 34.398 38.615 34.488 ;
     RECT  37.499 1.152 38.695 1.17 ;
     RECT  38.515 2.034 38.695 33.408 ;
     RECT  38.587 0.144 38.911 0.162 ;
     RECT  38.695 1.152 39.263 33.408 ;
     RECT  38.911 0.144 39.451 0.234 ;
     RECT  39.451 0.144 39.559 0.324 ;
     RECT  39.263 1.152 39.659 1.17 ;
     RECT  39.559 0.144 39.739 0.396 ;
     RECT  39.263 2.034 40.091 33.408 ;
     RECT  39.739 0.144 40.127 0.594 ;
     RECT  40.127 0.144 40.343 0.234 ;
     RECT  40.091 2.106 40.523 33.408 ;
     RECT  40.343 0.144 40.847 0.162 ;
     RECT  40.783 1.152 40.883 1.17 ;
     RECT  40.523 2.151 41.539 33.408 ;
     RECT  38.615 34.434 41.611 34.452 ;
     RECT  41.539 2.106 41.639 33.408 ;
     RECT  41.611 34.434 41.647 34.488 ;
     RECT  41.647 34.398 41.747 34.488 ;
     RECT  41.899 0.144 42.467 0.162 ;
     RECT  42.475 0.216 42.683 0.234 ;
     RECT  43.195 0.144 44.095 0.162 ;
     RECT  44.095 0.144 44.267 0.234 ;
     RECT  41.639 2.151 44.419 33.408 ;
     RECT  44.267 0.144 44.447 0.162 ;
     RECT  45.175 0.144 45.283 0.162 ;
     RECT  44.419 2.106 45.319 33.408 ;
     RECT  45.319 1.998 45.391 33.408 ;
     RECT  45.283 0.144 45.419 0.324 ;
     RECT  45.391 1.341 45.427 33.408 ;
     RECT  45.427 1.26 45.599 33.408 ;
     RECT  45.599 1.998 45.779 33.408 ;
     RECT  45.419 0.144 45.959 0.279 ;
     RECT  45.959 0.144 46.139 0.234 ;
     RECT  45.779 2.07 46.283 33.408 ;
     RECT  46.139 0.144 46.903 0.162 ;
     RECT  46.903 0.144 47.003 0.234 ;
     RECT  46.255 1.152 47.011 1.17 ;
     RECT  47.003 0.144 47.147 0.198 ;
     RECT  41.747 34.398 47.363 34.452 ;
     RECT  46.283 2.106 47.903 33.408 ;
     RECT  47.363 34.398 47.939 34.416 ;
     RECT  47.011 1.152 48.011 1.242 ;
     RECT  47.903 33.318 48.047 33.408 ;
     RECT  48.047 33.39 48.155 33.408 ;
     RECT  47.147 0.144 48.163 0.162 ;
     RECT  47.903 2.106 48.839 32.49 ;
     RECT  48.011 1.152 48.911 1.17 ;
     RECT  48.839 2.106 49.063 32.409 ;
     RECT  49.063 1.728 49.343 32.409 ;
     RECT  50.611 33.624 50.819 33.642 ;
     RECT  50.827 34.398 50.927 34.488 ;
     RECT  50.927 34.47 50.963 34.488 ;
     RECT  49.343 2.106 50.971 32.409 ;
     RECT  50.971 2.106 50.999 32.562 ;
     RECT  50.999 2.151 51.143 32.562 ;
     RECT  51.143 2.151 51.287 32.49 ;
     RECT  48.163 0.144 52.303 0.234 ;
     RECT  52.303 0.144 52.439 0.324 ;
     RECT  51.287 2.151 52.519 32.409 ;
     RECT  52.519 2.151 52.735 32.454 ;
     RECT  52.735 2.151 52.835 32.526 ;
     RECT  53.203 1.341 53.311 1.359 ;
     RECT  53.311 1.152 53.519 1.359 ;
     RECT  53.519 1.152 53.555 1.278 ;
     RECT  52.439 0.144 53.563 0.162 ;
     RECT  52.835 2.151 53.951 32.454 ;
     RECT  53.563 0.144 54.167 0.234 ;
     RECT  53.555 1.152 54.383 1.17 ;
     RECT  53.951 2.151 54.679 32.409 ;
     RECT  54.679 2.106 54.859 32.409 ;
     RECT  54.167 0.144 55.579 0.162 ;
     RECT  54.859 1.728 55.579 32.409 ;
     RECT  55.579 1.152 55.895 32.409 ;
     RECT  55.895 2.106 56.003 32.409 ;
     RECT  55.579 0.144 56.435 0.234 ;
     RECT  55.895 1.152 56.731 1.17 ;
     RECT  56.731 1.152 56.867 1.242 ;
     RECT  56.867 1.152 57.011 1.17 ;
     RECT  56.435 0.144 57.155 0.162 ;
     RECT  56.003 2.151 57.631 32.409 ;
     RECT  57.631 2.106 57.883 32.409 ;
     RECT  58.027 0.144 58.207 0.162 ;
     RECT  57.883 2.034 58.243 32.409 ;
     RECT  58.207 0.144 58.271 0.234 ;
     RECT  58.243 1.728 58.379 32.409 ;
     RECT  58.379 2.106 58.775 32.409 ;
     RECT  58.271 0.216 58.811 0.234 ;
     RECT  59.431 0.144 59.539 0.162 ;
     RECT  59.539 0.144 60.331 0.198 ;
     RECT  60.331 0.144 60.431 0.234 ;
     RECT  60.431 0.144 61.771 0.162 ;
     RECT  61.771 0.144 61.835 0.234 ;
     RECT  61.835 0.216 61.943 0.234 ;
     RECT  63.679 0.144 64.211 0.162 ;
     RECT  58.775 2.151 71.28 32.409 ;
     RECT  71.28 20.898 71.843 23.184 ;
     RECT  71.843 22.518 71.879 22.536 ;
    LAYER M3 ;
     RECT  9 0.108 64.206 0.167 ;
     RECT  9 0.167 64.134 2.371 ;
     RECT  2.415 2.143 2.505 2.413 ;
     RECT  7.815 2.143 7.905 2.413 ;
     RECT  67.215 2.143 67.305 2.413 ;
     RECT  9 2.371 64.206 2.641 ;
     RECT  9 2.641 64.674 3.335 ;
     RECT  9.108 3.335 64.674 3.407 ;
     RECT  9.108 3.407 9.234 3.605 ;
     RECT  10.008 3.407 64.674 3.605 ;
     RECT  9.216 3.605 9.234 3.875 ;
     RECT  10.224 3.605 64.674 16.835 ;
     RECT  0.216 16.267 0.234 17.105 ;
     RECT  63.972 16.835 64.674 17.951 ;
     RECT  10.224 16.835 63.054 18.293 ;
     RECT  13.215 18.293 63.054 18.527 ;
     RECT  13.215 18.527 62.766 19.031 ;
     RECT  10.224 18.293 12.402 19.103 ;
     RECT  63.972 17.951 63.99 19.877 ;
     RECT  10.98 19.103 12.402 20.011 ;
     RECT  13.215 19.031 62.298 20.011 ;
     RECT  10.98 20.011 62.298 20.345 ;
     RECT  10.98 20.345 59.13 20.579 ;
     RECT  71.244 20.695 71.262 20.731 ;
     RECT  70.92 20.731 71.262 20.893 ;
     RECT  70.92 20.893 71.838 21.001 ;
     RECT  70.848 21.001 71.838 21.271 ;
     RECT  60.12 20.345 62.298 21.533 ;
     RECT  70.776 21.271 71.838 21.541 ;
     RECT  70.704 21.541 71.838 21.631 ;
     RECT  70.56 21.631 71.838 21.667 ;
     RECT  10.98 20.579 54.882 21.731 ;
     RECT  70.344 21.667 71.838 21.739 ;
     RECT  70.344 21.739 71.874 21.775 ;
     RECT  70.308 21.775 71.874 21.803 ;
     RECT  70.308 21.803 71.082 21.811 ;
     RECT  55.692 20.579 59.13 21.839 ;
     RECT  60.12 21.533 62.097 21.965 ;
     RECT  11.988 21.731 54.882 22.061 ;
     RECT  71.82 21.803 71.874 22.109 ;
     RECT  70.164 21.811 71.082 22.199 ;
     RECT  70.164 22.199 70.938 22.235 ;
     RECT  13.215 22.061 54.882 22.343 ;
     RECT  10.98 21.731 10.998 22.469 ;
     RECT  71.856 22.109 71.874 22.541 ;
     RECT  56.376 21.839 59.13 22.585 ;
     RECT  55.656 22.585 59.13 22.649 ;
     RECT  14.796 22.343 54.882 22.711 ;
     RECT  55.656 22.649 57.042 22.711 ;
     RECT  10.224 19.103 10.242 22.775 ;
     RECT  14.796 22.711 57.042 22.775 ;
     RECT  70.308 22.235 70.722 22.775 ;
     RECT  57.816 22.649 59.13 22.792 ;
     RECT  14.796 22.775 55.638 22.811 ;
     RECT  60.12 21.965 60.714 22.919 ;
     RECT  11.988 22.061 12.006 23.009 ;
     RECT  14.796 22.811 54.846 23.009 ;
     RECT  70.704 22.775 70.722 23.125 ;
     RECT  67.215 2.413 67.497 23.161 ;
     RECT  69.3 22.891 69.318 23.161 ;
     RECT  13.215 22.343 13.95 23.165 ;
     RECT  55.584 22.811 55.638 23.279 ;
     RECT  66.708 23.161 67.497 23.279 ;
     RECT  70.704 23.125 70.938 23.279 ;
     RECT  71.82 23.161 71.838 23.309 ;
     RECT  60.228 22.919 60.714 23.315 ;
     RECT  69.264 23.161 69.318 23.387 ;
     RECT  56.376 22.775 57.042 23.459 ;
     RECT  69.552 23.395 69.57 23.549 ;
     RECT  70.704 23.279 70.794 23.549 ;
     RECT  68.724 23.395 68.742 23.597 ;
     RECT  70.704 23.549 70.722 23.621 ;
     RECT  14.796 23.009 54.738 23.791 ;
     RECT  14.796 23.791 54.774 23.819 ;
     RECT  60.696 23.315 60.714 23.999 ;
     RECT  55.584 23.279 55.602 24.187 ;
     RECT  56.376 23.459 56.697 24.187 ;
     RECT  57.816 22.792 59.094 24.233 ;
     RECT  55.584 24.187 56.697 24.365 ;
     RECT  14.976 23.819 54.018 24.413 ;
     RECT  55.584 24.365 55.602 24.431 ;
     RECT  58.428 24.233 59.094 24.653 ;
     RECT  15.192 24.413 54.018 24.809 ;
     RECT  59.076 24.653 59.094 25.349 ;
     RECT  15.516 24.809 54.018 28.481 ;
     RECT  15.588 28.481 54.018 28.589 ;
     RECT  15.624 28.589 54.018 29.641 ;
     RECT  54.756 23.819 54.774 29.641 ;
     RECT  15.624 29.641 54.774 31.829 ;
     RECT  2.415 2.413 2.697 32.147 ;
     RECT  7.815 2.413 8.097 32.147 ;
     RECT  13.215 23.165 13.497 32.147 ;
     RECT  56.415 24.365 56.697 32.147 ;
     RECT  61.815 21.965 62.097 32.147 ;
     RECT  67.215 23.279 67.497 32.147 ;
     RECT  15.624 31.829 54.522 32.189 ;
     RECT  49.86 32.189 54.45 32.225 ;
     RECT  49.86 32.225 53.946 32.261 ;
     RECT  2.415 32.147 2.505 32.417 ;
     RECT  7.815 32.147 7.905 32.417 ;
     RECT  13.215 32.147 13.305 32.417 ;
     RECT  56.415 32.147 56.505 32.417 ;
     RECT  61.815 32.147 61.905 32.417 ;
     RECT  67.215 32.147 67.305 32.417 ;
     RECT  50.04 32.261 53.946 32.459 ;
     RECT  15.624 32.189 48.834 32.495 ;
     RECT  15.624 32.495 48.222 32.573 ;
     RECT  17.82 32.573 48.222 32.639 ;
     RECT  14.22 27.931 14.238 32.801 ;
     RECT  17.928 32.639 48.222 32.999 ;
     RECT  18 32.999 48.222 33.224 ;
     RECT  46.332 33.224 48.222 33.269 ;
     RECT  46.836 33.269 48.222 33.293 ;
     RECT  14.76 33.067 14.778 33.611 ;
     RECT  15.624 32.573 17.046 33.629 ;
     RECT  15.624 33.629 15.966 33.965 ;
     RECT  16.776 33.629 17.046 34.109 ;
     RECT  46.836 33.293 48.186 34.109 ;
     RECT  15.624 33.965 15.642 34.157 ;
     RECT  16.776 34.109 16.794 34.349 ;
     RECT  47.34 34.109 48.186 34.397 ;
     RECT  47.34 34.397 47.934 34.421 ;
     RECT  18 33.224 45.558 34.428 ;
     RECT  50.04 32.459 53.406 34.428 ;
     RECT  35.316 34.428 35.334 34.457 ;
     RECT  47.34 34.421 47.358 34.457 ;
    LAYER M4 ;
     RECT  0.229 20.112 2.408 20.136 ;
     RECT  2.408 2.148 2.512 32.412 ;
     RECT  2.512 2.418 2.704 32.142 ;
     RECT  2.704 20.112 7.808 20.136 ;
     RECT  7.808 2.148 7.912 32.412 ;
     RECT  7.912 2.418 8.104 32.142 ;
     RECT  9.277 0.144 9.925 0.168 ;
     RECT  11.185 3.312 11.437 3.336 ;
     RECT  11.437 3.072 11.509 3.336 ;
     RECT  11.509 2.832 11.593 3.336 ;
     RECT  11.989 1.728 12.044 1.752 ;
     RECT  9.925 0.144 12.157 0.216 ;
     RECT  12.044 1.68 12.157 1.752 ;
     RECT  11.593 3.072 12.181 3.336 ;
     RECT  12.181 3.072 12.277 3.432 ;
     RECT  12.157 0.144 12.515 1.752 ;
     RECT  12.515 0.144 12.557 0.6 ;
     RECT  12.557 0.24 12.611 0.6 ;
     RECT  12.515 1.68 12.697 1.752 ;
     RECT  12.277 3.072 12.697 3.672 ;
     RECT  8.104 20.112 12.949 20.136 ;
     RECT  12.697 1.68 13.045 3.672 ;
     RECT  13.045 1.68 13.093 4.584 ;
     RECT  13.093 1.68 13.208 4.968 ;
     RECT  11.509 17.952 13.208 17.976 ;
     RECT  12.949 20.112 13.208 20.328 ;
     RECT  12.553 22.032 13.208 22.056 ;
     RECT  13.208 1.68 13.312 32.412 ;
     RECT  13.312 1.68 13.504 32.142 ;
     RECT  12.611 0.288 13.525 0.6 ;
     RECT  13.504 1.68 13.525 5.16 ;
     RECT  13.525 0.288 13.777 5.16 ;
     RECT  13.777 0.192 13.811 5.16 ;
     RECT  13.811 0.192 13.885 3.144 ;
     RECT  13.885 0.144 14.213 3.144 ;
     RECT  14.213 0.192 14.243 3.144 ;
     RECT  13.504 27.936 14.249 27.96 ;
     RECT  14.243 0.192 14.509 2.856 ;
     RECT  13.504 20.112 14.725 22.056 ;
     RECT  13.504 23.136 14.725 23.16 ;
     RECT  13.504 17.952 14.773 18.84 ;
     RECT  13.504 30.048 14.773 30.072 ;
     RECT  14.705 33.072 14.789 33.096 ;
     RECT  13.811 4.224 15.317 5.16 ;
     RECT  15.349 27.984 15.589 28.008 ;
     RECT  14.965 24.384 15.613 24.408 ;
     RECT  14.725 20.112 15.637 23.16 ;
     RECT  15.613 24.384 15.637 24.696 ;
     RECT  15.637 32.208 15.649 32.232 ;
     RECT  15.613 34.128 15.685 34.152 ;
     RECT  14.773 30.048 15.733 30.312 ;
     RECT  15.649 31.728 15.733 32.232 ;
     RECT  15.637 20.112 15.781 24.696 ;
     RECT  15.317 3.648 15.829 5.16 ;
     RECT  14.773 17.184 15.829 18.84 ;
     RECT  15.733 30.048 15.865 32.232 ;
     RECT  14.509 0.192 15.893 2.328 ;
     RECT  15.829 3.408 15.893 5.256 ;
     RECT  15.893 0.192 15.923 5.256 ;
     RECT  15.781 20.112 15.925 25.56 ;
     RECT  15.685 34.128 15.925 34.248 ;
     RECT  15.925 34.128 15.937 34.392 ;
     RECT  15.923 0.192 15.977 4.44 ;
     RECT  15.977 1.104 16.067 2.376 ;
     RECT  15.865 30.048 16.117 32.28 ;
     RECT  15.977 3.36 16.163 4.44 ;
     RECT  15.589 27.984 16.165 28.68 ;
     RECT  16.117 29.76 16.165 32.28 ;
     RECT  15.937 33.936 16.189 34.392 ;
     RECT  15.829 17.184 16.261 19.08 ;
     RECT  15.925 20.112 16.261 25.608 ;
     RECT  16.165 27.984 16.261 32.28 ;
     RECT  16.189 33.504 16.261 34.392 ;
     RECT  16.261 17.184 16.453 25.608 ;
     RECT  16.405 26.88 16.453 26.904 ;
     RECT  16.067 1.104 16.835 2.328 ;
     RECT  16.453 17.184 16.837 26.904 ;
     RECT  16.835 1.104 16.945 2.28 ;
     RECT  16.837 17.136 17.089 26.904 ;
     RECT  16.261 27.984 17.089 34.392 ;
     RECT  16.945 0.192 17.129 2.28 ;
     RECT  16.163 3.36 17.273 4.152 ;
     RECT  17.089 17.136 17.749 34.392 ;
     RECT  17.273 3.984 17.809 4.152 ;
     RECT  17.129 0.192 17.921 0.504 ;
     RECT  17.129 1.728 18.061 2.28 ;
     RECT  17.921 0.288 18.169 0.504 ;
     RECT  18.169 0.288 18.277 0.552 ;
     RECT  18.061 1.728 18.277 2.904 ;
     RECT  17.809 3.984 18.277 4.68 ;
     RECT  18.277 0.288 18.493 4.68 ;
     RECT  18.493 0.288 18.563 5.544 ;
     RECT  18.563 0.48 18.565 5.544 ;
     RECT  18.565 0.48 18.608 5.592 ;
     RECT  17.749 17.088 18.608 34.392 ;
     RECT  18.608 0.48 18.755 34.392 ;
     RECT  18.755 0.576 18.904 34.392 ;
     RECT  18.904 0.576 19.523 2.328 ;
     RECT  18.904 3.36 19.685 5.64 ;
     RECT  19.523 1.728 19.715 2.328 ;
     RECT  19.685 3.36 19.829 5.544 ;
     RECT  19.829 3.36 19.897 5.16 ;
     RECT  19.717 0.528 20.005 0.552 ;
     RECT  19.897 3.312 20.149 5.16 ;
     RECT  20.149 2.832 20.291 5.16 ;
     RECT  20.291 2.832 20.771 5.016 ;
     RECT  19.715 1.728 20.837 1.752 ;
     RECT  20.771 2.976 21.203 5.016 ;
     RECT  21.157 14.832 21.269 14.856 ;
     RECT  20.005 0.48 21.301 0.552 ;
     RECT  21.26 1.68 21.347 1.704 ;
     RECT  21.203 2.976 21.443 4.728 ;
     RECT  21.301 0.288 21.625 0.552 ;
     RECT  21.443 2.976 21.665 4.632 ;
     RECT  21.625 0.288 21.697 0.6 ;
     RECT  21.665 2.976 21.733 4.584 ;
     RECT  21.697 0.288 21.877 1.128 ;
     RECT  21.733 2.832 22.124 4.584 ;
     RECT  21.877 0.192 22.525 1.128 ;
     RECT  22.124 2.256 22.525 4.584 ;
     RECT  22.525 0.192 22.733 4.584 ;
     RECT  22.733 0.192 22.817 4.92 ;
     RECT  22.817 0.192 22.849 4.584 ;
     RECT  22.849 0.144 23.363 4.584 ;
     RECT  23.363 0.144 23.933 0.504 ;
     RECT  23.363 1.68 24.001 4.584 ;
     RECT  24.001 1.68 24.008 4.68 ;
     RECT  23.677 14.832 24.008 14.856 ;
     RECT  18.904 16.32 24.008 34.392 ;
     RECT  24.008 1.68 24.304 34.392 ;
     RECT  23.933 0.192 24.337 0.504 ;
     RECT  24.304 1.68 24.365 5.736 ;
     RECT  24.337 0.192 24.419 0.408 ;
     RECT  24.365 1.728 24.515 5.736 ;
     RECT  24.515 1.728 24.689 4.584 ;
     RECT  24.419 0.192 24.899 0.36 ;
     RECT  24.689 1.728 25.013 4.2 ;
     RECT  25.013 1.728 25.091 2.28 ;
     RECT  25.013 3.312 25.091 4.2 ;
     RECT  24.899 0.192 25.301 0.216 ;
     RECT  25.091 3.984 25.667 4.2 ;
     RECT  24.515 5.712 25.955 5.736 ;
     RECT  25.813 4.56 25.984 4.584 ;
     RECT  25.091 1.728 26.053 1.752 ;
     RECT  25.984 4.56 26.093 4.632 ;
     RECT  26.017 0.144 26.341 0.168 ;
     RECT  26.341 0.144 26.453 0.216 ;
     RECT  26.453 0.192 26.593 0.216 ;
     RECT  26.053 1.728 26.627 2.328 ;
     RECT  26.627 2.256 26.629 2.328 ;
     RECT  26.197 3.408 26.629 3.432 ;
     RECT  25.981 14.832 26.633 14.856 ;
     RECT  26.593 0.192 26.773 0.552 ;
     RECT  26.828 4.512 26.915 4.536 ;
     RECT  26.629 2.256 27.011 3.432 ;
     RECT  24.304 16.368 27.241 34.392 ;
     RECT  27.241 16.032 27.313 34.392 ;
     RECT  27.061 4.56 27.421 5.112 ;
     RECT  27.421 4.56 27.605 5.64 ;
     RECT  26.773 0.192 27.637 1.128 ;
     RECT  27.011 2.256 27.637 3.336 ;
     RECT  27.605 4.56 27.683 5.016 ;
     RECT  27.493 6.768 27.749 6.792 ;
     RECT  27.637 0.192 27.997 3.336 ;
     RECT  27.313 15.984 27.997 34.392 ;
     RECT  27.997 0.192 28.069 3.576 ;
     RECT  27.997 15.408 28.211 34.392 ;
     RECT  28.069 0.192 28.547 4.008 ;
     RECT  28.547 1.728 28.645 4.008 ;
     RECT  27.683 4.992 28.645 5.016 ;
     RECT  28.645 1.728 28.717 5.016 ;
     RECT  28.211 15.984 29.333 34.392 ;
     RECT  28.717 1.728 29.408 5.64 ;
     RECT  29.333 15.984 29.408 33.096 ;
     RECT  29.408 1.728 29.704 33.096 ;
     RECT  28.547 0.192 29.749 0.312 ;
     RECT  29.749 0.192 29.9 0.408 ;
     RECT  29.9 0.192 29.944 0.552 ;
     RECT  29.944 0.144 30.089 0.552 ;
     RECT  30.089 0.24 30.205 0.552 ;
     RECT  30.205 0.288 30.469 0.552 ;
     RECT  29.704 1.728 30.469 5.496 ;
     RECT  30.469 0.288 30.652 5.496 ;
     RECT  30.652 0.528 30.755 5.496 ;
     RECT  29.333 34.32 30.757 34.392 ;
     RECT  30.755 1.728 30.816 5.496 ;
     RECT  30.757 34.128 31.205 34.392 ;
     RECT  29.704 16.272 31.333 33.096 ;
     RECT  30.816 1.728 31.715 5.352 ;
     RECT  30.755 0.528 32.195 0.552 ;
     RECT  31.715 1.728 32.492 1.8 ;
     RECT  32.492 1.104 32.579 1.8 ;
     RECT  32.579 1.152 32.677 1.8 ;
     RECT  31.715 2.88 32.677 5.352 ;
     RECT  32.677 1.152 32.681 5.352 ;
     RECT  31.333 16.272 32.681 33.672 ;
     RECT  32.681 1.152 32.689 5.16 ;
     RECT  32.689 1.728 32.725 5.16 ;
     RECT  32.681 16.512 33.347 33.672 ;
     RECT  33.347 17.04 33.473 33.672 ;
     RECT  33.749 0.192 33.833 0.216 ;
     RECT  32.725 1.728 34.477 5.112 ;
     RECT  33.473 17.04 34.597 33.384 ;
     RECT  34.597 17.04 34.765 34.296 ;
     RECT  34.477 1.728 34.808 5.16 ;
     RECT  33.013 13.344 34.808 13.368 ;
     RECT  34.369 14.832 34.808 14.856 ;
     RECT  34.765 16.656 34.808 34.392 ;
     RECT  34.045 0.288 35.029 0.408 ;
     RECT  35.029 0.288 35.077 0.504 ;
     RECT  34.808 1.728 35.077 34.392 ;
     RECT  35.077 0.288 35.089 34.392 ;
     RECT  35.089 0.192 35.104 34.392 ;
     RECT  35.104 0.192 35.381 5.4 ;
     RECT  35.104 14.736 35.603 14.76 ;
     RECT  35.381 0.192 35.777 5.208 ;
     RECT  35.777 0.288 35.813 5.208 ;
     RECT  35.813 0.288 36.029 0.696 ;
     RECT  35.813 1.68 36.529 5.208 ;
     RECT  36.029 0.576 36.713 0.696 ;
     RECT  36.713 0.672 36.749 0.696 ;
     RECT  36.529 1.68 36.853 5.256 ;
     RECT  36.853 1.68 36.889 5.736 ;
     RECT  35.104 13.344 36.965 13.368 ;
     RECT  36.889 1.152 37.001 5.736 ;
     RECT  36.853 10.8 37.001 10.824 ;
     RECT  37.069 14.832 37.249 14.856 ;
     RECT  37.001 1.728 37.357 5.736 ;
     RECT  37.357 1.728 37.685 5.976 ;
     RECT  37.685 1.728 38.329 5.736 ;
     RECT  35.104 12.24 38.473 12.264 ;
     RECT  38.329 1.152 38.581 5.736 ;
     RECT  35.104 16.512 38.725 34.392 ;
     RECT  38.581 0.528 38.729 5.736 ;
     RECT  38.725 16.32 38.873 34.392 ;
     RECT  37.249 13.92 38.977 14.856 ;
     RECT  38.729 0.528 39.157 1.752 ;
     RECT  38.729 2.784 39.197 5.736 ;
     RECT  38.977 13.92 39.197 14.952 ;
     RECT  39.197 13.92 39.233 14.856 ;
     RECT  39.157 0.192 39.395 1.752 ;
     RECT  39.395 1.104 39.491 1.752 ;
     RECT  39.491 1.536 39.725 1.752 ;
     RECT  39.197 2.784 39.725 5.592 ;
     RECT  39.725 1.536 40.208 5.592 ;
     RECT  39.373 10.608 40.208 10.632 ;
     RECT  38.473 12.24 40.208 12.312 ;
     RECT  39.233 13.92 40.208 14.52 ;
     RECT  38.873 16.368 40.208 34.392 ;
     RECT  40.208 1.536 40.504 34.392 ;
     RECT  40.489 0.192 40.573 0.216 ;
     RECT  40.504 1.536 40.601 5.736 ;
     RECT  40.504 16.368 40.643 34.392 ;
     RECT  40.601 1.728 40.753 5.736 ;
     RECT  40.753 1.728 42.179 5.592 ;
     RECT  40.504 8.784 42.289 8.808 ;
     RECT  40.504 13.92 42.401 14.856 ;
     RECT  40.504 12.24 42.467 12.312 ;
     RECT  42.179 2.832 42.613 5.592 ;
     RECT  40.504 10.608 42.973 10.632 ;
     RECT  42.973 10.608 43.157 10.824 ;
     RECT  42.179 1.728 43.192 1.8 ;
     RECT  43.192 1.68 43.253 1.8 ;
     RECT  42.613 2.832 43.253 5.64 ;
     RECT  43.253 1.68 43.261 5.64 ;
     RECT  42.401 13.92 43.369 14.52 ;
     RECT  43.261 1.68 43.427 6.12 ;
     RECT  43.369 13.92 43.621 14.856 ;
     RECT  43.621 13.92 43.769 14.952 ;
     RECT  43.427 1.728 43.985 6.12 ;
     RECT  42.467 12.288 44.125 12.312 ;
     RECT  43.769 13.92 44.125 14.52 ;
     RECT  43.985 1.728 44.129 5.592 ;
     RECT  44.017 0.192 44.195 0.216 ;
     RECT  44.125 12.288 44.339 14.52 ;
     RECT  44.665 0.528 44.773 0.552 ;
     RECT  44.773 0.528 45.277 0.6 ;
     RECT  44.129 1.728 45.277 5.544 ;
     RECT  45.277 0.528 45.313 5.544 ;
     RECT  45.313 0.144 45.425 5.544 ;
     RECT  45.425 1.728 45.608 5.544 ;
     RECT  42.289 8.208 45.608 8.808 ;
     RECT  43.157 10.608 45.608 10.632 ;
     RECT  44.339 13.056 45.608 14.52 ;
     RECT  40.643 16.512 45.608 34.392 ;
     RECT  45.608 1.728 45.904 34.392 ;
     RECT  45.904 16.512 46.019 34.392 ;
     RECT  45.425 0.192 46.109 0.552 ;
     RECT  46.109 0.192 46.115 0.456 ;
     RECT  46.115 0.192 46.153 0.36 ;
     RECT  46.153 0.336 46.163 0.36 ;
     RECT  46.019 18.48 46.181 34.392 ;
     RECT  46.181 18.48 46.397 27.192 ;
     RECT  45.904 6.816 46.577 6.84 ;
     RECT  45.904 1.728 46.685 5.592 ;
     RECT  46.181 28.272 46.691 34.392 ;
     RECT  45.904 13.056 46.739 14.52 ;
     RECT  46.739 13.056 47.219 13.992 ;
     RECT  46.691 28.512 47.555 34.392 ;
     RECT  46.685 1.728 47.689 5.544 ;
     RECT  46.397 18.48 48.131 27.144 ;
     RECT  47.555 28.704 48.131 34.392 ;
     RECT  48.131 27.12 48.161 27.144 ;
     RECT  47.219 13.968 48.179 13.992 ;
     RECT  48.131 33.264 48.197 34.392 ;
     RECT  48.197 33.264 48.233 33.528 ;
     RECT  47.581 6.816 48.341 6.84 ;
     RECT  48.131 28.704 48.371 32.28 ;
     RECT  48.229 0.144 48.437 0.168 ;
     RECT  48.233 33.504 48.515 33.528 ;
     RECT  48.437 0.144 48.521 0.6 ;
     RECT  48.131 18.48 48.557 26.136 ;
     RECT  48.557 18.48 48.611 25.176 ;
     RECT  48.521 0.144 48.665 0.168 ;
     RECT  46.019 16.512 48.803 17.496 ;
     RECT  48.371 28.704 48.803 31.992 ;
     RECT  47.689 1.728 48.845 5.592 ;
     RECT  48.803 28.704 49.025 30.12 ;
     RECT  48.803 16.512 49.043 17.352 ;
     RECT  48.611 18.528 49.043 25.176 ;
     RECT  49.043 18.528 49.091 25.08 ;
     RECT  49.025 29.232 49.091 30.12 ;
     RECT  48.803 31.344 49.139 31.992 ;
     RECT  49.091 29.232 49.187 29.496 ;
     RECT  49.139 31.344 49.609 31.368 ;
     RECT  48.845 1.728 49.633 5.304 ;
     RECT  49.187 29.232 49.673 29.256 ;
     RECT  49.633 1.152 49.859 5.304 ;
     RECT  45.904 10.608 49.885 10.632 ;
     RECT  49.859 1.728 50.965 5.304 ;
     RECT  50.965 1.728 51.008 5.544 ;
     RECT  45.904 8.208 51.008 9.384 ;
     RECT  49.885 10.608 51.008 10.776 ;
     RECT  48.337 13.344 51.008 13.368 ;
     RECT  49.043 17.328 51.008 17.352 ;
     RECT  49.091 18.672 51.008 25.08 ;
     RECT  51.008 1.728 51.112 32.412 ;
     RECT  51.112 1.728 51.304 32.142 ;
     RECT  50.533 0.288 51.325 0.6 ;
     RECT  51.304 1.728 51.325 5.736 ;
     RECT  51.325 0.288 51.349 5.736 ;
     RECT  51.349 0.192 51.491 5.736 ;
     RECT  51.304 8.208 51.635 9.384 ;
     RECT  51.491 0.192 51.683 0.6 ;
     RECT  51.304 18.672 51.761 24.648 ;
     RECT  51.304 30.816 52.085 30.84 ;
     RECT  51.761 21.504 52.265 24.648 ;
     RECT  51.491 1.728 52.589 5.736 ;
     RECT  51.761 18.672 52.589 20.328 ;
     RECT  51.635 8.208 52.739 8.808 ;
     RECT  51.304 10.608 53.315 10.632 ;
     RECT  51.683 0.192 53.413 0.216 ;
     RECT  52.589 1.728 53.885 5.16 ;
     RECT  52.265 21.696 53.885 24.648 ;
     RECT  53.885 1.728 53.989 2.856 ;
     RECT  53.413 0.144 54.025 0.216 ;
     RECT  53.989 1.632 54.025 2.856 ;
     RECT  54.025 0.144 54.065 2.856 ;
     RECT  51.304 13.344 54.227 13.368 ;
     RECT  54.065 0.576 54.275 2.856 ;
     RECT  54.275 1.632 54.371 2.856 ;
     RECT  52.589 18.672 54.389 20.184 ;
     RECT  53.885 4.128 54.421 5.16 ;
     RECT  54.421 4.128 54.569 5.304 ;
     RECT  53.885 21.936 54.677 24.648 ;
     RECT  51.304 17.328 54.709 17.352 ;
     RECT  54.709 17.184 54.749 17.352 ;
     RECT  54.677 23.424 54.749 24.648 ;
     RECT  54.275 0.576 54.851 0.6 ;
     RECT  54.371 1.728 55.105 2.856 ;
     RECT  54.569 4.128 55.105 5.256 ;
     RECT  55.105 1.728 55.537 5.256 ;
     RECT  55.537 1.728 56.408 5.592 ;
     RECT  52.739 8.208 56.408 8.232 ;
     RECT  54.749 17.184 56.408 17.208 ;
     RECT  54.389 18.672 56.408 18.696 ;
     RECT  54.389 19.68 56.408 20.184 ;
     RECT  54.677 21.936 56.408 22.296 ;
     RECT  54.749 23.568 56.408 24.648 ;
     RECT  56.408 1.728 56.512 32.412 ;
     RECT  56.512 1.728 56.704 32.142 ;
     RECT  56.629 0.288 56.725 0.312 ;
     RECT  56.725 0.288 56.819 0.408 ;
     RECT  56.819 0.384 56.915 0.408 ;
     RECT  56.704 8.208 57.299 8.232 ;
     RECT  57.193 0.528 57.443 0.552 ;
     RECT  56.704 1.728 57.589 5.592 ;
     RECT  56.704 21.936 57.683 22.296 ;
     RECT  57.589 1.152 57.805 5.592 ;
     RECT  57.805 1.152 58.097 6.264 ;
     RECT  58.097 1.728 58.205 6.264 ;
     RECT  56.704 17.184 58.403 17.208 ;
     RECT  56.704 24.624 58.457 24.648 ;
     RECT  56.704 23.568 58.565 23.64 ;
     RECT  56.704 20.16 58.601 20.184 ;
     RECT  58.205 6.24 58.643 6.264 ;
     RECT  58.205 1.728 58.781 5.256 ;
     RECT  58.781 1.728 59.753 5.16 ;
     RECT  59.753 4.464 60.179 5.16 ;
     RECT  60.179 4.464 60.515 4.584 ;
     RECT  56.704 18.672 60.755 18.696 ;
     RECT  60.515 4.464 60.833 4.488 ;
     RECT  59.753 1.728 60.941 3.48 ;
     RECT  61.045 0.576 61.129 0.6 ;
     RECT  60.941 1.776 61.229 3.48 ;
     RECT  61.229 1.824 61.481 3.48 ;
     RECT  61.481 1.92 61.517 3.48 ;
     RECT  61.517 2.148 61.621 3.48 ;
     RECT  61.621 2.148 61.808 4.248 ;
     RECT  60.685 17.616 61.808 17.64 ;
     RECT  57.683 21.936 61.808 21.96 ;
     RECT  58.565 23.568 61.808 23.592 ;
     RECT  61.808 2.148 61.912 32.412 ;
     RECT  61.912 2.304 62.104 32.142 ;
     RECT  62.104 2.304 62.165 4.248 ;
     RECT  62.165 2.304 62.489 3.528 ;
     RECT  62.489 2.496 62.813 3.528 ;
     RECT  62.813 2.496 62.957 2.904 ;
     RECT  62.957 2.496 63.173 2.856 ;
     RECT  63.173 2.832 63.389 2.856 ;
     RECT  62.104 23.568 67.208 23.592 ;
     RECT  67.208 2.148 67.312 32.412 ;
     RECT  67.312 2.418 67.504 32.142 ;
     RECT  67.504 23.568 68.753 23.592 ;
     RECT  71.233 20.736 71.269 21.336 ;
     RECT  71.269 20.736 71.809 21.48 ;
     RECT  71.809 20.736 71.845 21.624 ;
     RECT  71.845 20.736 73.26 21.768 ;
    LAYER M5 ;
     RECT  12 0.144 61.08 0.611 ;
     RECT  12 0.611 60.984 1.763 ;
     RECT  12.192 1.763 60.984 2.137 ;
     RECT  2.4 2.137 2.52 2.151 ;
     RECT  7.8 2.137 7.92 2.151 ;
     RECT  12.192 2.137 61.92 2.151 ;
     RECT  67.2 2.137 67.32 2.151 ;
     RECT  12.192 2.151 62.112 2.821 ;
     RECT  11.52 2.821 62.112 3.443 ;
     RECT  11.52 3.443 55.128 3.683 ;
     RECT  56.256 3.443 62.112 4.115 ;
     RECT  12.96 3.683 55.128 4.499 ;
     RECT  12.96 4.499 49.608 4.595 ;
     RECT  56.256 4.115 59.16 4.595 ;
     RECT  12.96 4.595 37.08 4.643 ;
     RECT  39.936 4.595 49.608 4.739 ;
     RECT  38.112 4.595 38.472 4.883 ;
     RECT  50.688 4.499 55.128 4.885 ;
     RECT  56.256 4.595 58.632 4.885 ;
     RECT  50.688 4.885 58.632 4.931 ;
     RECT  42.144 4.739 43.032 5.027 ;
     RECT  55.776 4.931 58.632 5.027 ;
     RECT  20.256 4.643 37.08 5.075 ;
     RECT  12.96 4.643 18.912 5.123 ;
     RECT  39.936 4.739 40.824 5.123 ;
     RECT  44.112 4.739 49.608 5.123 ;
     RECT  12.96 5.123 14.472 5.171 ;
     RECT  20.256 5.075 36.888 5.171 ;
     RECT  50.688 4.931 54.456 5.171 ;
     RECT  60.144 4.115 62.112 5.171 ;
     RECT  15.888 5.123 18.912 5.267 ;
     RECT  39.936 5.123 40.728 5.315 ;
     RECT  51 5.171 54.456 5.315 ;
     RECT  38.208 4.883 38.472 5.411 ;
     RECT  20.784 5.171 31.56 5.747 ;
     RECT  40.2 5.315 40.728 5.747 ;
     RECT  56.4 5.027 58.632 6.275 ;
     RECT  51 5.315 54.216 9.395 ;
     RECT  52.512 9.395 54.216 10.643 ;
     RECT  42.144 5.027 42.456 12.275 ;
     RECT  44.112 5.123 48.744 12.323 ;
     RECT  45.264 12.323 48.744 13.091 ;
     RECT  54.192 10.643 54.216 13.379 ;
     RECT  45.264 13.091 47.016 13.955 ;
     RECT  48.144 13.091 48.744 14.003 ;
     RECT  45.264 13.955 46.728 14.531 ;
     RECT  32.784 5.171 36.888 14.771 ;
     RECT  15.936 5.267 18.912 16.309 ;
     RECT  40.2 5.747 40.512 16.357 ;
     RECT  40.2 16.357 40.632 16.453 ;
     RECT  20.784 5.747 25.08 16.501 ;
     RECT  32.784 14.771 35.112 16.501 ;
     RECT  36.144 14.771 36.888 16.501 ;
     RECT  48.72 14.003 48.744 16.501 ;
     RECT  26.64 5.747 31.56 16.645 ;
     RECT  32.784 16.501 36.888 16.645 ;
     RECT  39.648 16.453 40.632 16.645 ;
     RECT  48.72 16.501 49.032 16.789 ;
     RECT  39.648 16.645 40.872 16.981 ;
     RECT  26.64 16.645 36.888 17.077 ;
     RECT  39.552 16.981 40.872 17.077 ;
     RECT  42.144 12.275 42.168 17.077 ;
     RECT  44.112 12.323 44.136 17.077 ;
     RECT  45.264 14.531 45.912 17.077 ;
     RECT  48.528 16.789 49.032 17.125 ;
     RECT  48.288 17.125 49.032 17.171 ;
     RECT  12.96 5.171 13.992 17.173 ;
     RECT  56.4 6.275 58.392 17.219 ;
     RECT  39.552 17.077 42.696 17.267 ;
     RECT  12.96 17.173 14.808 17.413 ;
     RECT  15.936 16.309 19.56 17.413 ;
     RECT  42.144 17.267 42.168 17.507 ;
     RECT  44.112 17.077 45.912 17.555 ;
     RECT  44.112 17.555 44.136 17.603 ;
     RECT  39.552 17.267 40.872 17.651 ;
     RECT  60.72 5.171 62.112 17.651 ;
     RECT  38.448 5.411 38.472 17.845 ;
     RECT  39.552 17.651 40.632 17.845 ;
     RECT  11.52 3.683 11.544 17.987 ;
     RECT  45.264 17.555 45.912 18.181 ;
     RECT  38.448 17.845 40.632 18.229 ;
     RECT  20.784 16.501 25.128 18.275 ;
     RECT  48.288 17.171 48.936 18.517 ;
     RECT  26.64 17.077 36.984 18.661 ;
     RECT  38.304 18.229 40.632 18.661 ;
     RECT  60.72 17.651 60.744 18.707 ;
     RECT  47.088 17.173 47.112 18.709 ;
     RECT  26.64 18.661 40.632 18.755 ;
     RECT  34.56 18.755 40.632 18.757 ;
     RECT  41.616 18.565 41.64 18.757 ;
     RECT  48.288 18.517 49.08 18.757 ;
     RECT  20.784 18.275 25.08 18.851 ;
     RECT  26.64 18.755 33.576 18.851 ;
     RECT  45.264 18.181 46.008 19.045 ;
     RECT  47.04 18.709 47.112 19.045 ;
     RECT  45.264 19.045 47.112 19.141 ;
     RECT  48.288 18.757 49.128 19.141 ;
     RECT  52.512 10.643 52.536 19.189 ;
     RECT  34.56 18.757 41.64 19.235 ;
     RECT  44.064 18.277 44.088 19.333 ;
     RECT  52.464 19.189 52.536 19.667 ;
     RECT  41.616 19.235 41.64 19.717 ;
     RECT  12.96 17.413 19.56 19.909 ;
     RECT  26.736 18.851 33.576 19.957 ;
     RECT  34.56 19.235 40.632 19.957 ;
     RECT  41.616 19.717 42.168 19.957 ;
     RECT  43.44 19.333 44.088 19.957 ;
     RECT  0.24 17.269 0.264 20.147 ;
     RECT  12.96 19.909 20.52 20.339 ;
     RECT  52.464 19.667 52.488 20.339 ;
     RECT  41.616 19.957 44.088 20.387 ;
     RECT  45.264 19.141 49.128 20.437 ;
     RECT  26.736 19.957 40.632 20.485 ;
     RECT  41.616 20.387 41.88 20.485 ;
     RECT  45.072 20.437 49.128 20.579 ;
     RECT  26.736 20.485 41.88 20.627 ;
     RECT  21.744 18.851 25.08 20.675 ;
     RECT  43.104 20.387 44.088 20.773 ;
     RECT  45.072 20.579 49.08 20.773 ;
     RECT  32.496 20.627 41.88 20.867 ;
     RECT  22.464 20.675 25.08 21.061 ;
     RECT  26.736 20.627 31.128 21.061 ;
     RECT  32.64 20.867 41.88 21.203 ;
     RECT  43.104 20.773 49.08 22.021 ;
     RECT  51 9.395 51.312 22.021 ;
     RECT  22.464 21.061 31.128 22.165 ;
     RECT  32.64 21.203 41.112 22.165 ;
     RECT  56.4 17.219 57.672 22.307 ;
     RECT  43.104 22.021 49.128 22.549 ;
     RECT  13.2 20.339 20.52 22.741 ;
     RECT  22.464 22.165 41.112 22.933 ;
     RECT  22.464 22.933 41.16 23.173 ;
     RECT  13.2 22.741 21.192 23.365 ;
     RECT  22.464 23.173 41.88 23.365 ;
     RECT  54.576 22.741 54.6 23.603 ;
     RECT  50.88 22.021 51.312 23.843 ;
     RECT  13.2 23.365 41.88 24.421 ;
     RECT  13.2 24.421 42.072 24.469 ;
     RECT  43.104 22.549 49.176 24.469 ;
     RECT  13.2 24.469 49.176 25.045 ;
     RECT  13.2 25.045 49.56 30.083 ;
     RECT  14.736 30.083 49.56 31.379 ;
     RECT  14.736 31.379 49.128 31.811 ;
     RECT  17.856 31.811 49.128 32.003 ;
     RECT  17.856 32.003 48.504 32.291 ;
     RECT  2.4 2.151 2.712 32.409 ;
     RECT  7.8 2.151 8.112 32.409 ;
     RECT  13.2 30.083 13.512 32.409 ;
     RECT  51 23.843 51.312 32.409 ;
     RECT  56.4 22.307 56.712 32.409 ;
     RECT  61.8 17.651 62.112 32.409 ;
     RECT  67.2 2.151 67.512 32.409 ;
     RECT  2.4 32.409 2.52 32.423 ;
     RECT  7.8 32.409 7.92 32.423 ;
     RECT  13.2 32.409 13.32 32.423 ;
     RECT  17.856 32.291 44.424 32.423 ;
     RECT  45.6 32.291 48.504 32.423 ;
     RECT  51 32.409 51.12 32.423 ;
     RECT  56.4 32.409 56.52 32.423 ;
     RECT  61.8 32.409 61.92 32.423 ;
     RECT  67.2 32.409 67.32 32.423 ;
     RECT  14.736 31.811 16.872 32.531 ;
     RECT  14.736 32.531 16.536 33.107 ;
     RECT  15.696 33.107 16.536 33.347 ;
     RECT  15.696 33.347 16.488 33.443 ;
     RECT  46.08 32.423 48.504 33.443 ;
     RECT  17.856 32.423 18.168 33.491 ;
     RECT  46.8 33.443 48.504 33.539 ;
     RECT  17.856 33.491 18.12 33.587 ;
     RECT  19.584 32.423 44.424 33.637 ;
     RECT  46.8 33.539 48.072 34.067 ;
     RECT  47.904 34.067 48.072 34.163 ;
     RECT  46.8 34.067 46.92 34.211 ;
     RECT  15.696 33.443 15.96 34.259 ;
     RECT  46.8 34.211 46.824 34.259 ;
     RECT  18.096 33.587 18.12 34.307 ;
     RECT  47.952 34.163 48.072 34.307 ;
     RECT  19.584 33.637 44.52 34.355 ;
     RECT  48.048 34.307 48.072 34.355 ;
     RECT  20.016 34.355 44.52 34.384 ;
     RECT  15.936 34.259 15.96 34.403 ;
     RECT  60.984 0.611 61.08 2.137 ;
     RECT  12 1.763 12.192 2.821 ;
     RECT  55.128 3.443 56.256 4.885 ;
     RECT  11.544 3.683 12.96 17.987 ;
     RECT  59.16 4.115 60.144 4.595 ;
     RECT  49.608 4.499 50.688 5.123 ;
     RECT  37.08 4.595 38.112 4.883 ;
     RECT  38.472 4.595 39.936 5.315 ;
     RECT  58.632 4.595 60.144 5.171 ;
     RECT  18.912 4.643 20.256 5.171 ;
     RECT  40.824 4.739 42.144 5.123 ;
     RECT  43.032 4.739 44.112 5.027 ;
     RECT  37.08 4.883 38.208 5.075 ;
     RECT  54.456 4.931 55.776 5.027 ;
     RECT  36.888 5.075 38.208 5.411 ;
     RECT  14.472 5.123 15.888 5.171 ;
     RECT  40.728 5.123 42.144 5.747 ;
     RECT  31.56 5.171 32.784 16.645 ;
     RECT  51.312 9.395 52.512 19.189 ;
     RECT  44.136 12.323 45.264 17.077 ;
     RECT  47.016 13.091 48.144 13.955 ;
     RECT  46.728 13.955 48.144 14.003 ;
     RECT  35.112 14.771 36.144 16.501 ;
     RECT  19.56 16.309 20.784 18.851 ;
     RECT  40.632 16.357 42.144 16.645 ;
     RECT  38.472 16.453 39.648 16.981 ;
     RECT  25.128 16.501 26.64 18.275 ;
     RECT  40.872 16.645 42.144 17.077 ;
     RECT  38.472 16.981 39.552 17.845 ;
     RECT  36.984 17.077 38.448 18.229 ;
     RECT  42.696 17.077 44.112 17.267 ;
     RECT  48.936 17.171 49.032 18.517 ;
     RECT  14.808 17.173 15.936 17.413 ;
     RECT  45.912 17.173 47.088 18.181 ;
     RECT  47.112 17.173 48.288 19.141 ;
     RECT  40.872 17.267 42.144 17.507 ;
     RECT  44.064 17.267 44.112 17.603 ;
     RECT  40.872 17.507 41.64 17.651 ;
     RECT  44.136 17.555 45.264 17.603 ;
     RECT  44.064 17.603 45.264 18.277 ;
     RECT  40.632 17.651 41.64 18.565 ;
     RECT  60.744 17.651 61.8 18.707 ;
     RECT  46.008 18.181 47.088 18.709 ;
     RECT  36.984 18.229 38.304 18.661 ;
     RECT  44.088 18.277 45.264 20.437 ;
     RECT  40.632 18.565 41.616 18.757 ;
     RECT  46.008 18.709 47.04 19.045 ;
     RECT  33.576 18.755 34.56 19.957 ;
     RECT  19.56 18.851 21.744 19.909 ;
     RECT  51.312 19.189 52.464 20.339 ;
     RECT  40.632 19.235 41.616 20.485 ;
     RECT  42.168 19.717 43.44 19.957 ;
     RECT  20.52 19.909 21.744 20.675 ;
     RECT  41.88 20.387 43.104 21.203 ;
     RECT  44.088 20.437 45.072 20.773 ;
     RECT  49.08 20.579 49.128 22.021 ;
     RECT  31.128 20.627 32.496 20.867 ;
     RECT  31.128 20.867 32.64 22.165 ;
     RECT  21.192 22.741 22.464 23.365 ;
     RECT  41.88 23.173 43.104 24.421 ;
     RECT  50.88 23.843 51 25.045 ;
     RECT  42.072 24.421 43.104 24.469 ;
     RECT  49.56 25.045 51 31.379 ;
     RECT  13.512 30.083 14.736 32.409 ;
     RECT  16.872 31.811 17.856 32.531 ;
     RECT  44.424 32.291 45.6 32.423 ;
     RECT  13.32 32.409 14.736 32.423 ;
     RECT  18.168 32.423 19.584 33.491 ;
     RECT  44.424 32.423 44.52 33.637 ;
     RECT  16.536 32.531 17.856 33.347 ;
     RECT  16.488 33.347 17.856 33.443 ;
     RECT  18.12 33.491 19.584 34.307 ;
     RECT  46.92 34.067 47.904 34.163 ;
     RECT  46.92 34.163 47.952 34.211 ;
     RECT  46.824 34.211 47.952 34.259 ;
  END
END ot_s81_pq_ix_ba_native
END LIBRARY
